VERSION 5.8 ;
BUSBITCHARS "[]" ;
DIVIDERCHAR "/" ;
UNITS
    DATABASE MICRONS 1000 ;
END UNITS

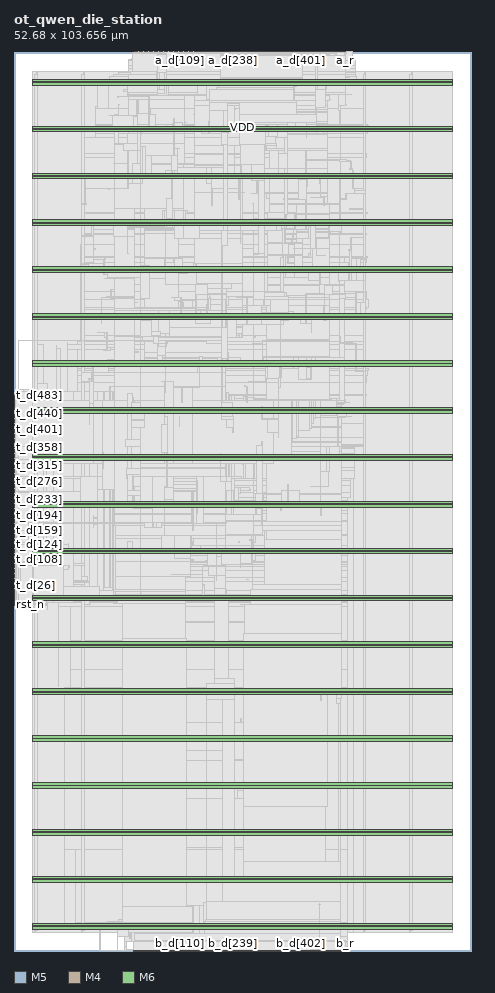
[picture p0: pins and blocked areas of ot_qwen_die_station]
MACRO ot_qwen_die_station
  FOREIGN ot_qwen_die_station 0 0 ;
  CLASS BLOCK ;
  SIZE 52.68 BY 103.656 ;
  PIN a_d[0]
    DIRECTION INPUT ;
    USE SIGNAL ;
    PORT
      LAYER M5 ;
        RECT  13.824 103.572 13.848 103.656 ;
    END
  END a_d[0]
  PIN a_d[100]
    DIRECTION INPUT ;
    USE SIGNAL ;
    PORT
      LAYER M5 ;
        RECT  18.624 103.572 18.648 103.656 ;
    END
  END a_d[100]
  PIN a_d[101]
    DIRECTION INPUT ;
    USE SIGNAL ;
    PORT
      LAYER M5 ;
        RECT  18.672 103.572 18.696 103.656 ;
    END
  END a_d[101]
  PIN a_d[102]
    DIRECTION INPUT ;
    USE SIGNAL ;
    PORT
      LAYER M5 ;
        RECT  18.72 103.572 18.744 103.656 ;
    END
  END a_d[102]
  PIN a_d[103]
    DIRECTION INPUT ;
    USE SIGNAL ;
    PORT
      LAYER M5 ;
        RECT  18.768 103.572 18.792 103.656 ;
    END
  END a_d[103]
  PIN a_d[104]
    DIRECTION INPUT ;
    USE SIGNAL ;
    PORT
      LAYER M5 ;
        RECT  18.816 103.572 18.84 103.656 ;
    END
  END a_d[104]
  PIN a_d[105]
    DIRECTION INPUT ;
    USE SIGNAL ;
    PORT
      LAYER M5 ;
        RECT  18.864 103.572 18.888 103.656 ;
    END
  END a_d[105]
  PIN a_d[106]
    DIRECTION INPUT ;
    USE SIGNAL ;
    PORT
      LAYER M5 ;
        RECT  18.912 103.572 18.936 103.656 ;
    END
  END a_d[106]
  PIN a_d[107]
    DIRECTION INPUT ;
    USE SIGNAL ;
    PORT
      LAYER M5 ;
        RECT  18.96 103.572 18.984 103.656 ;
    END
  END a_d[107]
  PIN a_d[108]
    DIRECTION INPUT ;
    USE SIGNAL ;
    PORT
      LAYER M5 ;
        RECT  19.008 103.572 19.032 103.656 ;
    END
  END a_d[108]
  PIN a_d[109]
    DIRECTION INPUT ;
    USE SIGNAL ;
    PORT
      LAYER M5 ;
        RECT  19.056 103.572 19.08 103.656 ;
    END
  END a_d[109]
  PIN a_d[10]
    DIRECTION INPUT ;
    USE SIGNAL ;
    PORT
      LAYER M5 ;
        RECT  14.304 103.572 14.328 103.656 ;
    END
  END a_d[10]
  PIN a_d[110]
    DIRECTION INPUT ;
    USE SIGNAL ;
    PORT
      LAYER M5 ;
        RECT  19.104 103.572 19.128 103.656 ;
    END
  END a_d[110]
  PIN a_d[111]
    DIRECTION INPUT ;
    USE SIGNAL ;
    PORT
      LAYER M5 ;
        RECT  19.152 103.572 19.176 103.656 ;
    END
  END a_d[111]
  PIN a_d[112]
    DIRECTION INPUT ;
    USE SIGNAL ;
    PORT
      LAYER M5 ;
        RECT  19.2 103.572 19.224 103.656 ;
    END
  END a_d[112]
  PIN a_d[113]
    DIRECTION INPUT ;
    USE SIGNAL ;
    PORT
      LAYER M5 ;
        RECT  19.248 103.572 19.272 103.656 ;
    END
  END a_d[113]
  PIN a_d[114]
    DIRECTION INPUT ;
    USE SIGNAL ;
    PORT
      LAYER M5 ;
        RECT  19.296 103.572 19.32 103.656 ;
    END
  END a_d[114]
  PIN a_d[115]
    DIRECTION INPUT ;
    USE SIGNAL ;
    PORT
      LAYER M5 ;
        RECT  19.344 103.572 19.368 103.656 ;
    END
  END a_d[115]
  PIN a_d[116]
    DIRECTION INPUT ;
    USE SIGNAL ;
    PORT
      LAYER M5 ;
        RECT  19.392 103.572 19.416 103.656 ;
    END
  END a_d[116]
  PIN a_d[117]
    DIRECTION INPUT ;
    USE SIGNAL ;
    PORT
      LAYER M5 ;
        RECT  19.44 103.572 19.464 103.656 ;
    END
  END a_d[117]
  PIN a_d[118]
    DIRECTION INPUT ;
    USE SIGNAL ;
    PORT
      LAYER M5 ;
        RECT  19.488 103.572 19.512 103.656 ;
    END
  END a_d[118]
  PIN a_d[119]
    DIRECTION INPUT ;
    USE SIGNAL ;
    PORT
      LAYER M5 ;
        RECT  19.536 103.572 19.56 103.656 ;
    END
  END a_d[119]
  PIN a_d[11]
    DIRECTION INPUT ;
    USE SIGNAL ;
    PORT
      LAYER M5 ;
        RECT  14.352 103.572 14.376 103.656 ;
    END
  END a_d[11]
  PIN a_d[120]
    DIRECTION INPUT ;
    USE SIGNAL ;
    PORT
      LAYER M5 ;
        RECT  19.584 103.572 19.608 103.656 ;
    END
  END a_d[120]
  PIN a_d[121]
    DIRECTION INPUT ;
    USE SIGNAL ;
    PORT
      LAYER M5 ;
        RECT  19.632 103.572 19.656 103.656 ;
    END
  END a_d[121]
  PIN a_d[122]
    DIRECTION INPUT ;
    USE SIGNAL ;
    PORT
      LAYER M5 ;
        RECT  19.68 103.572 19.704 103.656 ;
    END
  END a_d[122]
  PIN a_d[123]
    DIRECTION INPUT ;
    USE SIGNAL ;
    PORT
      LAYER M5 ;
        RECT  19.728 103.572 19.752 103.656 ;
    END
  END a_d[123]
  PIN a_d[124]
    DIRECTION INPUT ;
    USE SIGNAL ;
    PORT
      LAYER M5 ;
        RECT  19.776 103.572 19.8 103.656 ;
    END
  END a_d[124]
  PIN a_d[125]
    DIRECTION INPUT ;
    USE SIGNAL ;
    PORT
      LAYER M5 ;
        RECT  19.824 103.572 19.848 103.656 ;
    END
  END a_d[125]
  PIN a_d[126]
    DIRECTION INPUT ;
    USE SIGNAL ;
    PORT
      LAYER M5 ;
        RECT  19.872 103.572 19.896 103.656 ;
    END
  END a_d[126]
  PIN a_d[127]
    DIRECTION INPUT ;
    USE SIGNAL ;
    PORT
      LAYER M5 ;
        RECT  19.92 103.572 19.944 103.656 ;
    END
  END a_d[127]
  PIN a_d[128]
    DIRECTION INPUT ;
    USE SIGNAL ;
    PORT
      LAYER M5 ;
        RECT  19.968 103.572 19.992 103.656 ;
    END
  END a_d[128]
  PIN a_d[129]
    DIRECTION INPUT ;
    USE SIGNAL ;
    PORT
      LAYER M5 ;
        RECT  20.016 103.572 20.04 103.656 ;
    END
  END a_d[129]
  PIN a_d[12]
    DIRECTION INPUT ;
    USE SIGNAL ;
    PORT
      LAYER M5 ;
        RECT  14.4 103.572 14.424 103.656 ;
    END
  END a_d[12]
  PIN a_d[130]
    DIRECTION INPUT ;
    USE SIGNAL ;
    PORT
      LAYER M5 ;
        RECT  20.064 103.572 20.088 103.656 ;
    END
  END a_d[130]
  PIN a_d[131]
    DIRECTION INPUT ;
    USE SIGNAL ;
    PORT
      LAYER M5 ;
        RECT  20.112 103.572 20.136 103.656 ;
    END
  END a_d[131]
  PIN a_d[132]
    DIRECTION INPUT ;
    USE SIGNAL ;
    PORT
      LAYER M5 ;
        RECT  20.16 103.572 20.184 103.656 ;
    END
  END a_d[132]
  PIN a_d[133]
    DIRECTION INPUT ;
    USE SIGNAL ;
    PORT
      LAYER M5 ;
        RECT  20.208 103.572 20.232 103.656 ;
    END
  END a_d[133]
  PIN a_d[134]
    DIRECTION INPUT ;
    USE SIGNAL ;
    PORT
      LAYER M5 ;
        RECT  20.256 103.572 20.28 103.656 ;
    END
  END a_d[134]
  PIN a_d[135]
    DIRECTION INPUT ;
    USE SIGNAL ;
    PORT
      LAYER M5 ;
        RECT  20.304 103.572 20.328 103.656 ;
    END
  END a_d[135]
  PIN a_d[136]
    DIRECTION INPUT ;
    USE SIGNAL ;
    PORT
      LAYER M5 ;
        RECT  20.352 103.572 20.376 103.656 ;
    END
  END a_d[136]
  PIN a_d[137]
    DIRECTION INPUT ;
    USE SIGNAL ;
    PORT
      LAYER M5 ;
        RECT  20.4 103.572 20.424 103.656 ;
    END
  END a_d[137]
  PIN a_d[138]
    DIRECTION INPUT ;
    USE SIGNAL ;
    PORT
      LAYER M5 ;
        RECT  20.448 103.572 20.472 103.656 ;
    END
  END a_d[138]
  PIN a_d[139]
    DIRECTION INPUT ;
    USE SIGNAL ;
    PORT
      LAYER M5 ;
        RECT  20.496 103.572 20.52 103.656 ;
    END
  END a_d[139]
  PIN a_d[13]
    DIRECTION INPUT ;
    USE SIGNAL ;
    PORT
      LAYER M5 ;
        RECT  14.448 103.572 14.472 103.656 ;
    END
  END a_d[13]
  PIN a_d[140]
    DIRECTION INPUT ;
    USE SIGNAL ;
    PORT
      LAYER M5 ;
        RECT  20.544 103.572 20.568 103.656 ;
    END
  END a_d[140]
  PIN a_d[141]
    DIRECTION INPUT ;
    USE SIGNAL ;
    PORT
      LAYER M5 ;
        RECT  20.592 103.572 20.616 103.656 ;
    END
  END a_d[141]
  PIN a_d[142]
    DIRECTION INPUT ;
    USE SIGNAL ;
    PORT
      LAYER M5 ;
        RECT  20.64 103.572 20.664 103.656 ;
    END
  END a_d[142]
  PIN a_d[143]
    DIRECTION INPUT ;
    USE SIGNAL ;
    PORT
      LAYER M5 ;
        RECT  20.688 103.572 20.712 103.656 ;
    END
  END a_d[143]
  PIN a_d[144]
    DIRECTION INPUT ;
    USE SIGNAL ;
    PORT
      LAYER M5 ;
        RECT  20.736 103.572 20.76 103.656 ;
    END
  END a_d[144]
  PIN a_d[145]
    DIRECTION INPUT ;
    USE SIGNAL ;
    PORT
      LAYER M5 ;
        RECT  20.784 103.572 20.808 103.656 ;
    END
  END a_d[145]
  PIN a_d[146]
    DIRECTION INPUT ;
    USE SIGNAL ;
    PORT
      LAYER M5 ;
        RECT  20.832 103.572 20.856 103.656 ;
    END
  END a_d[146]
  PIN a_d[147]
    DIRECTION INPUT ;
    USE SIGNAL ;
    PORT
      LAYER M5 ;
        RECT  20.88 103.572 20.904 103.656 ;
    END
  END a_d[147]
  PIN a_d[148]
    DIRECTION INPUT ;
    USE SIGNAL ;
    PORT
      LAYER M5 ;
        RECT  20.928 103.572 20.952 103.656 ;
    END
  END a_d[148]
  PIN a_d[149]
    DIRECTION INPUT ;
    USE SIGNAL ;
    PORT
      LAYER M5 ;
        RECT  20.976 103.572 21 103.656 ;
    END
  END a_d[149]
  PIN a_d[14]
    DIRECTION INPUT ;
    USE SIGNAL ;
    PORT
      LAYER M5 ;
        RECT  14.496 103.572 14.52 103.656 ;
    END
  END a_d[14]
  PIN a_d[150]
    DIRECTION INPUT ;
    USE SIGNAL ;
    PORT
      LAYER M5 ;
        RECT  21.024 103.572 21.048 103.656 ;
    END
  END a_d[150]
  PIN a_d[151]
    DIRECTION INPUT ;
    USE SIGNAL ;
    PORT
      LAYER M5 ;
        RECT  21.072 103.572 21.096 103.656 ;
    END
  END a_d[151]
  PIN a_d[152]
    DIRECTION INPUT ;
    USE SIGNAL ;
    PORT
      LAYER M5 ;
        RECT  21.12 103.572 21.144 103.656 ;
    END
  END a_d[152]
  PIN a_d[153]
    DIRECTION INPUT ;
    USE SIGNAL ;
    PORT
      LAYER M5 ;
        RECT  21.168 103.572 21.192 103.656 ;
    END
  END a_d[153]
  PIN a_d[154]
    DIRECTION INPUT ;
    USE SIGNAL ;
    PORT
      LAYER M5 ;
        RECT  21.216 103.572 21.24 103.656 ;
    END
  END a_d[154]
  PIN a_d[155]
    DIRECTION INPUT ;
    USE SIGNAL ;
    PORT
      LAYER M5 ;
        RECT  21.264 103.572 21.288 103.656 ;
    END
  END a_d[155]
  PIN a_d[156]
    DIRECTION INPUT ;
    USE SIGNAL ;
    PORT
      LAYER M5 ;
        RECT  21.312 103.572 21.336 103.656 ;
    END
  END a_d[156]
  PIN a_d[157]
    DIRECTION INPUT ;
    USE SIGNAL ;
    PORT
      LAYER M5 ;
        RECT  21.36 103.572 21.384 103.656 ;
    END
  END a_d[157]
  PIN a_d[158]
    DIRECTION INPUT ;
    USE SIGNAL ;
    PORT
      LAYER M5 ;
        RECT  21.408 103.572 21.432 103.656 ;
    END
  END a_d[158]
  PIN a_d[159]
    DIRECTION INPUT ;
    USE SIGNAL ;
    PORT
      LAYER M5 ;
        RECT  21.456 103.572 21.48 103.656 ;
    END
  END a_d[159]
  PIN a_d[15]
    DIRECTION INPUT ;
    USE SIGNAL ;
    PORT
      LAYER M5 ;
        RECT  14.544 103.572 14.568 103.656 ;
    END
  END a_d[15]
  PIN a_d[160]
    DIRECTION INPUT ;
    USE SIGNAL ;
    PORT
      LAYER M5 ;
        RECT  21.504 103.572 21.528 103.656 ;
    END
  END a_d[160]
  PIN a_d[161]
    DIRECTION INPUT ;
    USE SIGNAL ;
    PORT
      LAYER M5 ;
        RECT  21.552 103.572 21.576 103.656 ;
    END
  END a_d[161]
  PIN a_d[162]
    DIRECTION INPUT ;
    USE SIGNAL ;
    PORT
      LAYER M5 ;
        RECT  21.6 103.572 21.624 103.656 ;
    END
  END a_d[162]
  PIN a_d[163]
    DIRECTION INPUT ;
    USE SIGNAL ;
    PORT
      LAYER M5 ;
        RECT  21.648 103.572 21.672 103.656 ;
    END
  END a_d[163]
  PIN a_d[164]
    DIRECTION INPUT ;
    USE SIGNAL ;
    PORT
      LAYER M5 ;
        RECT  21.696 103.572 21.72 103.656 ;
    END
  END a_d[164]
  PIN a_d[165]
    DIRECTION INPUT ;
    USE SIGNAL ;
    PORT
      LAYER M5 ;
        RECT  21.744 103.572 21.768 103.656 ;
    END
  END a_d[165]
  PIN a_d[166]
    DIRECTION INPUT ;
    USE SIGNAL ;
    PORT
      LAYER M5 ;
        RECT  21.792 103.572 21.816 103.656 ;
    END
  END a_d[166]
  PIN a_d[167]
    DIRECTION INPUT ;
    USE SIGNAL ;
    PORT
      LAYER M5 ;
        RECT  21.84 103.572 21.864 103.656 ;
    END
  END a_d[167]
  PIN a_d[168]
    DIRECTION INPUT ;
    USE SIGNAL ;
    PORT
      LAYER M5 ;
        RECT  21.888 103.572 21.912 103.656 ;
    END
  END a_d[168]
  PIN a_d[169]
    DIRECTION INPUT ;
    USE SIGNAL ;
    PORT
      LAYER M5 ;
        RECT  21.936 103.572 21.96 103.656 ;
    END
  END a_d[169]
  PIN a_d[16]
    DIRECTION INPUT ;
    USE SIGNAL ;
    PORT
      LAYER M5 ;
        RECT  14.592 103.572 14.616 103.656 ;
    END
  END a_d[16]
  PIN a_d[170]
    DIRECTION INPUT ;
    USE SIGNAL ;
    PORT
      LAYER M5 ;
        RECT  21.984 103.572 22.008 103.656 ;
    END
  END a_d[170]
  PIN a_d[171]
    DIRECTION INPUT ;
    USE SIGNAL ;
    PORT
      LAYER M5 ;
        RECT  22.032 103.572 22.056 103.656 ;
    END
  END a_d[171]
  PIN a_d[172]
    DIRECTION INPUT ;
    USE SIGNAL ;
    PORT
      LAYER M5 ;
        RECT  22.08 103.572 22.104 103.656 ;
    END
  END a_d[172]
  PIN a_d[173]
    DIRECTION INPUT ;
    USE SIGNAL ;
    PORT
      LAYER M5 ;
        RECT  22.128 103.572 22.152 103.656 ;
    END
  END a_d[173]
  PIN a_d[174]
    DIRECTION INPUT ;
    USE SIGNAL ;
    PORT
      LAYER M5 ;
        RECT  22.176 103.572 22.2 103.656 ;
    END
  END a_d[174]
  PIN a_d[175]
    DIRECTION INPUT ;
    USE SIGNAL ;
    PORT
      LAYER M5 ;
        RECT  22.224 103.572 22.248 103.656 ;
    END
  END a_d[175]
  PIN a_d[176]
    DIRECTION INPUT ;
    USE SIGNAL ;
    PORT
      LAYER M5 ;
        RECT  22.272 103.572 22.296 103.656 ;
    END
  END a_d[176]
  PIN a_d[177]
    DIRECTION INPUT ;
    USE SIGNAL ;
    PORT
      LAYER M5 ;
        RECT  22.32 103.572 22.344 103.656 ;
    END
  END a_d[177]
  PIN a_d[178]
    DIRECTION INPUT ;
    USE SIGNAL ;
    PORT
      LAYER M5 ;
        RECT  22.368 103.572 22.392 103.656 ;
    END
  END a_d[178]
  PIN a_d[179]
    DIRECTION INPUT ;
    USE SIGNAL ;
    PORT
      LAYER M5 ;
        RECT  22.416 103.572 22.44 103.656 ;
    END
  END a_d[179]
  PIN a_d[17]
    DIRECTION INPUT ;
    USE SIGNAL ;
    PORT
      LAYER M5 ;
        RECT  14.64 103.572 14.664 103.656 ;
    END
  END a_d[17]
  PIN a_d[180]
    DIRECTION INPUT ;
    USE SIGNAL ;
    PORT
      LAYER M5 ;
        RECT  22.464 103.572 22.488 103.656 ;
    END
  END a_d[180]
  PIN a_d[181]
    DIRECTION INPUT ;
    USE SIGNAL ;
    PORT
      LAYER M5 ;
        RECT  22.512 103.572 22.536 103.656 ;
    END
  END a_d[181]
  PIN a_d[182]
    DIRECTION INPUT ;
    USE SIGNAL ;
    PORT
      LAYER M5 ;
        RECT  22.56 103.572 22.584 103.656 ;
    END
  END a_d[182]
  PIN a_d[183]
    DIRECTION INPUT ;
    USE SIGNAL ;
    PORT
      LAYER M5 ;
        RECT  22.608 103.572 22.632 103.656 ;
    END
  END a_d[183]
  PIN a_d[184]
    DIRECTION INPUT ;
    USE SIGNAL ;
    PORT
      LAYER M5 ;
        RECT  22.656 103.572 22.68 103.656 ;
    END
  END a_d[184]
  PIN a_d[185]
    DIRECTION INPUT ;
    USE SIGNAL ;
    PORT
      LAYER M5 ;
        RECT  22.704 103.572 22.728 103.656 ;
    END
  END a_d[185]
  PIN a_d[186]
    DIRECTION INPUT ;
    USE SIGNAL ;
    PORT
      LAYER M5 ;
        RECT  22.752 103.572 22.776 103.656 ;
    END
  END a_d[186]
  PIN a_d[187]
    DIRECTION INPUT ;
    USE SIGNAL ;
    PORT
      LAYER M5 ;
        RECT  22.8 103.572 22.824 103.656 ;
    END
  END a_d[187]
  PIN a_d[188]
    DIRECTION INPUT ;
    USE SIGNAL ;
    PORT
      LAYER M5 ;
        RECT  22.848 103.572 22.872 103.656 ;
    END
  END a_d[188]
  PIN a_d[189]
    DIRECTION INPUT ;
    USE SIGNAL ;
    PORT
      LAYER M5 ;
        RECT  22.896 103.572 22.92 103.656 ;
    END
  END a_d[189]
  PIN a_d[18]
    DIRECTION INPUT ;
    USE SIGNAL ;
    PORT
      LAYER M5 ;
        RECT  14.688 103.572 14.712 103.656 ;
    END
  END a_d[18]
  PIN a_d[190]
    DIRECTION INPUT ;
    USE SIGNAL ;
    PORT
      LAYER M5 ;
        RECT  22.944 103.572 22.968 103.656 ;
    END
  END a_d[190]
  PIN a_d[191]
    DIRECTION INPUT ;
    USE SIGNAL ;
    PORT
      LAYER M5 ;
        RECT  22.992 103.572 23.016 103.656 ;
    END
  END a_d[191]
  PIN a_d[192]
    DIRECTION INPUT ;
    USE SIGNAL ;
    PORT
      LAYER M5 ;
        RECT  23.04 103.572 23.064 103.656 ;
    END
  END a_d[192]
  PIN a_d[193]
    DIRECTION INPUT ;
    USE SIGNAL ;
    PORT
      LAYER M5 ;
        RECT  23.088 103.572 23.112 103.656 ;
    END
  END a_d[193]
  PIN a_d[194]
    DIRECTION INPUT ;
    USE SIGNAL ;
    PORT
      LAYER M5 ;
        RECT  23.136 103.572 23.16 103.656 ;
    END
  END a_d[194]
  PIN a_d[195]
    DIRECTION INPUT ;
    USE SIGNAL ;
    PORT
      LAYER M5 ;
        RECT  23.184 103.572 23.208 103.656 ;
    END
  END a_d[195]
  PIN a_d[196]
    DIRECTION INPUT ;
    USE SIGNAL ;
    PORT
      LAYER M5 ;
        RECT  23.232 103.572 23.256 103.656 ;
    END
  END a_d[196]
  PIN a_d[197]
    DIRECTION INPUT ;
    USE SIGNAL ;
    PORT
      LAYER M5 ;
        RECT  23.28 103.572 23.304 103.656 ;
    END
  END a_d[197]
  PIN a_d[198]
    DIRECTION INPUT ;
    USE SIGNAL ;
    PORT
      LAYER M5 ;
        RECT  23.328 103.572 23.352 103.656 ;
    END
  END a_d[198]
  PIN a_d[199]
    DIRECTION INPUT ;
    USE SIGNAL ;
    PORT
      LAYER M5 ;
        RECT  23.376 103.572 23.4 103.656 ;
    END
  END a_d[199]
  PIN a_d[19]
    DIRECTION INPUT ;
    USE SIGNAL ;
    PORT
      LAYER M5 ;
        RECT  14.736 103.572 14.76 103.656 ;
    END
  END a_d[19]
  PIN a_d[1]
    DIRECTION INPUT ;
    USE SIGNAL ;
    PORT
      LAYER M5 ;
        RECT  13.872 103.572 13.896 103.656 ;
    END
  END a_d[1]
  PIN a_d[200]
    DIRECTION INPUT ;
    USE SIGNAL ;
    PORT
      LAYER M5 ;
        RECT  23.424 103.572 23.448 103.656 ;
    END
  END a_d[200]
  PIN a_d[201]
    DIRECTION INPUT ;
    USE SIGNAL ;
    PORT
      LAYER M5 ;
        RECT  23.472 103.572 23.496 103.656 ;
    END
  END a_d[201]
  PIN a_d[202]
    DIRECTION INPUT ;
    USE SIGNAL ;
    PORT
      LAYER M5 ;
        RECT  23.52 103.572 23.544 103.656 ;
    END
  END a_d[202]
  PIN a_d[203]
    DIRECTION INPUT ;
    USE SIGNAL ;
    PORT
      LAYER M5 ;
        RECT  23.568 103.572 23.592 103.656 ;
    END
  END a_d[203]
  PIN a_d[204]
    DIRECTION INPUT ;
    USE SIGNAL ;
    PORT
      LAYER M5 ;
        RECT  23.616 103.572 23.64 103.656 ;
    END
  END a_d[204]
  PIN a_d[205]
    DIRECTION INPUT ;
    USE SIGNAL ;
    PORT
      LAYER M5 ;
        RECT  23.664 103.572 23.688 103.656 ;
    END
  END a_d[205]
  PIN a_d[206]
    DIRECTION INPUT ;
    USE SIGNAL ;
    PORT
      LAYER M5 ;
        RECT  23.712 103.572 23.736 103.656 ;
    END
  END a_d[206]
  PIN a_d[207]
    DIRECTION INPUT ;
    USE SIGNAL ;
    PORT
      LAYER M5 ;
        RECT  23.76 103.572 23.784 103.656 ;
    END
  END a_d[207]
  PIN a_d[208]
    DIRECTION INPUT ;
    USE SIGNAL ;
    PORT
      LAYER M5 ;
        RECT  23.808 103.572 23.832 103.656 ;
    END
  END a_d[208]
  PIN a_d[209]
    DIRECTION INPUT ;
    USE SIGNAL ;
    PORT
      LAYER M5 ;
        RECT  23.856 103.572 23.88 103.656 ;
    END
  END a_d[209]
  PIN a_d[20]
    DIRECTION INPUT ;
    USE SIGNAL ;
    PORT
      LAYER M5 ;
        RECT  14.784 103.572 14.808 103.656 ;
    END
  END a_d[20]
  PIN a_d[210]
    DIRECTION INPUT ;
    USE SIGNAL ;
    PORT
      LAYER M5 ;
        RECT  23.904 103.572 23.928 103.656 ;
    END
  END a_d[210]
  PIN a_d[211]
    DIRECTION INPUT ;
    USE SIGNAL ;
    PORT
      LAYER M5 ;
        RECT  23.952 103.572 23.976 103.656 ;
    END
  END a_d[211]
  PIN a_d[212]
    DIRECTION INPUT ;
    USE SIGNAL ;
    PORT
      LAYER M5 ;
        RECT  24 103.572 24.024 103.656 ;
    END
  END a_d[212]
  PIN a_d[213]
    DIRECTION INPUT ;
    USE SIGNAL ;
    PORT
      LAYER M5 ;
        RECT  24.048 103.572 24.072 103.656 ;
    END
  END a_d[213]
  PIN a_d[214]
    DIRECTION INPUT ;
    USE SIGNAL ;
    PORT
      LAYER M5 ;
        RECT  24.096 103.572 24.12 103.656 ;
    END
  END a_d[214]
  PIN a_d[215]
    DIRECTION INPUT ;
    USE SIGNAL ;
    PORT
      LAYER M5 ;
        RECT  24.144 103.572 24.168 103.656 ;
    END
  END a_d[215]
  PIN a_d[216]
    DIRECTION INPUT ;
    USE SIGNAL ;
    PORT
      LAYER M5 ;
        RECT  24.192 103.572 24.216 103.656 ;
    END
  END a_d[216]
  PIN a_d[217]
    DIRECTION INPUT ;
    USE SIGNAL ;
    PORT
      LAYER M5 ;
        RECT  24.24 103.572 24.264 103.656 ;
    END
  END a_d[217]
  PIN a_d[218]
    DIRECTION INPUT ;
    USE SIGNAL ;
    PORT
      LAYER M5 ;
        RECT  24.288 103.572 24.312 103.656 ;
    END
  END a_d[218]
  PIN a_d[219]
    DIRECTION INPUT ;
    USE SIGNAL ;
    PORT
      LAYER M5 ;
        RECT  24.336 103.572 24.36 103.656 ;
    END
  END a_d[219]
  PIN a_d[21]
    DIRECTION INPUT ;
    USE SIGNAL ;
    PORT
      LAYER M5 ;
        RECT  14.832 103.572 14.856 103.656 ;
    END
  END a_d[21]
  PIN a_d[220]
    DIRECTION INPUT ;
    USE SIGNAL ;
    PORT
      LAYER M5 ;
        RECT  24.384 103.572 24.408 103.656 ;
    END
  END a_d[220]
  PIN a_d[221]
    DIRECTION INPUT ;
    USE SIGNAL ;
    PORT
      LAYER M5 ;
        RECT  24.432 103.572 24.456 103.656 ;
    END
  END a_d[221]
  PIN a_d[222]
    DIRECTION INPUT ;
    USE SIGNAL ;
    PORT
      LAYER M5 ;
        RECT  24.48 103.572 24.504 103.656 ;
    END
  END a_d[222]
  PIN a_d[223]
    DIRECTION INPUT ;
    USE SIGNAL ;
    PORT
      LAYER M5 ;
        RECT  24.528 103.572 24.552 103.656 ;
    END
  END a_d[223]
  PIN a_d[224]
    DIRECTION INPUT ;
    USE SIGNAL ;
    PORT
      LAYER M5 ;
        RECT  24.576 103.572 24.6 103.656 ;
    END
  END a_d[224]
  PIN a_d[225]
    DIRECTION INPUT ;
    USE SIGNAL ;
    PORT
      LAYER M5 ;
        RECT  24.624 103.572 24.648 103.656 ;
    END
  END a_d[225]
  PIN a_d[226]
    DIRECTION INPUT ;
    USE SIGNAL ;
    PORT
      LAYER M5 ;
        RECT  24.672 103.572 24.696 103.656 ;
    END
  END a_d[226]
  PIN a_d[227]
    DIRECTION INPUT ;
    USE SIGNAL ;
    PORT
      LAYER M5 ;
        RECT  24.72 103.572 24.744 103.656 ;
    END
  END a_d[227]
  PIN a_d[228]
    DIRECTION INPUT ;
    USE SIGNAL ;
    PORT
      LAYER M5 ;
        RECT  24.768 103.572 24.792 103.656 ;
    END
  END a_d[228]
  PIN a_d[229]
    DIRECTION INPUT ;
    USE SIGNAL ;
    PORT
      LAYER M5 ;
        RECT  24.816 103.572 24.84 103.656 ;
    END
  END a_d[229]
  PIN a_d[22]
    DIRECTION INPUT ;
    USE SIGNAL ;
    PORT
      LAYER M5 ;
        RECT  14.88 103.572 14.904 103.656 ;
    END
  END a_d[22]
  PIN a_d[230]
    DIRECTION INPUT ;
    USE SIGNAL ;
    PORT
      LAYER M5 ;
        RECT  24.864 103.572 24.888 103.656 ;
    END
  END a_d[230]
  PIN a_d[231]
    DIRECTION INPUT ;
    USE SIGNAL ;
    PORT
      LAYER M5 ;
        RECT  24.912 103.572 24.936 103.656 ;
    END
  END a_d[231]
  PIN a_d[232]
    DIRECTION INPUT ;
    USE SIGNAL ;
    PORT
      LAYER M5 ;
        RECT  24.96 103.572 24.984 103.656 ;
    END
  END a_d[232]
  PIN a_d[233]
    DIRECTION INPUT ;
    USE SIGNAL ;
    PORT
      LAYER M5 ;
        RECT  25.008 103.572 25.032 103.656 ;
    END
  END a_d[233]
  PIN a_d[234]
    DIRECTION INPUT ;
    USE SIGNAL ;
    PORT
      LAYER M5 ;
        RECT  25.056 103.572 25.08 103.656 ;
    END
  END a_d[234]
  PIN a_d[235]
    DIRECTION INPUT ;
    USE SIGNAL ;
    PORT
      LAYER M5 ;
        RECT  25.104 103.572 25.128 103.656 ;
    END
  END a_d[235]
  PIN a_d[236]
    DIRECTION INPUT ;
    USE SIGNAL ;
    PORT
      LAYER M5 ;
        RECT  25.152 103.572 25.176 103.656 ;
    END
  END a_d[236]
  PIN a_d[237]
    DIRECTION INPUT ;
    USE SIGNAL ;
    PORT
      LAYER M5 ;
        RECT  25.2 103.572 25.224 103.656 ;
    END
  END a_d[237]
  PIN a_d[238]
    DIRECTION INPUT ;
    USE SIGNAL ;
    PORT
      LAYER M5 ;
        RECT  25.248 103.572 25.272 103.656 ;
    END
  END a_d[238]
  PIN a_d[239]
    DIRECTION INPUT ;
    USE SIGNAL ;
    PORT
      LAYER M5 ;
        RECT  25.296 103.572 25.32 103.656 ;
    END
  END a_d[239]
  PIN a_d[23]
    DIRECTION INPUT ;
    USE SIGNAL ;
    PORT
      LAYER M5 ;
        RECT  14.928 103.572 14.952 103.656 ;
    END
  END a_d[23]
  PIN a_d[240]
    DIRECTION INPUT ;
    USE SIGNAL ;
    PORT
      LAYER M5 ;
        RECT  25.344 103.572 25.368 103.656 ;
    END
  END a_d[240]
  PIN a_d[241]
    DIRECTION INPUT ;
    USE SIGNAL ;
    PORT
      LAYER M5 ;
        RECT  25.392 103.572 25.416 103.656 ;
    END
  END a_d[241]
  PIN a_d[242]
    DIRECTION INPUT ;
    USE SIGNAL ;
    PORT
      LAYER M5 ;
        RECT  25.44 103.572 25.464 103.656 ;
    END
  END a_d[242]
  PIN a_d[243]
    DIRECTION INPUT ;
    USE SIGNAL ;
    PORT
      LAYER M5 ;
        RECT  25.488 103.572 25.512 103.656 ;
    END
  END a_d[243]
  PIN a_d[244]
    DIRECTION INPUT ;
    USE SIGNAL ;
    PORT
      LAYER M5 ;
        RECT  25.536 103.572 25.56 103.656 ;
    END
  END a_d[244]
  PIN a_d[245]
    DIRECTION INPUT ;
    USE SIGNAL ;
    PORT
      LAYER M5 ;
        RECT  25.584 103.572 25.608 103.656 ;
    END
  END a_d[245]
  PIN a_d[246]
    DIRECTION INPUT ;
    USE SIGNAL ;
    PORT
      LAYER M5 ;
        RECT  25.632 103.572 25.656 103.656 ;
    END
  END a_d[246]
  PIN a_d[247]
    DIRECTION INPUT ;
    USE SIGNAL ;
    PORT
      LAYER M5 ;
        RECT  25.68 103.572 25.704 103.656 ;
    END
  END a_d[247]
  PIN a_d[248]
    DIRECTION INPUT ;
    USE SIGNAL ;
    PORT
      LAYER M5 ;
        RECT  25.728 103.572 25.752 103.656 ;
    END
  END a_d[248]
  PIN a_d[249]
    DIRECTION INPUT ;
    USE SIGNAL ;
    PORT
      LAYER M5 ;
        RECT  25.776 103.572 25.8 103.656 ;
    END
  END a_d[249]
  PIN a_d[24]
    DIRECTION INPUT ;
    USE SIGNAL ;
    PORT
      LAYER M5 ;
        RECT  14.976 103.572 15 103.656 ;
    END
  END a_d[24]
  PIN a_d[250]
    DIRECTION INPUT ;
    USE SIGNAL ;
    PORT
      LAYER M5 ;
        RECT  25.824 103.572 25.848 103.656 ;
    END
  END a_d[250]
  PIN a_d[251]
    DIRECTION INPUT ;
    USE SIGNAL ;
    PORT
      LAYER M5 ;
        RECT  25.872 103.572 25.896 103.656 ;
    END
  END a_d[251]
  PIN a_d[252]
    DIRECTION INPUT ;
    USE SIGNAL ;
    PORT
      LAYER M5 ;
        RECT  25.92 103.572 25.944 103.656 ;
    END
  END a_d[252]
  PIN a_d[253]
    DIRECTION INPUT ;
    USE SIGNAL ;
    PORT
      LAYER M5 ;
        RECT  25.968 103.572 25.992 103.656 ;
    END
  END a_d[253]
  PIN a_d[254]
    DIRECTION INPUT ;
    USE SIGNAL ;
    PORT
      LAYER M5 ;
        RECT  26.016 103.572 26.04 103.656 ;
    END
  END a_d[254]
  PIN a_d[255]
    DIRECTION INPUT ;
    USE SIGNAL ;
    PORT
      LAYER M5 ;
        RECT  26.064 103.572 26.088 103.656 ;
    END
  END a_d[255]
  PIN a_d[256]
    DIRECTION INPUT ;
    USE SIGNAL ;
    PORT
      LAYER M5 ;
        RECT  26.112 103.572 26.136 103.656 ;
    END
  END a_d[256]
  PIN a_d[257]
    DIRECTION INPUT ;
    USE SIGNAL ;
    PORT
      LAYER M5 ;
        RECT  26.16 103.572 26.184 103.656 ;
    END
  END a_d[257]
  PIN a_d[258]
    DIRECTION INPUT ;
    USE SIGNAL ;
    PORT
      LAYER M5 ;
        RECT  26.208 103.572 26.232 103.656 ;
    END
  END a_d[258]
  PIN a_d[259]
    DIRECTION INPUT ;
    USE SIGNAL ;
    PORT
      LAYER M5 ;
        RECT  26.256 103.572 26.28 103.656 ;
    END
  END a_d[259]
  PIN a_d[25]
    DIRECTION INPUT ;
    USE SIGNAL ;
    PORT
      LAYER M5 ;
        RECT  15.024 103.572 15.048 103.656 ;
    END
  END a_d[25]
  PIN a_d[260]
    DIRECTION INPUT ;
    USE SIGNAL ;
    PORT
      LAYER M5 ;
        RECT  26.304 103.572 26.328 103.656 ;
    END
  END a_d[260]
  PIN a_d[261]
    DIRECTION INPUT ;
    USE SIGNAL ;
    PORT
      LAYER M5 ;
        RECT  26.352 103.572 26.376 103.656 ;
    END
  END a_d[261]
  PIN a_d[262]
    DIRECTION INPUT ;
    USE SIGNAL ;
    PORT
      LAYER M5 ;
        RECT  26.4 103.572 26.424 103.656 ;
    END
  END a_d[262]
  PIN a_d[263]
    DIRECTION INPUT ;
    USE SIGNAL ;
    PORT
      LAYER M5 ;
        RECT  26.448 103.572 26.472 103.656 ;
    END
  END a_d[263]
  PIN a_d[264]
    DIRECTION INPUT ;
    USE SIGNAL ;
    PORT
      LAYER M5 ;
        RECT  26.496 103.572 26.52 103.656 ;
    END
  END a_d[264]
  PIN a_d[265]
    DIRECTION INPUT ;
    USE SIGNAL ;
    PORT
      LAYER M5 ;
        RECT  26.544 103.572 26.568 103.656 ;
    END
  END a_d[265]
  PIN a_d[266]
    DIRECTION INPUT ;
    USE SIGNAL ;
    PORT
      LAYER M5 ;
        RECT  26.592 103.572 26.616 103.656 ;
    END
  END a_d[266]
  PIN a_d[267]
    DIRECTION INPUT ;
    USE SIGNAL ;
    PORT
      LAYER M5 ;
        RECT  26.64 103.572 26.664 103.656 ;
    END
  END a_d[267]
  PIN a_d[268]
    DIRECTION INPUT ;
    USE SIGNAL ;
    PORT
      LAYER M5 ;
        RECT  26.688 103.572 26.712 103.656 ;
    END
  END a_d[268]
  PIN a_d[269]
    DIRECTION INPUT ;
    USE SIGNAL ;
    PORT
      LAYER M5 ;
        RECT  26.736 103.572 26.76 103.656 ;
    END
  END a_d[269]
  PIN a_d[26]
    DIRECTION INPUT ;
    USE SIGNAL ;
    PORT
      LAYER M5 ;
        RECT  15.072 103.572 15.096 103.656 ;
    END
  END a_d[26]
  PIN a_d[270]
    DIRECTION INPUT ;
    USE SIGNAL ;
    PORT
      LAYER M5 ;
        RECT  26.784 103.572 26.808 103.656 ;
    END
  END a_d[270]
  PIN a_d[271]
    DIRECTION INPUT ;
    USE SIGNAL ;
    PORT
      LAYER M5 ;
        RECT  26.832 103.572 26.856 103.656 ;
    END
  END a_d[271]
  PIN a_d[272]
    DIRECTION INPUT ;
    USE SIGNAL ;
    PORT
      LAYER M5 ;
        RECT  26.88 103.572 26.904 103.656 ;
    END
  END a_d[272]
  PIN a_d[273]
    DIRECTION INPUT ;
    USE SIGNAL ;
    PORT
      LAYER M5 ;
        RECT  26.928 103.572 26.952 103.656 ;
    END
  END a_d[273]
  PIN a_d[274]
    DIRECTION INPUT ;
    USE SIGNAL ;
    PORT
      LAYER M5 ;
        RECT  26.976 103.572 27 103.656 ;
    END
  END a_d[274]
  PIN a_d[275]
    DIRECTION INPUT ;
    USE SIGNAL ;
    PORT
      LAYER M5 ;
        RECT  27.024 103.572 27.048 103.656 ;
    END
  END a_d[275]
  PIN a_d[276]
    DIRECTION INPUT ;
    USE SIGNAL ;
    PORT
      LAYER M5 ;
        RECT  27.072 103.572 27.096 103.656 ;
    END
  END a_d[276]
  PIN a_d[277]
    DIRECTION INPUT ;
    USE SIGNAL ;
    PORT
      LAYER M5 ;
        RECT  27.12 103.572 27.144 103.656 ;
    END
  END a_d[277]
  PIN a_d[278]
    DIRECTION INPUT ;
    USE SIGNAL ;
    PORT
      LAYER M5 ;
        RECT  27.168 103.572 27.192 103.656 ;
    END
  END a_d[278]
  PIN a_d[279]
    DIRECTION INPUT ;
    USE SIGNAL ;
    PORT
      LAYER M5 ;
        RECT  27.216 103.572 27.24 103.656 ;
    END
  END a_d[279]
  PIN a_d[27]
    DIRECTION INPUT ;
    USE SIGNAL ;
    PORT
      LAYER M5 ;
        RECT  15.12 103.572 15.144 103.656 ;
    END
  END a_d[27]
  PIN a_d[280]
    DIRECTION INPUT ;
    USE SIGNAL ;
    PORT
      LAYER M5 ;
        RECT  27.264 103.572 27.288 103.656 ;
    END
  END a_d[280]
  PIN a_d[281]
    DIRECTION INPUT ;
    USE SIGNAL ;
    PORT
      LAYER M5 ;
        RECT  27.312 103.572 27.336 103.656 ;
    END
  END a_d[281]
  PIN a_d[282]
    DIRECTION INPUT ;
    USE SIGNAL ;
    PORT
      LAYER M5 ;
        RECT  27.36 103.572 27.384 103.656 ;
    END
  END a_d[282]
  PIN a_d[283]
    DIRECTION INPUT ;
    USE SIGNAL ;
    PORT
      LAYER M5 ;
        RECT  27.408 103.572 27.432 103.656 ;
    END
  END a_d[283]
  PIN a_d[284]
    DIRECTION INPUT ;
    USE SIGNAL ;
    PORT
      LAYER M5 ;
        RECT  27.456 103.572 27.48 103.656 ;
    END
  END a_d[284]
  PIN a_d[285]
    DIRECTION INPUT ;
    USE SIGNAL ;
    PORT
      LAYER M5 ;
        RECT  27.504 103.572 27.528 103.656 ;
    END
  END a_d[285]
  PIN a_d[286]
    DIRECTION INPUT ;
    USE SIGNAL ;
    PORT
      LAYER M5 ;
        RECT  27.552 103.572 27.576 103.656 ;
    END
  END a_d[286]
  PIN a_d[287]
    DIRECTION INPUT ;
    USE SIGNAL ;
    PORT
      LAYER M5 ;
        RECT  27.6 103.572 27.624 103.656 ;
    END
  END a_d[287]
  PIN a_d[288]
    DIRECTION INPUT ;
    USE SIGNAL ;
    PORT
      LAYER M5 ;
        RECT  27.648 103.572 27.672 103.656 ;
    END
  END a_d[288]
  PIN a_d[289]
    DIRECTION INPUT ;
    USE SIGNAL ;
    PORT
      LAYER M5 ;
        RECT  27.696 103.572 27.72 103.656 ;
    END
  END a_d[289]
  PIN a_d[28]
    DIRECTION INPUT ;
    USE SIGNAL ;
    PORT
      LAYER M5 ;
        RECT  15.168 103.572 15.192 103.656 ;
    END
  END a_d[28]
  PIN a_d[290]
    DIRECTION INPUT ;
    USE SIGNAL ;
    PORT
      LAYER M5 ;
        RECT  27.744 103.572 27.768 103.656 ;
    END
  END a_d[290]
  PIN a_d[291]
    DIRECTION INPUT ;
    USE SIGNAL ;
    PORT
      LAYER M5 ;
        RECT  27.792 103.572 27.816 103.656 ;
    END
  END a_d[291]
  PIN a_d[292]
    DIRECTION INPUT ;
    USE SIGNAL ;
    PORT
      LAYER M5 ;
        RECT  27.84 103.572 27.864 103.656 ;
    END
  END a_d[292]
  PIN a_d[293]
    DIRECTION INPUT ;
    USE SIGNAL ;
    PORT
      LAYER M5 ;
        RECT  27.888 103.572 27.912 103.656 ;
    END
  END a_d[293]
  PIN a_d[294]
    DIRECTION INPUT ;
    USE SIGNAL ;
    PORT
      LAYER M5 ;
        RECT  27.936 103.572 27.96 103.656 ;
    END
  END a_d[294]
  PIN a_d[295]
    DIRECTION INPUT ;
    USE SIGNAL ;
    PORT
      LAYER M5 ;
        RECT  27.984 103.572 28.008 103.656 ;
    END
  END a_d[295]
  PIN a_d[296]
    DIRECTION INPUT ;
    USE SIGNAL ;
    PORT
      LAYER M5 ;
        RECT  28.032 103.572 28.056 103.656 ;
    END
  END a_d[296]
  PIN a_d[297]
    DIRECTION INPUT ;
    USE SIGNAL ;
    PORT
      LAYER M5 ;
        RECT  28.08 103.572 28.104 103.656 ;
    END
  END a_d[297]
  PIN a_d[298]
    DIRECTION INPUT ;
    USE SIGNAL ;
    PORT
      LAYER M5 ;
        RECT  28.128 103.572 28.152 103.656 ;
    END
  END a_d[298]
  PIN a_d[299]
    DIRECTION INPUT ;
    USE SIGNAL ;
    PORT
      LAYER M5 ;
        RECT  28.176 103.572 28.2 103.656 ;
    END
  END a_d[299]
  PIN a_d[29]
    DIRECTION INPUT ;
    USE SIGNAL ;
    PORT
      LAYER M5 ;
        RECT  15.216 103.572 15.24 103.656 ;
    END
  END a_d[29]
  PIN a_d[2]
    DIRECTION INPUT ;
    USE SIGNAL ;
    PORT
      LAYER M5 ;
        RECT  13.92 103.572 13.944 103.656 ;
    END
  END a_d[2]
  PIN a_d[300]
    DIRECTION INPUT ;
    USE SIGNAL ;
    PORT
      LAYER M5 ;
        RECT  28.224 103.572 28.248 103.656 ;
    END
  END a_d[300]
  PIN a_d[301]
    DIRECTION INPUT ;
    USE SIGNAL ;
    PORT
      LAYER M5 ;
        RECT  28.272 103.572 28.296 103.656 ;
    END
  END a_d[301]
  PIN a_d[302]
    DIRECTION INPUT ;
    USE SIGNAL ;
    PORT
      LAYER M5 ;
        RECT  28.32 103.572 28.344 103.656 ;
    END
  END a_d[302]
  PIN a_d[303]
    DIRECTION INPUT ;
    USE SIGNAL ;
    PORT
      LAYER M5 ;
        RECT  28.368 103.572 28.392 103.656 ;
    END
  END a_d[303]
  PIN a_d[304]
    DIRECTION INPUT ;
    USE SIGNAL ;
    PORT
      LAYER M5 ;
        RECT  28.416 103.572 28.44 103.656 ;
    END
  END a_d[304]
  PIN a_d[305]
    DIRECTION INPUT ;
    USE SIGNAL ;
    PORT
      LAYER M5 ;
        RECT  28.464 103.572 28.488 103.656 ;
    END
  END a_d[305]
  PIN a_d[306]
    DIRECTION INPUT ;
    USE SIGNAL ;
    PORT
      LAYER M5 ;
        RECT  28.512 103.572 28.536 103.656 ;
    END
  END a_d[306]
  PIN a_d[307]
    DIRECTION INPUT ;
    USE SIGNAL ;
    PORT
      LAYER M5 ;
        RECT  28.56 103.572 28.584 103.656 ;
    END
  END a_d[307]
  PIN a_d[308]
    DIRECTION INPUT ;
    USE SIGNAL ;
    PORT
      LAYER M5 ;
        RECT  28.608 103.572 28.632 103.656 ;
    END
  END a_d[308]
  PIN a_d[309]
    DIRECTION INPUT ;
    USE SIGNAL ;
    PORT
      LAYER M5 ;
        RECT  28.656 103.572 28.68 103.656 ;
    END
  END a_d[309]
  PIN a_d[30]
    DIRECTION INPUT ;
    USE SIGNAL ;
    PORT
      LAYER M5 ;
        RECT  15.264 103.572 15.288 103.656 ;
    END
  END a_d[30]
  PIN a_d[310]
    DIRECTION INPUT ;
    USE SIGNAL ;
    PORT
      LAYER M5 ;
        RECT  28.704 103.572 28.728 103.656 ;
    END
  END a_d[310]
  PIN a_d[311]
    DIRECTION INPUT ;
    USE SIGNAL ;
    PORT
      LAYER M5 ;
        RECT  28.752 103.572 28.776 103.656 ;
    END
  END a_d[311]
  PIN a_d[312]
    DIRECTION INPUT ;
    USE SIGNAL ;
    PORT
      LAYER M5 ;
        RECT  28.8 103.572 28.824 103.656 ;
    END
  END a_d[312]
  PIN a_d[313]
    DIRECTION INPUT ;
    USE SIGNAL ;
    PORT
      LAYER M5 ;
        RECT  28.848 103.572 28.872 103.656 ;
    END
  END a_d[313]
  PIN a_d[314]
    DIRECTION INPUT ;
    USE SIGNAL ;
    PORT
      LAYER M5 ;
        RECT  28.896 103.572 28.92 103.656 ;
    END
  END a_d[314]
  PIN a_d[315]
    DIRECTION INPUT ;
    USE SIGNAL ;
    PORT
      LAYER M5 ;
        RECT  28.944 103.572 28.968 103.656 ;
    END
  END a_d[315]
  PIN a_d[316]
    DIRECTION INPUT ;
    USE SIGNAL ;
    PORT
      LAYER M5 ;
        RECT  28.992 103.572 29.016 103.656 ;
    END
  END a_d[316]
  PIN a_d[317]
    DIRECTION INPUT ;
    USE SIGNAL ;
    PORT
      LAYER M5 ;
        RECT  29.04 103.572 29.064 103.656 ;
    END
  END a_d[317]
  PIN a_d[318]
    DIRECTION INPUT ;
    USE SIGNAL ;
    PORT
      LAYER M5 ;
        RECT  29.088 103.572 29.112 103.656 ;
    END
  END a_d[318]
  PIN a_d[319]
    DIRECTION INPUT ;
    USE SIGNAL ;
    PORT
      LAYER M5 ;
        RECT  29.136 103.572 29.16 103.656 ;
    END
  END a_d[319]
  PIN a_d[31]
    DIRECTION INPUT ;
    USE SIGNAL ;
    PORT
      LAYER M5 ;
        RECT  15.312 103.572 15.336 103.656 ;
    END
  END a_d[31]
  PIN a_d[320]
    DIRECTION INPUT ;
    USE SIGNAL ;
    PORT
      LAYER M5 ;
        RECT  29.184 103.572 29.208 103.656 ;
    END
  END a_d[320]
  PIN a_d[321]
    DIRECTION INPUT ;
    USE SIGNAL ;
    PORT
      LAYER M5 ;
        RECT  29.232 103.572 29.256 103.656 ;
    END
  END a_d[321]
  PIN a_d[322]
    DIRECTION INPUT ;
    USE SIGNAL ;
    PORT
      LAYER M5 ;
        RECT  29.28 103.572 29.304 103.656 ;
    END
  END a_d[322]
  PIN a_d[323]
    DIRECTION INPUT ;
    USE SIGNAL ;
    PORT
      LAYER M5 ;
        RECT  29.328 103.572 29.352 103.656 ;
    END
  END a_d[323]
  PIN a_d[324]
    DIRECTION INPUT ;
    USE SIGNAL ;
    PORT
      LAYER M5 ;
        RECT  29.376 103.572 29.4 103.656 ;
    END
  END a_d[324]
  PIN a_d[325]
    DIRECTION INPUT ;
    USE SIGNAL ;
    PORT
      LAYER M5 ;
        RECT  29.424 103.572 29.448 103.656 ;
    END
  END a_d[325]
  PIN a_d[326]
    DIRECTION INPUT ;
    USE SIGNAL ;
    PORT
      LAYER M5 ;
        RECT  29.472 103.572 29.496 103.656 ;
    END
  END a_d[326]
  PIN a_d[327]
    DIRECTION INPUT ;
    USE SIGNAL ;
    PORT
      LAYER M5 ;
        RECT  29.52 103.572 29.544 103.656 ;
    END
  END a_d[327]
  PIN a_d[328]
    DIRECTION INPUT ;
    USE SIGNAL ;
    PORT
      LAYER M5 ;
        RECT  29.568 103.572 29.592 103.656 ;
    END
  END a_d[328]
  PIN a_d[329]
    DIRECTION INPUT ;
    USE SIGNAL ;
    PORT
      LAYER M5 ;
        RECT  29.616 103.572 29.64 103.656 ;
    END
  END a_d[329]
  PIN a_d[32]
    DIRECTION INPUT ;
    USE SIGNAL ;
    PORT
      LAYER M5 ;
        RECT  15.36 103.572 15.384 103.656 ;
    END
  END a_d[32]
  PIN a_d[330]
    DIRECTION INPUT ;
    USE SIGNAL ;
    PORT
      LAYER M5 ;
        RECT  29.664 103.572 29.688 103.656 ;
    END
  END a_d[330]
  PIN a_d[331]
    DIRECTION INPUT ;
    USE SIGNAL ;
    PORT
      LAYER M5 ;
        RECT  29.712 103.572 29.736 103.656 ;
    END
  END a_d[331]
  PIN a_d[332]
    DIRECTION INPUT ;
    USE SIGNAL ;
    PORT
      LAYER M5 ;
        RECT  29.76 103.572 29.784 103.656 ;
    END
  END a_d[332]
  PIN a_d[333]
    DIRECTION INPUT ;
    USE SIGNAL ;
    PORT
      LAYER M5 ;
        RECT  29.808 103.572 29.832 103.656 ;
    END
  END a_d[333]
  PIN a_d[334]
    DIRECTION INPUT ;
    USE SIGNAL ;
    PORT
      LAYER M5 ;
        RECT  29.856 103.572 29.88 103.656 ;
    END
  END a_d[334]
  PIN a_d[335]
    DIRECTION INPUT ;
    USE SIGNAL ;
    PORT
      LAYER M5 ;
        RECT  29.904 103.572 29.928 103.656 ;
    END
  END a_d[335]
  PIN a_d[336]
    DIRECTION INPUT ;
    USE SIGNAL ;
    PORT
      LAYER M5 ;
        RECT  29.952 103.572 29.976 103.656 ;
    END
  END a_d[336]
  PIN a_d[337]
    DIRECTION INPUT ;
    USE SIGNAL ;
    PORT
      LAYER M5 ;
        RECT  30 103.572 30.024 103.656 ;
    END
  END a_d[337]
  PIN a_d[338]
    DIRECTION INPUT ;
    USE SIGNAL ;
    PORT
      LAYER M5 ;
        RECT  30.048 103.572 30.072 103.656 ;
    END
  END a_d[338]
  PIN a_d[339]
    DIRECTION INPUT ;
    USE SIGNAL ;
    PORT
      LAYER M5 ;
        RECT  30.096 103.572 30.12 103.656 ;
    END
  END a_d[339]
  PIN a_d[33]
    DIRECTION INPUT ;
    USE SIGNAL ;
    PORT
      LAYER M5 ;
        RECT  15.408 103.572 15.432 103.656 ;
    END
  END a_d[33]
  PIN a_d[340]
    DIRECTION INPUT ;
    USE SIGNAL ;
    PORT
      LAYER M5 ;
        RECT  30.144 103.572 30.168 103.656 ;
    END
  END a_d[340]
  PIN a_d[341]
    DIRECTION INPUT ;
    USE SIGNAL ;
    PORT
      LAYER M5 ;
        RECT  30.192 103.572 30.216 103.656 ;
    END
  END a_d[341]
  PIN a_d[342]
    DIRECTION INPUT ;
    USE SIGNAL ;
    PORT
      LAYER M5 ;
        RECT  30.24 103.572 30.264 103.656 ;
    END
  END a_d[342]
  PIN a_d[343]
    DIRECTION INPUT ;
    USE SIGNAL ;
    PORT
      LAYER M5 ;
        RECT  30.288 103.572 30.312 103.656 ;
    END
  END a_d[343]
  PIN a_d[344]
    DIRECTION INPUT ;
    USE SIGNAL ;
    PORT
      LAYER M5 ;
        RECT  30.336 103.572 30.36 103.656 ;
    END
  END a_d[344]
  PIN a_d[345]
    DIRECTION INPUT ;
    USE SIGNAL ;
    PORT
      LAYER M5 ;
        RECT  30.384 103.572 30.408 103.656 ;
    END
  END a_d[345]
  PIN a_d[346]
    DIRECTION INPUT ;
    USE SIGNAL ;
    PORT
      LAYER M5 ;
        RECT  30.432 103.572 30.456 103.656 ;
    END
  END a_d[346]
  PIN a_d[347]
    DIRECTION INPUT ;
    USE SIGNAL ;
    PORT
      LAYER M5 ;
        RECT  30.48 103.572 30.504 103.656 ;
    END
  END a_d[347]
  PIN a_d[348]
    DIRECTION INPUT ;
    USE SIGNAL ;
    PORT
      LAYER M5 ;
        RECT  30.528 103.572 30.552 103.656 ;
    END
  END a_d[348]
  PIN a_d[349]
    DIRECTION INPUT ;
    USE SIGNAL ;
    PORT
      LAYER M5 ;
        RECT  30.576 103.572 30.6 103.656 ;
    END
  END a_d[349]
  PIN a_d[34]
    DIRECTION INPUT ;
    USE SIGNAL ;
    PORT
      LAYER M5 ;
        RECT  15.456 103.572 15.48 103.656 ;
    END
  END a_d[34]
  PIN a_d[350]
    DIRECTION INPUT ;
    USE SIGNAL ;
    PORT
      LAYER M5 ;
        RECT  30.624 103.572 30.648 103.656 ;
    END
  END a_d[350]
  PIN a_d[351]
    DIRECTION INPUT ;
    USE SIGNAL ;
    PORT
      LAYER M5 ;
        RECT  30.672 103.572 30.696 103.656 ;
    END
  END a_d[351]
  PIN a_d[352]
    DIRECTION INPUT ;
    USE SIGNAL ;
    PORT
      LAYER M5 ;
        RECT  30.72 103.572 30.744 103.656 ;
    END
  END a_d[352]
  PIN a_d[353]
    DIRECTION INPUT ;
    USE SIGNAL ;
    PORT
      LAYER M5 ;
        RECT  30.768 103.572 30.792 103.656 ;
    END
  END a_d[353]
  PIN a_d[354]
    DIRECTION INPUT ;
    USE SIGNAL ;
    PORT
      LAYER M5 ;
        RECT  30.816 103.572 30.84 103.656 ;
    END
  END a_d[354]
  PIN a_d[355]
    DIRECTION INPUT ;
    USE SIGNAL ;
    PORT
      LAYER M5 ;
        RECT  30.864 103.572 30.888 103.656 ;
    END
  END a_d[355]
  PIN a_d[356]
    DIRECTION INPUT ;
    USE SIGNAL ;
    PORT
      LAYER M5 ;
        RECT  30.912 103.572 30.936 103.656 ;
    END
  END a_d[356]
  PIN a_d[357]
    DIRECTION INPUT ;
    USE SIGNAL ;
    PORT
      LAYER M5 ;
        RECT  30.96 103.572 30.984 103.656 ;
    END
  END a_d[357]
  PIN a_d[358]
    DIRECTION INPUT ;
    USE SIGNAL ;
    PORT
      LAYER M5 ;
        RECT  31.008 103.572 31.032 103.656 ;
    END
  END a_d[358]
  PIN a_d[359]
    DIRECTION INPUT ;
    USE SIGNAL ;
    PORT
      LAYER M5 ;
        RECT  31.056 103.572 31.08 103.656 ;
    END
  END a_d[359]
  PIN a_d[35]
    DIRECTION INPUT ;
    USE SIGNAL ;
    PORT
      LAYER M5 ;
        RECT  15.504 103.572 15.528 103.656 ;
    END
  END a_d[35]
  PIN a_d[360]
    DIRECTION INPUT ;
    USE SIGNAL ;
    PORT
      LAYER M5 ;
        RECT  31.104 103.572 31.128 103.656 ;
    END
  END a_d[360]
  PIN a_d[361]
    DIRECTION INPUT ;
    USE SIGNAL ;
    PORT
      LAYER M5 ;
        RECT  31.152 103.572 31.176 103.656 ;
    END
  END a_d[361]
  PIN a_d[362]
    DIRECTION INPUT ;
    USE SIGNAL ;
    PORT
      LAYER M5 ;
        RECT  31.2 103.572 31.224 103.656 ;
    END
  END a_d[362]
  PIN a_d[363]
    DIRECTION INPUT ;
    USE SIGNAL ;
    PORT
      LAYER M5 ;
        RECT  31.248 103.572 31.272 103.656 ;
    END
  END a_d[363]
  PIN a_d[364]
    DIRECTION INPUT ;
    USE SIGNAL ;
    PORT
      LAYER M5 ;
        RECT  31.296 103.572 31.32 103.656 ;
    END
  END a_d[364]
  PIN a_d[365]
    DIRECTION INPUT ;
    USE SIGNAL ;
    PORT
      LAYER M5 ;
        RECT  31.344 103.572 31.368 103.656 ;
    END
  END a_d[365]
  PIN a_d[366]
    DIRECTION INPUT ;
    USE SIGNAL ;
    PORT
      LAYER M5 ;
        RECT  31.392 103.572 31.416 103.656 ;
    END
  END a_d[366]
  PIN a_d[367]
    DIRECTION INPUT ;
    USE SIGNAL ;
    PORT
      LAYER M5 ;
        RECT  31.44 103.572 31.464 103.656 ;
    END
  END a_d[367]
  PIN a_d[368]
    DIRECTION INPUT ;
    USE SIGNAL ;
    PORT
      LAYER M5 ;
        RECT  31.488 103.572 31.512 103.656 ;
    END
  END a_d[368]
  PIN a_d[369]
    DIRECTION INPUT ;
    USE SIGNAL ;
    PORT
      LAYER M5 ;
        RECT  31.536 103.572 31.56 103.656 ;
    END
  END a_d[369]
  PIN a_d[36]
    DIRECTION INPUT ;
    USE SIGNAL ;
    PORT
      LAYER M5 ;
        RECT  15.552 103.572 15.576 103.656 ;
    END
  END a_d[36]
  PIN a_d[370]
    DIRECTION INPUT ;
    USE SIGNAL ;
    PORT
      LAYER M5 ;
        RECT  31.584 103.572 31.608 103.656 ;
    END
  END a_d[370]
  PIN a_d[371]
    DIRECTION INPUT ;
    USE SIGNAL ;
    PORT
      LAYER M5 ;
        RECT  31.632 103.572 31.656 103.656 ;
    END
  END a_d[371]
  PIN a_d[372]
    DIRECTION INPUT ;
    USE SIGNAL ;
    PORT
      LAYER M5 ;
        RECT  31.68 103.572 31.704 103.656 ;
    END
  END a_d[372]
  PIN a_d[373]
    DIRECTION INPUT ;
    USE SIGNAL ;
    PORT
      LAYER M5 ;
        RECT  31.728 103.572 31.752 103.656 ;
    END
  END a_d[373]
  PIN a_d[374]
    DIRECTION INPUT ;
    USE SIGNAL ;
    PORT
      LAYER M5 ;
        RECT  31.776 103.572 31.8 103.656 ;
    END
  END a_d[374]
  PIN a_d[375]
    DIRECTION INPUT ;
    USE SIGNAL ;
    PORT
      LAYER M5 ;
        RECT  31.824 103.572 31.848 103.656 ;
    END
  END a_d[375]
  PIN a_d[376]
    DIRECTION INPUT ;
    USE SIGNAL ;
    PORT
      LAYER M5 ;
        RECT  31.872 103.572 31.896 103.656 ;
    END
  END a_d[376]
  PIN a_d[377]
    DIRECTION INPUT ;
    USE SIGNAL ;
    PORT
      LAYER M5 ;
        RECT  31.92 103.572 31.944 103.656 ;
    END
  END a_d[377]
  PIN a_d[378]
    DIRECTION INPUT ;
    USE SIGNAL ;
    PORT
      LAYER M5 ;
        RECT  31.968 103.572 31.992 103.656 ;
    END
  END a_d[378]
  PIN a_d[379]
    DIRECTION INPUT ;
    USE SIGNAL ;
    PORT
      LAYER M5 ;
        RECT  32.016 103.572 32.04 103.656 ;
    END
  END a_d[379]
  PIN a_d[37]
    DIRECTION INPUT ;
    USE SIGNAL ;
    PORT
      LAYER M5 ;
        RECT  15.6 103.572 15.624 103.656 ;
    END
  END a_d[37]
  PIN a_d[380]
    DIRECTION INPUT ;
    USE SIGNAL ;
    PORT
      LAYER M5 ;
        RECT  32.064 103.572 32.088 103.656 ;
    END
  END a_d[380]
  PIN a_d[381]
    DIRECTION INPUT ;
    USE SIGNAL ;
    PORT
      LAYER M5 ;
        RECT  32.112 103.572 32.136 103.656 ;
    END
  END a_d[381]
  PIN a_d[382]
    DIRECTION INPUT ;
    USE SIGNAL ;
    PORT
      LAYER M5 ;
        RECT  32.16 103.572 32.184 103.656 ;
    END
  END a_d[382]
  PIN a_d[383]
    DIRECTION INPUT ;
    USE SIGNAL ;
    PORT
      LAYER M5 ;
        RECT  32.208 103.572 32.232 103.656 ;
    END
  END a_d[383]
  PIN a_d[384]
    DIRECTION INPUT ;
    USE SIGNAL ;
    PORT
      LAYER M5 ;
        RECT  32.256 103.572 32.28 103.656 ;
    END
  END a_d[384]
  PIN a_d[385]
    DIRECTION INPUT ;
    USE SIGNAL ;
    PORT
      LAYER M5 ;
        RECT  32.304 103.572 32.328 103.656 ;
    END
  END a_d[385]
  PIN a_d[386]
    DIRECTION INPUT ;
    USE SIGNAL ;
    PORT
      LAYER M5 ;
        RECT  32.352 103.572 32.376 103.656 ;
    END
  END a_d[386]
  PIN a_d[387]
    DIRECTION INPUT ;
    USE SIGNAL ;
    PORT
      LAYER M5 ;
        RECT  32.4 103.572 32.424 103.656 ;
    END
  END a_d[387]
  PIN a_d[388]
    DIRECTION INPUT ;
    USE SIGNAL ;
    PORT
      LAYER M5 ;
        RECT  32.448 103.572 32.472 103.656 ;
    END
  END a_d[388]
  PIN a_d[389]
    DIRECTION INPUT ;
    USE SIGNAL ;
    PORT
      LAYER M5 ;
        RECT  32.496 103.572 32.52 103.656 ;
    END
  END a_d[389]
  PIN a_d[38]
    DIRECTION INPUT ;
    USE SIGNAL ;
    PORT
      LAYER M5 ;
        RECT  15.648 103.572 15.672 103.656 ;
    END
  END a_d[38]
  PIN a_d[390]
    DIRECTION INPUT ;
    USE SIGNAL ;
    PORT
      LAYER M5 ;
        RECT  32.544 103.572 32.568 103.656 ;
    END
  END a_d[390]
  PIN a_d[391]
    DIRECTION INPUT ;
    USE SIGNAL ;
    PORT
      LAYER M5 ;
        RECT  32.592 103.572 32.616 103.656 ;
    END
  END a_d[391]
  PIN a_d[392]
    DIRECTION INPUT ;
    USE SIGNAL ;
    PORT
      LAYER M5 ;
        RECT  32.64 103.572 32.664 103.656 ;
    END
  END a_d[392]
  PIN a_d[393]
    DIRECTION INPUT ;
    USE SIGNAL ;
    PORT
      LAYER M5 ;
        RECT  32.688 103.572 32.712 103.656 ;
    END
  END a_d[393]
  PIN a_d[394]
    DIRECTION INPUT ;
    USE SIGNAL ;
    PORT
      LAYER M5 ;
        RECT  32.736 103.572 32.76 103.656 ;
    END
  END a_d[394]
  PIN a_d[395]
    DIRECTION INPUT ;
    USE SIGNAL ;
    PORT
      LAYER M5 ;
        RECT  32.784 103.572 32.808 103.656 ;
    END
  END a_d[395]
  PIN a_d[396]
    DIRECTION INPUT ;
    USE SIGNAL ;
    PORT
      LAYER M5 ;
        RECT  32.832 103.572 32.856 103.656 ;
    END
  END a_d[396]
  PIN a_d[397]
    DIRECTION INPUT ;
    USE SIGNAL ;
    PORT
      LAYER M5 ;
        RECT  32.88 103.572 32.904 103.656 ;
    END
  END a_d[397]
  PIN a_d[398]
    DIRECTION INPUT ;
    USE SIGNAL ;
    PORT
      LAYER M5 ;
        RECT  32.928 103.572 32.952 103.656 ;
    END
  END a_d[398]
  PIN a_d[399]
    DIRECTION INPUT ;
    USE SIGNAL ;
    PORT
      LAYER M5 ;
        RECT  32.976 103.572 33 103.656 ;
    END
  END a_d[399]
  PIN a_d[39]
    DIRECTION INPUT ;
    USE SIGNAL ;
    PORT
      LAYER M5 ;
        RECT  15.696 103.572 15.72 103.656 ;
    END
  END a_d[39]
  PIN a_d[3]
    DIRECTION INPUT ;
    USE SIGNAL ;
    PORT
      LAYER M5 ;
        RECT  13.968 103.572 13.992 103.656 ;
    END
  END a_d[3]
  PIN a_d[400]
    DIRECTION INPUT ;
    USE SIGNAL ;
    PORT
      LAYER M5 ;
        RECT  33.024 103.572 33.048 103.656 ;
    END
  END a_d[400]
  PIN a_d[401]
    DIRECTION INPUT ;
    USE SIGNAL ;
    PORT
      LAYER M5 ;
        RECT  33.072 103.572 33.096 103.656 ;
    END
  END a_d[401]
  PIN a_d[402]
    DIRECTION INPUT ;
    USE SIGNAL ;
    PORT
      LAYER M5 ;
        RECT  33.12 103.572 33.144 103.656 ;
    END
  END a_d[402]
  PIN a_d[403]
    DIRECTION INPUT ;
    USE SIGNAL ;
    PORT
      LAYER M5 ;
        RECT  33.168 103.572 33.192 103.656 ;
    END
  END a_d[403]
  PIN a_d[404]
    DIRECTION INPUT ;
    USE SIGNAL ;
    PORT
      LAYER M5 ;
        RECT  33.216 103.572 33.24 103.656 ;
    END
  END a_d[404]
  PIN a_d[405]
    DIRECTION INPUT ;
    USE SIGNAL ;
    PORT
      LAYER M5 ;
        RECT  33.264 103.572 33.288 103.656 ;
    END
  END a_d[405]
  PIN a_d[406]
    DIRECTION INPUT ;
    USE SIGNAL ;
    PORT
      LAYER M5 ;
        RECT  33.312 103.572 33.336 103.656 ;
    END
  END a_d[406]
  PIN a_d[407]
    DIRECTION INPUT ;
    USE SIGNAL ;
    PORT
      LAYER M5 ;
        RECT  33.36 103.572 33.384 103.656 ;
    END
  END a_d[407]
  PIN a_d[408]
    DIRECTION INPUT ;
    USE SIGNAL ;
    PORT
      LAYER M5 ;
        RECT  33.408 103.572 33.432 103.656 ;
    END
  END a_d[408]
  PIN a_d[409]
    DIRECTION INPUT ;
    USE SIGNAL ;
    PORT
      LAYER M5 ;
        RECT  33.456 103.572 33.48 103.656 ;
    END
  END a_d[409]
  PIN a_d[40]
    DIRECTION INPUT ;
    USE SIGNAL ;
    PORT
      LAYER M5 ;
        RECT  15.744 103.572 15.768 103.656 ;
    END
  END a_d[40]
  PIN a_d[410]
    DIRECTION INPUT ;
    USE SIGNAL ;
    PORT
      LAYER M5 ;
        RECT  33.504 103.572 33.528 103.656 ;
    END
  END a_d[410]
  PIN a_d[411]
    DIRECTION INPUT ;
    USE SIGNAL ;
    PORT
      LAYER M5 ;
        RECT  33.552 103.572 33.576 103.656 ;
    END
  END a_d[411]
  PIN a_d[412]
    DIRECTION INPUT ;
    USE SIGNAL ;
    PORT
      LAYER M5 ;
        RECT  33.6 103.572 33.624 103.656 ;
    END
  END a_d[412]
  PIN a_d[413]
    DIRECTION INPUT ;
    USE SIGNAL ;
    PORT
      LAYER M5 ;
        RECT  33.648 103.572 33.672 103.656 ;
    END
  END a_d[413]
  PIN a_d[414]
    DIRECTION INPUT ;
    USE SIGNAL ;
    PORT
      LAYER M5 ;
        RECT  33.696 103.572 33.72 103.656 ;
    END
  END a_d[414]
  PIN a_d[415]
    DIRECTION INPUT ;
    USE SIGNAL ;
    PORT
      LAYER M5 ;
        RECT  33.744 103.572 33.768 103.656 ;
    END
  END a_d[415]
  PIN a_d[416]
    DIRECTION INPUT ;
    USE SIGNAL ;
    PORT
      LAYER M5 ;
        RECT  33.792 103.572 33.816 103.656 ;
    END
  END a_d[416]
  PIN a_d[417]
    DIRECTION INPUT ;
    USE SIGNAL ;
    PORT
      LAYER M5 ;
        RECT  33.84 103.572 33.864 103.656 ;
    END
  END a_d[417]
  PIN a_d[418]
    DIRECTION INPUT ;
    USE SIGNAL ;
    PORT
      LAYER M5 ;
        RECT  33.888 103.572 33.912 103.656 ;
    END
  END a_d[418]
  PIN a_d[419]
    DIRECTION INPUT ;
    USE SIGNAL ;
    PORT
      LAYER M5 ;
        RECT  33.936 103.572 33.96 103.656 ;
    END
  END a_d[419]
  PIN a_d[41]
    DIRECTION INPUT ;
    USE SIGNAL ;
    PORT
      LAYER M5 ;
        RECT  15.792 103.572 15.816 103.656 ;
    END
  END a_d[41]
  PIN a_d[420]
    DIRECTION INPUT ;
    USE SIGNAL ;
    PORT
      LAYER M5 ;
        RECT  33.984 103.572 34.008 103.656 ;
    END
  END a_d[420]
  PIN a_d[421]
    DIRECTION INPUT ;
    USE SIGNAL ;
    PORT
      LAYER M5 ;
        RECT  34.032 103.572 34.056 103.656 ;
    END
  END a_d[421]
  PIN a_d[422]
    DIRECTION INPUT ;
    USE SIGNAL ;
    PORT
      LAYER M5 ;
        RECT  34.08 103.572 34.104 103.656 ;
    END
  END a_d[422]
  PIN a_d[423]
    DIRECTION INPUT ;
    USE SIGNAL ;
    PORT
      LAYER M5 ;
        RECT  34.128 103.572 34.152 103.656 ;
    END
  END a_d[423]
  PIN a_d[424]
    DIRECTION INPUT ;
    USE SIGNAL ;
    PORT
      LAYER M5 ;
        RECT  34.176 103.572 34.2 103.656 ;
    END
  END a_d[424]
  PIN a_d[425]
    DIRECTION INPUT ;
    USE SIGNAL ;
    PORT
      LAYER M5 ;
        RECT  34.224 103.572 34.248 103.656 ;
    END
  END a_d[425]
  PIN a_d[426]
    DIRECTION INPUT ;
    USE SIGNAL ;
    PORT
      LAYER M5 ;
        RECT  34.272 103.572 34.296 103.656 ;
    END
  END a_d[426]
  PIN a_d[427]
    DIRECTION INPUT ;
    USE SIGNAL ;
    PORT
      LAYER M5 ;
        RECT  34.32 103.572 34.344 103.656 ;
    END
  END a_d[427]
  PIN a_d[428]
    DIRECTION INPUT ;
    USE SIGNAL ;
    PORT
      LAYER M5 ;
        RECT  34.368 103.572 34.392 103.656 ;
    END
  END a_d[428]
  PIN a_d[429]
    DIRECTION INPUT ;
    USE SIGNAL ;
    PORT
      LAYER M5 ;
        RECT  34.416 103.572 34.44 103.656 ;
    END
  END a_d[429]
  PIN a_d[42]
    DIRECTION INPUT ;
    USE SIGNAL ;
    PORT
      LAYER M5 ;
        RECT  15.84 103.572 15.864 103.656 ;
    END
  END a_d[42]
  PIN a_d[430]
    DIRECTION INPUT ;
    USE SIGNAL ;
    PORT
      LAYER M5 ;
        RECT  34.464 103.572 34.488 103.656 ;
    END
  END a_d[430]
  PIN a_d[431]
    DIRECTION INPUT ;
    USE SIGNAL ;
    PORT
      LAYER M5 ;
        RECT  34.512 103.572 34.536 103.656 ;
    END
  END a_d[431]
  PIN a_d[432]
    DIRECTION INPUT ;
    USE SIGNAL ;
    PORT
      LAYER M5 ;
        RECT  34.56 103.572 34.584 103.656 ;
    END
  END a_d[432]
  PIN a_d[433]
    DIRECTION INPUT ;
    USE SIGNAL ;
    PORT
      LAYER M5 ;
        RECT  34.608 103.572 34.632 103.656 ;
    END
  END a_d[433]
  PIN a_d[434]
    DIRECTION INPUT ;
    USE SIGNAL ;
    PORT
      LAYER M5 ;
        RECT  34.656 103.572 34.68 103.656 ;
    END
  END a_d[434]
  PIN a_d[435]
    DIRECTION INPUT ;
    USE SIGNAL ;
    PORT
      LAYER M5 ;
        RECT  34.704 103.572 34.728 103.656 ;
    END
  END a_d[435]
  PIN a_d[436]
    DIRECTION INPUT ;
    USE SIGNAL ;
    PORT
      LAYER M5 ;
        RECT  34.752 103.572 34.776 103.656 ;
    END
  END a_d[436]
  PIN a_d[437]
    DIRECTION INPUT ;
    USE SIGNAL ;
    PORT
      LAYER M5 ;
        RECT  34.8 103.572 34.824 103.656 ;
    END
  END a_d[437]
  PIN a_d[438]
    DIRECTION INPUT ;
    USE SIGNAL ;
    PORT
      LAYER M5 ;
        RECT  34.848 103.572 34.872 103.656 ;
    END
  END a_d[438]
  PIN a_d[439]
    DIRECTION INPUT ;
    USE SIGNAL ;
    PORT
      LAYER M5 ;
        RECT  34.896 103.572 34.92 103.656 ;
    END
  END a_d[439]
  PIN a_d[43]
    DIRECTION INPUT ;
    USE SIGNAL ;
    PORT
      LAYER M5 ;
        RECT  15.888 103.572 15.912 103.656 ;
    END
  END a_d[43]
  PIN a_d[440]
    DIRECTION INPUT ;
    USE SIGNAL ;
    PORT
      LAYER M5 ;
        RECT  34.944 103.572 34.968 103.656 ;
    END
  END a_d[440]
  PIN a_d[441]
    DIRECTION INPUT ;
    USE SIGNAL ;
    PORT
      LAYER M5 ;
        RECT  34.992 103.572 35.016 103.656 ;
    END
  END a_d[441]
  PIN a_d[442]
    DIRECTION INPUT ;
    USE SIGNAL ;
    PORT
      LAYER M5 ;
        RECT  35.04 103.572 35.064 103.656 ;
    END
  END a_d[442]
  PIN a_d[443]
    DIRECTION INPUT ;
    USE SIGNAL ;
    PORT
      LAYER M5 ;
        RECT  35.088 103.572 35.112 103.656 ;
    END
  END a_d[443]
  PIN a_d[444]
    DIRECTION INPUT ;
    USE SIGNAL ;
    PORT
      LAYER M5 ;
        RECT  35.136 103.572 35.16 103.656 ;
    END
  END a_d[444]
  PIN a_d[445]
    DIRECTION INPUT ;
    USE SIGNAL ;
    PORT
      LAYER M5 ;
        RECT  35.184 103.572 35.208 103.656 ;
    END
  END a_d[445]
  PIN a_d[446]
    DIRECTION INPUT ;
    USE SIGNAL ;
    PORT
      LAYER M5 ;
        RECT  35.232 103.572 35.256 103.656 ;
    END
  END a_d[446]
  PIN a_d[447]
    DIRECTION INPUT ;
    USE SIGNAL ;
    PORT
      LAYER M5 ;
        RECT  35.28 103.572 35.304 103.656 ;
    END
  END a_d[447]
  PIN a_d[448]
    DIRECTION INPUT ;
    USE SIGNAL ;
    PORT
      LAYER M5 ;
        RECT  35.328 103.572 35.352 103.656 ;
    END
  END a_d[448]
  PIN a_d[449]
    DIRECTION INPUT ;
    USE SIGNAL ;
    PORT
      LAYER M5 ;
        RECT  35.376 103.572 35.4 103.656 ;
    END
  END a_d[449]
  PIN a_d[44]
    DIRECTION INPUT ;
    USE SIGNAL ;
    PORT
      LAYER M5 ;
        RECT  15.936 103.572 15.96 103.656 ;
    END
  END a_d[44]
  PIN a_d[450]
    DIRECTION INPUT ;
    USE SIGNAL ;
    PORT
      LAYER M5 ;
        RECT  35.424 103.572 35.448 103.656 ;
    END
  END a_d[450]
  PIN a_d[451]
    DIRECTION INPUT ;
    USE SIGNAL ;
    PORT
      LAYER M5 ;
        RECT  35.472 103.572 35.496 103.656 ;
    END
  END a_d[451]
  PIN a_d[452]
    DIRECTION INPUT ;
    USE SIGNAL ;
    PORT
      LAYER M5 ;
        RECT  35.52 103.572 35.544 103.656 ;
    END
  END a_d[452]
  PIN a_d[453]
    DIRECTION INPUT ;
    USE SIGNAL ;
    PORT
      LAYER M5 ;
        RECT  35.568 103.572 35.592 103.656 ;
    END
  END a_d[453]
  PIN a_d[454]
    DIRECTION INPUT ;
    USE SIGNAL ;
    PORT
      LAYER M5 ;
        RECT  35.616 103.572 35.64 103.656 ;
    END
  END a_d[454]
  PIN a_d[455]
    DIRECTION INPUT ;
    USE SIGNAL ;
    PORT
      LAYER M5 ;
        RECT  35.664 103.572 35.688 103.656 ;
    END
  END a_d[455]
  PIN a_d[456]
    DIRECTION INPUT ;
    USE SIGNAL ;
    PORT
      LAYER M5 ;
        RECT  35.712 103.572 35.736 103.656 ;
    END
  END a_d[456]
  PIN a_d[457]
    DIRECTION INPUT ;
    USE SIGNAL ;
    PORT
      LAYER M5 ;
        RECT  35.76 103.572 35.784 103.656 ;
    END
  END a_d[457]
  PIN a_d[458]
    DIRECTION INPUT ;
    USE SIGNAL ;
    PORT
      LAYER M5 ;
        RECT  35.808 103.572 35.832 103.656 ;
    END
  END a_d[458]
  PIN a_d[459]
    DIRECTION INPUT ;
    USE SIGNAL ;
    PORT
      LAYER M5 ;
        RECT  35.856 103.572 35.88 103.656 ;
    END
  END a_d[459]
  PIN a_d[45]
    DIRECTION INPUT ;
    USE SIGNAL ;
    PORT
      LAYER M5 ;
        RECT  15.984 103.572 16.008 103.656 ;
    END
  END a_d[45]
  PIN a_d[460]
    DIRECTION INPUT ;
    USE SIGNAL ;
    PORT
      LAYER M5 ;
        RECT  35.904 103.572 35.928 103.656 ;
    END
  END a_d[460]
  PIN a_d[461]
    DIRECTION INPUT ;
    USE SIGNAL ;
    PORT
      LAYER M5 ;
        RECT  35.952 103.572 35.976 103.656 ;
    END
  END a_d[461]
  PIN a_d[462]
    DIRECTION INPUT ;
    USE SIGNAL ;
    PORT
      LAYER M5 ;
        RECT  36 103.572 36.024 103.656 ;
    END
  END a_d[462]
  PIN a_d[463]
    DIRECTION INPUT ;
    USE SIGNAL ;
    PORT
      LAYER M5 ;
        RECT  36.048 103.572 36.072 103.656 ;
    END
  END a_d[463]
  PIN a_d[464]
    DIRECTION INPUT ;
    USE SIGNAL ;
    PORT
      LAYER M5 ;
        RECT  36.096 103.572 36.12 103.656 ;
    END
  END a_d[464]
  PIN a_d[465]
    DIRECTION INPUT ;
    USE SIGNAL ;
    PORT
      LAYER M5 ;
        RECT  36.144 103.572 36.168 103.656 ;
    END
  END a_d[465]
  PIN a_d[466]
    DIRECTION INPUT ;
    USE SIGNAL ;
    PORT
      LAYER M5 ;
        RECT  36.192 103.572 36.216 103.656 ;
    END
  END a_d[466]
  PIN a_d[467]
    DIRECTION INPUT ;
    USE SIGNAL ;
    PORT
      LAYER M5 ;
        RECT  36.24 103.572 36.264 103.656 ;
    END
  END a_d[467]
  PIN a_d[468]
    DIRECTION INPUT ;
    USE SIGNAL ;
    PORT
      LAYER M5 ;
        RECT  36.288 103.572 36.312 103.656 ;
    END
  END a_d[468]
  PIN a_d[469]
    DIRECTION INPUT ;
    USE SIGNAL ;
    PORT
      LAYER M5 ;
        RECT  36.336 103.572 36.36 103.656 ;
    END
  END a_d[469]
  PIN a_d[46]
    DIRECTION INPUT ;
    USE SIGNAL ;
    PORT
      LAYER M5 ;
        RECT  16.032 103.572 16.056 103.656 ;
    END
  END a_d[46]
  PIN a_d[470]
    DIRECTION INPUT ;
    USE SIGNAL ;
    PORT
      LAYER M5 ;
        RECT  36.384 103.572 36.408 103.656 ;
    END
  END a_d[470]
  PIN a_d[471]
    DIRECTION INPUT ;
    USE SIGNAL ;
    PORT
      LAYER M5 ;
        RECT  36.432 103.572 36.456 103.656 ;
    END
  END a_d[471]
  PIN a_d[472]
    DIRECTION INPUT ;
    USE SIGNAL ;
    PORT
      LAYER M5 ;
        RECT  36.48 103.572 36.504 103.656 ;
    END
  END a_d[472]
  PIN a_d[473]
    DIRECTION INPUT ;
    USE SIGNAL ;
    PORT
      LAYER M5 ;
        RECT  36.528 103.572 36.552 103.656 ;
    END
  END a_d[473]
  PIN a_d[474]
    DIRECTION INPUT ;
    USE SIGNAL ;
    PORT
      LAYER M5 ;
        RECT  36.576 103.572 36.6 103.656 ;
    END
  END a_d[474]
  PIN a_d[475]
    DIRECTION INPUT ;
    USE SIGNAL ;
    PORT
      LAYER M5 ;
        RECT  36.624 103.572 36.648 103.656 ;
    END
  END a_d[475]
  PIN a_d[476]
    DIRECTION INPUT ;
    USE SIGNAL ;
    PORT
      LAYER M5 ;
        RECT  36.672 103.572 36.696 103.656 ;
    END
  END a_d[476]
  PIN a_d[477]
    DIRECTION INPUT ;
    USE SIGNAL ;
    PORT
      LAYER M5 ;
        RECT  36.72 103.572 36.744 103.656 ;
    END
  END a_d[477]
  PIN a_d[478]
    DIRECTION INPUT ;
    USE SIGNAL ;
    PORT
      LAYER M5 ;
        RECT  36.768 103.572 36.792 103.656 ;
    END
  END a_d[478]
  PIN a_d[479]
    DIRECTION INPUT ;
    USE SIGNAL ;
    PORT
      LAYER M5 ;
        RECT  36.816 103.572 36.84 103.656 ;
    END
  END a_d[479]
  PIN a_d[47]
    DIRECTION INPUT ;
    USE SIGNAL ;
    PORT
      LAYER M5 ;
        RECT  16.08 103.572 16.104 103.656 ;
    END
  END a_d[47]
  PIN a_d[480]
    DIRECTION INPUT ;
    USE SIGNAL ;
    PORT
      LAYER M5 ;
        RECT  36.864 103.572 36.888 103.656 ;
    END
  END a_d[480]
  PIN a_d[481]
    DIRECTION INPUT ;
    USE SIGNAL ;
    PORT
      LAYER M5 ;
        RECT  36.912 103.572 36.936 103.656 ;
    END
  END a_d[481]
  PIN a_d[482]
    DIRECTION INPUT ;
    USE SIGNAL ;
    PORT
      LAYER M5 ;
        RECT  36.96 103.572 36.984 103.656 ;
    END
  END a_d[482]
  PIN a_d[483]
    DIRECTION INPUT ;
    USE SIGNAL ;
    PORT
      LAYER M5 ;
        RECT  37.008 103.572 37.032 103.656 ;
    END
  END a_d[483]
  PIN a_d[484]
    DIRECTION INPUT ;
    USE SIGNAL ;
    PORT
      LAYER M5 ;
        RECT  37.056 103.572 37.08 103.656 ;
    END
  END a_d[484]
  PIN a_d[485]
    DIRECTION INPUT ;
    USE SIGNAL ;
    PORT
      LAYER M5 ;
        RECT  37.104 103.572 37.128 103.656 ;
    END
  END a_d[485]
  PIN a_d[486]
    DIRECTION INPUT ;
    USE SIGNAL ;
    PORT
      LAYER M5 ;
        RECT  37.152 103.572 37.176 103.656 ;
    END
  END a_d[486]
  PIN a_d[487]
    DIRECTION INPUT ;
    USE SIGNAL ;
    PORT
      LAYER M5 ;
        RECT  37.2 103.572 37.224 103.656 ;
    END
  END a_d[487]
  PIN a_d[488]
    DIRECTION INPUT ;
    USE SIGNAL ;
    PORT
      LAYER M5 ;
        RECT  37.248 103.572 37.272 103.656 ;
    END
  END a_d[488]
  PIN a_d[489]
    DIRECTION INPUT ;
    USE SIGNAL ;
    PORT
      LAYER M5 ;
        RECT  37.296 103.572 37.32 103.656 ;
    END
  END a_d[489]
  PIN a_d[48]
    DIRECTION INPUT ;
    USE SIGNAL ;
    PORT
      LAYER M5 ;
        RECT  16.128 103.572 16.152 103.656 ;
    END
  END a_d[48]
  PIN a_d[490]
    DIRECTION INPUT ;
    USE SIGNAL ;
    PORT
      LAYER M5 ;
        RECT  37.344 103.572 37.368 103.656 ;
    END
  END a_d[490]
  PIN a_d[491]
    DIRECTION INPUT ;
    USE SIGNAL ;
    PORT
      LAYER M5 ;
        RECT  37.392 103.572 37.416 103.656 ;
    END
  END a_d[491]
  PIN a_d[492]
    DIRECTION INPUT ;
    USE SIGNAL ;
    PORT
      LAYER M5 ;
        RECT  37.44 103.572 37.464 103.656 ;
    END
  END a_d[492]
  PIN a_d[493]
    DIRECTION INPUT ;
    USE SIGNAL ;
    PORT
      LAYER M5 ;
        RECT  37.488 103.572 37.512 103.656 ;
    END
  END a_d[493]
  PIN a_d[494]
    DIRECTION INPUT ;
    USE SIGNAL ;
    PORT
      LAYER M5 ;
        RECT  37.536 103.572 37.56 103.656 ;
    END
  END a_d[494]
  PIN a_d[495]
    DIRECTION INPUT ;
    USE SIGNAL ;
    PORT
      LAYER M5 ;
        RECT  37.584 103.572 37.608 103.656 ;
    END
  END a_d[495]
  PIN a_d[496]
    DIRECTION INPUT ;
    USE SIGNAL ;
    PORT
      LAYER M5 ;
        RECT  37.632 103.572 37.656 103.656 ;
    END
  END a_d[496]
  PIN a_d[497]
    DIRECTION INPUT ;
    USE SIGNAL ;
    PORT
      LAYER M5 ;
        RECT  37.68 103.572 37.704 103.656 ;
    END
  END a_d[497]
  PIN a_d[498]
    DIRECTION INPUT ;
    USE SIGNAL ;
    PORT
      LAYER M5 ;
        RECT  37.728 103.572 37.752 103.656 ;
    END
  END a_d[498]
  PIN a_d[499]
    DIRECTION INPUT ;
    USE SIGNAL ;
    PORT
      LAYER M5 ;
        RECT  37.776 103.572 37.8 103.656 ;
    END
  END a_d[499]
  PIN a_d[49]
    DIRECTION INPUT ;
    USE SIGNAL ;
    PORT
      LAYER M5 ;
        RECT  16.176 103.572 16.2 103.656 ;
    END
  END a_d[49]
  PIN a_d[4]
    DIRECTION INPUT ;
    USE SIGNAL ;
    PORT
      LAYER M5 ;
        RECT  14.016 103.572 14.04 103.656 ;
    END
  END a_d[4]
  PIN a_d[500]
    DIRECTION INPUT ;
    USE SIGNAL ;
    PORT
      LAYER M5 ;
        RECT  37.824 103.572 37.848 103.656 ;
    END
  END a_d[500]
  PIN a_d[501]
    DIRECTION INPUT ;
    USE SIGNAL ;
    PORT
      LAYER M5 ;
        RECT  37.872 103.572 37.896 103.656 ;
    END
  END a_d[501]
  PIN a_d[502]
    DIRECTION INPUT ;
    USE SIGNAL ;
    PORT
      LAYER M5 ;
        RECT  37.92 103.572 37.944 103.656 ;
    END
  END a_d[502]
  PIN a_d[503]
    DIRECTION INPUT ;
    USE SIGNAL ;
    PORT
      LAYER M5 ;
        RECT  37.968 103.572 37.992 103.656 ;
    END
  END a_d[503]
  PIN a_d[504]
    DIRECTION INPUT ;
    USE SIGNAL ;
    PORT
      LAYER M5 ;
        RECT  38.016 103.572 38.04 103.656 ;
    END
  END a_d[504]
  PIN a_d[505]
    DIRECTION INPUT ;
    USE SIGNAL ;
    PORT
      LAYER M5 ;
        RECT  38.064 103.572 38.088 103.656 ;
    END
  END a_d[505]
  PIN a_d[506]
    DIRECTION INPUT ;
    USE SIGNAL ;
    PORT
      LAYER M5 ;
        RECT  38.112 103.572 38.136 103.656 ;
    END
  END a_d[506]
  PIN a_d[507]
    DIRECTION INPUT ;
    USE SIGNAL ;
    PORT
      LAYER M5 ;
        RECT  38.16 103.572 38.184 103.656 ;
    END
  END a_d[507]
  PIN a_d[50]
    DIRECTION INPUT ;
    USE SIGNAL ;
    PORT
      LAYER M5 ;
        RECT  16.224 103.572 16.248 103.656 ;
    END
  END a_d[50]
  PIN a_d[51]
    DIRECTION INPUT ;
    USE SIGNAL ;
    PORT
      LAYER M5 ;
        RECT  16.272 103.572 16.296 103.656 ;
    END
  END a_d[51]
  PIN a_d[52]
    DIRECTION INPUT ;
    USE SIGNAL ;
    PORT
      LAYER M5 ;
        RECT  16.32 103.572 16.344 103.656 ;
    END
  END a_d[52]
  PIN a_d[53]
    DIRECTION INPUT ;
    USE SIGNAL ;
    PORT
      LAYER M5 ;
        RECT  16.368 103.572 16.392 103.656 ;
    END
  END a_d[53]
  PIN a_d[54]
    DIRECTION INPUT ;
    USE SIGNAL ;
    PORT
      LAYER M5 ;
        RECT  16.416 103.572 16.44 103.656 ;
    END
  END a_d[54]
  PIN a_d[55]
    DIRECTION INPUT ;
    USE SIGNAL ;
    PORT
      LAYER M5 ;
        RECT  16.464 103.572 16.488 103.656 ;
    END
  END a_d[55]
  PIN a_d[56]
    DIRECTION INPUT ;
    USE SIGNAL ;
    PORT
      LAYER M5 ;
        RECT  16.512 103.572 16.536 103.656 ;
    END
  END a_d[56]
  PIN a_d[57]
    DIRECTION INPUT ;
    USE SIGNAL ;
    PORT
      LAYER M5 ;
        RECT  16.56 103.572 16.584 103.656 ;
    END
  END a_d[57]
  PIN a_d[58]
    DIRECTION INPUT ;
    USE SIGNAL ;
    PORT
      LAYER M5 ;
        RECT  16.608 103.572 16.632 103.656 ;
    END
  END a_d[58]
  PIN a_d[59]
    DIRECTION INPUT ;
    USE SIGNAL ;
    PORT
      LAYER M5 ;
        RECT  16.656 103.572 16.68 103.656 ;
    END
  END a_d[59]
  PIN a_d[5]
    DIRECTION INPUT ;
    USE SIGNAL ;
    PORT
      LAYER M5 ;
        RECT  14.064 103.572 14.088 103.656 ;
    END
  END a_d[5]
  PIN a_d[60]
    DIRECTION INPUT ;
    USE SIGNAL ;
    PORT
      LAYER M5 ;
        RECT  16.704 103.572 16.728 103.656 ;
    END
  END a_d[60]
  PIN a_d[61]
    DIRECTION INPUT ;
    USE SIGNAL ;
    PORT
      LAYER M5 ;
        RECT  16.752 103.572 16.776 103.656 ;
    END
  END a_d[61]
  PIN a_d[62]
    DIRECTION INPUT ;
    USE SIGNAL ;
    PORT
      LAYER M5 ;
        RECT  16.8 103.572 16.824 103.656 ;
    END
  END a_d[62]
  PIN a_d[63]
    DIRECTION INPUT ;
    USE SIGNAL ;
    PORT
      LAYER M5 ;
        RECT  16.848 103.572 16.872 103.656 ;
    END
  END a_d[63]
  PIN a_d[64]
    DIRECTION INPUT ;
    USE SIGNAL ;
    PORT
      LAYER M5 ;
        RECT  16.896 103.572 16.92 103.656 ;
    END
  END a_d[64]
  PIN a_d[65]
    DIRECTION INPUT ;
    USE SIGNAL ;
    PORT
      LAYER M5 ;
        RECT  16.944 103.572 16.968 103.656 ;
    END
  END a_d[65]
  PIN a_d[66]
    DIRECTION INPUT ;
    USE SIGNAL ;
    PORT
      LAYER M5 ;
        RECT  16.992 103.572 17.016 103.656 ;
    END
  END a_d[66]
  PIN a_d[67]
    DIRECTION INPUT ;
    USE SIGNAL ;
    PORT
      LAYER M5 ;
        RECT  17.04 103.572 17.064 103.656 ;
    END
  END a_d[67]
  PIN a_d[68]
    DIRECTION INPUT ;
    USE SIGNAL ;
    PORT
      LAYER M5 ;
        RECT  17.088 103.572 17.112 103.656 ;
    END
  END a_d[68]
  PIN a_d[69]
    DIRECTION INPUT ;
    USE SIGNAL ;
    PORT
      LAYER M5 ;
        RECT  17.136 103.572 17.16 103.656 ;
    END
  END a_d[69]
  PIN a_d[6]
    DIRECTION INPUT ;
    USE SIGNAL ;
    PORT
      LAYER M5 ;
        RECT  14.112 103.572 14.136 103.656 ;
    END
  END a_d[6]
  PIN a_d[70]
    DIRECTION INPUT ;
    USE SIGNAL ;
    PORT
      LAYER M5 ;
        RECT  17.184 103.572 17.208 103.656 ;
    END
  END a_d[70]
  PIN a_d[71]
    DIRECTION INPUT ;
    USE SIGNAL ;
    PORT
      LAYER M5 ;
        RECT  17.232 103.572 17.256 103.656 ;
    END
  END a_d[71]
  PIN a_d[72]
    DIRECTION INPUT ;
    USE SIGNAL ;
    PORT
      LAYER M5 ;
        RECT  17.28 103.572 17.304 103.656 ;
    END
  END a_d[72]
  PIN a_d[73]
    DIRECTION INPUT ;
    USE SIGNAL ;
    PORT
      LAYER M5 ;
        RECT  17.328 103.572 17.352 103.656 ;
    END
  END a_d[73]
  PIN a_d[74]
    DIRECTION INPUT ;
    USE SIGNAL ;
    PORT
      LAYER M5 ;
        RECT  17.376 103.572 17.4 103.656 ;
    END
  END a_d[74]
  PIN a_d[75]
    DIRECTION INPUT ;
    USE SIGNAL ;
    PORT
      LAYER M5 ;
        RECT  17.424 103.572 17.448 103.656 ;
    END
  END a_d[75]
  PIN a_d[76]
    DIRECTION INPUT ;
    USE SIGNAL ;
    PORT
      LAYER M5 ;
        RECT  17.472 103.572 17.496 103.656 ;
    END
  END a_d[76]
  PIN a_d[77]
    DIRECTION INPUT ;
    USE SIGNAL ;
    PORT
      LAYER M5 ;
        RECT  17.52 103.572 17.544 103.656 ;
    END
  END a_d[77]
  PIN a_d[78]
    DIRECTION INPUT ;
    USE SIGNAL ;
    PORT
      LAYER M5 ;
        RECT  17.568 103.572 17.592 103.656 ;
    END
  END a_d[78]
  PIN a_d[79]
    DIRECTION INPUT ;
    USE SIGNAL ;
    PORT
      LAYER M5 ;
        RECT  17.616 103.572 17.64 103.656 ;
    END
  END a_d[79]
  PIN a_d[7]
    DIRECTION INPUT ;
    USE SIGNAL ;
    PORT
      LAYER M5 ;
        RECT  14.16 103.572 14.184 103.656 ;
    END
  END a_d[7]
  PIN a_d[80]
    DIRECTION INPUT ;
    USE SIGNAL ;
    PORT
      LAYER M5 ;
        RECT  17.664 103.572 17.688 103.656 ;
    END
  END a_d[80]
  PIN a_d[81]
    DIRECTION INPUT ;
    USE SIGNAL ;
    PORT
      LAYER M5 ;
        RECT  17.712 103.572 17.736 103.656 ;
    END
  END a_d[81]
  PIN a_d[82]
    DIRECTION INPUT ;
    USE SIGNAL ;
    PORT
      LAYER M5 ;
        RECT  17.76 103.572 17.784 103.656 ;
    END
  END a_d[82]
  PIN a_d[83]
    DIRECTION INPUT ;
    USE SIGNAL ;
    PORT
      LAYER M5 ;
        RECT  17.808 103.572 17.832 103.656 ;
    END
  END a_d[83]
  PIN a_d[84]
    DIRECTION INPUT ;
    USE SIGNAL ;
    PORT
      LAYER M5 ;
        RECT  17.856 103.572 17.88 103.656 ;
    END
  END a_d[84]
  PIN a_d[85]
    DIRECTION INPUT ;
    USE SIGNAL ;
    PORT
      LAYER M5 ;
        RECT  17.904 103.572 17.928 103.656 ;
    END
  END a_d[85]
  PIN a_d[86]
    DIRECTION INPUT ;
    USE SIGNAL ;
    PORT
      LAYER M5 ;
        RECT  17.952 103.572 17.976 103.656 ;
    END
  END a_d[86]
  PIN a_d[87]
    DIRECTION INPUT ;
    USE SIGNAL ;
    PORT
      LAYER M5 ;
        RECT  18 103.572 18.024 103.656 ;
    END
  END a_d[87]
  PIN a_d[88]
    DIRECTION INPUT ;
    USE SIGNAL ;
    PORT
      LAYER M5 ;
        RECT  18.048 103.572 18.072 103.656 ;
    END
  END a_d[88]
  PIN a_d[89]
    DIRECTION INPUT ;
    USE SIGNAL ;
    PORT
      LAYER M5 ;
        RECT  18.096 103.572 18.12 103.656 ;
    END
  END a_d[89]
  PIN a_d[8]
    DIRECTION INPUT ;
    USE SIGNAL ;
    PORT
      LAYER M5 ;
        RECT  14.208 103.572 14.232 103.656 ;
    END
  END a_d[8]
  PIN a_d[90]
    DIRECTION INPUT ;
    USE SIGNAL ;
    PORT
      LAYER M5 ;
        RECT  18.144 103.572 18.168 103.656 ;
    END
  END a_d[90]
  PIN a_d[91]
    DIRECTION INPUT ;
    USE SIGNAL ;
    PORT
      LAYER M5 ;
        RECT  18.192 103.572 18.216 103.656 ;
    END
  END a_d[91]
  PIN a_d[92]
    DIRECTION INPUT ;
    USE SIGNAL ;
    PORT
      LAYER M5 ;
        RECT  18.24 103.572 18.264 103.656 ;
    END
  END a_d[92]
  PIN a_d[93]
    DIRECTION INPUT ;
    USE SIGNAL ;
    PORT
      LAYER M5 ;
        RECT  18.288 103.572 18.312 103.656 ;
    END
  END a_d[93]
  PIN a_d[94]
    DIRECTION INPUT ;
    USE SIGNAL ;
    PORT
      LAYER M5 ;
        RECT  18.336 103.572 18.36 103.656 ;
    END
  END a_d[94]
  PIN a_d[95]
    DIRECTION INPUT ;
    USE SIGNAL ;
    PORT
      LAYER M5 ;
        RECT  18.384 103.572 18.408 103.656 ;
    END
  END a_d[95]
  PIN a_d[96]
    DIRECTION INPUT ;
    USE SIGNAL ;
    PORT
      LAYER M5 ;
        RECT  18.432 103.572 18.456 103.656 ;
    END
  END a_d[96]
  PIN a_d[97]
    DIRECTION INPUT ;
    USE SIGNAL ;
    PORT
      LAYER M5 ;
        RECT  18.48 103.572 18.504 103.656 ;
    END
  END a_d[97]
  PIN a_d[98]
    DIRECTION INPUT ;
    USE SIGNAL ;
    PORT
      LAYER M5 ;
        RECT  18.528 103.572 18.552 103.656 ;
    END
  END a_d[98]
  PIN a_d[99]
    DIRECTION INPUT ;
    USE SIGNAL ;
    PORT
      LAYER M5 ;
        RECT  18.576 103.572 18.6 103.656 ;
    END
  END a_d[99]
  PIN a_d[9]
    DIRECTION INPUT ;
    USE SIGNAL ;
    PORT
      LAYER M5 ;
        RECT  14.256 103.572 14.28 103.656 ;
    END
  END a_d[9]
  PIN a_r
    DIRECTION OUTPUT ;
    USE SIGNAL ;
    PORT
      LAYER M5 ;
        RECT  38.208 103.572 38.232 103.656 ;
    END
  END a_r
  PIN b_d[0]
    DIRECTION OUTPUT ;
    USE SIGNAL ;
    PORT
      LAYER M5 ;
        RECT  13.776 0 13.8 0.084 ;
    END
  END b_d[0]
  PIN b_d[100]
    DIRECTION OUTPUT ;
    USE SIGNAL ;
    PORT
      LAYER M5 ;
        RECT  18.576 0 18.6 0.084 ;
    END
  END b_d[100]
  PIN b_d[101]
    DIRECTION OUTPUT ;
    USE SIGNAL ;
    PORT
      LAYER M5 ;
        RECT  18.624 0 18.648 0.084 ;
    END
  END b_d[101]
  PIN b_d[102]
    DIRECTION OUTPUT ;
    USE SIGNAL ;
    PORT
      LAYER M5 ;
        RECT  18.672 0 18.696 0.084 ;
    END
  END b_d[102]
  PIN b_d[103]
    DIRECTION OUTPUT ;
    USE SIGNAL ;
    PORT
      LAYER M5 ;
        RECT  18.72 0 18.744 0.084 ;
    END
  END b_d[103]
  PIN b_d[104]
    DIRECTION OUTPUT ;
    USE SIGNAL ;
    PORT
      LAYER M5 ;
        RECT  18.768 0 18.792 0.084 ;
    END
  END b_d[104]
  PIN b_d[105]
    DIRECTION OUTPUT ;
    USE SIGNAL ;
    PORT
      LAYER M5 ;
        RECT  18.816 0 18.84 0.084 ;
    END
  END b_d[105]
  PIN b_d[106]
    DIRECTION OUTPUT ;
    USE SIGNAL ;
    PORT
      LAYER M5 ;
        RECT  18.864 0 18.888 0.084 ;
    END
  END b_d[106]
  PIN b_d[107]
    DIRECTION OUTPUT ;
    USE SIGNAL ;
    PORT
      LAYER M5 ;
        RECT  18.912 0 18.936 0.084 ;
    END
  END b_d[107]
  PIN b_d[108]
    DIRECTION OUTPUT ;
    USE SIGNAL ;
    PORT
      LAYER M5 ;
        RECT  18.96 0 18.984 0.084 ;
    END
  END b_d[108]
  PIN b_d[109]
    DIRECTION OUTPUT ;
    USE SIGNAL ;
    PORT
      LAYER M5 ;
        RECT  19.008 0 19.032 0.084 ;
    END
  END b_d[109]
  PIN b_d[10]
    DIRECTION OUTPUT ;
    USE SIGNAL ;
    PORT
      LAYER M5 ;
        RECT  14.256 0 14.28 0.084 ;
    END
  END b_d[10]
  PIN b_d[110]
    DIRECTION OUTPUT ;
    USE SIGNAL ;
    PORT
      LAYER M5 ;
        RECT  19.056 0 19.08 0.084 ;
    END
  END b_d[110]
  PIN b_d[111]
    DIRECTION OUTPUT ;
    USE SIGNAL ;
    PORT
      LAYER M5 ;
        RECT  19.104 0 19.128 0.084 ;
    END
  END b_d[111]
  PIN b_d[112]
    DIRECTION OUTPUT ;
    USE SIGNAL ;
    PORT
      LAYER M5 ;
        RECT  19.152 0 19.176 0.084 ;
    END
  END b_d[112]
  PIN b_d[113]
    DIRECTION OUTPUT ;
    USE SIGNAL ;
    PORT
      LAYER M5 ;
        RECT  19.2 0 19.224 0.084 ;
    END
  END b_d[113]
  PIN b_d[114]
    DIRECTION OUTPUT ;
    USE SIGNAL ;
    PORT
      LAYER M5 ;
        RECT  19.248 0 19.272 0.084 ;
    END
  END b_d[114]
  PIN b_d[115]
    DIRECTION OUTPUT ;
    USE SIGNAL ;
    PORT
      LAYER M5 ;
        RECT  19.296 0 19.32 0.084 ;
    END
  END b_d[115]
  PIN b_d[116]
    DIRECTION OUTPUT ;
    USE SIGNAL ;
    PORT
      LAYER M5 ;
        RECT  19.344 0 19.368 0.084 ;
    END
  END b_d[116]
  PIN b_d[117]
    DIRECTION OUTPUT ;
    USE SIGNAL ;
    PORT
      LAYER M5 ;
        RECT  19.392 0 19.416 0.084 ;
    END
  END b_d[117]
  PIN b_d[118]
    DIRECTION OUTPUT ;
    USE SIGNAL ;
    PORT
      LAYER M5 ;
        RECT  19.44 0 19.464 0.084 ;
    END
  END b_d[118]
  PIN b_d[119]
    DIRECTION OUTPUT ;
    USE SIGNAL ;
    PORT
      LAYER M5 ;
        RECT  19.488 0 19.512 0.084 ;
    END
  END b_d[119]
  PIN b_d[11]
    DIRECTION OUTPUT ;
    USE SIGNAL ;
    PORT
      LAYER M5 ;
        RECT  14.304 0 14.328 0.084 ;
    END
  END b_d[11]
  PIN b_d[120]
    DIRECTION OUTPUT ;
    USE SIGNAL ;
    PORT
      LAYER M5 ;
        RECT  19.536 0 19.56 0.084 ;
    END
  END b_d[120]
  PIN b_d[121]
    DIRECTION OUTPUT ;
    USE SIGNAL ;
    PORT
      LAYER M5 ;
        RECT  19.584 0 19.608 0.084 ;
    END
  END b_d[121]
  PIN b_d[122]
    DIRECTION OUTPUT ;
    USE SIGNAL ;
    PORT
      LAYER M5 ;
        RECT  19.632 0 19.656 0.084 ;
    END
  END b_d[122]
  PIN b_d[123]
    DIRECTION OUTPUT ;
    USE SIGNAL ;
    PORT
      LAYER M5 ;
        RECT  19.68 0 19.704 0.084 ;
    END
  END b_d[123]
  PIN b_d[124]
    DIRECTION OUTPUT ;
    USE SIGNAL ;
    PORT
      LAYER M5 ;
        RECT  19.728 0 19.752 0.084 ;
    END
  END b_d[124]
  PIN b_d[125]
    DIRECTION OUTPUT ;
    USE SIGNAL ;
    PORT
      LAYER M5 ;
        RECT  19.776 0 19.8 0.084 ;
    END
  END b_d[125]
  PIN b_d[126]
    DIRECTION OUTPUT ;
    USE SIGNAL ;
    PORT
      LAYER M5 ;
        RECT  19.824 0 19.848 0.084 ;
    END
  END b_d[126]
  PIN b_d[127]
    DIRECTION OUTPUT ;
    USE SIGNAL ;
    PORT
      LAYER M5 ;
        RECT  19.872 0 19.896 0.084 ;
    END
  END b_d[127]
  PIN b_d[128]
    DIRECTION OUTPUT ;
    USE SIGNAL ;
    PORT
      LAYER M5 ;
        RECT  19.92 0 19.944 0.084 ;
    END
  END b_d[128]
  PIN b_d[129]
    DIRECTION OUTPUT ;
    USE SIGNAL ;
    PORT
      LAYER M5 ;
        RECT  19.968 0 19.992 0.084 ;
    END
  END b_d[129]
  PIN b_d[12]
    DIRECTION OUTPUT ;
    USE SIGNAL ;
    PORT
      LAYER M5 ;
        RECT  14.352 0 14.376 0.084 ;
    END
  END b_d[12]
  PIN b_d[130]
    DIRECTION OUTPUT ;
    USE SIGNAL ;
    PORT
      LAYER M5 ;
        RECT  20.016 0 20.04 0.084 ;
    END
  END b_d[130]
  PIN b_d[131]
    DIRECTION OUTPUT ;
    USE SIGNAL ;
    PORT
      LAYER M5 ;
        RECT  20.064 0 20.088 0.084 ;
    END
  END b_d[131]
  PIN b_d[132]
    DIRECTION OUTPUT ;
    USE SIGNAL ;
    PORT
      LAYER M5 ;
        RECT  20.112 0 20.136 0.084 ;
    END
  END b_d[132]
  PIN b_d[133]
    DIRECTION OUTPUT ;
    USE SIGNAL ;
    PORT
      LAYER M5 ;
        RECT  20.16 0 20.184 0.084 ;
    END
  END b_d[133]
  PIN b_d[134]
    DIRECTION OUTPUT ;
    USE SIGNAL ;
    PORT
      LAYER M5 ;
        RECT  20.208 0 20.232 0.084 ;
    END
  END b_d[134]
  PIN b_d[135]
    DIRECTION OUTPUT ;
    USE SIGNAL ;
    PORT
      LAYER M5 ;
        RECT  20.256 0 20.28 0.084 ;
    END
  END b_d[135]
  PIN b_d[136]
    DIRECTION OUTPUT ;
    USE SIGNAL ;
    PORT
      LAYER M5 ;
        RECT  20.304 0 20.328 0.084 ;
    END
  END b_d[136]
  PIN b_d[137]
    DIRECTION OUTPUT ;
    USE SIGNAL ;
    PORT
      LAYER M5 ;
        RECT  20.352 0 20.376 0.084 ;
    END
  END b_d[137]
  PIN b_d[138]
    DIRECTION OUTPUT ;
    USE SIGNAL ;
    PORT
      LAYER M5 ;
        RECT  20.4 0 20.424 0.084 ;
    END
  END b_d[138]
  PIN b_d[139]
    DIRECTION OUTPUT ;
    USE SIGNAL ;
    PORT
      LAYER M5 ;
        RECT  20.448 0 20.472 0.084 ;
    END
  END b_d[139]
  PIN b_d[13]
    DIRECTION OUTPUT ;
    USE SIGNAL ;
    PORT
      LAYER M5 ;
        RECT  14.4 0 14.424 0.084 ;
    END
  END b_d[13]
  PIN b_d[140]
    DIRECTION OUTPUT ;
    USE SIGNAL ;
    PORT
      LAYER M5 ;
        RECT  20.496 0 20.52 0.084 ;
    END
  END b_d[140]
  PIN b_d[141]
    DIRECTION OUTPUT ;
    USE SIGNAL ;
    PORT
      LAYER M5 ;
        RECT  20.544 0 20.568 0.084 ;
    END
  END b_d[141]
  PIN b_d[142]
    DIRECTION OUTPUT ;
    USE SIGNAL ;
    PORT
      LAYER M5 ;
        RECT  20.592 0 20.616 0.084 ;
    END
  END b_d[142]
  PIN b_d[143]
    DIRECTION OUTPUT ;
    USE SIGNAL ;
    PORT
      LAYER M5 ;
        RECT  20.64 0 20.664 0.084 ;
    END
  END b_d[143]
  PIN b_d[144]
    DIRECTION OUTPUT ;
    USE SIGNAL ;
    PORT
      LAYER M5 ;
        RECT  20.688 0 20.712 0.084 ;
    END
  END b_d[144]
  PIN b_d[145]
    DIRECTION OUTPUT ;
    USE SIGNAL ;
    PORT
      LAYER M5 ;
        RECT  20.736 0 20.76 0.084 ;
    END
  END b_d[145]
  PIN b_d[146]
    DIRECTION OUTPUT ;
    USE SIGNAL ;
    PORT
      LAYER M5 ;
        RECT  20.784 0 20.808 0.084 ;
    END
  END b_d[146]
  PIN b_d[147]
    DIRECTION OUTPUT ;
    USE SIGNAL ;
    PORT
      LAYER M5 ;
        RECT  20.832 0 20.856 0.084 ;
    END
  END b_d[147]
  PIN b_d[148]
    DIRECTION OUTPUT ;
    USE SIGNAL ;
    PORT
      LAYER M5 ;
        RECT  20.88 0 20.904 0.084 ;
    END
  END b_d[148]
  PIN b_d[149]
    DIRECTION OUTPUT ;
    USE SIGNAL ;
    PORT
      LAYER M5 ;
        RECT  20.928 0 20.952 0.084 ;
    END
  END b_d[149]
  PIN b_d[14]
    DIRECTION OUTPUT ;
    USE SIGNAL ;
    PORT
      LAYER M5 ;
        RECT  14.448 0 14.472 0.084 ;
    END
  END b_d[14]
  PIN b_d[150]
    DIRECTION OUTPUT ;
    USE SIGNAL ;
    PORT
      LAYER M5 ;
        RECT  20.976 0 21 0.084 ;
    END
  END b_d[150]
  PIN b_d[151]
    DIRECTION OUTPUT ;
    USE SIGNAL ;
    PORT
      LAYER M5 ;
        RECT  21.024 0 21.048 0.084 ;
    END
  END b_d[151]
  PIN b_d[152]
    DIRECTION OUTPUT ;
    USE SIGNAL ;
    PORT
      LAYER M5 ;
        RECT  21.072 0 21.096 0.084 ;
    END
  END b_d[152]
  PIN b_d[153]
    DIRECTION OUTPUT ;
    USE SIGNAL ;
    PORT
      LAYER M5 ;
        RECT  21.12 0 21.144 0.084 ;
    END
  END b_d[153]
  PIN b_d[154]
    DIRECTION OUTPUT ;
    USE SIGNAL ;
    PORT
      LAYER M5 ;
        RECT  21.168 0 21.192 0.084 ;
    END
  END b_d[154]
  PIN b_d[155]
    DIRECTION OUTPUT ;
    USE SIGNAL ;
    PORT
      LAYER M5 ;
        RECT  21.216 0 21.24 0.084 ;
    END
  END b_d[155]
  PIN b_d[156]
    DIRECTION OUTPUT ;
    USE SIGNAL ;
    PORT
      LAYER M5 ;
        RECT  21.264 0 21.288 0.084 ;
    END
  END b_d[156]
  PIN b_d[157]
    DIRECTION OUTPUT ;
    USE SIGNAL ;
    PORT
      LAYER M5 ;
        RECT  21.312 0 21.336 0.084 ;
    END
  END b_d[157]
  PIN b_d[158]
    DIRECTION OUTPUT ;
    USE SIGNAL ;
    PORT
      LAYER M5 ;
        RECT  21.36 0 21.384 0.084 ;
    END
  END b_d[158]
  PIN b_d[159]
    DIRECTION OUTPUT ;
    USE SIGNAL ;
    PORT
      LAYER M5 ;
        RECT  21.408 0 21.432 0.084 ;
    END
  END b_d[159]
  PIN b_d[15]
    DIRECTION OUTPUT ;
    USE SIGNAL ;
    PORT
      LAYER M5 ;
        RECT  14.496 0 14.52 0.084 ;
    END
  END b_d[15]
  PIN b_d[160]
    DIRECTION OUTPUT ;
    USE SIGNAL ;
    PORT
      LAYER M5 ;
        RECT  21.456 0 21.48 0.084 ;
    END
  END b_d[160]
  PIN b_d[161]
    DIRECTION OUTPUT ;
    USE SIGNAL ;
    PORT
      LAYER M5 ;
        RECT  21.504 0 21.528 0.084 ;
    END
  END b_d[161]
  PIN b_d[162]
    DIRECTION OUTPUT ;
    USE SIGNAL ;
    PORT
      LAYER M5 ;
        RECT  21.552 0 21.576 0.084 ;
    END
  END b_d[162]
  PIN b_d[163]
    DIRECTION OUTPUT ;
    USE SIGNAL ;
    PORT
      LAYER M5 ;
        RECT  21.6 0 21.624 0.084 ;
    END
  END b_d[163]
  PIN b_d[164]
    DIRECTION OUTPUT ;
    USE SIGNAL ;
    PORT
      LAYER M5 ;
        RECT  21.648 0 21.672 0.084 ;
    END
  END b_d[164]
  PIN b_d[165]
    DIRECTION OUTPUT ;
    USE SIGNAL ;
    PORT
      LAYER M5 ;
        RECT  21.696 0 21.72 0.084 ;
    END
  END b_d[165]
  PIN b_d[166]
    DIRECTION OUTPUT ;
    USE SIGNAL ;
    PORT
      LAYER M5 ;
        RECT  21.744 0 21.768 0.084 ;
    END
  END b_d[166]
  PIN b_d[167]
    DIRECTION OUTPUT ;
    USE SIGNAL ;
    PORT
      LAYER M5 ;
        RECT  21.792 0 21.816 0.084 ;
    END
  END b_d[167]
  PIN b_d[168]
    DIRECTION OUTPUT ;
    USE SIGNAL ;
    PORT
      LAYER M5 ;
        RECT  21.84 0 21.864 0.084 ;
    END
  END b_d[168]
  PIN b_d[169]
    DIRECTION OUTPUT ;
    USE SIGNAL ;
    PORT
      LAYER M5 ;
        RECT  21.888 0 21.912 0.084 ;
    END
  END b_d[169]
  PIN b_d[16]
    DIRECTION OUTPUT ;
    USE SIGNAL ;
    PORT
      LAYER M5 ;
        RECT  14.544 0 14.568 0.084 ;
    END
  END b_d[16]
  PIN b_d[170]
    DIRECTION OUTPUT ;
    USE SIGNAL ;
    PORT
      LAYER M5 ;
        RECT  21.936 0 21.96 0.084 ;
    END
  END b_d[170]
  PIN b_d[171]
    DIRECTION OUTPUT ;
    USE SIGNAL ;
    PORT
      LAYER M5 ;
        RECT  21.984 0 22.008 0.084 ;
    END
  END b_d[171]
  PIN b_d[172]
    DIRECTION OUTPUT ;
    USE SIGNAL ;
    PORT
      LAYER M5 ;
        RECT  22.032 0 22.056 0.084 ;
    END
  END b_d[172]
  PIN b_d[173]
    DIRECTION OUTPUT ;
    USE SIGNAL ;
    PORT
      LAYER M5 ;
        RECT  22.08 0 22.104 0.084 ;
    END
  END b_d[173]
  PIN b_d[174]
    DIRECTION OUTPUT ;
    USE SIGNAL ;
    PORT
      LAYER M5 ;
        RECT  22.128 0 22.152 0.084 ;
    END
  END b_d[174]
  PIN b_d[175]
    DIRECTION OUTPUT ;
    USE SIGNAL ;
    PORT
      LAYER M5 ;
        RECT  22.176 0 22.2 0.084 ;
    END
  END b_d[175]
  PIN b_d[176]
    DIRECTION OUTPUT ;
    USE SIGNAL ;
    PORT
      LAYER M5 ;
        RECT  22.224 0 22.248 0.084 ;
    END
  END b_d[176]
  PIN b_d[177]
    DIRECTION OUTPUT ;
    USE SIGNAL ;
    PORT
      LAYER M5 ;
        RECT  22.272 0 22.296 0.084 ;
    END
  END b_d[177]
  PIN b_d[178]
    DIRECTION OUTPUT ;
    USE SIGNAL ;
    PORT
      LAYER M5 ;
        RECT  22.32 0 22.344 0.084 ;
    END
  END b_d[178]
  PIN b_d[179]
    DIRECTION OUTPUT ;
    USE SIGNAL ;
    PORT
      LAYER M5 ;
        RECT  22.368 0 22.392 0.084 ;
    END
  END b_d[179]
  PIN b_d[17]
    DIRECTION OUTPUT ;
    USE SIGNAL ;
    PORT
      LAYER M5 ;
        RECT  14.592 0 14.616 0.084 ;
    END
  END b_d[17]
  PIN b_d[180]
    DIRECTION OUTPUT ;
    USE SIGNAL ;
    PORT
      LAYER M5 ;
        RECT  22.416 0 22.44 0.084 ;
    END
  END b_d[180]
  PIN b_d[181]
    DIRECTION OUTPUT ;
    USE SIGNAL ;
    PORT
      LAYER M5 ;
        RECT  22.464 0 22.488 0.084 ;
    END
  END b_d[181]
  PIN b_d[182]
    DIRECTION OUTPUT ;
    USE SIGNAL ;
    PORT
      LAYER M5 ;
        RECT  22.512 0 22.536 0.084 ;
    END
  END b_d[182]
  PIN b_d[183]
    DIRECTION OUTPUT ;
    USE SIGNAL ;
    PORT
      LAYER M5 ;
        RECT  22.56 0 22.584 0.084 ;
    END
  END b_d[183]
  PIN b_d[184]
    DIRECTION OUTPUT ;
    USE SIGNAL ;
    PORT
      LAYER M5 ;
        RECT  22.608 0 22.632 0.084 ;
    END
  END b_d[184]
  PIN b_d[185]
    DIRECTION OUTPUT ;
    USE SIGNAL ;
    PORT
      LAYER M5 ;
        RECT  22.656 0 22.68 0.084 ;
    END
  END b_d[185]
  PIN b_d[186]
    DIRECTION OUTPUT ;
    USE SIGNAL ;
    PORT
      LAYER M5 ;
        RECT  22.704 0 22.728 0.084 ;
    END
  END b_d[186]
  PIN b_d[187]
    DIRECTION OUTPUT ;
    USE SIGNAL ;
    PORT
      LAYER M5 ;
        RECT  22.752 0 22.776 0.084 ;
    END
  END b_d[187]
  PIN b_d[188]
    DIRECTION OUTPUT ;
    USE SIGNAL ;
    PORT
      LAYER M5 ;
        RECT  22.8 0 22.824 0.084 ;
    END
  END b_d[188]
  PIN b_d[189]
    DIRECTION OUTPUT ;
    USE SIGNAL ;
    PORT
      LAYER M5 ;
        RECT  22.848 0 22.872 0.084 ;
    END
  END b_d[189]
  PIN b_d[18]
    DIRECTION OUTPUT ;
    USE SIGNAL ;
    PORT
      LAYER M5 ;
        RECT  14.64 0 14.664 0.084 ;
    END
  END b_d[18]
  PIN b_d[190]
    DIRECTION OUTPUT ;
    USE SIGNAL ;
    PORT
      LAYER M5 ;
        RECT  22.896 0 22.92 0.084 ;
    END
  END b_d[190]
  PIN b_d[191]
    DIRECTION OUTPUT ;
    USE SIGNAL ;
    PORT
      LAYER M5 ;
        RECT  22.944 0 22.968 0.084 ;
    END
  END b_d[191]
  PIN b_d[192]
    DIRECTION OUTPUT ;
    USE SIGNAL ;
    PORT
      LAYER M5 ;
        RECT  22.992 0 23.016 0.084 ;
    END
  END b_d[192]
  PIN b_d[193]
    DIRECTION OUTPUT ;
    USE SIGNAL ;
    PORT
      LAYER M5 ;
        RECT  23.04 0 23.064 0.084 ;
    END
  END b_d[193]
  PIN b_d[194]
    DIRECTION OUTPUT ;
    USE SIGNAL ;
    PORT
      LAYER M5 ;
        RECT  23.088 0 23.112 0.084 ;
    END
  END b_d[194]
  PIN b_d[195]
    DIRECTION OUTPUT ;
    USE SIGNAL ;
    PORT
      LAYER M5 ;
        RECT  23.136 0 23.16 0.084 ;
    END
  END b_d[195]
  PIN b_d[196]
    DIRECTION OUTPUT ;
    USE SIGNAL ;
    PORT
      LAYER M5 ;
        RECT  23.184 0 23.208 0.084 ;
    END
  END b_d[196]
  PIN b_d[197]
    DIRECTION OUTPUT ;
    USE SIGNAL ;
    PORT
      LAYER M5 ;
        RECT  23.232 0 23.256 0.084 ;
    END
  END b_d[197]
  PIN b_d[198]
    DIRECTION OUTPUT ;
    USE SIGNAL ;
    PORT
      LAYER M5 ;
        RECT  23.28 0 23.304 0.084 ;
    END
  END b_d[198]
  PIN b_d[199]
    DIRECTION OUTPUT ;
    USE SIGNAL ;
    PORT
      LAYER M5 ;
        RECT  23.328 0 23.352 0.084 ;
    END
  END b_d[199]
  PIN b_d[19]
    DIRECTION OUTPUT ;
    USE SIGNAL ;
    PORT
      LAYER M5 ;
        RECT  14.688 0 14.712 0.084 ;
    END
  END b_d[19]
  PIN b_d[1]
    DIRECTION OUTPUT ;
    USE SIGNAL ;
    PORT
      LAYER M5 ;
        RECT  13.824 0 13.848 0.084 ;
    END
  END b_d[1]
  PIN b_d[200]
    DIRECTION OUTPUT ;
    USE SIGNAL ;
    PORT
      LAYER M5 ;
        RECT  23.376 0 23.4 0.084 ;
    END
  END b_d[200]
  PIN b_d[201]
    DIRECTION OUTPUT ;
    USE SIGNAL ;
    PORT
      LAYER M5 ;
        RECT  23.424 0 23.448 0.084 ;
    END
  END b_d[201]
  PIN b_d[202]
    DIRECTION OUTPUT ;
    USE SIGNAL ;
    PORT
      LAYER M5 ;
        RECT  23.472 0 23.496 0.084 ;
    END
  END b_d[202]
  PIN b_d[203]
    DIRECTION OUTPUT ;
    USE SIGNAL ;
    PORT
      LAYER M5 ;
        RECT  23.52 0 23.544 0.084 ;
    END
  END b_d[203]
  PIN b_d[204]
    DIRECTION OUTPUT ;
    USE SIGNAL ;
    PORT
      LAYER M5 ;
        RECT  23.568 0 23.592 0.084 ;
    END
  END b_d[204]
  PIN b_d[205]
    DIRECTION OUTPUT ;
    USE SIGNAL ;
    PORT
      LAYER M5 ;
        RECT  23.616 0 23.64 0.084 ;
    END
  END b_d[205]
  PIN b_d[206]
    DIRECTION OUTPUT ;
    USE SIGNAL ;
    PORT
      LAYER M5 ;
        RECT  23.664 0 23.688 0.084 ;
    END
  END b_d[206]
  PIN b_d[207]
    DIRECTION OUTPUT ;
    USE SIGNAL ;
    PORT
      LAYER M5 ;
        RECT  23.712 0 23.736 0.084 ;
    END
  END b_d[207]
  PIN b_d[208]
    DIRECTION OUTPUT ;
    USE SIGNAL ;
    PORT
      LAYER M5 ;
        RECT  23.76 0 23.784 0.084 ;
    END
  END b_d[208]
  PIN b_d[209]
    DIRECTION OUTPUT ;
    USE SIGNAL ;
    PORT
      LAYER M5 ;
        RECT  23.808 0 23.832 0.084 ;
    END
  END b_d[209]
  PIN b_d[20]
    DIRECTION OUTPUT ;
    USE SIGNAL ;
    PORT
      LAYER M5 ;
        RECT  14.736 0 14.76 0.084 ;
    END
  END b_d[20]
  PIN b_d[210]
    DIRECTION OUTPUT ;
    USE SIGNAL ;
    PORT
      LAYER M5 ;
        RECT  23.856 0 23.88 0.084 ;
    END
  END b_d[210]
  PIN b_d[211]
    DIRECTION OUTPUT ;
    USE SIGNAL ;
    PORT
      LAYER M5 ;
        RECT  23.904 0 23.928 0.084 ;
    END
  END b_d[211]
  PIN b_d[212]
    DIRECTION OUTPUT ;
    USE SIGNAL ;
    PORT
      LAYER M5 ;
        RECT  23.952 0 23.976 0.084 ;
    END
  END b_d[212]
  PIN b_d[213]
    DIRECTION OUTPUT ;
    USE SIGNAL ;
    PORT
      LAYER M5 ;
        RECT  24 0 24.024 0.084 ;
    END
  END b_d[213]
  PIN b_d[214]
    DIRECTION OUTPUT ;
    USE SIGNAL ;
    PORT
      LAYER M5 ;
        RECT  24.048 0 24.072 0.084 ;
    END
  END b_d[214]
  PIN b_d[215]
    DIRECTION OUTPUT ;
    USE SIGNAL ;
    PORT
      LAYER M5 ;
        RECT  24.096 0 24.12 0.084 ;
    END
  END b_d[215]
  PIN b_d[216]
    DIRECTION OUTPUT ;
    USE SIGNAL ;
    PORT
      LAYER M5 ;
        RECT  24.144 0 24.168 0.084 ;
    END
  END b_d[216]
  PIN b_d[217]
    DIRECTION OUTPUT ;
    USE SIGNAL ;
    PORT
      LAYER M5 ;
        RECT  24.192 0 24.216 0.084 ;
    END
  END b_d[217]
  PIN b_d[218]
    DIRECTION OUTPUT ;
    USE SIGNAL ;
    PORT
      LAYER M5 ;
        RECT  24.24 0 24.264 0.084 ;
    END
  END b_d[218]
  PIN b_d[219]
    DIRECTION OUTPUT ;
    USE SIGNAL ;
    PORT
      LAYER M5 ;
        RECT  24.288 0 24.312 0.084 ;
    END
  END b_d[219]
  PIN b_d[21]
    DIRECTION OUTPUT ;
    USE SIGNAL ;
    PORT
      LAYER M5 ;
        RECT  14.784 0 14.808 0.084 ;
    END
  END b_d[21]
  PIN b_d[220]
    DIRECTION OUTPUT ;
    USE SIGNAL ;
    PORT
      LAYER M5 ;
        RECT  24.336 0 24.36 0.084 ;
    END
  END b_d[220]
  PIN b_d[221]
    DIRECTION OUTPUT ;
    USE SIGNAL ;
    PORT
      LAYER M5 ;
        RECT  24.384 0 24.408 0.084 ;
    END
  END b_d[221]
  PIN b_d[222]
    DIRECTION OUTPUT ;
    USE SIGNAL ;
    PORT
      LAYER M5 ;
        RECT  24.432 0 24.456 0.084 ;
    END
  END b_d[222]
  PIN b_d[223]
    DIRECTION OUTPUT ;
    USE SIGNAL ;
    PORT
      LAYER M5 ;
        RECT  24.48 0 24.504 0.084 ;
    END
  END b_d[223]
  PIN b_d[224]
    DIRECTION OUTPUT ;
    USE SIGNAL ;
    PORT
      LAYER M5 ;
        RECT  24.528 0 24.552 0.084 ;
    END
  END b_d[224]
  PIN b_d[225]
    DIRECTION OUTPUT ;
    USE SIGNAL ;
    PORT
      LAYER M5 ;
        RECT  24.576 0 24.6 0.084 ;
    END
  END b_d[225]
  PIN b_d[226]
    DIRECTION OUTPUT ;
    USE SIGNAL ;
    PORT
      LAYER M5 ;
        RECT  24.624 0 24.648 0.084 ;
    END
  END b_d[226]
  PIN b_d[227]
    DIRECTION OUTPUT ;
    USE SIGNAL ;
    PORT
      LAYER M5 ;
        RECT  24.672 0 24.696 0.084 ;
    END
  END b_d[227]
  PIN b_d[228]
    DIRECTION OUTPUT ;
    USE SIGNAL ;
    PORT
      LAYER M5 ;
        RECT  24.72 0 24.744 0.084 ;
    END
  END b_d[228]
  PIN b_d[229]
    DIRECTION OUTPUT ;
    USE SIGNAL ;
    PORT
      LAYER M5 ;
        RECT  24.768 0 24.792 0.084 ;
    END
  END b_d[229]
  PIN b_d[22]
    DIRECTION OUTPUT ;
    USE SIGNAL ;
    PORT
      LAYER M5 ;
        RECT  14.832 0 14.856 0.084 ;
    END
  END b_d[22]
  PIN b_d[230]
    DIRECTION OUTPUT ;
    USE SIGNAL ;
    PORT
      LAYER M5 ;
        RECT  24.816 0 24.84 0.084 ;
    END
  END b_d[230]
  PIN b_d[231]
    DIRECTION OUTPUT ;
    USE SIGNAL ;
    PORT
      LAYER M5 ;
        RECT  24.864 0 24.888 0.084 ;
    END
  END b_d[231]
  PIN b_d[232]
    DIRECTION OUTPUT ;
    USE SIGNAL ;
    PORT
      LAYER M5 ;
        RECT  24.912 0 24.936 0.084 ;
    END
  END b_d[232]
  PIN b_d[233]
    DIRECTION OUTPUT ;
    USE SIGNAL ;
    PORT
      LAYER M5 ;
        RECT  24.96 0 24.984 0.084 ;
    END
  END b_d[233]
  PIN b_d[234]
    DIRECTION OUTPUT ;
    USE SIGNAL ;
    PORT
      LAYER M5 ;
        RECT  25.008 0 25.032 0.084 ;
    END
  END b_d[234]
  PIN b_d[235]
    DIRECTION OUTPUT ;
    USE SIGNAL ;
    PORT
      LAYER M5 ;
        RECT  25.056 0 25.08 0.084 ;
    END
  END b_d[235]
  PIN b_d[236]
    DIRECTION OUTPUT ;
    USE SIGNAL ;
    PORT
      LAYER M5 ;
        RECT  25.104 0 25.128 0.084 ;
    END
  END b_d[236]
  PIN b_d[237]
    DIRECTION OUTPUT ;
    USE SIGNAL ;
    PORT
      LAYER M5 ;
        RECT  25.152 0 25.176 0.084 ;
    END
  END b_d[237]
  PIN b_d[238]
    DIRECTION OUTPUT ;
    USE SIGNAL ;
    PORT
      LAYER M5 ;
        RECT  25.2 0 25.224 0.084 ;
    END
  END b_d[238]
  PIN b_d[239]
    DIRECTION OUTPUT ;
    USE SIGNAL ;
    PORT
      LAYER M5 ;
        RECT  25.248 0 25.272 0.084 ;
    END
  END b_d[239]
  PIN b_d[23]
    DIRECTION OUTPUT ;
    USE SIGNAL ;
    PORT
      LAYER M5 ;
        RECT  14.88 0 14.904 0.084 ;
    END
  END b_d[23]
  PIN b_d[240]
    DIRECTION OUTPUT ;
    USE SIGNAL ;
    PORT
      LAYER M5 ;
        RECT  25.296 0 25.32 0.084 ;
    END
  END b_d[240]
  PIN b_d[241]
    DIRECTION OUTPUT ;
    USE SIGNAL ;
    PORT
      LAYER M5 ;
        RECT  25.344 0 25.368 0.084 ;
    END
  END b_d[241]
  PIN b_d[242]
    DIRECTION OUTPUT ;
    USE SIGNAL ;
    PORT
      LAYER M5 ;
        RECT  25.392 0 25.416 0.084 ;
    END
  END b_d[242]
  PIN b_d[243]
    DIRECTION OUTPUT ;
    USE SIGNAL ;
    PORT
      LAYER M5 ;
        RECT  25.44 0 25.464 0.084 ;
    END
  END b_d[243]
  PIN b_d[244]
    DIRECTION OUTPUT ;
    USE SIGNAL ;
    PORT
      LAYER M5 ;
        RECT  25.488 0 25.512 0.084 ;
    END
  END b_d[244]
  PIN b_d[245]
    DIRECTION OUTPUT ;
    USE SIGNAL ;
    PORT
      LAYER M5 ;
        RECT  25.536 0 25.56 0.084 ;
    END
  END b_d[245]
  PIN b_d[246]
    DIRECTION OUTPUT ;
    USE SIGNAL ;
    PORT
      LAYER M5 ;
        RECT  25.584 0 25.608 0.084 ;
    END
  END b_d[246]
  PIN b_d[247]
    DIRECTION OUTPUT ;
    USE SIGNAL ;
    PORT
      LAYER M5 ;
        RECT  25.632 0 25.656 0.084 ;
    END
  END b_d[247]
  PIN b_d[248]
    DIRECTION OUTPUT ;
    USE SIGNAL ;
    PORT
      LAYER M5 ;
        RECT  25.68 0 25.704 0.084 ;
    END
  END b_d[248]
  PIN b_d[249]
    DIRECTION OUTPUT ;
    USE SIGNAL ;
    PORT
      LAYER M5 ;
        RECT  25.728 0 25.752 0.084 ;
    END
  END b_d[249]
  PIN b_d[24]
    DIRECTION OUTPUT ;
    USE SIGNAL ;
    PORT
      LAYER M5 ;
        RECT  14.928 0 14.952 0.084 ;
    END
  END b_d[24]
  PIN b_d[250]
    DIRECTION OUTPUT ;
    USE SIGNAL ;
    PORT
      LAYER M5 ;
        RECT  25.776 0 25.8 0.084 ;
    END
  END b_d[250]
  PIN b_d[251]
    DIRECTION OUTPUT ;
    USE SIGNAL ;
    PORT
      LAYER M5 ;
        RECT  25.824 0 25.848 0.084 ;
    END
  END b_d[251]
  PIN b_d[252]
    DIRECTION OUTPUT ;
    USE SIGNAL ;
    PORT
      LAYER M5 ;
        RECT  25.872 0 25.896 0.084 ;
    END
  END b_d[252]
  PIN b_d[253]
    DIRECTION OUTPUT ;
    USE SIGNAL ;
    PORT
      LAYER M5 ;
        RECT  25.92 0 25.944 0.084 ;
    END
  END b_d[253]
  PIN b_d[254]
    DIRECTION OUTPUT ;
    USE SIGNAL ;
    PORT
      LAYER M5 ;
        RECT  25.968 0 25.992 0.084 ;
    END
  END b_d[254]
  PIN b_d[255]
    DIRECTION OUTPUT ;
    USE SIGNAL ;
    PORT
      LAYER M5 ;
        RECT  26.016 0 26.04 0.084 ;
    END
  END b_d[255]
  PIN b_d[256]
    DIRECTION OUTPUT ;
    USE SIGNAL ;
    PORT
      LAYER M5 ;
        RECT  26.064 0 26.088 0.084 ;
    END
  END b_d[256]
  PIN b_d[257]
    DIRECTION OUTPUT ;
    USE SIGNAL ;
    PORT
      LAYER M5 ;
        RECT  26.112 0 26.136 0.084 ;
    END
  END b_d[257]
  PIN b_d[258]
    DIRECTION OUTPUT ;
    USE SIGNAL ;
    PORT
      LAYER M5 ;
        RECT  26.16 0 26.184 0.084 ;
    END
  END b_d[258]
  PIN b_d[259]
    DIRECTION OUTPUT ;
    USE SIGNAL ;
    PORT
      LAYER M5 ;
        RECT  26.208 0 26.232 0.084 ;
    END
  END b_d[259]
  PIN b_d[25]
    DIRECTION OUTPUT ;
    USE SIGNAL ;
    PORT
      LAYER M5 ;
        RECT  14.976 0 15 0.084 ;
    END
  END b_d[25]
  PIN b_d[260]
    DIRECTION OUTPUT ;
    USE SIGNAL ;
    PORT
      LAYER M5 ;
        RECT  26.256 0 26.28 0.084 ;
    END
  END b_d[260]
  PIN b_d[261]
    DIRECTION OUTPUT ;
    USE SIGNAL ;
    PORT
      LAYER M5 ;
        RECT  26.304 0 26.328 0.084 ;
    END
  END b_d[261]
  PIN b_d[262]
    DIRECTION OUTPUT ;
    USE SIGNAL ;
    PORT
      LAYER M5 ;
        RECT  26.352 0 26.376 0.084 ;
    END
  END b_d[262]
  PIN b_d[263]
    DIRECTION OUTPUT ;
    USE SIGNAL ;
    PORT
      LAYER M5 ;
        RECT  26.4 0 26.424 0.084 ;
    END
  END b_d[263]
  PIN b_d[264]
    DIRECTION OUTPUT ;
    USE SIGNAL ;
    PORT
      LAYER M5 ;
        RECT  26.448 0 26.472 0.084 ;
    END
  END b_d[264]
  PIN b_d[265]
    DIRECTION OUTPUT ;
    USE SIGNAL ;
    PORT
      LAYER M5 ;
        RECT  26.496 0 26.52 0.084 ;
    END
  END b_d[265]
  PIN b_d[266]
    DIRECTION OUTPUT ;
    USE SIGNAL ;
    PORT
      LAYER M5 ;
        RECT  26.544 0 26.568 0.084 ;
    END
  END b_d[266]
  PIN b_d[267]
    DIRECTION OUTPUT ;
    USE SIGNAL ;
    PORT
      LAYER M5 ;
        RECT  26.592 0 26.616 0.084 ;
    END
  END b_d[267]
  PIN b_d[268]
    DIRECTION OUTPUT ;
    USE SIGNAL ;
    PORT
      LAYER M5 ;
        RECT  26.64 0 26.664 0.084 ;
    END
  END b_d[268]
  PIN b_d[269]
    DIRECTION OUTPUT ;
    USE SIGNAL ;
    PORT
      LAYER M5 ;
        RECT  26.688 0 26.712 0.084 ;
    END
  END b_d[269]
  PIN b_d[26]
    DIRECTION OUTPUT ;
    USE SIGNAL ;
    PORT
      LAYER M5 ;
        RECT  15.024 0 15.048 0.084 ;
    END
  END b_d[26]
  PIN b_d[270]
    DIRECTION OUTPUT ;
    USE SIGNAL ;
    PORT
      LAYER M5 ;
        RECT  26.736 0 26.76 0.084 ;
    END
  END b_d[270]
  PIN b_d[271]
    DIRECTION OUTPUT ;
    USE SIGNAL ;
    PORT
      LAYER M5 ;
        RECT  26.784 0 26.808 0.084 ;
    END
  END b_d[271]
  PIN b_d[272]
    DIRECTION OUTPUT ;
    USE SIGNAL ;
    PORT
      LAYER M5 ;
        RECT  26.832 0 26.856 0.084 ;
    END
  END b_d[272]
  PIN b_d[273]
    DIRECTION OUTPUT ;
    USE SIGNAL ;
    PORT
      LAYER M5 ;
        RECT  26.88 0 26.904 0.084 ;
    END
  END b_d[273]
  PIN b_d[274]
    DIRECTION OUTPUT ;
    USE SIGNAL ;
    PORT
      LAYER M5 ;
        RECT  26.928 0 26.952 0.084 ;
    END
  END b_d[274]
  PIN b_d[275]
    DIRECTION OUTPUT ;
    USE SIGNAL ;
    PORT
      LAYER M5 ;
        RECT  26.976 0 27 0.084 ;
    END
  END b_d[275]
  PIN b_d[276]
    DIRECTION OUTPUT ;
    USE SIGNAL ;
    PORT
      LAYER M5 ;
        RECT  27.024 0 27.048 0.084 ;
    END
  END b_d[276]
  PIN b_d[277]
    DIRECTION OUTPUT ;
    USE SIGNAL ;
    PORT
      LAYER M5 ;
        RECT  27.072 0 27.096 0.084 ;
    END
  END b_d[277]
  PIN b_d[278]
    DIRECTION OUTPUT ;
    USE SIGNAL ;
    PORT
      LAYER M5 ;
        RECT  27.12 0 27.144 0.084 ;
    END
  END b_d[278]
  PIN b_d[279]
    DIRECTION OUTPUT ;
    USE SIGNAL ;
    PORT
      LAYER M5 ;
        RECT  27.168 0 27.192 0.084 ;
    END
  END b_d[279]
  PIN b_d[27]
    DIRECTION OUTPUT ;
    USE SIGNAL ;
    PORT
      LAYER M5 ;
        RECT  15.072 0 15.096 0.084 ;
    END
  END b_d[27]
  PIN b_d[280]
    DIRECTION OUTPUT ;
    USE SIGNAL ;
    PORT
      LAYER M5 ;
        RECT  27.216 0 27.24 0.084 ;
    END
  END b_d[280]
  PIN b_d[281]
    DIRECTION OUTPUT ;
    USE SIGNAL ;
    PORT
      LAYER M5 ;
        RECT  27.264 0 27.288 0.084 ;
    END
  END b_d[281]
  PIN b_d[282]
    DIRECTION OUTPUT ;
    USE SIGNAL ;
    PORT
      LAYER M5 ;
        RECT  27.312 0 27.336 0.084 ;
    END
  END b_d[282]
  PIN b_d[283]
    DIRECTION OUTPUT ;
    USE SIGNAL ;
    PORT
      LAYER M5 ;
        RECT  27.36 0 27.384 0.084 ;
    END
  END b_d[283]
  PIN b_d[284]
    DIRECTION OUTPUT ;
    USE SIGNAL ;
    PORT
      LAYER M5 ;
        RECT  27.408 0 27.432 0.084 ;
    END
  END b_d[284]
  PIN b_d[285]
    DIRECTION OUTPUT ;
    USE SIGNAL ;
    PORT
      LAYER M5 ;
        RECT  27.456 0 27.48 0.084 ;
    END
  END b_d[285]
  PIN b_d[286]
    DIRECTION OUTPUT ;
    USE SIGNAL ;
    PORT
      LAYER M5 ;
        RECT  27.504 0 27.528 0.084 ;
    END
  END b_d[286]
  PIN b_d[287]
    DIRECTION OUTPUT ;
    USE SIGNAL ;
    PORT
      LAYER M5 ;
        RECT  27.552 0 27.576 0.084 ;
    END
  END b_d[287]
  PIN b_d[288]
    DIRECTION OUTPUT ;
    USE SIGNAL ;
    PORT
      LAYER M5 ;
        RECT  27.6 0 27.624 0.084 ;
    END
  END b_d[288]
  PIN b_d[289]
    DIRECTION OUTPUT ;
    USE SIGNAL ;
    PORT
      LAYER M5 ;
        RECT  27.648 0 27.672 0.084 ;
    END
  END b_d[289]
  PIN b_d[28]
    DIRECTION OUTPUT ;
    USE SIGNAL ;
    PORT
      LAYER M5 ;
        RECT  15.12 0 15.144 0.084 ;
    END
  END b_d[28]
  PIN b_d[290]
    DIRECTION OUTPUT ;
    USE SIGNAL ;
    PORT
      LAYER M5 ;
        RECT  27.696 0 27.72 0.084 ;
    END
  END b_d[290]
  PIN b_d[291]
    DIRECTION OUTPUT ;
    USE SIGNAL ;
    PORT
      LAYER M5 ;
        RECT  27.744 0 27.768 0.084 ;
    END
  END b_d[291]
  PIN b_d[292]
    DIRECTION OUTPUT ;
    USE SIGNAL ;
    PORT
      LAYER M5 ;
        RECT  27.792 0 27.816 0.084 ;
    END
  END b_d[292]
  PIN b_d[293]
    DIRECTION OUTPUT ;
    USE SIGNAL ;
    PORT
      LAYER M5 ;
        RECT  27.84 0 27.864 0.084 ;
    END
  END b_d[293]
  PIN b_d[294]
    DIRECTION OUTPUT ;
    USE SIGNAL ;
    PORT
      LAYER M5 ;
        RECT  27.888 0 27.912 0.084 ;
    END
  END b_d[294]
  PIN b_d[295]
    DIRECTION OUTPUT ;
    USE SIGNAL ;
    PORT
      LAYER M5 ;
        RECT  27.936 0 27.96 0.084 ;
    END
  END b_d[295]
  PIN b_d[296]
    DIRECTION OUTPUT ;
    USE SIGNAL ;
    PORT
      LAYER M5 ;
        RECT  27.984 0 28.008 0.084 ;
    END
  END b_d[296]
  PIN b_d[297]
    DIRECTION OUTPUT ;
    USE SIGNAL ;
    PORT
      LAYER M5 ;
        RECT  28.032 0 28.056 0.084 ;
    END
  END b_d[297]
  PIN b_d[298]
    DIRECTION OUTPUT ;
    USE SIGNAL ;
    PORT
      LAYER M5 ;
        RECT  28.08 0 28.104 0.084 ;
    END
  END b_d[298]
  PIN b_d[299]
    DIRECTION OUTPUT ;
    USE SIGNAL ;
    PORT
      LAYER M5 ;
        RECT  28.128 0 28.152 0.084 ;
    END
  END b_d[299]
  PIN b_d[29]
    DIRECTION OUTPUT ;
    USE SIGNAL ;
    PORT
      LAYER M5 ;
        RECT  15.168 0 15.192 0.084 ;
    END
  END b_d[29]
  PIN b_d[2]
    DIRECTION OUTPUT ;
    USE SIGNAL ;
    PORT
      LAYER M5 ;
        RECT  13.872 0 13.896 0.084 ;
    END
  END b_d[2]
  PIN b_d[300]
    DIRECTION OUTPUT ;
    USE SIGNAL ;
    PORT
      LAYER M5 ;
        RECT  28.176 0 28.2 0.084 ;
    END
  END b_d[300]
  PIN b_d[301]
    DIRECTION OUTPUT ;
    USE SIGNAL ;
    PORT
      LAYER M5 ;
        RECT  28.224 0 28.248 0.084 ;
    END
  END b_d[301]
  PIN b_d[302]
    DIRECTION OUTPUT ;
    USE SIGNAL ;
    PORT
      LAYER M5 ;
        RECT  28.272 0 28.296 0.084 ;
    END
  END b_d[302]
  PIN b_d[303]
    DIRECTION OUTPUT ;
    USE SIGNAL ;
    PORT
      LAYER M5 ;
        RECT  28.32 0 28.344 0.084 ;
    END
  END b_d[303]
  PIN b_d[304]
    DIRECTION OUTPUT ;
    USE SIGNAL ;
    PORT
      LAYER M5 ;
        RECT  28.368 0 28.392 0.084 ;
    END
  END b_d[304]
  PIN b_d[305]
    DIRECTION OUTPUT ;
    USE SIGNAL ;
    PORT
      LAYER M5 ;
        RECT  28.416 0 28.44 0.084 ;
    END
  END b_d[305]
  PIN b_d[306]
    DIRECTION OUTPUT ;
    USE SIGNAL ;
    PORT
      LAYER M5 ;
        RECT  28.464 0 28.488 0.084 ;
    END
  END b_d[306]
  PIN b_d[307]
    DIRECTION OUTPUT ;
    USE SIGNAL ;
    PORT
      LAYER M5 ;
        RECT  28.512 0 28.536 0.084 ;
    END
  END b_d[307]
  PIN b_d[308]
    DIRECTION OUTPUT ;
    USE SIGNAL ;
    PORT
      LAYER M5 ;
        RECT  28.56 0 28.584 0.084 ;
    END
  END b_d[308]
  PIN b_d[309]
    DIRECTION OUTPUT ;
    USE SIGNAL ;
    PORT
      LAYER M5 ;
        RECT  28.608 0 28.632 0.084 ;
    END
  END b_d[309]
  PIN b_d[30]
    DIRECTION OUTPUT ;
    USE SIGNAL ;
    PORT
      LAYER M5 ;
        RECT  15.216 0 15.24 0.084 ;
    END
  END b_d[30]
  PIN b_d[310]
    DIRECTION OUTPUT ;
    USE SIGNAL ;
    PORT
      LAYER M5 ;
        RECT  28.656 0 28.68 0.084 ;
    END
  END b_d[310]
  PIN b_d[311]
    DIRECTION OUTPUT ;
    USE SIGNAL ;
    PORT
      LAYER M5 ;
        RECT  28.704 0 28.728 0.084 ;
    END
  END b_d[311]
  PIN b_d[312]
    DIRECTION OUTPUT ;
    USE SIGNAL ;
    PORT
      LAYER M5 ;
        RECT  28.752 0 28.776 0.084 ;
    END
  END b_d[312]
  PIN b_d[313]
    DIRECTION OUTPUT ;
    USE SIGNAL ;
    PORT
      LAYER M5 ;
        RECT  28.8 0 28.824 0.084 ;
    END
  END b_d[313]
  PIN b_d[314]
    DIRECTION OUTPUT ;
    USE SIGNAL ;
    PORT
      LAYER M5 ;
        RECT  28.848 0 28.872 0.084 ;
    END
  END b_d[314]
  PIN b_d[315]
    DIRECTION OUTPUT ;
    USE SIGNAL ;
    PORT
      LAYER M5 ;
        RECT  28.896 0 28.92 0.084 ;
    END
  END b_d[315]
  PIN b_d[316]
    DIRECTION OUTPUT ;
    USE SIGNAL ;
    PORT
      LAYER M5 ;
        RECT  28.944 0 28.968 0.084 ;
    END
  END b_d[316]
  PIN b_d[317]
    DIRECTION OUTPUT ;
    USE SIGNAL ;
    PORT
      LAYER M5 ;
        RECT  28.992 0 29.016 0.084 ;
    END
  END b_d[317]
  PIN b_d[318]
    DIRECTION OUTPUT ;
    USE SIGNAL ;
    PORT
      LAYER M5 ;
        RECT  29.04 0 29.064 0.084 ;
    END
  END b_d[318]
  PIN b_d[319]
    DIRECTION OUTPUT ;
    USE SIGNAL ;
    PORT
      LAYER M5 ;
        RECT  29.088 0 29.112 0.084 ;
    END
  END b_d[319]
  PIN b_d[31]
    DIRECTION OUTPUT ;
    USE SIGNAL ;
    PORT
      LAYER M5 ;
        RECT  15.264 0 15.288 0.084 ;
    END
  END b_d[31]
  PIN b_d[320]
    DIRECTION OUTPUT ;
    USE SIGNAL ;
    PORT
      LAYER M5 ;
        RECT  29.136 0 29.16 0.084 ;
    END
  END b_d[320]
  PIN b_d[321]
    DIRECTION OUTPUT ;
    USE SIGNAL ;
    PORT
      LAYER M5 ;
        RECT  29.184 0 29.208 0.084 ;
    END
  END b_d[321]
  PIN b_d[322]
    DIRECTION OUTPUT ;
    USE SIGNAL ;
    PORT
      LAYER M5 ;
        RECT  29.232 0 29.256 0.084 ;
    END
  END b_d[322]
  PIN b_d[323]
    DIRECTION OUTPUT ;
    USE SIGNAL ;
    PORT
      LAYER M5 ;
        RECT  29.28 0 29.304 0.084 ;
    END
  END b_d[323]
  PIN b_d[324]
    DIRECTION OUTPUT ;
    USE SIGNAL ;
    PORT
      LAYER M5 ;
        RECT  29.328 0 29.352 0.084 ;
    END
  END b_d[324]
  PIN b_d[325]
    DIRECTION OUTPUT ;
    USE SIGNAL ;
    PORT
      LAYER M5 ;
        RECT  29.376 0 29.4 0.084 ;
    END
  END b_d[325]
  PIN b_d[326]
    DIRECTION OUTPUT ;
    USE SIGNAL ;
    PORT
      LAYER M5 ;
        RECT  29.424 0 29.448 0.084 ;
    END
  END b_d[326]
  PIN b_d[327]
    DIRECTION OUTPUT ;
    USE SIGNAL ;
    PORT
      LAYER M5 ;
        RECT  29.472 0 29.496 0.084 ;
    END
  END b_d[327]
  PIN b_d[328]
    DIRECTION OUTPUT ;
    USE SIGNAL ;
    PORT
      LAYER M5 ;
        RECT  29.52 0 29.544 0.084 ;
    END
  END b_d[328]
  PIN b_d[329]
    DIRECTION OUTPUT ;
    USE SIGNAL ;
    PORT
      LAYER M5 ;
        RECT  29.568 0 29.592 0.084 ;
    END
  END b_d[329]
  PIN b_d[32]
    DIRECTION OUTPUT ;
    USE SIGNAL ;
    PORT
      LAYER M5 ;
        RECT  15.312 0 15.336 0.084 ;
    END
  END b_d[32]
  PIN b_d[330]
    DIRECTION OUTPUT ;
    USE SIGNAL ;
    PORT
      LAYER M5 ;
        RECT  29.616 0 29.64 0.084 ;
    END
  END b_d[330]
  PIN b_d[331]
    DIRECTION OUTPUT ;
    USE SIGNAL ;
    PORT
      LAYER M5 ;
        RECT  29.664 0 29.688 0.084 ;
    END
  END b_d[331]
  PIN b_d[332]
    DIRECTION OUTPUT ;
    USE SIGNAL ;
    PORT
      LAYER M5 ;
        RECT  29.712 0 29.736 0.084 ;
    END
  END b_d[332]
  PIN b_d[333]
    DIRECTION OUTPUT ;
    USE SIGNAL ;
    PORT
      LAYER M5 ;
        RECT  29.76 0 29.784 0.084 ;
    END
  END b_d[333]
  PIN b_d[334]
    DIRECTION OUTPUT ;
    USE SIGNAL ;
    PORT
      LAYER M5 ;
        RECT  29.808 0 29.832 0.084 ;
    END
  END b_d[334]
  PIN b_d[335]
    DIRECTION OUTPUT ;
    USE SIGNAL ;
    PORT
      LAYER M5 ;
        RECT  29.856 0 29.88 0.084 ;
    END
  END b_d[335]
  PIN b_d[336]
    DIRECTION OUTPUT ;
    USE SIGNAL ;
    PORT
      LAYER M5 ;
        RECT  29.904 0 29.928 0.084 ;
    END
  END b_d[336]
  PIN b_d[337]
    DIRECTION OUTPUT ;
    USE SIGNAL ;
    PORT
      LAYER M5 ;
        RECT  29.952 0 29.976 0.084 ;
    END
  END b_d[337]
  PIN b_d[338]
    DIRECTION OUTPUT ;
    USE SIGNAL ;
    PORT
      LAYER M5 ;
        RECT  30 0 30.024 0.084 ;
    END
  END b_d[338]
  PIN b_d[339]
    DIRECTION OUTPUT ;
    USE SIGNAL ;
    PORT
      LAYER M5 ;
        RECT  30.048 0 30.072 0.084 ;
    END
  END b_d[339]
  PIN b_d[33]
    DIRECTION OUTPUT ;
    USE SIGNAL ;
    PORT
      LAYER M5 ;
        RECT  15.36 0 15.384 0.084 ;
    END
  END b_d[33]
  PIN b_d[340]
    DIRECTION OUTPUT ;
    USE SIGNAL ;
    PORT
      LAYER M5 ;
        RECT  30.096 0 30.12 0.084 ;
    END
  END b_d[340]
  PIN b_d[341]
    DIRECTION OUTPUT ;
    USE SIGNAL ;
    PORT
      LAYER M5 ;
        RECT  30.144 0 30.168 0.084 ;
    END
  END b_d[341]
  PIN b_d[342]
    DIRECTION OUTPUT ;
    USE SIGNAL ;
    PORT
      LAYER M5 ;
        RECT  30.192 0 30.216 0.084 ;
    END
  END b_d[342]
  PIN b_d[343]
    DIRECTION OUTPUT ;
    USE SIGNAL ;
    PORT
      LAYER M5 ;
        RECT  30.24 0 30.264 0.084 ;
    END
  END b_d[343]
  PIN b_d[344]
    DIRECTION OUTPUT ;
    USE SIGNAL ;
    PORT
      LAYER M5 ;
        RECT  30.288 0 30.312 0.084 ;
    END
  END b_d[344]
  PIN b_d[345]
    DIRECTION OUTPUT ;
    USE SIGNAL ;
    PORT
      LAYER M5 ;
        RECT  30.336 0 30.36 0.084 ;
    END
  END b_d[345]
  PIN b_d[346]
    DIRECTION OUTPUT ;
    USE SIGNAL ;
    PORT
      LAYER M5 ;
        RECT  30.384 0 30.408 0.084 ;
    END
  END b_d[346]
  PIN b_d[347]
    DIRECTION OUTPUT ;
    USE SIGNAL ;
    PORT
      LAYER M5 ;
        RECT  30.432 0 30.456 0.084 ;
    END
  END b_d[347]
  PIN b_d[348]
    DIRECTION OUTPUT ;
    USE SIGNAL ;
    PORT
      LAYER M5 ;
        RECT  30.48 0 30.504 0.084 ;
    END
  END b_d[348]
  PIN b_d[349]
    DIRECTION OUTPUT ;
    USE SIGNAL ;
    PORT
      LAYER M5 ;
        RECT  30.528 0 30.552 0.084 ;
    END
  END b_d[349]
  PIN b_d[34]
    DIRECTION OUTPUT ;
    USE SIGNAL ;
    PORT
      LAYER M5 ;
        RECT  15.408 0 15.432 0.084 ;
    END
  END b_d[34]
  PIN b_d[350]
    DIRECTION OUTPUT ;
    USE SIGNAL ;
    PORT
      LAYER M5 ;
        RECT  30.576 0 30.6 0.084 ;
    END
  END b_d[350]
  PIN b_d[351]
    DIRECTION OUTPUT ;
    USE SIGNAL ;
    PORT
      LAYER M5 ;
        RECT  30.624 0 30.648 0.084 ;
    END
  END b_d[351]
  PIN b_d[352]
    DIRECTION OUTPUT ;
    USE SIGNAL ;
    PORT
      LAYER M5 ;
        RECT  30.672 0 30.696 0.084 ;
    END
  END b_d[352]
  PIN b_d[353]
    DIRECTION OUTPUT ;
    USE SIGNAL ;
    PORT
      LAYER M5 ;
        RECT  30.72 0 30.744 0.084 ;
    END
  END b_d[353]
  PIN b_d[354]
    DIRECTION OUTPUT ;
    USE SIGNAL ;
    PORT
      LAYER M5 ;
        RECT  30.768 0 30.792 0.084 ;
    END
  END b_d[354]
  PIN b_d[355]
    DIRECTION OUTPUT ;
    USE SIGNAL ;
    PORT
      LAYER M5 ;
        RECT  30.816 0 30.84 0.084 ;
    END
  END b_d[355]
  PIN b_d[356]
    DIRECTION OUTPUT ;
    USE SIGNAL ;
    PORT
      LAYER M5 ;
        RECT  30.864 0 30.888 0.084 ;
    END
  END b_d[356]
  PIN b_d[357]
    DIRECTION OUTPUT ;
    USE SIGNAL ;
    PORT
      LAYER M5 ;
        RECT  30.912 0 30.936 0.084 ;
    END
  END b_d[357]
  PIN b_d[358]
    DIRECTION OUTPUT ;
    USE SIGNAL ;
    PORT
      LAYER M5 ;
        RECT  30.96 0 30.984 0.084 ;
    END
  END b_d[358]
  PIN b_d[359]
    DIRECTION OUTPUT ;
    USE SIGNAL ;
    PORT
      LAYER M5 ;
        RECT  31.008 0 31.032 0.084 ;
    END
  END b_d[359]
  PIN b_d[35]
    DIRECTION OUTPUT ;
    USE SIGNAL ;
    PORT
      LAYER M5 ;
        RECT  15.456 0 15.48 0.084 ;
    END
  END b_d[35]
  PIN b_d[360]
    DIRECTION OUTPUT ;
    USE SIGNAL ;
    PORT
      LAYER M5 ;
        RECT  31.056 0 31.08 0.084 ;
    END
  END b_d[360]
  PIN b_d[361]
    DIRECTION OUTPUT ;
    USE SIGNAL ;
    PORT
      LAYER M5 ;
        RECT  31.104 0 31.128 0.084 ;
    END
  END b_d[361]
  PIN b_d[362]
    DIRECTION OUTPUT ;
    USE SIGNAL ;
    PORT
      LAYER M5 ;
        RECT  31.152 0 31.176 0.084 ;
    END
  END b_d[362]
  PIN b_d[363]
    DIRECTION OUTPUT ;
    USE SIGNAL ;
    PORT
      LAYER M5 ;
        RECT  31.2 0 31.224 0.084 ;
    END
  END b_d[363]
  PIN b_d[364]
    DIRECTION OUTPUT ;
    USE SIGNAL ;
    PORT
      LAYER M5 ;
        RECT  31.248 0 31.272 0.084 ;
    END
  END b_d[364]
  PIN b_d[365]
    DIRECTION OUTPUT ;
    USE SIGNAL ;
    PORT
      LAYER M5 ;
        RECT  31.296 0 31.32 0.084 ;
    END
  END b_d[365]
  PIN b_d[366]
    DIRECTION OUTPUT ;
    USE SIGNAL ;
    PORT
      LAYER M5 ;
        RECT  31.344 0 31.368 0.084 ;
    END
  END b_d[366]
  PIN b_d[367]
    DIRECTION OUTPUT ;
    USE SIGNAL ;
    PORT
      LAYER M5 ;
        RECT  31.392 0 31.416 0.084 ;
    END
  END b_d[367]
  PIN b_d[368]
    DIRECTION OUTPUT ;
    USE SIGNAL ;
    PORT
      LAYER M5 ;
        RECT  31.44 0 31.464 0.084 ;
    END
  END b_d[368]
  PIN b_d[369]
    DIRECTION OUTPUT ;
    USE SIGNAL ;
    PORT
      LAYER M5 ;
        RECT  31.488 0 31.512 0.084 ;
    END
  END b_d[369]
  PIN b_d[36]
    DIRECTION OUTPUT ;
    USE SIGNAL ;
    PORT
      LAYER M5 ;
        RECT  15.504 0 15.528 0.084 ;
    END
  END b_d[36]
  PIN b_d[370]
    DIRECTION OUTPUT ;
    USE SIGNAL ;
    PORT
      LAYER M5 ;
        RECT  31.536 0 31.56 0.084 ;
    END
  END b_d[370]
  PIN b_d[371]
    DIRECTION OUTPUT ;
    USE SIGNAL ;
    PORT
      LAYER M5 ;
        RECT  31.584 0 31.608 0.084 ;
    END
  END b_d[371]
  PIN b_d[372]
    DIRECTION OUTPUT ;
    USE SIGNAL ;
    PORT
      LAYER M5 ;
        RECT  31.632 0 31.656 0.084 ;
    END
  END b_d[372]
  PIN b_d[373]
    DIRECTION OUTPUT ;
    USE SIGNAL ;
    PORT
      LAYER M5 ;
        RECT  31.68 0 31.704 0.084 ;
    END
  END b_d[373]
  PIN b_d[374]
    DIRECTION OUTPUT ;
    USE SIGNAL ;
    PORT
      LAYER M5 ;
        RECT  31.728 0 31.752 0.084 ;
    END
  END b_d[374]
  PIN b_d[375]
    DIRECTION OUTPUT ;
    USE SIGNAL ;
    PORT
      LAYER M5 ;
        RECT  31.776 0 31.8 0.084 ;
    END
  END b_d[375]
  PIN b_d[376]
    DIRECTION OUTPUT ;
    USE SIGNAL ;
    PORT
      LAYER M5 ;
        RECT  31.824 0 31.848 0.084 ;
    END
  END b_d[376]
  PIN b_d[377]
    DIRECTION OUTPUT ;
    USE SIGNAL ;
    PORT
      LAYER M5 ;
        RECT  31.872 0 31.896 0.084 ;
    END
  END b_d[377]
  PIN b_d[378]
    DIRECTION OUTPUT ;
    USE SIGNAL ;
    PORT
      LAYER M5 ;
        RECT  31.92 0 31.944 0.084 ;
    END
  END b_d[378]
  PIN b_d[379]
    DIRECTION OUTPUT ;
    USE SIGNAL ;
    PORT
      LAYER M5 ;
        RECT  31.968 0 31.992 0.084 ;
    END
  END b_d[379]
  PIN b_d[37]
    DIRECTION OUTPUT ;
    USE SIGNAL ;
    PORT
      LAYER M5 ;
        RECT  15.552 0 15.576 0.084 ;
    END
  END b_d[37]
  PIN b_d[380]
    DIRECTION OUTPUT ;
    USE SIGNAL ;
    PORT
      LAYER M5 ;
        RECT  32.016 0 32.04 0.084 ;
    END
  END b_d[380]
  PIN b_d[381]
    DIRECTION OUTPUT ;
    USE SIGNAL ;
    PORT
      LAYER M5 ;
        RECT  32.064 0 32.088 0.084 ;
    END
  END b_d[381]
  PIN b_d[382]
    DIRECTION OUTPUT ;
    USE SIGNAL ;
    PORT
      LAYER M5 ;
        RECT  32.112 0 32.136 0.084 ;
    END
  END b_d[382]
  PIN b_d[383]
    DIRECTION OUTPUT ;
    USE SIGNAL ;
    PORT
      LAYER M5 ;
        RECT  32.16 0 32.184 0.084 ;
    END
  END b_d[383]
  PIN b_d[384]
    DIRECTION OUTPUT ;
    USE SIGNAL ;
    PORT
      LAYER M5 ;
        RECT  32.208 0 32.232 0.084 ;
    END
  END b_d[384]
  PIN b_d[385]
    DIRECTION OUTPUT ;
    USE SIGNAL ;
    PORT
      LAYER M5 ;
        RECT  32.256 0 32.28 0.084 ;
    END
  END b_d[385]
  PIN b_d[386]
    DIRECTION OUTPUT ;
    USE SIGNAL ;
    PORT
      LAYER M5 ;
        RECT  32.304 0 32.328 0.084 ;
    END
  END b_d[386]
  PIN b_d[387]
    DIRECTION OUTPUT ;
    USE SIGNAL ;
    PORT
      LAYER M5 ;
        RECT  32.352 0 32.376 0.084 ;
    END
  END b_d[387]
  PIN b_d[388]
    DIRECTION OUTPUT ;
    USE SIGNAL ;
    PORT
      LAYER M5 ;
        RECT  32.4 0 32.424 0.084 ;
    END
  END b_d[388]
  PIN b_d[389]
    DIRECTION OUTPUT ;
    USE SIGNAL ;
    PORT
      LAYER M5 ;
        RECT  32.448 0 32.472 0.084 ;
    END
  END b_d[389]
  PIN b_d[38]
    DIRECTION OUTPUT ;
    USE SIGNAL ;
    PORT
      LAYER M5 ;
        RECT  15.6 0 15.624 0.084 ;
    END
  END b_d[38]
  PIN b_d[390]
    DIRECTION OUTPUT ;
    USE SIGNAL ;
    PORT
      LAYER M5 ;
        RECT  32.496 0 32.52 0.084 ;
    END
  END b_d[390]
  PIN b_d[391]
    DIRECTION OUTPUT ;
    USE SIGNAL ;
    PORT
      LAYER M5 ;
        RECT  32.544 0 32.568 0.084 ;
    END
  END b_d[391]
  PIN b_d[392]
    DIRECTION OUTPUT ;
    USE SIGNAL ;
    PORT
      LAYER M5 ;
        RECT  32.592 0 32.616 0.084 ;
    END
  END b_d[392]
  PIN b_d[393]
    DIRECTION OUTPUT ;
    USE SIGNAL ;
    PORT
      LAYER M5 ;
        RECT  32.64 0 32.664 0.084 ;
    END
  END b_d[393]
  PIN b_d[394]
    DIRECTION OUTPUT ;
    USE SIGNAL ;
    PORT
      LAYER M5 ;
        RECT  32.688 0 32.712 0.084 ;
    END
  END b_d[394]
  PIN b_d[395]
    DIRECTION OUTPUT ;
    USE SIGNAL ;
    PORT
      LAYER M5 ;
        RECT  32.736 0 32.76 0.084 ;
    END
  END b_d[395]
  PIN b_d[396]
    DIRECTION OUTPUT ;
    USE SIGNAL ;
    PORT
      LAYER M5 ;
        RECT  32.784 0 32.808 0.084 ;
    END
  END b_d[396]
  PIN b_d[397]
    DIRECTION OUTPUT ;
    USE SIGNAL ;
    PORT
      LAYER M5 ;
        RECT  32.832 0 32.856 0.084 ;
    END
  END b_d[397]
  PIN b_d[398]
    DIRECTION OUTPUT ;
    USE SIGNAL ;
    PORT
      LAYER M5 ;
        RECT  32.88 0 32.904 0.084 ;
    END
  END b_d[398]
  PIN b_d[399]
    DIRECTION OUTPUT ;
    USE SIGNAL ;
    PORT
      LAYER M5 ;
        RECT  32.928 0 32.952 0.084 ;
    END
  END b_d[399]
  PIN b_d[39]
    DIRECTION OUTPUT ;
    USE SIGNAL ;
    PORT
      LAYER M5 ;
        RECT  15.648 0 15.672 0.084 ;
    END
  END b_d[39]
  PIN b_d[3]
    DIRECTION OUTPUT ;
    USE SIGNAL ;
    PORT
      LAYER M5 ;
        RECT  13.92 0 13.944 0.084 ;
    END
  END b_d[3]
  PIN b_d[400]
    DIRECTION OUTPUT ;
    USE SIGNAL ;
    PORT
      LAYER M5 ;
        RECT  32.976 0 33 0.084 ;
    END
  END b_d[400]
  PIN b_d[401]
    DIRECTION OUTPUT ;
    USE SIGNAL ;
    PORT
      LAYER M5 ;
        RECT  33.024 0 33.048 0.084 ;
    END
  END b_d[401]
  PIN b_d[402]
    DIRECTION OUTPUT ;
    USE SIGNAL ;
    PORT
      LAYER M5 ;
        RECT  33.072 0 33.096 0.084 ;
    END
  END b_d[402]
  PIN b_d[403]
    DIRECTION OUTPUT ;
    USE SIGNAL ;
    PORT
      LAYER M5 ;
        RECT  33.12 0 33.144 0.084 ;
    END
  END b_d[403]
  PIN b_d[404]
    DIRECTION OUTPUT ;
    USE SIGNAL ;
    PORT
      LAYER M5 ;
        RECT  33.168 0 33.192 0.084 ;
    END
  END b_d[404]
  PIN b_d[405]
    DIRECTION OUTPUT ;
    USE SIGNAL ;
    PORT
      LAYER M5 ;
        RECT  33.216 0 33.24 0.084 ;
    END
  END b_d[405]
  PIN b_d[406]
    DIRECTION OUTPUT ;
    USE SIGNAL ;
    PORT
      LAYER M5 ;
        RECT  33.264 0 33.288 0.084 ;
    END
  END b_d[406]
  PIN b_d[407]
    DIRECTION OUTPUT ;
    USE SIGNAL ;
    PORT
      LAYER M5 ;
        RECT  33.312 0 33.336 0.084 ;
    END
  END b_d[407]
  PIN b_d[408]
    DIRECTION OUTPUT ;
    USE SIGNAL ;
    PORT
      LAYER M5 ;
        RECT  33.36 0 33.384 0.084 ;
    END
  END b_d[408]
  PIN b_d[409]
    DIRECTION OUTPUT ;
    USE SIGNAL ;
    PORT
      LAYER M5 ;
        RECT  33.408 0 33.432 0.084 ;
    END
  END b_d[409]
  PIN b_d[40]
    DIRECTION OUTPUT ;
    USE SIGNAL ;
    PORT
      LAYER M5 ;
        RECT  15.696 0 15.72 0.084 ;
    END
  END b_d[40]
  PIN b_d[410]
    DIRECTION OUTPUT ;
    USE SIGNAL ;
    PORT
      LAYER M5 ;
        RECT  33.456 0 33.48 0.084 ;
    END
  END b_d[410]
  PIN b_d[411]
    DIRECTION OUTPUT ;
    USE SIGNAL ;
    PORT
      LAYER M5 ;
        RECT  33.504 0 33.528 0.084 ;
    END
  END b_d[411]
  PIN b_d[412]
    DIRECTION OUTPUT ;
    USE SIGNAL ;
    PORT
      LAYER M5 ;
        RECT  33.552 0 33.576 0.084 ;
    END
  END b_d[412]
  PIN b_d[413]
    DIRECTION OUTPUT ;
    USE SIGNAL ;
    PORT
      LAYER M5 ;
        RECT  33.6 0 33.624 0.084 ;
    END
  END b_d[413]
  PIN b_d[414]
    DIRECTION OUTPUT ;
    USE SIGNAL ;
    PORT
      LAYER M5 ;
        RECT  33.648 0 33.672 0.084 ;
    END
  END b_d[414]
  PIN b_d[415]
    DIRECTION OUTPUT ;
    USE SIGNAL ;
    PORT
      LAYER M5 ;
        RECT  33.696 0 33.72 0.084 ;
    END
  END b_d[415]
  PIN b_d[416]
    DIRECTION OUTPUT ;
    USE SIGNAL ;
    PORT
      LAYER M5 ;
        RECT  33.744 0 33.768 0.084 ;
    END
  END b_d[416]
  PIN b_d[417]
    DIRECTION OUTPUT ;
    USE SIGNAL ;
    PORT
      LAYER M5 ;
        RECT  33.792 0 33.816 0.084 ;
    END
  END b_d[417]
  PIN b_d[418]
    DIRECTION OUTPUT ;
    USE SIGNAL ;
    PORT
      LAYER M5 ;
        RECT  33.84 0 33.864 0.084 ;
    END
  END b_d[418]
  PIN b_d[419]
    DIRECTION OUTPUT ;
    USE SIGNAL ;
    PORT
      LAYER M5 ;
        RECT  33.888 0 33.912 0.084 ;
    END
  END b_d[419]
  PIN b_d[41]
    DIRECTION OUTPUT ;
    USE SIGNAL ;
    PORT
      LAYER M5 ;
        RECT  15.744 0 15.768 0.084 ;
    END
  END b_d[41]
  PIN b_d[420]
    DIRECTION OUTPUT ;
    USE SIGNAL ;
    PORT
      LAYER M5 ;
        RECT  33.936 0 33.96 0.084 ;
    END
  END b_d[420]
  PIN b_d[421]
    DIRECTION OUTPUT ;
    USE SIGNAL ;
    PORT
      LAYER M5 ;
        RECT  33.984 0 34.008 0.084 ;
    END
  END b_d[421]
  PIN b_d[422]
    DIRECTION OUTPUT ;
    USE SIGNAL ;
    PORT
      LAYER M5 ;
        RECT  34.032 0 34.056 0.084 ;
    END
  END b_d[422]
  PIN b_d[423]
    DIRECTION OUTPUT ;
    USE SIGNAL ;
    PORT
      LAYER M5 ;
        RECT  34.08 0 34.104 0.084 ;
    END
  END b_d[423]
  PIN b_d[424]
    DIRECTION OUTPUT ;
    USE SIGNAL ;
    PORT
      LAYER M5 ;
        RECT  34.128 0 34.152 0.084 ;
    END
  END b_d[424]
  PIN b_d[425]
    DIRECTION OUTPUT ;
    USE SIGNAL ;
    PORT
      LAYER M5 ;
        RECT  34.176 0 34.2 0.084 ;
    END
  END b_d[425]
  PIN b_d[426]
    DIRECTION OUTPUT ;
    USE SIGNAL ;
    PORT
      LAYER M5 ;
        RECT  34.224 0 34.248 0.084 ;
    END
  END b_d[426]
  PIN b_d[427]
    DIRECTION OUTPUT ;
    USE SIGNAL ;
    PORT
      LAYER M5 ;
        RECT  34.272 0 34.296 0.084 ;
    END
  END b_d[427]
  PIN b_d[428]
    DIRECTION OUTPUT ;
    USE SIGNAL ;
    PORT
      LAYER M5 ;
        RECT  34.32 0 34.344 0.084 ;
    END
  END b_d[428]
  PIN b_d[429]
    DIRECTION OUTPUT ;
    USE SIGNAL ;
    PORT
      LAYER M5 ;
        RECT  34.368 0 34.392 0.084 ;
    END
  END b_d[429]
  PIN b_d[42]
    DIRECTION OUTPUT ;
    USE SIGNAL ;
    PORT
      LAYER M5 ;
        RECT  15.792 0 15.816 0.084 ;
    END
  END b_d[42]
  PIN b_d[430]
    DIRECTION OUTPUT ;
    USE SIGNAL ;
    PORT
      LAYER M5 ;
        RECT  34.416 0 34.44 0.084 ;
    END
  END b_d[430]
  PIN b_d[431]
    DIRECTION OUTPUT ;
    USE SIGNAL ;
    PORT
      LAYER M5 ;
        RECT  34.464 0 34.488 0.084 ;
    END
  END b_d[431]
  PIN b_d[432]
    DIRECTION OUTPUT ;
    USE SIGNAL ;
    PORT
      LAYER M5 ;
        RECT  34.512 0 34.536 0.084 ;
    END
  END b_d[432]
  PIN b_d[433]
    DIRECTION OUTPUT ;
    USE SIGNAL ;
    PORT
      LAYER M5 ;
        RECT  34.56 0 34.584 0.084 ;
    END
  END b_d[433]
  PIN b_d[434]
    DIRECTION OUTPUT ;
    USE SIGNAL ;
    PORT
      LAYER M5 ;
        RECT  34.608 0 34.632 0.084 ;
    END
  END b_d[434]
  PIN b_d[435]
    DIRECTION OUTPUT ;
    USE SIGNAL ;
    PORT
      LAYER M5 ;
        RECT  34.656 0 34.68 0.084 ;
    END
  END b_d[435]
  PIN b_d[436]
    DIRECTION OUTPUT ;
    USE SIGNAL ;
    PORT
      LAYER M5 ;
        RECT  34.704 0 34.728 0.084 ;
    END
  END b_d[436]
  PIN b_d[437]
    DIRECTION OUTPUT ;
    USE SIGNAL ;
    PORT
      LAYER M5 ;
        RECT  34.752 0 34.776 0.084 ;
    END
  END b_d[437]
  PIN b_d[438]
    DIRECTION OUTPUT ;
    USE SIGNAL ;
    PORT
      LAYER M5 ;
        RECT  34.8 0 34.824 0.084 ;
    END
  END b_d[438]
  PIN b_d[439]
    DIRECTION OUTPUT ;
    USE SIGNAL ;
    PORT
      LAYER M5 ;
        RECT  34.848 0 34.872 0.084 ;
    END
  END b_d[439]
  PIN b_d[43]
    DIRECTION OUTPUT ;
    USE SIGNAL ;
    PORT
      LAYER M5 ;
        RECT  15.84 0 15.864 0.084 ;
    END
  END b_d[43]
  PIN b_d[440]
    DIRECTION OUTPUT ;
    USE SIGNAL ;
    PORT
      LAYER M5 ;
        RECT  34.896 0 34.92 0.084 ;
    END
  END b_d[440]
  PIN b_d[441]
    DIRECTION OUTPUT ;
    USE SIGNAL ;
    PORT
      LAYER M5 ;
        RECT  34.944 0 34.968 0.084 ;
    END
  END b_d[441]
  PIN b_d[442]
    DIRECTION OUTPUT ;
    USE SIGNAL ;
    PORT
      LAYER M5 ;
        RECT  34.992 0 35.016 0.084 ;
    END
  END b_d[442]
  PIN b_d[443]
    DIRECTION OUTPUT ;
    USE SIGNAL ;
    PORT
      LAYER M5 ;
        RECT  35.04 0 35.064 0.084 ;
    END
  END b_d[443]
  PIN b_d[444]
    DIRECTION OUTPUT ;
    USE SIGNAL ;
    PORT
      LAYER M5 ;
        RECT  35.088 0 35.112 0.084 ;
    END
  END b_d[444]
  PIN b_d[445]
    DIRECTION OUTPUT ;
    USE SIGNAL ;
    PORT
      LAYER M5 ;
        RECT  35.136 0 35.16 0.084 ;
    END
  END b_d[445]
  PIN b_d[446]
    DIRECTION OUTPUT ;
    USE SIGNAL ;
    PORT
      LAYER M5 ;
        RECT  35.184 0 35.208 0.084 ;
    END
  END b_d[446]
  PIN b_d[447]
    DIRECTION OUTPUT ;
    USE SIGNAL ;
    PORT
      LAYER M5 ;
        RECT  35.232 0 35.256 0.084 ;
    END
  END b_d[447]
  PIN b_d[448]
    DIRECTION OUTPUT ;
    USE SIGNAL ;
    PORT
      LAYER M5 ;
        RECT  35.28 0 35.304 0.084 ;
    END
  END b_d[448]
  PIN b_d[449]
    DIRECTION OUTPUT ;
    USE SIGNAL ;
    PORT
      LAYER M5 ;
        RECT  35.328 0 35.352 0.084 ;
    END
  END b_d[449]
  PIN b_d[44]
    DIRECTION OUTPUT ;
    USE SIGNAL ;
    PORT
      LAYER M5 ;
        RECT  15.888 0 15.912 0.084 ;
    END
  END b_d[44]
  PIN b_d[450]
    DIRECTION OUTPUT ;
    USE SIGNAL ;
    PORT
      LAYER M5 ;
        RECT  35.376 0 35.4 0.084 ;
    END
  END b_d[450]
  PIN b_d[451]
    DIRECTION OUTPUT ;
    USE SIGNAL ;
    PORT
      LAYER M5 ;
        RECT  35.424 0 35.448 0.084 ;
    END
  END b_d[451]
  PIN b_d[452]
    DIRECTION OUTPUT ;
    USE SIGNAL ;
    PORT
      LAYER M5 ;
        RECT  35.472 0 35.496 0.084 ;
    END
  END b_d[452]
  PIN b_d[453]
    DIRECTION OUTPUT ;
    USE SIGNAL ;
    PORT
      LAYER M5 ;
        RECT  35.52 0 35.544 0.084 ;
    END
  END b_d[453]
  PIN b_d[454]
    DIRECTION OUTPUT ;
    USE SIGNAL ;
    PORT
      LAYER M5 ;
        RECT  35.568 0 35.592 0.084 ;
    END
  END b_d[454]
  PIN b_d[455]
    DIRECTION OUTPUT ;
    USE SIGNAL ;
    PORT
      LAYER M5 ;
        RECT  35.616 0 35.64 0.084 ;
    END
  END b_d[455]
  PIN b_d[456]
    DIRECTION OUTPUT ;
    USE SIGNAL ;
    PORT
      LAYER M5 ;
        RECT  35.664 0 35.688 0.084 ;
    END
  END b_d[456]
  PIN b_d[457]
    DIRECTION OUTPUT ;
    USE SIGNAL ;
    PORT
      LAYER M5 ;
        RECT  35.712 0 35.736 0.084 ;
    END
  END b_d[457]
  PIN b_d[458]
    DIRECTION OUTPUT ;
    USE SIGNAL ;
    PORT
      LAYER M5 ;
        RECT  35.76 0 35.784 0.084 ;
    END
  END b_d[458]
  PIN b_d[459]
    DIRECTION OUTPUT ;
    USE SIGNAL ;
    PORT
      LAYER M5 ;
        RECT  35.808 0 35.832 0.084 ;
    END
  END b_d[459]
  PIN b_d[45]
    DIRECTION OUTPUT ;
    USE SIGNAL ;
    PORT
      LAYER M5 ;
        RECT  15.936 0 15.96 0.084 ;
    END
  END b_d[45]
  PIN b_d[460]
    DIRECTION OUTPUT ;
    USE SIGNAL ;
    PORT
      LAYER M5 ;
        RECT  35.856 0 35.88 0.084 ;
    END
  END b_d[460]
  PIN b_d[461]
    DIRECTION OUTPUT ;
    USE SIGNAL ;
    PORT
      LAYER M5 ;
        RECT  35.904 0 35.928 0.084 ;
    END
  END b_d[461]
  PIN b_d[462]
    DIRECTION OUTPUT ;
    USE SIGNAL ;
    PORT
      LAYER M5 ;
        RECT  35.952 0 35.976 0.084 ;
    END
  END b_d[462]
  PIN b_d[463]
    DIRECTION OUTPUT ;
    USE SIGNAL ;
    PORT
      LAYER M5 ;
        RECT  36 0 36.024 0.084 ;
    END
  END b_d[463]
  PIN b_d[464]
    DIRECTION OUTPUT ;
    USE SIGNAL ;
    PORT
      LAYER M5 ;
        RECT  36.048 0 36.072 0.084 ;
    END
  END b_d[464]
  PIN b_d[465]
    DIRECTION OUTPUT ;
    USE SIGNAL ;
    PORT
      LAYER M5 ;
        RECT  36.096 0 36.12 0.084 ;
    END
  END b_d[465]
  PIN b_d[466]
    DIRECTION OUTPUT ;
    USE SIGNAL ;
    PORT
      LAYER M5 ;
        RECT  36.144 0 36.168 0.084 ;
    END
  END b_d[466]
  PIN b_d[467]
    DIRECTION OUTPUT ;
    USE SIGNAL ;
    PORT
      LAYER M5 ;
        RECT  36.192 0 36.216 0.084 ;
    END
  END b_d[467]
  PIN b_d[468]
    DIRECTION OUTPUT ;
    USE SIGNAL ;
    PORT
      LAYER M5 ;
        RECT  36.24 0 36.264 0.084 ;
    END
  END b_d[468]
  PIN b_d[469]
    DIRECTION OUTPUT ;
    USE SIGNAL ;
    PORT
      LAYER M5 ;
        RECT  36.288 0 36.312 0.084 ;
    END
  END b_d[469]
  PIN b_d[46]
    DIRECTION OUTPUT ;
    USE SIGNAL ;
    PORT
      LAYER M5 ;
        RECT  15.984 0 16.008 0.084 ;
    END
  END b_d[46]
  PIN b_d[470]
    DIRECTION OUTPUT ;
    USE SIGNAL ;
    PORT
      LAYER M5 ;
        RECT  36.336 0 36.36 0.084 ;
    END
  END b_d[470]
  PIN b_d[471]
    DIRECTION OUTPUT ;
    USE SIGNAL ;
    PORT
      LAYER M5 ;
        RECT  36.384 0 36.408 0.084 ;
    END
  END b_d[471]
  PIN b_d[472]
    DIRECTION OUTPUT ;
    USE SIGNAL ;
    PORT
      LAYER M5 ;
        RECT  36.432 0 36.456 0.084 ;
    END
  END b_d[472]
  PIN b_d[473]
    DIRECTION OUTPUT ;
    USE SIGNAL ;
    PORT
      LAYER M5 ;
        RECT  36.48 0 36.504 0.084 ;
    END
  END b_d[473]
  PIN b_d[474]
    DIRECTION OUTPUT ;
    USE SIGNAL ;
    PORT
      LAYER M5 ;
        RECT  36.528 0 36.552 0.084 ;
    END
  END b_d[474]
  PIN b_d[475]
    DIRECTION OUTPUT ;
    USE SIGNAL ;
    PORT
      LAYER M5 ;
        RECT  36.576 0 36.6 0.084 ;
    END
  END b_d[475]
  PIN b_d[476]
    DIRECTION OUTPUT ;
    USE SIGNAL ;
    PORT
      LAYER M5 ;
        RECT  36.624 0 36.648 0.084 ;
    END
  END b_d[476]
  PIN b_d[477]
    DIRECTION OUTPUT ;
    USE SIGNAL ;
    PORT
      LAYER M5 ;
        RECT  36.672 0 36.696 0.084 ;
    END
  END b_d[477]
  PIN b_d[478]
    DIRECTION OUTPUT ;
    USE SIGNAL ;
    PORT
      LAYER M5 ;
        RECT  36.72 0 36.744 0.084 ;
    END
  END b_d[478]
  PIN b_d[479]
    DIRECTION OUTPUT ;
    USE SIGNAL ;
    PORT
      LAYER M5 ;
        RECT  36.768 0 36.792 0.084 ;
    END
  END b_d[479]
  PIN b_d[47]
    DIRECTION OUTPUT ;
    USE SIGNAL ;
    PORT
      LAYER M5 ;
        RECT  16.032 0 16.056 0.084 ;
    END
  END b_d[47]
  PIN b_d[480]
    DIRECTION OUTPUT ;
    USE SIGNAL ;
    PORT
      LAYER M5 ;
        RECT  36.816 0 36.84 0.084 ;
    END
  END b_d[480]
  PIN b_d[481]
    DIRECTION OUTPUT ;
    USE SIGNAL ;
    PORT
      LAYER M5 ;
        RECT  36.864 0 36.888 0.084 ;
    END
  END b_d[481]
  PIN b_d[482]
    DIRECTION OUTPUT ;
    USE SIGNAL ;
    PORT
      LAYER M5 ;
        RECT  36.912 0 36.936 0.084 ;
    END
  END b_d[482]
  PIN b_d[483]
    DIRECTION OUTPUT ;
    USE SIGNAL ;
    PORT
      LAYER M5 ;
        RECT  36.96 0 36.984 0.084 ;
    END
  END b_d[483]
  PIN b_d[484]
    DIRECTION OUTPUT ;
    USE SIGNAL ;
    PORT
      LAYER M5 ;
        RECT  37.008 0 37.032 0.084 ;
    END
  END b_d[484]
  PIN b_d[485]
    DIRECTION OUTPUT ;
    USE SIGNAL ;
    PORT
      LAYER M5 ;
        RECT  37.056 0 37.08 0.084 ;
    END
  END b_d[485]
  PIN b_d[486]
    DIRECTION OUTPUT ;
    USE SIGNAL ;
    PORT
      LAYER M5 ;
        RECT  37.104 0 37.128 0.084 ;
    END
  END b_d[486]
  PIN b_d[487]
    DIRECTION OUTPUT ;
    USE SIGNAL ;
    PORT
      LAYER M5 ;
        RECT  37.152 0 37.176 0.084 ;
    END
  END b_d[487]
  PIN b_d[488]
    DIRECTION OUTPUT ;
    USE SIGNAL ;
    PORT
      LAYER M5 ;
        RECT  37.2 0 37.224 0.084 ;
    END
  END b_d[488]
  PIN b_d[489]
    DIRECTION OUTPUT ;
    USE SIGNAL ;
    PORT
      LAYER M5 ;
        RECT  37.248 0 37.272 0.084 ;
    END
  END b_d[489]
  PIN b_d[48]
    DIRECTION OUTPUT ;
    USE SIGNAL ;
    PORT
      LAYER M5 ;
        RECT  16.08 0 16.104 0.084 ;
    END
  END b_d[48]
  PIN b_d[490]
    DIRECTION OUTPUT ;
    USE SIGNAL ;
    PORT
      LAYER M5 ;
        RECT  37.296 0 37.32 0.084 ;
    END
  END b_d[490]
  PIN b_d[491]
    DIRECTION OUTPUT ;
    USE SIGNAL ;
    PORT
      LAYER M5 ;
        RECT  37.344 0 37.368 0.084 ;
    END
  END b_d[491]
  PIN b_d[492]
    DIRECTION OUTPUT ;
    USE SIGNAL ;
    PORT
      LAYER M5 ;
        RECT  37.392 0 37.416 0.084 ;
    END
  END b_d[492]
  PIN b_d[493]
    DIRECTION OUTPUT ;
    USE SIGNAL ;
    PORT
      LAYER M5 ;
        RECT  37.44 0 37.464 0.084 ;
    END
  END b_d[493]
  PIN b_d[494]
    DIRECTION OUTPUT ;
    USE SIGNAL ;
    PORT
      LAYER M5 ;
        RECT  37.488 0 37.512 0.084 ;
    END
  END b_d[494]
  PIN b_d[495]
    DIRECTION OUTPUT ;
    USE SIGNAL ;
    PORT
      LAYER M5 ;
        RECT  37.536 0 37.56 0.084 ;
    END
  END b_d[495]
  PIN b_d[496]
    DIRECTION OUTPUT ;
    USE SIGNAL ;
    PORT
      LAYER M5 ;
        RECT  37.584 0 37.608 0.084 ;
    END
  END b_d[496]
  PIN b_d[497]
    DIRECTION OUTPUT ;
    USE SIGNAL ;
    PORT
      LAYER M5 ;
        RECT  37.632 0 37.656 0.084 ;
    END
  END b_d[497]
  PIN b_d[498]
    DIRECTION OUTPUT ;
    USE SIGNAL ;
    PORT
      LAYER M5 ;
        RECT  37.68 0 37.704 0.084 ;
    END
  END b_d[498]
  PIN b_d[499]
    DIRECTION OUTPUT ;
    USE SIGNAL ;
    PORT
      LAYER M5 ;
        RECT  37.728 0 37.752 0.084 ;
    END
  END b_d[499]
  PIN b_d[49]
    DIRECTION OUTPUT ;
    USE SIGNAL ;
    PORT
      LAYER M5 ;
        RECT  16.128 0 16.152 0.084 ;
    END
  END b_d[49]
  PIN b_d[4]
    DIRECTION OUTPUT ;
    USE SIGNAL ;
    PORT
      LAYER M5 ;
        RECT  13.968 0 13.992 0.084 ;
    END
  END b_d[4]
  PIN b_d[500]
    DIRECTION OUTPUT ;
    USE SIGNAL ;
    PORT
      LAYER M5 ;
        RECT  37.776 0 37.8 0.084 ;
    END
  END b_d[500]
  PIN b_d[501]
    DIRECTION OUTPUT ;
    USE SIGNAL ;
    PORT
      LAYER M5 ;
        RECT  37.824 0 37.848 0.084 ;
    END
  END b_d[501]
  PIN b_d[502]
    DIRECTION OUTPUT ;
    USE SIGNAL ;
    PORT
      LAYER M5 ;
        RECT  37.872 0 37.896 0.084 ;
    END
  END b_d[502]
  PIN b_d[503]
    DIRECTION OUTPUT ;
    USE SIGNAL ;
    PORT
      LAYER M5 ;
        RECT  37.92 0 37.944 0.084 ;
    END
  END b_d[503]
  PIN b_d[504]
    DIRECTION OUTPUT ;
    USE SIGNAL ;
    PORT
      LAYER M5 ;
        RECT  37.968 0 37.992 0.084 ;
    END
  END b_d[504]
  PIN b_d[505]
    DIRECTION OUTPUT ;
    USE SIGNAL ;
    PORT
      LAYER M5 ;
        RECT  38.016 0 38.04 0.084 ;
    END
  END b_d[505]
  PIN b_d[506]
    DIRECTION OUTPUT ;
    USE SIGNAL ;
    PORT
      LAYER M5 ;
        RECT  38.064 0 38.088 0.084 ;
    END
  END b_d[506]
  PIN b_d[507]
    DIRECTION OUTPUT ;
    USE SIGNAL ;
    PORT
      LAYER M5 ;
        RECT  38.112 0 38.136 0.084 ;
    END
  END b_d[507]
  PIN b_d[50]
    DIRECTION OUTPUT ;
    USE SIGNAL ;
    PORT
      LAYER M5 ;
        RECT  16.176 0 16.2 0.084 ;
    END
  END b_d[50]
  PIN b_d[51]
    DIRECTION OUTPUT ;
    USE SIGNAL ;
    PORT
      LAYER M5 ;
        RECT  16.224 0 16.248 0.084 ;
    END
  END b_d[51]
  PIN b_d[52]
    DIRECTION OUTPUT ;
    USE SIGNAL ;
    PORT
      LAYER M5 ;
        RECT  16.272 0 16.296 0.084 ;
    END
  END b_d[52]
  PIN b_d[53]
    DIRECTION OUTPUT ;
    USE SIGNAL ;
    PORT
      LAYER M5 ;
        RECT  16.32 0 16.344 0.084 ;
    END
  END b_d[53]
  PIN b_d[54]
    DIRECTION OUTPUT ;
    USE SIGNAL ;
    PORT
      LAYER M5 ;
        RECT  16.368 0 16.392 0.084 ;
    END
  END b_d[54]
  PIN b_d[55]
    DIRECTION OUTPUT ;
    USE SIGNAL ;
    PORT
      LAYER M5 ;
        RECT  16.416 0 16.44 0.084 ;
    END
  END b_d[55]
  PIN b_d[56]
    DIRECTION OUTPUT ;
    USE SIGNAL ;
    PORT
      LAYER M5 ;
        RECT  16.464 0 16.488 0.084 ;
    END
  END b_d[56]
  PIN b_d[57]
    DIRECTION OUTPUT ;
    USE SIGNAL ;
    PORT
      LAYER M5 ;
        RECT  16.512 0 16.536 0.084 ;
    END
  END b_d[57]
  PIN b_d[58]
    DIRECTION OUTPUT ;
    USE SIGNAL ;
    PORT
      LAYER M5 ;
        RECT  16.56 0 16.584 0.084 ;
    END
  END b_d[58]
  PIN b_d[59]
    DIRECTION OUTPUT ;
    USE SIGNAL ;
    PORT
      LAYER M5 ;
        RECT  16.608 0 16.632 0.084 ;
    END
  END b_d[59]
  PIN b_d[5]
    DIRECTION OUTPUT ;
    USE SIGNAL ;
    PORT
      LAYER M5 ;
        RECT  14.016 0 14.04 0.084 ;
    END
  END b_d[5]
  PIN b_d[60]
    DIRECTION OUTPUT ;
    USE SIGNAL ;
    PORT
      LAYER M5 ;
        RECT  16.656 0 16.68 0.084 ;
    END
  END b_d[60]
  PIN b_d[61]
    DIRECTION OUTPUT ;
    USE SIGNAL ;
    PORT
      LAYER M5 ;
        RECT  16.704 0 16.728 0.084 ;
    END
  END b_d[61]
  PIN b_d[62]
    DIRECTION OUTPUT ;
    USE SIGNAL ;
    PORT
      LAYER M5 ;
        RECT  16.752 0 16.776 0.084 ;
    END
  END b_d[62]
  PIN b_d[63]
    DIRECTION OUTPUT ;
    USE SIGNAL ;
    PORT
      LAYER M5 ;
        RECT  16.8 0 16.824 0.084 ;
    END
  END b_d[63]
  PIN b_d[64]
    DIRECTION OUTPUT ;
    USE SIGNAL ;
    PORT
      LAYER M5 ;
        RECT  16.848 0 16.872 0.084 ;
    END
  END b_d[64]
  PIN b_d[65]
    DIRECTION OUTPUT ;
    USE SIGNAL ;
    PORT
      LAYER M5 ;
        RECT  16.896 0 16.92 0.084 ;
    END
  END b_d[65]
  PIN b_d[66]
    DIRECTION OUTPUT ;
    USE SIGNAL ;
    PORT
      LAYER M5 ;
        RECT  16.944 0 16.968 0.084 ;
    END
  END b_d[66]
  PIN b_d[67]
    DIRECTION OUTPUT ;
    USE SIGNAL ;
    PORT
      LAYER M5 ;
        RECT  16.992 0 17.016 0.084 ;
    END
  END b_d[67]
  PIN b_d[68]
    DIRECTION OUTPUT ;
    USE SIGNAL ;
    PORT
      LAYER M5 ;
        RECT  17.04 0 17.064 0.084 ;
    END
  END b_d[68]
  PIN b_d[69]
    DIRECTION OUTPUT ;
    USE SIGNAL ;
    PORT
      LAYER M5 ;
        RECT  17.088 0 17.112 0.084 ;
    END
  END b_d[69]
  PIN b_d[6]
    DIRECTION OUTPUT ;
    USE SIGNAL ;
    PORT
      LAYER M5 ;
        RECT  14.064 0 14.088 0.084 ;
    END
  END b_d[6]
  PIN b_d[70]
    DIRECTION OUTPUT ;
    USE SIGNAL ;
    PORT
      LAYER M5 ;
        RECT  17.136 0 17.16 0.084 ;
    END
  END b_d[70]
  PIN b_d[71]
    DIRECTION OUTPUT ;
    USE SIGNAL ;
    PORT
      LAYER M5 ;
        RECT  17.184 0 17.208 0.084 ;
    END
  END b_d[71]
  PIN b_d[72]
    DIRECTION OUTPUT ;
    USE SIGNAL ;
    PORT
      LAYER M5 ;
        RECT  17.232 0 17.256 0.084 ;
    END
  END b_d[72]
  PIN b_d[73]
    DIRECTION OUTPUT ;
    USE SIGNAL ;
    PORT
      LAYER M5 ;
        RECT  17.28 0 17.304 0.084 ;
    END
  END b_d[73]
  PIN b_d[74]
    DIRECTION OUTPUT ;
    USE SIGNAL ;
    PORT
      LAYER M5 ;
        RECT  17.328 0 17.352 0.084 ;
    END
  END b_d[74]
  PIN b_d[75]
    DIRECTION OUTPUT ;
    USE SIGNAL ;
    PORT
      LAYER M5 ;
        RECT  17.376 0 17.4 0.084 ;
    END
  END b_d[75]
  PIN b_d[76]
    DIRECTION OUTPUT ;
    USE SIGNAL ;
    PORT
      LAYER M5 ;
        RECT  17.424 0 17.448 0.084 ;
    END
  END b_d[76]
  PIN b_d[77]
    DIRECTION OUTPUT ;
    USE SIGNAL ;
    PORT
      LAYER M5 ;
        RECT  17.472 0 17.496 0.084 ;
    END
  END b_d[77]
  PIN b_d[78]
    DIRECTION OUTPUT ;
    USE SIGNAL ;
    PORT
      LAYER M5 ;
        RECT  17.52 0 17.544 0.084 ;
    END
  END b_d[78]
  PIN b_d[79]
    DIRECTION OUTPUT ;
    USE SIGNAL ;
    PORT
      LAYER M5 ;
        RECT  17.568 0 17.592 0.084 ;
    END
  END b_d[79]
  PIN b_d[7]
    DIRECTION OUTPUT ;
    USE SIGNAL ;
    PORT
      LAYER M5 ;
        RECT  14.112 0 14.136 0.084 ;
    END
  END b_d[7]
  PIN b_d[80]
    DIRECTION OUTPUT ;
    USE SIGNAL ;
    PORT
      LAYER M5 ;
        RECT  17.616 0 17.64 0.084 ;
    END
  END b_d[80]
  PIN b_d[81]
    DIRECTION OUTPUT ;
    USE SIGNAL ;
    PORT
      LAYER M5 ;
        RECT  17.664 0 17.688 0.084 ;
    END
  END b_d[81]
  PIN b_d[82]
    DIRECTION OUTPUT ;
    USE SIGNAL ;
    PORT
      LAYER M5 ;
        RECT  17.712 0 17.736 0.084 ;
    END
  END b_d[82]
  PIN b_d[83]
    DIRECTION OUTPUT ;
    USE SIGNAL ;
    PORT
      LAYER M5 ;
        RECT  17.76 0 17.784 0.084 ;
    END
  END b_d[83]
  PIN b_d[84]
    DIRECTION OUTPUT ;
    USE SIGNAL ;
    PORT
      LAYER M5 ;
        RECT  17.808 0 17.832 0.084 ;
    END
  END b_d[84]
  PIN b_d[85]
    DIRECTION OUTPUT ;
    USE SIGNAL ;
    PORT
      LAYER M5 ;
        RECT  17.856 0 17.88 0.084 ;
    END
  END b_d[85]
  PIN b_d[86]
    DIRECTION OUTPUT ;
    USE SIGNAL ;
    PORT
      LAYER M5 ;
        RECT  17.904 0 17.928 0.084 ;
    END
  END b_d[86]
  PIN b_d[87]
    DIRECTION OUTPUT ;
    USE SIGNAL ;
    PORT
      LAYER M5 ;
        RECT  17.952 0 17.976 0.084 ;
    END
  END b_d[87]
  PIN b_d[88]
    DIRECTION OUTPUT ;
    USE SIGNAL ;
    PORT
      LAYER M5 ;
        RECT  18 0 18.024 0.084 ;
    END
  END b_d[88]
  PIN b_d[89]
    DIRECTION OUTPUT ;
    USE SIGNAL ;
    PORT
      LAYER M5 ;
        RECT  18.048 0 18.072 0.084 ;
    END
  END b_d[89]
  PIN b_d[8]
    DIRECTION OUTPUT ;
    USE SIGNAL ;
    PORT
      LAYER M5 ;
        RECT  14.16 0 14.184 0.084 ;
    END
  END b_d[8]
  PIN b_d[90]
    DIRECTION OUTPUT ;
    USE SIGNAL ;
    PORT
      LAYER M5 ;
        RECT  18.096 0 18.12 0.084 ;
    END
  END b_d[90]
  PIN b_d[91]
    DIRECTION OUTPUT ;
    USE SIGNAL ;
    PORT
      LAYER M5 ;
        RECT  18.144 0 18.168 0.084 ;
    END
  END b_d[91]
  PIN b_d[92]
    DIRECTION OUTPUT ;
    USE SIGNAL ;
    PORT
      LAYER M5 ;
        RECT  18.192 0 18.216 0.084 ;
    END
  END b_d[92]
  PIN b_d[93]
    DIRECTION OUTPUT ;
    USE SIGNAL ;
    PORT
      LAYER M5 ;
        RECT  18.24 0 18.264 0.084 ;
    END
  END b_d[93]
  PIN b_d[94]
    DIRECTION OUTPUT ;
    USE SIGNAL ;
    PORT
      LAYER M5 ;
        RECT  18.288 0 18.312 0.084 ;
    END
  END b_d[94]
  PIN b_d[95]
    DIRECTION OUTPUT ;
    USE SIGNAL ;
    PORT
      LAYER M5 ;
        RECT  18.336 0 18.36 0.084 ;
    END
  END b_d[95]
  PIN b_d[96]
    DIRECTION OUTPUT ;
    USE SIGNAL ;
    PORT
      LAYER M5 ;
        RECT  18.384 0 18.408 0.084 ;
    END
  END b_d[96]
  PIN b_d[97]
    DIRECTION OUTPUT ;
    USE SIGNAL ;
    PORT
      LAYER M5 ;
        RECT  18.432 0 18.456 0.084 ;
    END
  END b_d[97]
  PIN b_d[98]
    DIRECTION OUTPUT ;
    USE SIGNAL ;
    PORT
      LAYER M5 ;
        RECT  18.48 0 18.504 0.084 ;
    END
  END b_d[98]
  PIN b_d[99]
    DIRECTION OUTPUT ;
    USE SIGNAL ;
    PORT
      LAYER M5 ;
        RECT  18.528 0 18.552 0.084 ;
    END
  END b_d[99]
  PIN b_d[9]
    DIRECTION OUTPUT ;
    USE SIGNAL ;
    PORT
      LAYER M5 ;
        RECT  14.208 0 14.232 0.084 ;
    END
  END b_d[9]
  PIN b_r
    DIRECTION INPUT ;
    USE SIGNAL ;
    PORT
      LAYER M5 ;
        RECT  38.16 0 38.184 0.084 ;
    END
  END b_r
  PIN c_d[0]
    DIRECTION OUTPUT ;
    USE SIGNAL ;
    PORT
      LAYER M4 ;
        RECT  0 39.696 0.084 39.72 ;
    END
  END c_d[0]
  PIN c_r
    DIRECTION INPUT ;
    USE SIGNAL ;
    PORT
      LAYER M4 ;
        RECT  0 39.744 0.084 39.768 ;
    END
  END c_r
  PIN clk
    DIRECTION INPUT ;
    USE SIGNAL ;
    PORT
      LAYER M4 ;
        RECT  0 39.792 0.084 39.816 ;
    END
  END clk
  PIN rst_n
    DIRECTION INPUT ;
    USE SIGNAL ;
    PORT
      LAYER M4 ;
        RECT  0 39.84 0.084 39.864 ;
    END
  END rst_n
  PIN t_d[0]
    DIRECTION OUTPUT ;
    USE SIGNAL ;
    PORT
      LAYER M4 ;
        RECT  0 39.888 0.084 39.912 ;
    END
  END t_d[0]
  PIN t_d[100]
    DIRECTION OUTPUT ;
    USE SIGNAL ;
    PORT
      LAYER M4 ;
        RECT  0 44.688 0.084 44.712 ;
    END
  END t_d[100]
  PIN t_d[101]
    DIRECTION OUTPUT ;
    USE SIGNAL ;
    PORT
      LAYER M4 ;
        RECT  0 44.736 0.084 44.76 ;
    END
  END t_d[101]
  PIN t_d[102]
    DIRECTION OUTPUT ;
    USE SIGNAL ;
    PORT
      LAYER M4 ;
        RECT  0 44.784 0.084 44.808 ;
    END
  END t_d[102]
  PIN t_d[103]
    DIRECTION OUTPUT ;
    USE SIGNAL ;
    PORT
      LAYER M4 ;
        RECT  0 44.832 0.084 44.856 ;
    END
  END t_d[103]
  PIN t_d[104]
    DIRECTION OUTPUT ;
    USE SIGNAL ;
    PORT
      LAYER M4 ;
        RECT  0 44.88 0.084 44.904 ;
    END
  END t_d[104]
  PIN t_d[105]
    DIRECTION OUTPUT ;
    USE SIGNAL ;
    PORT
      LAYER M4 ;
        RECT  0 44.928 0.084 44.952 ;
    END
  END t_d[105]
  PIN t_d[106]
    DIRECTION OUTPUT ;
    USE SIGNAL ;
    PORT
      LAYER M4 ;
        RECT  0 44.976 0.084 45 ;
    END
  END t_d[106]
  PIN t_d[107]
    DIRECTION OUTPUT ;
    USE SIGNAL ;
    PORT
      LAYER M4 ;
        RECT  0 45.024 0.084 45.048 ;
    END
  END t_d[107]
  PIN t_d[108]
    DIRECTION OUTPUT ;
    USE SIGNAL ;
    PORT
      LAYER M4 ;
        RECT  0 45.072 0.084 45.096 ;
    END
  END t_d[108]
  PIN t_d[109]
    DIRECTION OUTPUT ;
    USE SIGNAL ;
    PORT
      LAYER M4 ;
        RECT  0 45.12 0.084 45.144 ;
    END
  END t_d[109]
  PIN t_d[10]
    DIRECTION OUTPUT ;
    USE SIGNAL ;
    PORT
      LAYER M4 ;
        RECT  0 40.368 0.084 40.392 ;
    END
  END t_d[10]
  PIN t_d[110]
    DIRECTION OUTPUT ;
    USE SIGNAL ;
    PORT
      LAYER M4 ;
        RECT  0 45.168 0.084 45.192 ;
    END
  END t_d[110]
  PIN t_d[111]
    DIRECTION OUTPUT ;
    USE SIGNAL ;
    PORT
      LAYER M4 ;
        RECT  0 45.216 0.084 45.24 ;
    END
  END t_d[111]
  PIN t_d[112]
    DIRECTION OUTPUT ;
    USE SIGNAL ;
    PORT
      LAYER M4 ;
        RECT  0 45.264 0.084 45.288 ;
    END
  END t_d[112]
  PIN t_d[113]
    DIRECTION OUTPUT ;
    USE SIGNAL ;
    PORT
      LAYER M4 ;
        RECT  0 45.312 0.084 45.336 ;
    END
  END t_d[113]
  PIN t_d[114]
    DIRECTION OUTPUT ;
    USE SIGNAL ;
    PORT
      LAYER M4 ;
        RECT  0 45.36 0.084 45.384 ;
    END
  END t_d[114]
  PIN t_d[115]
    DIRECTION OUTPUT ;
    USE SIGNAL ;
    PORT
      LAYER M4 ;
        RECT  0 45.408 0.084 45.432 ;
    END
  END t_d[115]
  PIN t_d[116]
    DIRECTION OUTPUT ;
    USE SIGNAL ;
    PORT
      LAYER M4 ;
        RECT  0 45.456 0.084 45.48 ;
    END
  END t_d[116]
  PIN t_d[117]
    DIRECTION OUTPUT ;
    USE SIGNAL ;
    PORT
      LAYER M4 ;
        RECT  0 45.504 0.084 45.528 ;
    END
  END t_d[117]
  PIN t_d[118]
    DIRECTION OUTPUT ;
    USE SIGNAL ;
    PORT
      LAYER M4 ;
        RECT  0 45.552 0.084 45.576 ;
    END
  END t_d[118]
  PIN t_d[119]
    DIRECTION OUTPUT ;
    USE SIGNAL ;
    PORT
      LAYER M4 ;
        RECT  0 45.6 0.084 45.624 ;
    END
  END t_d[119]
  PIN t_d[11]
    DIRECTION OUTPUT ;
    USE SIGNAL ;
    PORT
      LAYER M4 ;
        RECT  0 40.416 0.084 40.44 ;
    END
  END t_d[11]
  PIN t_d[120]
    DIRECTION OUTPUT ;
    USE SIGNAL ;
    PORT
      LAYER M4 ;
        RECT  0 45.648 0.084 45.672 ;
    END
  END t_d[120]
  PIN t_d[121]
    DIRECTION OUTPUT ;
    USE SIGNAL ;
    PORT
      LAYER M4 ;
        RECT  0 45.696 0.084 45.72 ;
    END
  END t_d[121]
  PIN t_d[122]
    DIRECTION OUTPUT ;
    USE SIGNAL ;
    PORT
      LAYER M4 ;
        RECT  0 45.744 0.084 45.768 ;
    END
  END t_d[122]
  PIN t_d[123]
    DIRECTION OUTPUT ;
    USE SIGNAL ;
    PORT
      LAYER M4 ;
        RECT  0 45.792 0.084 45.816 ;
    END
  END t_d[123]
  PIN t_d[124]
    DIRECTION OUTPUT ;
    USE SIGNAL ;
    PORT
      LAYER M4 ;
        RECT  0 45.84 0.084 45.864 ;
    END
  END t_d[124]
  PIN t_d[125]
    DIRECTION OUTPUT ;
    USE SIGNAL ;
    PORT
      LAYER M4 ;
        RECT  0 45.888 0.084 45.912 ;
    END
  END t_d[125]
  PIN t_d[126]
    DIRECTION OUTPUT ;
    USE SIGNAL ;
    PORT
      LAYER M4 ;
        RECT  0 45.936 0.084 45.96 ;
    END
  END t_d[126]
  PIN t_d[127]
    DIRECTION OUTPUT ;
    USE SIGNAL ;
    PORT
      LAYER M4 ;
        RECT  0 45.984 0.084 46.008 ;
    END
  END t_d[127]
  PIN t_d[128]
    DIRECTION OUTPUT ;
    USE SIGNAL ;
    PORT
      LAYER M4 ;
        RECT  0 46.032 0.084 46.056 ;
    END
  END t_d[128]
  PIN t_d[129]
    DIRECTION OUTPUT ;
    USE SIGNAL ;
    PORT
      LAYER M4 ;
        RECT  0 46.08 0.084 46.104 ;
    END
  END t_d[129]
  PIN t_d[12]
    DIRECTION OUTPUT ;
    USE SIGNAL ;
    PORT
      LAYER M4 ;
        RECT  0 40.464 0.084 40.488 ;
    END
  END t_d[12]
  PIN t_d[130]
    DIRECTION OUTPUT ;
    USE SIGNAL ;
    PORT
      LAYER M4 ;
        RECT  0 46.128 0.084 46.152 ;
    END
  END t_d[130]
  PIN t_d[131]
    DIRECTION OUTPUT ;
    USE SIGNAL ;
    PORT
      LAYER M4 ;
        RECT  0 46.176 0.084 46.2 ;
    END
  END t_d[131]
  PIN t_d[132]
    DIRECTION OUTPUT ;
    USE SIGNAL ;
    PORT
      LAYER M4 ;
        RECT  0 46.224 0.084 46.248 ;
    END
  END t_d[132]
  PIN t_d[133]
    DIRECTION OUTPUT ;
    USE SIGNAL ;
    PORT
      LAYER M4 ;
        RECT  0 46.272 0.084 46.296 ;
    END
  END t_d[133]
  PIN t_d[134]
    DIRECTION OUTPUT ;
    USE SIGNAL ;
    PORT
      LAYER M4 ;
        RECT  0 46.32 0.084 46.344 ;
    END
  END t_d[134]
  PIN t_d[135]
    DIRECTION OUTPUT ;
    USE SIGNAL ;
    PORT
      LAYER M4 ;
        RECT  0 46.368 0.084 46.392 ;
    END
  END t_d[135]
  PIN t_d[136]
    DIRECTION OUTPUT ;
    USE SIGNAL ;
    PORT
      LAYER M4 ;
        RECT  0 46.416 0.084 46.44 ;
    END
  END t_d[136]
  PIN t_d[137]
    DIRECTION OUTPUT ;
    USE SIGNAL ;
    PORT
      LAYER M4 ;
        RECT  0 46.464 0.084 46.488 ;
    END
  END t_d[137]
  PIN t_d[138]
    DIRECTION OUTPUT ;
    USE SIGNAL ;
    PORT
      LAYER M4 ;
        RECT  0 46.512 0.084 46.536 ;
    END
  END t_d[138]
  PIN t_d[139]
    DIRECTION OUTPUT ;
    USE SIGNAL ;
    PORT
      LAYER M4 ;
        RECT  0 46.56 0.084 46.584 ;
    END
  END t_d[139]
  PIN t_d[13]
    DIRECTION OUTPUT ;
    USE SIGNAL ;
    PORT
      LAYER M4 ;
        RECT  0 40.512 0.084 40.536 ;
    END
  END t_d[13]
  PIN t_d[140]
    DIRECTION OUTPUT ;
    USE SIGNAL ;
    PORT
      LAYER M4 ;
        RECT  0 46.608 0.084 46.632 ;
    END
  END t_d[140]
  PIN t_d[141]
    DIRECTION OUTPUT ;
    USE SIGNAL ;
    PORT
      LAYER M4 ;
        RECT  0 46.656 0.084 46.68 ;
    END
  END t_d[141]
  PIN t_d[142]
    DIRECTION OUTPUT ;
    USE SIGNAL ;
    PORT
      LAYER M4 ;
        RECT  0 46.704 0.084 46.728 ;
    END
  END t_d[142]
  PIN t_d[143]
    DIRECTION OUTPUT ;
    USE SIGNAL ;
    PORT
      LAYER M4 ;
        RECT  0 46.752 0.084 46.776 ;
    END
  END t_d[143]
  PIN t_d[144]
    DIRECTION OUTPUT ;
    USE SIGNAL ;
    PORT
      LAYER M4 ;
        RECT  0 46.8 0.084 46.824 ;
    END
  END t_d[144]
  PIN t_d[145]
    DIRECTION OUTPUT ;
    USE SIGNAL ;
    PORT
      LAYER M4 ;
        RECT  0 46.848 0.084 46.872 ;
    END
  END t_d[145]
  PIN t_d[146]
    DIRECTION OUTPUT ;
    USE SIGNAL ;
    PORT
      LAYER M4 ;
        RECT  0 46.896 0.084 46.92 ;
    END
  END t_d[146]
  PIN t_d[147]
    DIRECTION OUTPUT ;
    USE SIGNAL ;
    PORT
      LAYER M4 ;
        RECT  0 46.944 0.084 46.968 ;
    END
  END t_d[147]
  PIN t_d[148]
    DIRECTION OUTPUT ;
    USE SIGNAL ;
    PORT
      LAYER M4 ;
        RECT  0 46.992 0.084 47.016 ;
    END
  END t_d[148]
  PIN t_d[149]
    DIRECTION OUTPUT ;
    USE SIGNAL ;
    PORT
      LAYER M4 ;
        RECT  0 47.04 0.084 47.064 ;
    END
  END t_d[149]
  PIN t_d[14]
    DIRECTION OUTPUT ;
    USE SIGNAL ;
    PORT
      LAYER M4 ;
        RECT  0 40.56 0.084 40.584 ;
    END
  END t_d[14]
  PIN t_d[150]
    DIRECTION OUTPUT ;
    USE SIGNAL ;
    PORT
      LAYER M4 ;
        RECT  0 47.088 0.084 47.112 ;
    END
  END t_d[150]
  PIN t_d[151]
    DIRECTION OUTPUT ;
    USE SIGNAL ;
    PORT
      LAYER M4 ;
        RECT  0 47.136 0.084 47.16 ;
    END
  END t_d[151]
  PIN t_d[152]
    DIRECTION OUTPUT ;
    USE SIGNAL ;
    PORT
      LAYER M4 ;
        RECT  0 47.184 0.084 47.208 ;
    END
  END t_d[152]
  PIN t_d[153]
    DIRECTION OUTPUT ;
    USE SIGNAL ;
    PORT
      LAYER M4 ;
        RECT  0 47.232 0.084 47.256 ;
    END
  END t_d[153]
  PIN t_d[154]
    DIRECTION OUTPUT ;
    USE SIGNAL ;
    PORT
      LAYER M4 ;
        RECT  0 47.28 0.084 47.304 ;
    END
  END t_d[154]
  PIN t_d[155]
    DIRECTION OUTPUT ;
    USE SIGNAL ;
    PORT
      LAYER M4 ;
        RECT  0 47.328 0.084 47.352 ;
    END
  END t_d[155]
  PIN t_d[156]
    DIRECTION OUTPUT ;
    USE SIGNAL ;
    PORT
      LAYER M4 ;
        RECT  0 47.376 0.084 47.4 ;
    END
  END t_d[156]
  PIN t_d[157]
    DIRECTION OUTPUT ;
    USE SIGNAL ;
    PORT
      LAYER M4 ;
        RECT  0 47.424 0.084 47.448 ;
    END
  END t_d[157]
  PIN t_d[158]
    DIRECTION OUTPUT ;
    USE SIGNAL ;
    PORT
      LAYER M4 ;
        RECT  0 47.472 0.084 47.496 ;
    END
  END t_d[158]
  PIN t_d[159]
    DIRECTION OUTPUT ;
    USE SIGNAL ;
    PORT
      LAYER M4 ;
        RECT  0 47.52 0.084 47.544 ;
    END
  END t_d[159]
  PIN t_d[15]
    DIRECTION OUTPUT ;
    USE SIGNAL ;
    PORT
      LAYER M4 ;
        RECT  0 40.608 0.084 40.632 ;
    END
  END t_d[15]
  PIN t_d[160]
    DIRECTION OUTPUT ;
    USE SIGNAL ;
    PORT
      LAYER M4 ;
        RECT  0 47.568 0.084 47.592 ;
    END
  END t_d[160]
  PIN t_d[161]
    DIRECTION OUTPUT ;
    USE SIGNAL ;
    PORT
      LAYER M4 ;
        RECT  0 47.616 0.084 47.64 ;
    END
  END t_d[161]
  PIN t_d[162]
    DIRECTION OUTPUT ;
    USE SIGNAL ;
    PORT
      LAYER M4 ;
        RECT  0 47.664 0.084 47.688 ;
    END
  END t_d[162]
  PIN t_d[163]
    DIRECTION OUTPUT ;
    USE SIGNAL ;
    PORT
      LAYER M4 ;
        RECT  0 47.712 0.084 47.736 ;
    END
  END t_d[163]
  PIN t_d[164]
    DIRECTION OUTPUT ;
    USE SIGNAL ;
    PORT
      LAYER M4 ;
        RECT  0 47.76 0.084 47.784 ;
    END
  END t_d[164]
  PIN t_d[165]
    DIRECTION OUTPUT ;
    USE SIGNAL ;
    PORT
      LAYER M4 ;
        RECT  0 47.808 0.084 47.832 ;
    END
  END t_d[165]
  PIN t_d[166]
    DIRECTION OUTPUT ;
    USE SIGNAL ;
    PORT
      LAYER M4 ;
        RECT  0 47.856 0.084 47.88 ;
    END
  END t_d[166]
  PIN t_d[167]
    DIRECTION OUTPUT ;
    USE SIGNAL ;
    PORT
      LAYER M4 ;
        RECT  0 47.904 0.084 47.928 ;
    END
  END t_d[167]
  PIN t_d[168]
    DIRECTION OUTPUT ;
    USE SIGNAL ;
    PORT
      LAYER M4 ;
        RECT  0 47.952 0.084 47.976 ;
    END
  END t_d[168]
  PIN t_d[169]
    DIRECTION OUTPUT ;
    USE SIGNAL ;
    PORT
      LAYER M4 ;
        RECT  0 48 0.084 48.024 ;
    END
  END t_d[169]
  PIN t_d[16]
    DIRECTION OUTPUT ;
    USE SIGNAL ;
    PORT
      LAYER M4 ;
        RECT  0 40.656 0.084 40.68 ;
    END
  END t_d[16]
  PIN t_d[170]
    DIRECTION OUTPUT ;
    USE SIGNAL ;
    PORT
      LAYER M4 ;
        RECT  0 48.048 0.084 48.072 ;
    END
  END t_d[170]
  PIN t_d[171]
    DIRECTION OUTPUT ;
    USE SIGNAL ;
    PORT
      LAYER M4 ;
        RECT  0 48.096 0.084 48.12 ;
    END
  END t_d[171]
  PIN t_d[172]
    DIRECTION OUTPUT ;
    USE SIGNAL ;
    PORT
      LAYER M4 ;
        RECT  0 48.144 0.084 48.168 ;
    END
  END t_d[172]
  PIN t_d[173]
    DIRECTION OUTPUT ;
    USE SIGNAL ;
    PORT
      LAYER M4 ;
        RECT  0 48.192 0.084 48.216 ;
    END
  END t_d[173]
  PIN t_d[174]
    DIRECTION OUTPUT ;
    USE SIGNAL ;
    PORT
      LAYER M4 ;
        RECT  0 48.24 0.084 48.264 ;
    END
  END t_d[174]
  PIN t_d[175]
    DIRECTION OUTPUT ;
    USE SIGNAL ;
    PORT
      LAYER M4 ;
        RECT  0 48.288 0.084 48.312 ;
    END
  END t_d[175]
  PIN t_d[176]
    DIRECTION OUTPUT ;
    USE SIGNAL ;
    PORT
      LAYER M4 ;
        RECT  0 48.336 0.084 48.36 ;
    END
  END t_d[176]
  PIN t_d[177]
    DIRECTION OUTPUT ;
    USE SIGNAL ;
    PORT
      LAYER M4 ;
        RECT  0 48.384 0.084 48.408 ;
    END
  END t_d[177]
  PIN t_d[178]
    DIRECTION OUTPUT ;
    USE SIGNAL ;
    PORT
      LAYER M4 ;
        RECT  0 48.432 0.084 48.456 ;
    END
  END t_d[178]
  PIN t_d[179]
    DIRECTION OUTPUT ;
    USE SIGNAL ;
    PORT
      LAYER M4 ;
        RECT  0 48.48 0.084 48.504 ;
    END
  END t_d[179]
  PIN t_d[17]
    DIRECTION OUTPUT ;
    USE SIGNAL ;
    PORT
      LAYER M4 ;
        RECT  0 40.704 0.084 40.728 ;
    END
  END t_d[17]
  PIN t_d[180]
    DIRECTION OUTPUT ;
    USE SIGNAL ;
    PORT
      LAYER M4 ;
        RECT  0 48.528 0.084 48.552 ;
    END
  END t_d[180]
  PIN t_d[181]
    DIRECTION OUTPUT ;
    USE SIGNAL ;
    PORT
      LAYER M4 ;
        RECT  0 48.576 0.084 48.6 ;
    END
  END t_d[181]
  PIN t_d[182]
    DIRECTION OUTPUT ;
    USE SIGNAL ;
    PORT
      LAYER M4 ;
        RECT  0 48.624 0.084 48.648 ;
    END
  END t_d[182]
  PIN t_d[183]
    DIRECTION OUTPUT ;
    USE SIGNAL ;
    PORT
      LAYER M4 ;
        RECT  0 48.672 0.084 48.696 ;
    END
  END t_d[183]
  PIN t_d[184]
    DIRECTION OUTPUT ;
    USE SIGNAL ;
    PORT
      LAYER M4 ;
        RECT  0 48.72 0.084 48.744 ;
    END
  END t_d[184]
  PIN t_d[185]
    DIRECTION OUTPUT ;
    USE SIGNAL ;
    PORT
      LAYER M4 ;
        RECT  0 48.768 0.084 48.792 ;
    END
  END t_d[185]
  PIN t_d[186]
    DIRECTION OUTPUT ;
    USE SIGNAL ;
    PORT
      LAYER M4 ;
        RECT  0 48.816 0.084 48.84 ;
    END
  END t_d[186]
  PIN t_d[187]
    DIRECTION OUTPUT ;
    USE SIGNAL ;
    PORT
      LAYER M4 ;
        RECT  0 48.864 0.084 48.888 ;
    END
  END t_d[187]
  PIN t_d[188]
    DIRECTION OUTPUT ;
    USE SIGNAL ;
    PORT
      LAYER M4 ;
        RECT  0 48.912 0.084 48.936 ;
    END
  END t_d[188]
  PIN t_d[189]
    DIRECTION OUTPUT ;
    USE SIGNAL ;
    PORT
      LAYER M4 ;
        RECT  0 48.96 0.084 48.984 ;
    END
  END t_d[189]
  PIN t_d[18]
    DIRECTION OUTPUT ;
    USE SIGNAL ;
    PORT
      LAYER M4 ;
        RECT  0 40.752 0.084 40.776 ;
    END
  END t_d[18]
  PIN t_d[190]
    DIRECTION OUTPUT ;
    USE SIGNAL ;
    PORT
      LAYER M4 ;
        RECT  0 49.008 0.084 49.032 ;
    END
  END t_d[190]
  PIN t_d[191]
    DIRECTION OUTPUT ;
    USE SIGNAL ;
    PORT
      LAYER M4 ;
        RECT  0 49.056 0.084 49.08 ;
    END
  END t_d[191]
  PIN t_d[192]
    DIRECTION OUTPUT ;
    USE SIGNAL ;
    PORT
      LAYER M4 ;
        RECT  0 49.104 0.084 49.128 ;
    END
  END t_d[192]
  PIN t_d[193]
    DIRECTION OUTPUT ;
    USE SIGNAL ;
    PORT
      LAYER M4 ;
        RECT  0 49.152 0.084 49.176 ;
    END
  END t_d[193]
  PIN t_d[194]
    DIRECTION OUTPUT ;
    USE SIGNAL ;
    PORT
      LAYER M4 ;
        RECT  0 49.2 0.084 49.224 ;
    END
  END t_d[194]
  PIN t_d[195]
    DIRECTION OUTPUT ;
    USE SIGNAL ;
    PORT
      LAYER M4 ;
        RECT  0 49.248 0.084 49.272 ;
    END
  END t_d[195]
  PIN t_d[196]
    DIRECTION OUTPUT ;
    USE SIGNAL ;
    PORT
      LAYER M4 ;
        RECT  0 49.296 0.084 49.32 ;
    END
  END t_d[196]
  PIN t_d[197]
    DIRECTION OUTPUT ;
    USE SIGNAL ;
    PORT
      LAYER M4 ;
        RECT  0 49.344 0.084 49.368 ;
    END
  END t_d[197]
  PIN t_d[198]
    DIRECTION OUTPUT ;
    USE SIGNAL ;
    PORT
      LAYER M4 ;
        RECT  0 49.392 0.084 49.416 ;
    END
  END t_d[198]
  PIN t_d[199]
    DIRECTION OUTPUT ;
    USE SIGNAL ;
    PORT
      LAYER M4 ;
        RECT  0 49.44 0.084 49.464 ;
    END
  END t_d[199]
  PIN t_d[19]
    DIRECTION OUTPUT ;
    USE SIGNAL ;
    PORT
      LAYER M4 ;
        RECT  0 40.8 0.084 40.824 ;
    END
  END t_d[19]
  PIN t_d[1]
    DIRECTION OUTPUT ;
    USE SIGNAL ;
    PORT
      LAYER M4 ;
        RECT  0 39.936 0.084 39.96 ;
    END
  END t_d[1]
  PIN t_d[200]
    DIRECTION OUTPUT ;
    USE SIGNAL ;
    PORT
      LAYER M4 ;
        RECT  0 49.488 0.084 49.512 ;
    END
  END t_d[200]
  PIN t_d[201]
    DIRECTION OUTPUT ;
    USE SIGNAL ;
    PORT
      LAYER M4 ;
        RECT  0 49.536 0.084 49.56 ;
    END
  END t_d[201]
  PIN t_d[202]
    DIRECTION OUTPUT ;
    USE SIGNAL ;
    PORT
      LAYER M4 ;
        RECT  0 49.584 0.084 49.608 ;
    END
  END t_d[202]
  PIN t_d[203]
    DIRECTION OUTPUT ;
    USE SIGNAL ;
    PORT
      LAYER M4 ;
        RECT  0 49.632 0.084 49.656 ;
    END
  END t_d[203]
  PIN t_d[204]
    DIRECTION OUTPUT ;
    USE SIGNAL ;
    PORT
      LAYER M4 ;
        RECT  0 49.68 0.084 49.704 ;
    END
  END t_d[204]
  PIN t_d[205]
    DIRECTION OUTPUT ;
    USE SIGNAL ;
    PORT
      LAYER M4 ;
        RECT  0 49.728 0.084 49.752 ;
    END
  END t_d[205]
  PIN t_d[206]
    DIRECTION OUTPUT ;
    USE SIGNAL ;
    PORT
      LAYER M4 ;
        RECT  0 49.776 0.084 49.8 ;
    END
  END t_d[206]
  PIN t_d[207]
    DIRECTION OUTPUT ;
    USE SIGNAL ;
    PORT
      LAYER M4 ;
        RECT  0 49.824 0.084 49.848 ;
    END
  END t_d[207]
  PIN t_d[208]
    DIRECTION OUTPUT ;
    USE SIGNAL ;
    PORT
      LAYER M4 ;
        RECT  0 49.872 0.084 49.896 ;
    END
  END t_d[208]
  PIN t_d[209]
    DIRECTION OUTPUT ;
    USE SIGNAL ;
    PORT
      LAYER M4 ;
        RECT  0 49.92 0.084 49.944 ;
    END
  END t_d[209]
  PIN t_d[20]
    DIRECTION OUTPUT ;
    USE SIGNAL ;
    PORT
      LAYER M4 ;
        RECT  0 40.848 0.084 40.872 ;
    END
  END t_d[20]
  PIN t_d[210]
    DIRECTION OUTPUT ;
    USE SIGNAL ;
    PORT
      LAYER M4 ;
        RECT  0 49.968 0.084 49.992 ;
    END
  END t_d[210]
  PIN t_d[211]
    DIRECTION OUTPUT ;
    USE SIGNAL ;
    PORT
      LAYER M4 ;
        RECT  0 50.016 0.084 50.04 ;
    END
  END t_d[211]
  PIN t_d[212]
    DIRECTION OUTPUT ;
    USE SIGNAL ;
    PORT
      LAYER M4 ;
        RECT  0 50.064 0.084 50.088 ;
    END
  END t_d[212]
  PIN t_d[213]
    DIRECTION OUTPUT ;
    USE SIGNAL ;
    PORT
      LAYER M4 ;
        RECT  0 50.112 0.084 50.136 ;
    END
  END t_d[213]
  PIN t_d[214]
    DIRECTION OUTPUT ;
    USE SIGNAL ;
    PORT
      LAYER M4 ;
        RECT  0 50.16 0.084 50.184 ;
    END
  END t_d[214]
  PIN t_d[215]
    DIRECTION OUTPUT ;
    USE SIGNAL ;
    PORT
      LAYER M4 ;
        RECT  0 50.208 0.084 50.232 ;
    END
  END t_d[215]
  PIN t_d[216]
    DIRECTION OUTPUT ;
    USE SIGNAL ;
    PORT
      LAYER M4 ;
        RECT  0 50.256 0.084 50.28 ;
    END
  END t_d[216]
  PIN t_d[217]
    DIRECTION OUTPUT ;
    USE SIGNAL ;
    PORT
      LAYER M4 ;
        RECT  0 50.304 0.084 50.328 ;
    END
  END t_d[217]
  PIN t_d[218]
    DIRECTION OUTPUT ;
    USE SIGNAL ;
    PORT
      LAYER M4 ;
        RECT  0 50.352 0.084 50.376 ;
    END
  END t_d[218]
  PIN t_d[219]
    DIRECTION OUTPUT ;
    USE SIGNAL ;
    PORT
      LAYER M4 ;
        RECT  0 50.4 0.084 50.424 ;
    END
  END t_d[219]
  PIN t_d[21]
    DIRECTION OUTPUT ;
    USE SIGNAL ;
    PORT
      LAYER M4 ;
        RECT  0 40.896 0.084 40.92 ;
    END
  END t_d[21]
  PIN t_d[220]
    DIRECTION OUTPUT ;
    USE SIGNAL ;
    PORT
      LAYER M4 ;
        RECT  0 50.448 0.084 50.472 ;
    END
  END t_d[220]
  PIN t_d[221]
    DIRECTION OUTPUT ;
    USE SIGNAL ;
    PORT
      LAYER M4 ;
        RECT  0 50.496 0.084 50.52 ;
    END
  END t_d[221]
  PIN t_d[222]
    DIRECTION OUTPUT ;
    USE SIGNAL ;
    PORT
      LAYER M4 ;
        RECT  0 50.544 0.084 50.568 ;
    END
  END t_d[222]
  PIN t_d[223]
    DIRECTION OUTPUT ;
    USE SIGNAL ;
    PORT
      LAYER M4 ;
        RECT  0 50.592 0.084 50.616 ;
    END
  END t_d[223]
  PIN t_d[224]
    DIRECTION OUTPUT ;
    USE SIGNAL ;
    PORT
      LAYER M4 ;
        RECT  0 50.64 0.084 50.664 ;
    END
  END t_d[224]
  PIN t_d[225]
    DIRECTION OUTPUT ;
    USE SIGNAL ;
    PORT
      LAYER M4 ;
        RECT  0 50.688 0.084 50.712 ;
    END
  END t_d[225]
  PIN t_d[226]
    DIRECTION OUTPUT ;
    USE SIGNAL ;
    PORT
      LAYER M4 ;
        RECT  0 50.736 0.084 50.76 ;
    END
  END t_d[226]
  PIN t_d[227]
    DIRECTION OUTPUT ;
    USE SIGNAL ;
    PORT
      LAYER M4 ;
        RECT  0 50.784 0.084 50.808 ;
    END
  END t_d[227]
  PIN t_d[228]
    DIRECTION OUTPUT ;
    USE SIGNAL ;
    PORT
      LAYER M4 ;
        RECT  0 50.832 0.084 50.856 ;
    END
  END t_d[228]
  PIN t_d[229]
    DIRECTION OUTPUT ;
    USE SIGNAL ;
    PORT
      LAYER M4 ;
        RECT  0 50.88 0.084 50.904 ;
    END
  END t_d[229]
  PIN t_d[22]
    DIRECTION OUTPUT ;
    USE SIGNAL ;
    PORT
      LAYER M4 ;
        RECT  0 40.944 0.084 40.968 ;
    END
  END t_d[22]
  PIN t_d[230]
    DIRECTION OUTPUT ;
    USE SIGNAL ;
    PORT
      LAYER M4 ;
        RECT  0 50.928 0.084 50.952 ;
    END
  END t_d[230]
  PIN t_d[231]
    DIRECTION OUTPUT ;
    USE SIGNAL ;
    PORT
      LAYER M4 ;
        RECT  0 50.976 0.084 51 ;
    END
  END t_d[231]
  PIN t_d[232]
    DIRECTION OUTPUT ;
    USE SIGNAL ;
    PORT
      LAYER M4 ;
        RECT  0 51.024 0.084 51.048 ;
    END
  END t_d[232]
  PIN t_d[233]
    DIRECTION OUTPUT ;
    USE SIGNAL ;
    PORT
      LAYER M4 ;
        RECT  0 51.072 0.084 51.096 ;
    END
  END t_d[233]
  PIN t_d[234]
    DIRECTION OUTPUT ;
    USE SIGNAL ;
    PORT
      LAYER M4 ;
        RECT  0 51.12 0.084 51.144 ;
    END
  END t_d[234]
  PIN t_d[235]
    DIRECTION OUTPUT ;
    USE SIGNAL ;
    PORT
      LAYER M4 ;
        RECT  0 51.168 0.084 51.192 ;
    END
  END t_d[235]
  PIN t_d[236]
    DIRECTION OUTPUT ;
    USE SIGNAL ;
    PORT
      LAYER M4 ;
        RECT  0 51.216 0.084 51.24 ;
    END
  END t_d[236]
  PIN t_d[237]
    DIRECTION OUTPUT ;
    USE SIGNAL ;
    PORT
      LAYER M4 ;
        RECT  0 51.264 0.084 51.288 ;
    END
  END t_d[237]
  PIN t_d[238]
    DIRECTION OUTPUT ;
    USE SIGNAL ;
    PORT
      LAYER M4 ;
        RECT  0 51.312 0.084 51.336 ;
    END
  END t_d[238]
  PIN t_d[239]
    DIRECTION OUTPUT ;
    USE SIGNAL ;
    PORT
      LAYER M4 ;
        RECT  0 51.36 0.084 51.384 ;
    END
  END t_d[239]
  PIN t_d[23]
    DIRECTION OUTPUT ;
    USE SIGNAL ;
    PORT
      LAYER M4 ;
        RECT  0 40.992 0.084 41.016 ;
    END
  END t_d[23]
  PIN t_d[240]
    DIRECTION OUTPUT ;
    USE SIGNAL ;
    PORT
      LAYER M4 ;
        RECT  0 51.408 0.084 51.432 ;
    END
  END t_d[240]
  PIN t_d[241]
    DIRECTION OUTPUT ;
    USE SIGNAL ;
    PORT
      LAYER M4 ;
        RECT  0 51.456 0.084 51.48 ;
    END
  END t_d[241]
  PIN t_d[242]
    DIRECTION OUTPUT ;
    USE SIGNAL ;
    PORT
      LAYER M4 ;
        RECT  0 51.504 0.084 51.528 ;
    END
  END t_d[242]
  PIN t_d[243]
    DIRECTION OUTPUT ;
    USE SIGNAL ;
    PORT
      LAYER M4 ;
        RECT  0 51.552 0.084 51.576 ;
    END
  END t_d[243]
  PIN t_d[244]
    DIRECTION OUTPUT ;
    USE SIGNAL ;
    PORT
      LAYER M4 ;
        RECT  0 51.6 0.084 51.624 ;
    END
  END t_d[244]
  PIN t_d[245]
    DIRECTION OUTPUT ;
    USE SIGNAL ;
    PORT
      LAYER M4 ;
        RECT  0 51.648 0.084 51.672 ;
    END
  END t_d[245]
  PIN t_d[246]
    DIRECTION OUTPUT ;
    USE SIGNAL ;
    PORT
      LAYER M4 ;
        RECT  0 51.696 0.084 51.72 ;
    END
  END t_d[246]
  PIN t_d[247]
    DIRECTION OUTPUT ;
    USE SIGNAL ;
    PORT
      LAYER M4 ;
        RECT  0 51.744 0.084 51.768 ;
    END
  END t_d[247]
  PIN t_d[248]
    DIRECTION OUTPUT ;
    USE SIGNAL ;
    PORT
      LAYER M4 ;
        RECT  0 51.792 0.084 51.816 ;
    END
  END t_d[248]
  PIN t_d[249]
    DIRECTION OUTPUT ;
    USE SIGNAL ;
    PORT
      LAYER M4 ;
        RECT  0 51.84 0.084 51.864 ;
    END
  END t_d[249]
  PIN t_d[24]
    DIRECTION OUTPUT ;
    USE SIGNAL ;
    PORT
      LAYER M4 ;
        RECT  0 41.04 0.084 41.064 ;
    END
  END t_d[24]
  PIN t_d[250]
    DIRECTION OUTPUT ;
    USE SIGNAL ;
    PORT
      LAYER M4 ;
        RECT  0 51.888 0.084 51.912 ;
    END
  END t_d[250]
  PIN t_d[251]
    DIRECTION OUTPUT ;
    USE SIGNAL ;
    PORT
      LAYER M4 ;
        RECT  0 51.936 0.084 51.96 ;
    END
  END t_d[251]
  PIN t_d[252]
    DIRECTION OUTPUT ;
    USE SIGNAL ;
    PORT
      LAYER M4 ;
        RECT  0 51.984 0.084 52.008 ;
    END
  END t_d[252]
  PIN t_d[253]
    DIRECTION OUTPUT ;
    USE SIGNAL ;
    PORT
      LAYER M4 ;
        RECT  0 52.032 0.084 52.056 ;
    END
  END t_d[253]
  PIN t_d[254]
    DIRECTION OUTPUT ;
    USE SIGNAL ;
    PORT
      LAYER M4 ;
        RECT  0 52.08 0.084 52.104 ;
    END
  END t_d[254]
  PIN t_d[255]
    DIRECTION OUTPUT ;
    USE SIGNAL ;
    PORT
      LAYER M4 ;
        RECT  0 52.128 0.084 52.152 ;
    END
  END t_d[255]
  PIN t_d[256]
    DIRECTION OUTPUT ;
    USE SIGNAL ;
    PORT
      LAYER M4 ;
        RECT  0 52.176 0.084 52.2 ;
    END
  END t_d[256]
  PIN t_d[257]
    DIRECTION OUTPUT ;
    USE SIGNAL ;
    PORT
      LAYER M4 ;
        RECT  0 52.224 0.084 52.248 ;
    END
  END t_d[257]
  PIN t_d[258]
    DIRECTION OUTPUT ;
    USE SIGNAL ;
    PORT
      LAYER M4 ;
        RECT  0 52.272 0.084 52.296 ;
    END
  END t_d[258]
  PIN t_d[259]
    DIRECTION OUTPUT ;
    USE SIGNAL ;
    PORT
      LAYER M4 ;
        RECT  0 52.32 0.084 52.344 ;
    END
  END t_d[259]
  PIN t_d[25]
    DIRECTION OUTPUT ;
    USE SIGNAL ;
    PORT
      LAYER M4 ;
        RECT  0 41.088 0.084 41.112 ;
    END
  END t_d[25]
  PIN t_d[260]
    DIRECTION OUTPUT ;
    USE SIGNAL ;
    PORT
      LAYER M4 ;
        RECT  0 52.368 0.084 52.392 ;
    END
  END t_d[260]
  PIN t_d[261]
    DIRECTION OUTPUT ;
    USE SIGNAL ;
    PORT
      LAYER M4 ;
        RECT  0 52.416 0.084 52.44 ;
    END
  END t_d[261]
  PIN t_d[262]
    DIRECTION OUTPUT ;
    USE SIGNAL ;
    PORT
      LAYER M4 ;
        RECT  0 52.464 0.084 52.488 ;
    END
  END t_d[262]
  PIN t_d[263]
    DIRECTION OUTPUT ;
    USE SIGNAL ;
    PORT
      LAYER M4 ;
        RECT  0 52.512 0.084 52.536 ;
    END
  END t_d[263]
  PIN t_d[264]
    DIRECTION OUTPUT ;
    USE SIGNAL ;
    PORT
      LAYER M4 ;
        RECT  0 52.56 0.084 52.584 ;
    END
  END t_d[264]
  PIN t_d[265]
    DIRECTION OUTPUT ;
    USE SIGNAL ;
    PORT
      LAYER M4 ;
        RECT  0 52.608 0.084 52.632 ;
    END
  END t_d[265]
  PIN t_d[266]
    DIRECTION OUTPUT ;
    USE SIGNAL ;
    PORT
      LAYER M4 ;
        RECT  0 52.656 0.084 52.68 ;
    END
  END t_d[266]
  PIN t_d[267]
    DIRECTION OUTPUT ;
    USE SIGNAL ;
    PORT
      LAYER M4 ;
        RECT  0 52.704 0.084 52.728 ;
    END
  END t_d[267]
  PIN t_d[268]
    DIRECTION OUTPUT ;
    USE SIGNAL ;
    PORT
      LAYER M4 ;
        RECT  0 52.752 0.084 52.776 ;
    END
  END t_d[268]
  PIN t_d[269]
    DIRECTION OUTPUT ;
    USE SIGNAL ;
    PORT
      LAYER M4 ;
        RECT  0 52.8 0.084 52.824 ;
    END
  END t_d[269]
  PIN t_d[26]
    DIRECTION OUTPUT ;
    USE SIGNAL ;
    PORT
      LAYER M4 ;
        RECT  0 41.136 0.084 41.16 ;
    END
  END t_d[26]
  PIN t_d[270]
    DIRECTION OUTPUT ;
    USE SIGNAL ;
    PORT
      LAYER M4 ;
        RECT  0 52.848 0.084 52.872 ;
    END
  END t_d[270]
  PIN t_d[271]
    DIRECTION OUTPUT ;
    USE SIGNAL ;
    PORT
      LAYER M4 ;
        RECT  0 52.896 0.084 52.92 ;
    END
  END t_d[271]
  PIN t_d[272]
    DIRECTION OUTPUT ;
    USE SIGNAL ;
    PORT
      LAYER M4 ;
        RECT  0 52.944 0.084 52.968 ;
    END
  END t_d[272]
  PIN t_d[273]
    DIRECTION OUTPUT ;
    USE SIGNAL ;
    PORT
      LAYER M4 ;
        RECT  0 52.992 0.084 53.016 ;
    END
  END t_d[273]
  PIN t_d[274]
    DIRECTION OUTPUT ;
    USE SIGNAL ;
    PORT
      LAYER M4 ;
        RECT  0 53.04 0.084 53.064 ;
    END
  END t_d[274]
  PIN t_d[275]
    DIRECTION OUTPUT ;
    USE SIGNAL ;
    PORT
      LAYER M4 ;
        RECT  0 53.088 0.084 53.112 ;
    END
  END t_d[275]
  PIN t_d[276]
    DIRECTION OUTPUT ;
    USE SIGNAL ;
    PORT
      LAYER M4 ;
        RECT  0 53.136 0.084 53.16 ;
    END
  END t_d[276]
  PIN t_d[277]
    DIRECTION OUTPUT ;
    USE SIGNAL ;
    PORT
      LAYER M4 ;
        RECT  0 53.184 0.084 53.208 ;
    END
  END t_d[277]
  PIN t_d[278]
    DIRECTION OUTPUT ;
    USE SIGNAL ;
    PORT
      LAYER M4 ;
        RECT  0 53.232 0.084 53.256 ;
    END
  END t_d[278]
  PIN t_d[279]
    DIRECTION OUTPUT ;
    USE SIGNAL ;
    PORT
      LAYER M4 ;
        RECT  0 53.28 0.084 53.304 ;
    END
  END t_d[279]
  PIN t_d[27]
    DIRECTION OUTPUT ;
    USE SIGNAL ;
    PORT
      LAYER M4 ;
        RECT  0 41.184 0.084 41.208 ;
    END
  END t_d[27]
  PIN t_d[280]
    DIRECTION OUTPUT ;
    USE SIGNAL ;
    PORT
      LAYER M4 ;
        RECT  0 53.328 0.084 53.352 ;
    END
  END t_d[280]
  PIN t_d[281]
    DIRECTION OUTPUT ;
    USE SIGNAL ;
    PORT
      LAYER M4 ;
        RECT  0 53.376 0.084 53.4 ;
    END
  END t_d[281]
  PIN t_d[282]
    DIRECTION OUTPUT ;
    USE SIGNAL ;
    PORT
      LAYER M4 ;
        RECT  0 53.424 0.084 53.448 ;
    END
  END t_d[282]
  PIN t_d[283]
    DIRECTION OUTPUT ;
    USE SIGNAL ;
    PORT
      LAYER M4 ;
        RECT  0 53.472 0.084 53.496 ;
    END
  END t_d[283]
  PIN t_d[284]
    DIRECTION OUTPUT ;
    USE SIGNAL ;
    PORT
      LAYER M4 ;
        RECT  0 53.52 0.084 53.544 ;
    END
  END t_d[284]
  PIN t_d[285]
    DIRECTION OUTPUT ;
    USE SIGNAL ;
    PORT
      LAYER M4 ;
        RECT  0 53.568 0.084 53.592 ;
    END
  END t_d[285]
  PIN t_d[286]
    DIRECTION OUTPUT ;
    USE SIGNAL ;
    PORT
      LAYER M4 ;
        RECT  0 53.616 0.084 53.64 ;
    END
  END t_d[286]
  PIN t_d[287]
    DIRECTION OUTPUT ;
    USE SIGNAL ;
    PORT
      LAYER M4 ;
        RECT  0 53.664 0.084 53.688 ;
    END
  END t_d[287]
  PIN t_d[288]
    DIRECTION OUTPUT ;
    USE SIGNAL ;
    PORT
      LAYER M4 ;
        RECT  0 53.712 0.084 53.736 ;
    END
  END t_d[288]
  PIN t_d[289]
    DIRECTION OUTPUT ;
    USE SIGNAL ;
    PORT
      LAYER M4 ;
        RECT  0 53.76 0.084 53.784 ;
    END
  END t_d[289]
  PIN t_d[28]
    DIRECTION OUTPUT ;
    USE SIGNAL ;
    PORT
      LAYER M4 ;
        RECT  0 41.232 0.084 41.256 ;
    END
  END t_d[28]
  PIN t_d[290]
    DIRECTION OUTPUT ;
    USE SIGNAL ;
    PORT
      LAYER M4 ;
        RECT  0 53.808 0.084 53.832 ;
    END
  END t_d[290]
  PIN t_d[291]
    DIRECTION OUTPUT ;
    USE SIGNAL ;
    PORT
      LAYER M4 ;
        RECT  0 53.856 0.084 53.88 ;
    END
  END t_d[291]
  PIN t_d[292]
    DIRECTION OUTPUT ;
    USE SIGNAL ;
    PORT
      LAYER M4 ;
        RECT  0 53.904 0.084 53.928 ;
    END
  END t_d[292]
  PIN t_d[293]
    DIRECTION OUTPUT ;
    USE SIGNAL ;
    PORT
      LAYER M4 ;
        RECT  0 53.952 0.084 53.976 ;
    END
  END t_d[293]
  PIN t_d[294]
    DIRECTION OUTPUT ;
    USE SIGNAL ;
    PORT
      LAYER M4 ;
        RECT  0 54 0.084 54.024 ;
    END
  END t_d[294]
  PIN t_d[295]
    DIRECTION OUTPUT ;
    USE SIGNAL ;
    PORT
      LAYER M4 ;
        RECT  0 54.048 0.084 54.072 ;
    END
  END t_d[295]
  PIN t_d[296]
    DIRECTION OUTPUT ;
    USE SIGNAL ;
    PORT
      LAYER M4 ;
        RECT  0 54.096 0.084 54.12 ;
    END
  END t_d[296]
  PIN t_d[297]
    DIRECTION OUTPUT ;
    USE SIGNAL ;
    PORT
      LAYER M4 ;
        RECT  0 54.144 0.084 54.168 ;
    END
  END t_d[297]
  PIN t_d[298]
    DIRECTION OUTPUT ;
    USE SIGNAL ;
    PORT
      LAYER M4 ;
        RECT  0 54.192 0.084 54.216 ;
    END
  END t_d[298]
  PIN t_d[299]
    DIRECTION OUTPUT ;
    USE SIGNAL ;
    PORT
      LAYER M4 ;
        RECT  0 54.24 0.084 54.264 ;
    END
  END t_d[299]
  PIN t_d[29]
    DIRECTION OUTPUT ;
    USE SIGNAL ;
    PORT
      LAYER M4 ;
        RECT  0 41.28 0.084 41.304 ;
    END
  END t_d[29]
  PIN t_d[2]
    DIRECTION OUTPUT ;
    USE SIGNAL ;
    PORT
      LAYER M4 ;
        RECT  0 39.984 0.084 40.008 ;
    END
  END t_d[2]
  PIN t_d[300]
    DIRECTION OUTPUT ;
    USE SIGNAL ;
    PORT
      LAYER M4 ;
        RECT  0 54.288 0.084 54.312 ;
    END
  END t_d[300]
  PIN t_d[301]
    DIRECTION OUTPUT ;
    USE SIGNAL ;
    PORT
      LAYER M4 ;
        RECT  0 54.336 0.084 54.36 ;
    END
  END t_d[301]
  PIN t_d[302]
    DIRECTION OUTPUT ;
    USE SIGNAL ;
    PORT
      LAYER M4 ;
        RECT  0 54.384 0.084 54.408 ;
    END
  END t_d[302]
  PIN t_d[303]
    DIRECTION OUTPUT ;
    USE SIGNAL ;
    PORT
      LAYER M4 ;
        RECT  0 54.432 0.084 54.456 ;
    END
  END t_d[303]
  PIN t_d[304]
    DIRECTION OUTPUT ;
    USE SIGNAL ;
    PORT
      LAYER M4 ;
        RECT  0 54.48 0.084 54.504 ;
    END
  END t_d[304]
  PIN t_d[305]
    DIRECTION OUTPUT ;
    USE SIGNAL ;
    PORT
      LAYER M4 ;
        RECT  0 54.528 0.084 54.552 ;
    END
  END t_d[305]
  PIN t_d[306]
    DIRECTION OUTPUT ;
    USE SIGNAL ;
    PORT
      LAYER M4 ;
        RECT  0 54.576 0.084 54.6 ;
    END
  END t_d[306]
  PIN t_d[307]
    DIRECTION OUTPUT ;
    USE SIGNAL ;
    PORT
      LAYER M4 ;
        RECT  0 54.624 0.084 54.648 ;
    END
  END t_d[307]
  PIN t_d[308]
    DIRECTION OUTPUT ;
    USE SIGNAL ;
    PORT
      LAYER M4 ;
        RECT  0 54.672 0.084 54.696 ;
    END
  END t_d[308]
  PIN t_d[309]
    DIRECTION OUTPUT ;
    USE SIGNAL ;
    PORT
      LAYER M4 ;
        RECT  0 54.72 0.084 54.744 ;
    END
  END t_d[309]
  PIN t_d[30]
    DIRECTION OUTPUT ;
    USE SIGNAL ;
    PORT
      LAYER M4 ;
        RECT  0 41.328 0.084 41.352 ;
    END
  END t_d[30]
  PIN t_d[310]
    DIRECTION OUTPUT ;
    USE SIGNAL ;
    PORT
      LAYER M4 ;
        RECT  0 54.768 0.084 54.792 ;
    END
  END t_d[310]
  PIN t_d[311]
    DIRECTION OUTPUT ;
    USE SIGNAL ;
    PORT
      LAYER M4 ;
        RECT  0 54.816 0.084 54.84 ;
    END
  END t_d[311]
  PIN t_d[312]
    DIRECTION OUTPUT ;
    USE SIGNAL ;
    PORT
      LAYER M4 ;
        RECT  0 54.864 0.084 54.888 ;
    END
  END t_d[312]
  PIN t_d[313]
    DIRECTION OUTPUT ;
    USE SIGNAL ;
    PORT
      LAYER M4 ;
        RECT  0 54.912 0.084 54.936 ;
    END
  END t_d[313]
  PIN t_d[314]
    DIRECTION OUTPUT ;
    USE SIGNAL ;
    PORT
      LAYER M4 ;
        RECT  0 54.96 0.084 54.984 ;
    END
  END t_d[314]
  PIN t_d[315]
    DIRECTION OUTPUT ;
    USE SIGNAL ;
    PORT
      LAYER M4 ;
        RECT  0 55.008 0.084 55.032 ;
    END
  END t_d[315]
  PIN t_d[316]
    DIRECTION OUTPUT ;
    USE SIGNAL ;
    PORT
      LAYER M4 ;
        RECT  0 55.056 0.084 55.08 ;
    END
  END t_d[316]
  PIN t_d[317]
    DIRECTION OUTPUT ;
    USE SIGNAL ;
    PORT
      LAYER M4 ;
        RECT  0 55.104 0.084 55.128 ;
    END
  END t_d[317]
  PIN t_d[318]
    DIRECTION OUTPUT ;
    USE SIGNAL ;
    PORT
      LAYER M4 ;
        RECT  0 55.152 0.084 55.176 ;
    END
  END t_d[318]
  PIN t_d[319]
    DIRECTION OUTPUT ;
    USE SIGNAL ;
    PORT
      LAYER M4 ;
        RECT  0 55.2 0.084 55.224 ;
    END
  END t_d[319]
  PIN t_d[31]
    DIRECTION OUTPUT ;
    USE SIGNAL ;
    PORT
      LAYER M4 ;
        RECT  0 41.376 0.084 41.4 ;
    END
  END t_d[31]
  PIN t_d[320]
    DIRECTION OUTPUT ;
    USE SIGNAL ;
    PORT
      LAYER M4 ;
        RECT  0 55.248 0.084 55.272 ;
    END
  END t_d[320]
  PIN t_d[321]
    DIRECTION OUTPUT ;
    USE SIGNAL ;
    PORT
      LAYER M4 ;
        RECT  0 55.296 0.084 55.32 ;
    END
  END t_d[321]
  PIN t_d[322]
    DIRECTION OUTPUT ;
    USE SIGNAL ;
    PORT
      LAYER M4 ;
        RECT  0 55.344 0.084 55.368 ;
    END
  END t_d[322]
  PIN t_d[323]
    DIRECTION OUTPUT ;
    USE SIGNAL ;
    PORT
      LAYER M4 ;
        RECT  0 55.392 0.084 55.416 ;
    END
  END t_d[323]
  PIN t_d[324]
    DIRECTION OUTPUT ;
    USE SIGNAL ;
    PORT
      LAYER M4 ;
        RECT  0 55.44 0.084 55.464 ;
    END
  END t_d[324]
  PIN t_d[325]
    DIRECTION OUTPUT ;
    USE SIGNAL ;
    PORT
      LAYER M4 ;
        RECT  0 55.488 0.084 55.512 ;
    END
  END t_d[325]
  PIN t_d[326]
    DIRECTION OUTPUT ;
    USE SIGNAL ;
    PORT
      LAYER M4 ;
        RECT  0 55.536 0.084 55.56 ;
    END
  END t_d[326]
  PIN t_d[327]
    DIRECTION OUTPUT ;
    USE SIGNAL ;
    PORT
      LAYER M4 ;
        RECT  0 55.584 0.084 55.608 ;
    END
  END t_d[327]
  PIN t_d[328]
    DIRECTION OUTPUT ;
    USE SIGNAL ;
    PORT
      LAYER M4 ;
        RECT  0 55.632 0.084 55.656 ;
    END
  END t_d[328]
  PIN t_d[329]
    DIRECTION OUTPUT ;
    USE SIGNAL ;
    PORT
      LAYER M4 ;
        RECT  0 55.68 0.084 55.704 ;
    END
  END t_d[329]
  PIN t_d[32]
    DIRECTION OUTPUT ;
    USE SIGNAL ;
    PORT
      LAYER M4 ;
        RECT  0 41.424 0.084 41.448 ;
    END
  END t_d[32]
  PIN t_d[330]
    DIRECTION OUTPUT ;
    USE SIGNAL ;
    PORT
      LAYER M4 ;
        RECT  0 55.728 0.084 55.752 ;
    END
  END t_d[330]
  PIN t_d[331]
    DIRECTION OUTPUT ;
    USE SIGNAL ;
    PORT
      LAYER M4 ;
        RECT  0 55.776 0.084 55.8 ;
    END
  END t_d[331]
  PIN t_d[332]
    DIRECTION OUTPUT ;
    USE SIGNAL ;
    PORT
      LAYER M4 ;
        RECT  0 55.824 0.084 55.848 ;
    END
  END t_d[332]
  PIN t_d[333]
    DIRECTION OUTPUT ;
    USE SIGNAL ;
    PORT
      LAYER M4 ;
        RECT  0 55.872 0.084 55.896 ;
    END
  END t_d[333]
  PIN t_d[334]
    DIRECTION OUTPUT ;
    USE SIGNAL ;
    PORT
      LAYER M4 ;
        RECT  0 55.92 0.084 55.944 ;
    END
  END t_d[334]
  PIN t_d[335]
    DIRECTION OUTPUT ;
    USE SIGNAL ;
    PORT
      LAYER M4 ;
        RECT  0 55.968 0.084 55.992 ;
    END
  END t_d[335]
  PIN t_d[336]
    DIRECTION OUTPUT ;
    USE SIGNAL ;
    PORT
      LAYER M4 ;
        RECT  0 56.016 0.084 56.04 ;
    END
  END t_d[336]
  PIN t_d[337]
    DIRECTION OUTPUT ;
    USE SIGNAL ;
    PORT
      LAYER M4 ;
        RECT  0 56.064 0.084 56.088 ;
    END
  END t_d[337]
  PIN t_d[338]
    DIRECTION OUTPUT ;
    USE SIGNAL ;
    PORT
      LAYER M4 ;
        RECT  0 56.112 0.084 56.136 ;
    END
  END t_d[338]
  PIN t_d[339]
    DIRECTION OUTPUT ;
    USE SIGNAL ;
    PORT
      LAYER M4 ;
        RECT  0 56.16 0.084 56.184 ;
    END
  END t_d[339]
  PIN t_d[33]
    DIRECTION OUTPUT ;
    USE SIGNAL ;
    PORT
      LAYER M4 ;
        RECT  0 41.472 0.084 41.496 ;
    END
  END t_d[33]
  PIN t_d[340]
    DIRECTION OUTPUT ;
    USE SIGNAL ;
    PORT
      LAYER M4 ;
        RECT  0 56.208 0.084 56.232 ;
    END
  END t_d[340]
  PIN t_d[341]
    DIRECTION OUTPUT ;
    USE SIGNAL ;
    PORT
      LAYER M4 ;
        RECT  0 56.256 0.084 56.28 ;
    END
  END t_d[341]
  PIN t_d[342]
    DIRECTION OUTPUT ;
    USE SIGNAL ;
    PORT
      LAYER M4 ;
        RECT  0 56.304 0.084 56.328 ;
    END
  END t_d[342]
  PIN t_d[343]
    DIRECTION OUTPUT ;
    USE SIGNAL ;
    PORT
      LAYER M4 ;
        RECT  0 56.352 0.084 56.376 ;
    END
  END t_d[343]
  PIN t_d[344]
    DIRECTION OUTPUT ;
    USE SIGNAL ;
    PORT
      LAYER M4 ;
        RECT  0 56.4 0.084 56.424 ;
    END
  END t_d[344]
  PIN t_d[345]
    DIRECTION OUTPUT ;
    USE SIGNAL ;
    PORT
      LAYER M4 ;
        RECT  0 56.448 0.084 56.472 ;
    END
  END t_d[345]
  PIN t_d[346]
    DIRECTION OUTPUT ;
    USE SIGNAL ;
    PORT
      LAYER M4 ;
        RECT  0 56.496 0.084 56.52 ;
    END
  END t_d[346]
  PIN t_d[347]
    DIRECTION OUTPUT ;
    USE SIGNAL ;
    PORT
      LAYER M4 ;
        RECT  0 56.544 0.084 56.568 ;
    END
  END t_d[347]
  PIN t_d[348]
    DIRECTION OUTPUT ;
    USE SIGNAL ;
    PORT
      LAYER M4 ;
        RECT  0 56.592 0.084 56.616 ;
    END
  END t_d[348]
  PIN t_d[349]
    DIRECTION OUTPUT ;
    USE SIGNAL ;
    PORT
      LAYER M4 ;
        RECT  0 56.64 0.084 56.664 ;
    END
  END t_d[349]
  PIN t_d[34]
    DIRECTION OUTPUT ;
    USE SIGNAL ;
    PORT
      LAYER M4 ;
        RECT  0 41.52 0.084 41.544 ;
    END
  END t_d[34]
  PIN t_d[350]
    DIRECTION OUTPUT ;
    USE SIGNAL ;
    PORT
      LAYER M4 ;
        RECT  0 56.688 0.084 56.712 ;
    END
  END t_d[350]
  PIN t_d[351]
    DIRECTION OUTPUT ;
    USE SIGNAL ;
    PORT
      LAYER M4 ;
        RECT  0 56.736 0.084 56.76 ;
    END
  END t_d[351]
  PIN t_d[352]
    DIRECTION OUTPUT ;
    USE SIGNAL ;
    PORT
      LAYER M4 ;
        RECT  0 56.784 0.084 56.808 ;
    END
  END t_d[352]
  PIN t_d[353]
    DIRECTION OUTPUT ;
    USE SIGNAL ;
    PORT
      LAYER M4 ;
        RECT  0 56.832 0.084 56.856 ;
    END
  END t_d[353]
  PIN t_d[354]
    DIRECTION OUTPUT ;
    USE SIGNAL ;
    PORT
      LAYER M4 ;
        RECT  0 56.88 0.084 56.904 ;
    END
  END t_d[354]
  PIN t_d[355]
    DIRECTION OUTPUT ;
    USE SIGNAL ;
    PORT
      LAYER M4 ;
        RECT  0 56.928 0.084 56.952 ;
    END
  END t_d[355]
  PIN t_d[356]
    DIRECTION OUTPUT ;
    USE SIGNAL ;
    PORT
      LAYER M4 ;
        RECT  0 56.976 0.084 57 ;
    END
  END t_d[356]
  PIN t_d[357]
    DIRECTION OUTPUT ;
    USE SIGNAL ;
    PORT
      LAYER M4 ;
        RECT  0 57.024 0.084 57.048 ;
    END
  END t_d[357]
  PIN t_d[358]
    DIRECTION OUTPUT ;
    USE SIGNAL ;
    PORT
      LAYER M4 ;
        RECT  0 57.072 0.084 57.096 ;
    END
  END t_d[358]
  PIN t_d[359]
    DIRECTION OUTPUT ;
    USE SIGNAL ;
    PORT
      LAYER M4 ;
        RECT  0 57.12 0.084 57.144 ;
    END
  END t_d[359]
  PIN t_d[35]
    DIRECTION OUTPUT ;
    USE SIGNAL ;
    PORT
      LAYER M4 ;
        RECT  0 41.568 0.084 41.592 ;
    END
  END t_d[35]
  PIN t_d[360]
    DIRECTION OUTPUT ;
    USE SIGNAL ;
    PORT
      LAYER M4 ;
        RECT  0 57.168 0.084 57.192 ;
    END
  END t_d[360]
  PIN t_d[361]
    DIRECTION OUTPUT ;
    USE SIGNAL ;
    PORT
      LAYER M4 ;
        RECT  0 57.216 0.084 57.24 ;
    END
  END t_d[361]
  PIN t_d[362]
    DIRECTION OUTPUT ;
    USE SIGNAL ;
    PORT
      LAYER M4 ;
        RECT  0 57.264 0.084 57.288 ;
    END
  END t_d[362]
  PIN t_d[363]
    DIRECTION OUTPUT ;
    USE SIGNAL ;
    PORT
      LAYER M4 ;
        RECT  0 57.312 0.084 57.336 ;
    END
  END t_d[363]
  PIN t_d[364]
    DIRECTION OUTPUT ;
    USE SIGNAL ;
    PORT
      LAYER M4 ;
        RECT  0 57.36 0.084 57.384 ;
    END
  END t_d[364]
  PIN t_d[365]
    DIRECTION OUTPUT ;
    USE SIGNAL ;
    PORT
      LAYER M4 ;
        RECT  0 57.408 0.084 57.432 ;
    END
  END t_d[365]
  PIN t_d[366]
    DIRECTION OUTPUT ;
    USE SIGNAL ;
    PORT
      LAYER M4 ;
        RECT  0 57.456 0.084 57.48 ;
    END
  END t_d[366]
  PIN t_d[367]
    DIRECTION OUTPUT ;
    USE SIGNAL ;
    PORT
      LAYER M4 ;
        RECT  0 57.504 0.084 57.528 ;
    END
  END t_d[367]
  PIN t_d[368]
    DIRECTION OUTPUT ;
    USE SIGNAL ;
    PORT
      LAYER M4 ;
        RECT  0 57.552 0.084 57.576 ;
    END
  END t_d[368]
  PIN t_d[369]
    DIRECTION OUTPUT ;
    USE SIGNAL ;
    PORT
      LAYER M4 ;
        RECT  0 57.6 0.084 57.624 ;
    END
  END t_d[369]
  PIN t_d[36]
    DIRECTION OUTPUT ;
    USE SIGNAL ;
    PORT
      LAYER M4 ;
        RECT  0 41.616 0.084 41.64 ;
    END
  END t_d[36]
  PIN t_d[370]
    DIRECTION OUTPUT ;
    USE SIGNAL ;
    PORT
      LAYER M4 ;
        RECT  0 57.648 0.084 57.672 ;
    END
  END t_d[370]
  PIN t_d[371]
    DIRECTION OUTPUT ;
    USE SIGNAL ;
    PORT
      LAYER M4 ;
        RECT  0 57.696 0.084 57.72 ;
    END
  END t_d[371]
  PIN t_d[372]
    DIRECTION OUTPUT ;
    USE SIGNAL ;
    PORT
      LAYER M4 ;
        RECT  0 57.744 0.084 57.768 ;
    END
  END t_d[372]
  PIN t_d[373]
    DIRECTION OUTPUT ;
    USE SIGNAL ;
    PORT
      LAYER M4 ;
        RECT  0 57.792 0.084 57.816 ;
    END
  END t_d[373]
  PIN t_d[374]
    DIRECTION OUTPUT ;
    USE SIGNAL ;
    PORT
      LAYER M4 ;
        RECT  0 57.84 0.084 57.864 ;
    END
  END t_d[374]
  PIN t_d[375]
    DIRECTION OUTPUT ;
    USE SIGNAL ;
    PORT
      LAYER M4 ;
        RECT  0 57.888 0.084 57.912 ;
    END
  END t_d[375]
  PIN t_d[376]
    DIRECTION OUTPUT ;
    USE SIGNAL ;
    PORT
      LAYER M4 ;
        RECT  0 57.936 0.084 57.96 ;
    END
  END t_d[376]
  PIN t_d[377]
    DIRECTION OUTPUT ;
    USE SIGNAL ;
    PORT
      LAYER M4 ;
        RECT  0 57.984 0.084 58.008 ;
    END
  END t_d[377]
  PIN t_d[378]
    DIRECTION OUTPUT ;
    USE SIGNAL ;
    PORT
      LAYER M4 ;
        RECT  0 58.032 0.084 58.056 ;
    END
  END t_d[378]
  PIN t_d[379]
    DIRECTION OUTPUT ;
    USE SIGNAL ;
    PORT
      LAYER M4 ;
        RECT  0 58.08 0.084 58.104 ;
    END
  END t_d[379]
  PIN t_d[37]
    DIRECTION OUTPUT ;
    USE SIGNAL ;
    PORT
      LAYER M4 ;
        RECT  0 41.664 0.084 41.688 ;
    END
  END t_d[37]
  PIN t_d[380]
    DIRECTION OUTPUT ;
    USE SIGNAL ;
    PORT
      LAYER M4 ;
        RECT  0 58.128 0.084 58.152 ;
    END
  END t_d[380]
  PIN t_d[381]
    DIRECTION OUTPUT ;
    USE SIGNAL ;
    PORT
      LAYER M4 ;
        RECT  0 58.176 0.084 58.2 ;
    END
  END t_d[381]
  PIN t_d[382]
    DIRECTION OUTPUT ;
    USE SIGNAL ;
    PORT
      LAYER M4 ;
        RECT  0 58.224 0.084 58.248 ;
    END
  END t_d[382]
  PIN t_d[383]
    DIRECTION OUTPUT ;
    USE SIGNAL ;
    PORT
      LAYER M4 ;
        RECT  0 58.272 0.084 58.296 ;
    END
  END t_d[383]
  PIN t_d[384]
    DIRECTION OUTPUT ;
    USE SIGNAL ;
    PORT
      LAYER M4 ;
        RECT  0 58.32 0.084 58.344 ;
    END
  END t_d[384]
  PIN t_d[385]
    DIRECTION OUTPUT ;
    USE SIGNAL ;
    PORT
      LAYER M4 ;
        RECT  0 58.368 0.084 58.392 ;
    END
  END t_d[385]
  PIN t_d[386]
    DIRECTION OUTPUT ;
    USE SIGNAL ;
    PORT
      LAYER M4 ;
        RECT  0 58.416 0.084 58.44 ;
    END
  END t_d[386]
  PIN t_d[387]
    DIRECTION OUTPUT ;
    USE SIGNAL ;
    PORT
      LAYER M4 ;
        RECT  0 58.464 0.084 58.488 ;
    END
  END t_d[387]
  PIN t_d[388]
    DIRECTION OUTPUT ;
    USE SIGNAL ;
    PORT
      LAYER M4 ;
        RECT  0 58.512 0.084 58.536 ;
    END
  END t_d[388]
  PIN t_d[389]
    DIRECTION OUTPUT ;
    USE SIGNAL ;
    PORT
      LAYER M4 ;
        RECT  0 58.56 0.084 58.584 ;
    END
  END t_d[389]
  PIN t_d[38]
    DIRECTION OUTPUT ;
    USE SIGNAL ;
    PORT
      LAYER M4 ;
        RECT  0 41.712 0.084 41.736 ;
    END
  END t_d[38]
  PIN t_d[390]
    DIRECTION OUTPUT ;
    USE SIGNAL ;
    PORT
      LAYER M4 ;
        RECT  0 58.608 0.084 58.632 ;
    END
  END t_d[390]
  PIN t_d[391]
    DIRECTION OUTPUT ;
    USE SIGNAL ;
    PORT
      LAYER M4 ;
        RECT  0 58.656 0.084 58.68 ;
    END
  END t_d[391]
  PIN t_d[392]
    DIRECTION OUTPUT ;
    USE SIGNAL ;
    PORT
      LAYER M4 ;
        RECT  0 58.704 0.084 58.728 ;
    END
  END t_d[392]
  PIN t_d[393]
    DIRECTION OUTPUT ;
    USE SIGNAL ;
    PORT
      LAYER M4 ;
        RECT  0 58.752 0.084 58.776 ;
    END
  END t_d[393]
  PIN t_d[394]
    DIRECTION OUTPUT ;
    USE SIGNAL ;
    PORT
      LAYER M4 ;
        RECT  0 58.8 0.084 58.824 ;
    END
  END t_d[394]
  PIN t_d[395]
    DIRECTION OUTPUT ;
    USE SIGNAL ;
    PORT
      LAYER M4 ;
        RECT  0 58.848 0.084 58.872 ;
    END
  END t_d[395]
  PIN t_d[396]
    DIRECTION OUTPUT ;
    USE SIGNAL ;
    PORT
      LAYER M4 ;
        RECT  0 58.896 0.084 58.92 ;
    END
  END t_d[396]
  PIN t_d[397]
    DIRECTION OUTPUT ;
    USE SIGNAL ;
    PORT
      LAYER M4 ;
        RECT  0 58.944 0.084 58.968 ;
    END
  END t_d[397]
  PIN t_d[398]
    DIRECTION OUTPUT ;
    USE SIGNAL ;
    PORT
      LAYER M4 ;
        RECT  0 58.992 0.084 59.016 ;
    END
  END t_d[398]
  PIN t_d[399]
    DIRECTION OUTPUT ;
    USE SIGNAL ;
    PORT
      LAYER M4 ;
        RECT  0 59.04 0.084 59.064 ;
    END
  END t_d[399]
  PIN t_d[39]
    DIRECTION OUTPUT ;
    USE SIGNAL ;
    PORT
      LAYER M4 ;
        RECT  0 41.76 0.084 41.784 ;
    END
  END t_d[39]
  PIN t_d[3]
    DIRECTION OUTPUT ;
    USE SIGNAL ;
    PORT
      LAYER M4 ;
        RECT  0 40.032 0.084 40.056 ;
    END
  END t_d[3]
  PIN t_d[400]
    DIRECTION OUTPUT ;
    USE SIGNAL ;
    PORT
      LAYER M4 ;
        RECT  0 59.088 0.084 59.112 ;
    END
  END t_d[400]
  PIN t_d[401]
    DIRECTION OUTPUT ;
    USE SIGNAL ;
    PORT
      LAYER M4 ;
        RECT  0 59.136 0.084 59.16 ;
    END
  END t_d[401]
  PIN t_d[402]
    DIRECTION OUTPUT ;
    USE SIGNAL ;
    PORT
      LAYER M4 ;
        RECT  0 59.184 0.084 59.208 ;
    END
  END t_d[402]
  PIN t_d[403]
    DIRECTION OUTPUT ;
    USE SIGNAL ;
    PORT
      LAYER M4 ;
        RECT  0 59.232 0.084 59.256 ;
    END
  END t_d[403]
  PIN t_d[404]
    DIRECTION OUTPUT ;
    USE SIGNAL ;
    PORT
      LAYER M4 ;
        RECT  0 59.28 0.084 59.304 ;
    END
  END t_d[404]
  PIN t_d[405]
    DIRECTION OUTPUT ;
    USE SIGNAL ;
    PORT
      LAYER M4 ;
        RECT  0 59.328 0.084 59.352 ;
    END
  END t_d[405]
  PIN t_d[406]
    DIRECTION OUTPUT ;
    USE SIGNAL ;
    PORT
      LAYER M4 ;
        RECT  0 59.376 0.084 59.4 ;
    END
  END t_d[406]
  PIN t_d[407]
    DIRECTION OUTPUT ;
    USE SIGNAL ;
    PORT
      LAYER M4 ;
        RECT  0 59.424 0.084 59.448 ;
    END
  END t_d[407]
  PIN t_d[408]
    DIRECTION OUTPUT ;
    USE SIGNAL ;
    PORT
      LAYER M4 ;
        RECT  0 59.472 0.084 59.496 ;
    END
  END t_d[408]
  PIN t_d[409]
    DIRECTION OUTPUT ;
    USE SIGNAL ;
    PORT
      LAYER M4 ;
        RECT  0 59.52 0.084 59.544 ;
    END
  END t_d[409]
  PIN t_d[40]
    DIRECTION OUTPUT ;
    USE SIGNAL ;
    PORT
      LAYER M4 ;
        RECT  0 41.808 0.084 41.832 ;
    END
  END t_d[40]
  PIN t_d[410]
    DIRECTION OUTPUT ;
    USE SIGNAL ;
    PORT
      LAYER M4 ;
        RECT  0 59.568 0.084 59.592 ;
    END
  END t_d[410]
  PIN t_d[411]
    DIRECTION OUTPUT ;
    USE SIGNAL ;
    PORT
      LAYER M4 ;
        RECT  0 59.616 0.084 59.64 ;
    END
  END t_d[411]
  PIN t_d[412]
    DIRECTION OUTPUT ;
    USE SIGNAL ;
    PORT
      LAYER M4 ;
        RECT  0 59.664 0.084 59.688 ;
    END
  END t_d[412]
  PIN t_d[413]
    DIRECTION OUTPUT ;
    USE SIGNAL ;
    PORT
      LAYER M4 ;
        RECT  0 59.712 0.084 59.736 ;
    END
  END t_d[413]
  PIN t_d[414]
    DIRECTION OUTPUT ;
    USE SIGNAL ;
    PORT
      LAYER M4 ;
        RECT  0 59.76 0.084 59.784 ;
    END
  END t_d[414]
  PIN t_d[415]
    DIRECTION OUTPUT ;
    USE SIGNAL ;
    PORT
      LAYER M4 ;
        RECT  0 59.808 0.084 59.832 ;
    END
  END t_d[415]
  PIN t_d[416]
    DIRECTION OUTPUT ;
    USE SIGNAL ;
    PORT
      LAYER M4 ;
        RECT  0 59.856 0.084 59.88 ;
    END
  END t_d[416]
  PIN t_d[417]
    DIRECTION OUTPUT ;
    USE SIGNAL ;
    PORT
      LAYER M4 ;
        RECT  0 59.904 0.084 59.928 ;
    END
  END t_d[417]
  PIN t_d[418]
    DIRECTION OUTPUT ;
    USE SIGNAL ;
    PORT
      LAYER M4 ;
        RECT  0 59.952 0.084 59.976 ;
    END
  END t_d[418]
  PIN t_d[419]
    DIRECTION OUTPUT ;
    USE SIGNAL ;
    PORT
      LAYER M4 ;
        RECT  0 60 0.084 60.024 ;
    END
  END t_d[419]
  PIN t_d[41]
    DIRECTION OUTPUT ;
    USE SIGNAL ;
    PORT
      LAYER M4 ;
        RECT  0 41.856 0.084 41.88 ;
    END
  END t_d[41]
  PIN t_d[420]
    DIRECTION OUTPUT ;
    USE SIGNAL ;
    PORT
      LAYER M4 ;
        RECT  0 60.048 0.084 60.072 ;
    END
  END t_d[420]
  PIN t_d[421]
    DIRECTION OUTPUT ;
    USE SIGNAL ;
    PORT
      LAYER M4 ;
        RECT  0 60.096 0.084 60.12 ;
    END
  END t_d[421]
  PIN t_d[422]
    DIRECTION OUTPUT ;
    USE SIGNAL ;
    PORT
      LAYER M4 ;
        RECT  0 60.144 0.084 60.168 ;
    END
  END t_d[422]
  PIN t_d[423]
    DIRECTION OUTPUT ;
    USE SIGNAL ;
    PORT
      LAYER M4 ;
        RECT  0 60.192 0.084 60.216 ;
    END
  END t_d[423]
  PIN t_d[424]
    DIRECTION OUTPUT ;
    USE SIGNAL ;
    PORT
      LAYER M4 ;
        RECT  0 60.24 0.084 60.264 ;
    END
  END t_d[424]
  PIN t_d[425]
    DIRECTION OUTPUT ;
    USE SIGNAL ;
    PORT
      LAYER M4 ;
        RECT  0 60.288 0.084 60.312 ;
    END
  END t_d[425]
  PIN t_d[426]
    DIRECTION OUTPUT ;
    USE SIGNAL ;
    PORT
      LAYER M4 ;
        RECT  0 60.336 0.084 60.36 ;
    END
  END t_d[426]
  PIN t_d[427]
    DIRECTION OUTPUT ;
    USE SIGNAL ;
    PORT
      LAYER M4 ;
        RECT  0 60.384 0.084 60.408 ;
    END
  END t_d[427]
  PIN t_d[428]
    DIRECTION OUTPUT ;
    USE SIGNAL ;
    PORT
      LAYER M4 ;
        RECT  0 60.432 0.084 60.456 ;
    END
  END t_d[428]
  PIN t_d[429]
    DIRECTION OUTPUT ;
    USE SIGNAL ;
    PORT
      LAYER M4 ;
        RECT  0 60.48 0.084 60.504 ;
    END
  END t_d[429]
  PIN t_d[42]
    DIRECTION OUTPUT ;
    USE SIGNAL ;
    PORT
      LAYER M4 ;
        RECT  0 41.904 0.084 41.928 ;
    END
  END t_d[42]
  PIN t_d[430]
    DIRECTION OUTPUT ;
    USE SIGNAL ;
    PORT
      LAYER M4 ;
        RECT  0 60.528 0.084 60.552 ;
    END
  END t_d[430]
  PIN t_d[431]
    DIRECTION OUTPUT ;
    USE SIGNAL ;
    PORT
      LAYER M4 ;
        RECT  0 60.576 0.084 60.6 ;
    END
  END t_d[431]
  PIN t_d[432]
    DIRECTION OUTPUT ;
    USE SIGNAL ;
    PORT
      LAYER M4 ;
        RECT  0 60.624 0.084 60.648 ;
    END
  END t_d[432]
  PIN t_d[433]
    DIRECTION OUTPUT ;
    USE SIGNAL ;
    PORT
      LAYER M4 ;
        RECT  0 60.672 0.084 60.696 ;
    END
  END t_d[433]
  PIN t_d[434]
    DIRECTION OUTPUT ;
    USE SIGNAL ;
    PORT
      LAYER M4 ;
        RECT  0 60.72 0.084 60.744 ;
    END
  END t_d[434]
  PIN t_d[435]
    DIRECTION OUTPUT ;
    USE SIGNAL ;
    PORT
      LAYER M4 ;
        RECT  0 60.768 0.084 60.792 ;
    END
  END t_d[435]
  PIN t_d[436]
    DIRECTION OUTPUT ;
    USE SIGNAL ;
    PORT
      LAYER M4 ;
        RECT  0 60.816 0.084 60.84 ;
    END
  END t_d[436]
  PIN t_d[437]
    DIRECTION OUTPUT ;
    USE SIGNAL ;
    PORT
      LAYER M4 ;
        RECT  0 60.864 0.084 60.888 ;
    END
  END t_d[437]
  PIN t_d[438]
    DIRECTION OUTPUT ;
    USE SIGNAL ;
    PORT
      LAYER M4 ;
        RECT  0 60.912 0.084 60.936 ;
    END
  END t_d[438]
  PIN t_d[439]
    DIRECTION OUTPUT ;
    USE SIGNAL ;
    PORT
      LAYER M4 ;
        RECT  0 60.96 0.084 60.984 ;
    END
  END t_d[439]
  PIN t_d[43]
    DIRECTION OUTPUT ;
    USE SIGNAL ;
    PORT
      LAYER M4 ;
        RECT  0 41.952 0.084 41.976 ;
    END
  END t_d[43]
  PIN t_d[440]
    DIRECTION OUTPUT ;
    USE SIGNAL ;
    PORT
      LAYER M4 ;
        RECT  0 61.008 0.084 61.032 ;
    END
  END t_d[440]
  PIN t_d[441]
    DIRECTION OUTPUT ;
    USE SIGNAL ;
    PORT
      LAYER M4 ;
        RECT  0 61.056 0.084 61.08 ;
    END
  END t_d[441]
  PIN t_d[442]
    DIRECTION OUTPUT ;
    USE SIGNAL ;
    PORT
      LAYER M4 ;
        RECT  0 61.104 0.084 61.128 ;
    END
  END t_d[442]
  PIN t_d[443]
    DIRECTION OUTPUT ;
    USE SIGNAL ;
    PORT
      LAYER M4 ;
        RECT  0 61.152 0.084 61.176 ;
    END
  END t_d[443]
  PIN t_d[444]
    DIRECTION OUTPUT ;
    USE SIGNAL ;
    PORT
      LAYER M4 ;
        RECT  0 61.2 0.084 61.224 ;
    END
  END t_d[444]
  PIN t_d[445]
    DIRECTION OUTPUT ;
    USE SIGNAL ;
    PORT
      LAYER M4 ;
        RECT  0 61.248 0.084 61.272 ;
    END
  END t_d[445]
  PIN t_d[446]
    DIRECTION OUTPUT ;
    USE SIGNAL ;
    PORT
      LAYER M4 ;
        RECT  0 61.296 0.084 61.32 ;
    END
  END t_d[446]
  PIN t_d[447]
    DIRECTION OUTPUT ;
    USE SIGNAL ;
    PORT
      LAYER M4 ;
        RECT  0 61.344 0.084 61.368 ;
    END
  END t_d[447]
  PIN t_d[448]
    DIRECTION OUTPUT ;
    USE SIGNAL ;
    PORT
      LAYER M4 ;
        RECT  0 61.392 0.084 61.416 ;
    END
  END t_d[448]
  PIN t_d[449]
    DIRECTION OUTPUT ;
    USE SIGNAL ;
    PORT
      LAYER M4 ;
        RECT  0 61.44 0.084 61.464 ;
    END
  END t_d[449]
  PIN t_d[44]
    DIRECTION OUTPUT ;
    USE SIGNAL ;
    PORT
      LAYER M4 ;
        RECT  0 42 0.084 42.024 ;
    END
  END t_d[44]
  PIN t_d[450]
    DIRECTION OUTPUT ;
    USE SIGNAL ;
    PORT
      LAYER M4 ;
        RECT  0 61.488 0.084 61.512 ;
    END
  END t_d[450]
  PIN t_d[451]
    DIRECTION OUTPUT ;
    USE SIGNAL ;
    PORT
      LAYER M4 ;
        RECT  0 61.536 0.084 61.56 ;
    END
  END t_d[451]
  PIN t_d[452]
    DIRECTION OUTPUT ;
    USE SIGNAL ;
    PORT
      LAYER M4 ;
        RECT  0 61.584 0.084 61.608 ;
    END
  END t_d[452]
  PIN t_d[453]
    DIRECTION OUTPUT ;
    USE SIGNAL ;
    PORT
      LAYER M4 ;
        RECT  0 61.632 0.084 61.656 ;
    END
  END t_d[453]
  PIN t_d[454]
    DIRECTION OUTPUT ;
    USE SIGNAL ;
    PORT
      LAYER M4 ;
        RECT  0 61.68 0.084 61.704 ;
    END
  END t_d[454]
  PIN t_d[455]
    DIRECTION OUTPUT ;
    USE SIGNAL ;
    PORT
      LAYER M4 ;
        RECT  0 61.728 0.084 61.752 ;
    END
  END t_d[455]
  PIN t_d[456]
    DIRECTION OUTPUT ;
    USE SIGNAL ;
    PORT
      LAYER M4 ;
        RECT  0 61.776 0.084 61.8 ;
    END
  END t_d[456]
  PIN t_d[457]
    DIRECTION OUTPUT ;
    USE SIGNAL ;
    PORT
      LAYER M4 ;
        RECT  0 61.824 0.084 61.848 ;
    END
  END t_d[457]
  PIN t_d[458]
    DIRECTION OUTPUT ;
    USE SIGNAL ;
    PORT
      LAYER M4 ;
        RECT  0 61.872 0.084 61.896 ;
    END
  END t_d[458]
  PIN t_d[459]
    DIRECTION OUTPUT ;
    USE SIGNAL ;
    PORT
      LAYER M4 ;
        RECT  0 61.92 0.084 61.944 ;
    END
  END t_d[459]
  PIN t_d[45]
    DIRECTION OUTPUT ;
    USE SIGNAL ;
    PORT
      LAYER M4 ;
        RECT  0 42.048 0.084 42.072 ;
    END
  END t_d[45]
  PIN t_d[460]
    DIRECTION OUTPUT ;
    USE SIGNAL ;
    PORT
      LAYER M4 ;
        RECT  0 61.968 0.084 61.992 ;
    END
  END t_d[460]
  PIN t_d[461]
    DIRECTION OUTPUT ;
    USE SIGNAL ;
    PORT
      LAYER M4 ;
        RECT  0 62.016 0.084 62.04 ;
    END
  END t_d[461]
  PIN t_d[462]
    DIRECTION OUTPUT ;
    USE SIGNAL ;
    PORT
      LAYER M4 ;
        RECT  0 62.064 0.084 62.088 ;
    END
  END t_d[462]
  PIN t_d[463]
    DIRECTION OUTPUT ;
    USE SIGNAL ;
    PORT
      LAYER M4 ;
        RECT  0 62.112 0.084 62.136 ;
    END
  END t_d[463]
  PIN t_d[464]
    DIRECTION OUTPUT ;
    USE SIGNAL ;
    PORT
      LAYER M4 ;
        RECT  0 62.16 0.084 62.184 ;
    END
  END t_d[464]
  PIN t_d[465]
    DIRECTION OUTPUT ;
    USE SIGNAL ;
    PORT
      LAYER M4 ;
        RECT  0 62.208 0.084 62.232 ;
    END
  END t_d[465]
  PIN t_d[466]
    DIRECTION OUTPUT ;
    USE SIGNAL ;
    PORT
      LAYER M4 ;
        RECT  0 62.256 0.084 62.28 ;
    END
  END t_d[466]
  PIN t_d[467]
    DIRECTION OUTPUT ;
    USE SIGNAL ;
    PORT
      LAYER M4 ;
        RECT  0 62.304 0.084 62.328 ;
    END
  END t_d[467]
  PIN t_d[468]
    DIRECTION OUTPUT ;
    USE SIGNAL ;
    PORT
      LAYER M4 ;
        RECT  0 62.352 0.084 62.376 ;
    END
  END t_d[468]
  PIN t_d[469]
    DIRECTION OUTPUT ;
    USE SIGNAL ;
    PORT
      LAYER M4 ;
        RECT  0 62.4 0.084 62.424 ;
    END
  END t_d[469]
  PIN t_d[46]
    DIRECTION OUTPUT ;
    USE SIGNAL ;
    PORT
      LAYER M4 ;
        RECT  0 42.096 0.084 42.12 ;
    END
  END t_d[46]
  PIN t_d[470]
    DIRECTION OUTPUT ;
    USE SIGNAL ;
    PORT
      LAYER M4 ;
        RECT  0 62.448 0.084 62.472 ;
    END
  END t_d[470]
  PIN t_d[471]
    DIRECTION OUTPUT ;
    USE SIGNAL ;
    PORT
      LAYER M4 ;
        RECT  0 62.496 0.084 62.52 ;
    END
  END t_d[471]
  PIN t_d[472]
    DIRECTION OUTPUT ;
    USE SIGNAL ;
    PORT
      LAYER M4 ;
        RECT  0 62.544 0.084 62.568 ;
    END
  END t_d[472]
  PIN t_d[473]
    DIRECTION OUTPUT ;
    USE SIGNAL ;
    PORT
      LAYER M4 ;
        RECT  0 62.592 0.084 62.616 ;
    END
  END t_d[473]
  PIN t_d[474]
    DIRECTION OUTPUT ;
    USE SIGNAL ;
    PORT
      LAYER M4 ;
        RECT  0 62.64 0.084 62.664 ;
    END
  END t_d[474]
  PIN t_d[475]
    DIRECTION OUTPUT ;
    USE SIGNAL ;
    PORT
      LAYER M4 ;
        RECT  0 62.688 0.084 62.712 ;
    END
  END t_d[475]
  PIN t_d[476]
    DIRECTION OUTPUT ;
    USE SIGNAL ;
    PORT
      LAYER M4 ;
        RECT  0 62.736 0.084 62.76 ;
    END
  END t_d[476]
  PIN t_d[477]
    DIRECTION OUTPUT ;
    USE SIGNAL ;
    PORT
      LAYER M4 ;
        RECT  0 62.784 0.084 62.808 ;
    END
  END t_d[477]
  PIN t_d[478]
    DIRECTION OUTPUT ;
    USE SIGNAL ;
    PORT
      LAYER M4 ;
        RECT  0 62.832 0.084 62.856 ;
    END
  END t_d[478]
  PIN t_d[479]
    DIRECTION OUTPUT ;
    USE SIGNAL ;
    PORT
      LAYER M4 ;
        RECT  0 62.88 0.084 62.904 ;
    END
  END t_d[479]
  PIN t_d[47]
    DIRECTION OUTPUT ;
    USE SIGNAL ;
    PORT
      LAYER M4 ;
        RECT  0 42.144 0.084 42.168 ;
    END
  END t_d[47]
  PIN t_d[480]
    DIRECTION OUTPUT ;
    USE SIGNAL ;
    PORT
      LAYER M4 ;
        RECT  0 62.928 0.084 62.952 ;
    END
  END t_d[480]
  PIN t_d[481]
    DIRECTION OUTPUT ;
    USE SIGNAL ;
    PORT
      LAYER M4 ;
        RECT  0 62.976 0.084 63 ;
    END
  END t_d[481]
  PIN t_d[482]
    DIRECTION OUTPUT ;
    USE SIGNAL ;
    PORT
      LAYER M4 ;
        RECT  0 63.024 0.084 63.048 ;
    END
  END t_d[482]
  PIN t_d[483]
    DIRECTION OUTPUT ;
    USE SIGNAL ;
    PORT
      LAYER M4 ;
        RECT  0 63.072 0.084 63.096 ;
    END
  END t_d[483]
  PIN t_d[484]
    DIRECTION OUTPUT ;
    USE SIGNAL ;
    PORT
      LAYER M4 ;
        RECT  0 63.12 0.084 63.144 ;
    END
  END t_d[484]
  PIN t_d[485]
    DIRECTION OUTPUT ;
    USE SIGNAL ;
    PORT
      LAYER M4 ;
        RECT  0 63.168 0.084 63.192 ;
    END
  END t_d[485]
  PIN t_d[486]
    DIRECTION OUTPUT ;
    USE SIGNAL ;
    PORT
      LAYER M4 ;
        RECT  0 63.216 0.084 63.24 ;
    END
  END t_d[486]
  PIN t_d[487]
    DIRECTION OUTPUT ;
    USE SIGNAL ;
    PORT
      LAYER M4 ;
        RECT  0 63.264 0.084 63.288 ;
    END
  END t_d[487]
  PIN t_d[488]
    DIRECTION OUTPUT ;
    USE SIGNAL ;
    PORT
      LAYER M4 ;
        RECT  0 63.312 0.084 63.336 ;
    END
  END t_d[488]
  PIN t_d[489]
    DIRECTION OUTPUT ;
    USE SIGNAL ;
    PORT
      LAYER M4 ;
        RECT  0 63.36 0.084 63.384 ;
    END
  END t_d[489]
  PIN t_d[48]
    DIRECTION OUTPUT ;
    USE SIGNAL ;
    PORT
      LAYER M4 ;
        RECT  0 42.192 0.084 42.216 ;
    END
  END t_d[48]
  PIN t_d[490]
    DIRECTION OUTPUT ;
    USE SIGNAL ;
    PORT
      LAYER M4 ;
        RECT  0 63.408 0.084 63.432 ;
    END
  END t_d[490]
  PIN t_d[491]
    DIRECTION OUTPUT ;
    USE SIGNAL ;
    PORT
      LAYER M4 ;
        RECT  0 63.456 0.084 63.48 ;
    END
  END t_d[491]
  PIN t_d[492]
    DIRECTION OUTPUT ;
    USE SIGNAL ;
    PORT
      LAYER M4 ;
        RECT  0 63.504 0.084 63.528 ;
    END
  END t_d[492]
  PIN t_d[493]
    DIRECTION OUTPUT ;
    USE SIGNAL ;
    PORT
      LAYER M4 ;
        RECT  0 63.552 0.084 63.576 ;
    END
  END t_d[493]
  PIN t_d[494]
    DIRECTION OUTPUT ;
    USE SIGNAL ;
    PORT
      LAYER M4 ;
        RECT  0 63.6 0.084 63.624 ;
    END
  END t_d[494]
  PIN t_d[495]
    DIRECTION OUTPUT ;
    USE SIGNAL ;
    PORT
      LAYER M4 ;
        RECT  0 63.648 0.084 63.672 ;
    END
  END t_d[495]
  PIN t_d[496]
    DIRECTION OUTPUT ;
    USE SIGNAL ;
    PORT
      LAYER M4 ;
        RECT  0 63.696 0.084 63.72 ;
    END
  END t_d[496]
  PIN t_d[497]
    DIRECTION OUTPUT ;
    USE SIGNAL ;
    PORT
      LAYER M4 ;
        RECT  0 63.744 0.084 63.768 ;
    END
  END t_d[497]
  PIN t_d[498]
    DIRECTION OUTPUT ;
    USE SIGNAL ;
    PORT
      LAYER M4 ;
        RECT  0 63.792 0.084 63.816 ;
    END
  END t_d[498]
  PIN t_d[499]
    DIRECTION OUTPUT ;
    USE SIGNAL ;
    PORT
      LAYER M4 ;
        RECT  0 63.84 0.084 63.864 ;
    END
  END t_d[499]
  PIN t_d[49]
    DIRECTION OUTPUT ;
    USE SIGNAL ;
    PORT
      LAYER M4 ;
        RECT  0 42.24 0.084 42.264 ;
    END
  END t_d[49]
  PIN t_d[4]
    DIRECTION OUTPUT ;
    USE SIGNAL ;
    PORT
      LAYER M4 ;
        RECT  0 40.08 0.084 40.104 ;
    END
  END t_d[4]
  PIN t_d[500]
    DIRECTION OUTPUT ;
    USE SIGNAL ;
    PORT
      LAYER M4 ;
        RECT  0 63.888 0.084 63.912 ;
    END
  END t_d[500]
  PIN t_d[501]
    DIRECTION OUTPUT ;
    USE SIGNAL ;
    PORT
      LAYER M4 ;
        RECT  0 63.936 0.084 63.96 ;
    END
  END t_d[501]
  PIN t_d[502]
    DIRECTION OUTPUT ;
    USE SIGNAL ;
    PORT
      LAYER M4 ;
        RECT  0 63.984 0.084 64.008 ;
    END
  END t_d[502]
  PIN t_d[503]
    DIRECTION OUTPUT ;
    USE SIGNAL ;
    PORT
      LAYER M4 ;
        RECT  0 64.032 0.084 64.056 ;
    END
  END t_d[503]
  PIN t_d[504]
    DIRECTION OUTPUT ;
    USE SIGNAL ;
    PORT
      LAYER M4 ;
        RECT  0 64.08 0.084 64.104 ;
    END
  END t_d[504]
  PIN t_d[505]
    DIRECTION OUTPUT ;
    USE SIGNAL ;
    PORT
      LAYER M4 ;
        RECT  0 64.128 0.084 64.152 ;
    END
  END t_d[505]
  PIN t_d[506]
    DIRECTION OUTPUT ;
    USE SIGNAL ;
    PORT
      LAYER M4 ;
        RECT  0 64.176 0.084 64.2 ;
    END
  END t_d[506]
  PIN t_d[507]
    DIRECTION OUTPUT ;
    USE SIGNAL ;
    PORT
      LAYER M4 ;
        RECT  0 64.224 0.084 64.248 ;
    END
  END t_d[507]
  PIN t_d[50]
    DIRECTION OUTPUT ;
    USE SIGNAL ;
    PORT
      LAYER M4 ;
        RECT  0 42.288 0.084 42.312 ;
    END
  END t_d[50]
  PIN t_d[51]
    DIRECTION OUTPUT ;
    USE SIGNAL ;
    PORT
      LAYER M4 ;
        RECT  0 42.336 0.084 42.36 ;
    END
  END t_d[51]
  PIN t_d[52]
    DIRECTION OUTPUT ;
    USE SIGNAL ;
    PORT
      LAYER M4 ;
        RECT  0 42.384 0.084 42.408 ;
    END
  END t_d[52]
  PIN t_d[53]
    DIRECTION OUTPUT ;
    USE SIGNAL ;
    PORT
      LAYER M4 ;
        RECT  0 42.432 0.084 42.456 ;
    END
  END t_d[53]
  PIN t_d[54]
    DIRECTION OUTPUT ;
    USE SIGNAL ;
    PORT
      LAYER M4 ;
        RECT  0 42.48 0.084 42.504 ;
    END
  END t_d[54]
  PIN t_d[55]
    DIRECTION OUTPUT ;
    USE SIGNAL ;
    PORT
      LAYER M4 ;
        RECT  0 42.528 0.084 42.552 ;
    END
  END t_d[55]
  PIN t_d[56]
    DIRECTION OUTPUT ;
    USE SIGNAL ;
    PORT
      LAYER M4 ;
        RECT  0 42.576 0.084 42.6 ;
    END
  END t_d[56]
  PIN t_d[57]
    DIRECTION OUTPUT ;
    USE SIGNAL ;
    PORT
      LAYER M4 ;
        RECT  0 42.624 0.084 42.648 ;
    END
  END t_d[57]
  PIN t_d[58]
    DIRECTION OUTPUT ;
    USE SIGNAL ;
    PORT
      LAYER M4 ;
        RECT  0 42.672 0.084 42.696 ;
    END
  END t_d[58]
  PIN t_d[59]
    DIRECTION OUTPUT ;
    USE SIGNAL ;
    PORT
      LAYER M4 ;
        RECT  0 42.72 0.084 42.744 ;
    END
  END t_d[59]
  PIN t_d[5]
    DIRECTION OUTPUT ;
    USE SIGNAL ;
    PORT
      LAYER M4 ;
        RECT  0 40.128 0.084 40.152 ;
    END
  END t_d[5]
  PIN t_d[60]
    DIRECTION OUTPUT ;
    USE SIGNAL ;
    PORT
      LAYER M4 ;
        RECT  0 42.768 0.084 42.792 ;
    END
  END t_d[60]
  PIN t_d[61]
    DIRECTION OUTPUT ;
    USE SIGNAL ;
    PORT
      LAYER M4 ;
        RECT  0 42.816 0.084 42.84 ;
    END
  END t_d[61]
  PIN t_d[62]
    DIRECTION OUTPUT ;
    USE SIGNAL ;
    PORT
      LAYER M4 ;
        RECT  0 42.864 0.084 42.888 ;
    END
  END t_d[62]
  PIN t_d[63]
    DIRECTION OUTPUT ;
    USE SIGNAL ;
    PORT
      LAYER M4 ;
        RECT  0 42.912 0.084 42.936 ;
    END
  END t_d[63]
  PIN t_d[64]
    DIRECTION OUTPUT ;
    USE SIGNAL ;
    PORT
      LAYER M4 ;
        RECT  0 42.96 0.084 42.984 ;
    END
  END t_d[64]
  PIN t_d[65]
    DIRECTION OUTPUT ;
    USE SIGNAL ;
    PORT
      LAYER M4 ;
        RECT  0 43.008 0.084 43.032 ;
    END
  END t_d[65]
  PIN t_d[66]
    DIRECTION OUTPUT ;
    USE SIGNAL ;
    PORT
      LAYER M4 ;
        RECT  0 43.056 0.084 43.08 ;
    END
  END t_d[66]
  PIN t_d[67]
    DIRECTION OUTPUT ;
    USE SIGNAL ;
    PORT
      LAYER M4 ;
        RECT  0 43.104 0.084 43.128 ;
    END
  END t_d[67]
  PIN t_d[68]
    DIRECTION OUTPUT ;
    USE SIGNAL ;
    PORT
      LAYER M4 ;
        RECT  0 43.152 0.084 43.176 ;
    END
  END t_d[68]
  PIN t_d[69]
    DIRECTION OUTPUT ;
    USE SIGNAL ;
    PORT
      LAYER M4 ;
        RECT  0 43.2 0.084 43.224 ;
    END
  END t_d[69]
  PIN t_d[6]
    DIRECTION OUTPUT ;
    USE SIGNAL ;
    PORT
      LAYER M4 ;
        RECT  0 40.176 0.084 40.2 ;
    END
  END t_d[6]
  PIN t_d[70]
    DIRECTION OUTPUT ;
    USE SIGNAL ;
    PORT
      LAYER M4 ;
        RECT  0 43.248 0.084 43.272 ;
    END
  END t_d[70]
  PIN t_d[71]
    DIRECTION OUTPUT ;
    USE SIGNAL ;
    PORT
      LAYER M4 ;
        RECT  0 43.296 0.084 43.32 ;
    END
  END t_d[71]
  PIN t_d[72]
    DIRECTION OUTPUT ;
    USE SIGNAL ;
    PORT
      LAYER M4 ;
        RECT  0 43.344 0.084 43.368 ;
    END
  END t_d[72]
  PIN t_d[73]
    DIRECTION OUTPUT ;
    USE SIGNAL ;
    PORT
      LAYER M4 ;
        RECT  0 43.392 0.084 43.416 ;
    END
  END t_d[73]
  PIN t_d[74]
    DIRECTION OUTPUT ;
    USE SIGNAL ;
    PORT
      LAYER M4 ;
        RECT  0 43.44 0.084 43.464 ;
    END
  END t_d[74]
  PIN t_d[75]
    DIRECTION OUTPUT ;
    USE SIGNAL ;
    PORT
      LAYER M4 ;
        RECT  0 43.488 0.084 43.512 ;
    END
  END t_d[75]
  PIN t_d[76]
    DIRECTION OUTPUT ;
    USE SIGNAL ;
    PORT
      LAYER M4 ;
        RECT  0 43.536 0.084 43.56 ;
    END
  END t_d[76]
  PIN t_d[77]
    DIRECTION OUTPUT ;
    USE SIGNAL ;
    PORT
      LAYER M4 ;
        RECT  0 43.584 0.084 43.608 ;
    END
  END t_d[77]
  PIN t_d[78]
    DIRECTION OUTPUT ;
    USE SIGNAL ;
    PORT
      LAYER M4 ;
        RECT  0 43.632 0.084 43.656 ;
    END
  END t_d[78]
  PIN t_d[79]
    DIRECTION OUTPUT ;
    USE SIGNAL ;
    PORT
      LAYER M4 ;
        RECT  0 43.68 0.084 43.704 ;
    END
  END t_d[79]
  PIN t_d[7]
    DIRECTION OUTPUT ;
    USE SIGNAL ;
    PORT
      LAYER M4 ;
        RECT  0 40.224 0.084 40.248 ;
    END
  END t_d[7]
  PIN t_d[80]
    DIRECTION OUTPUT ;
    USE SIGNAL ;
    PORT
      LAYER M4 ;
        RECT  0 43.728 0.084 43.752 ;
    END
  END t_d[80]
  PIN t_d[81]
    DIRECTION OUTPUT ;
    USE SIGNAL ;
    PORT
      LAYER M4 ;
        RECT  0 43.776 0.084 43.8 ;
    END
  END t_d[81]
  PIN t_d[82]
    DIRECTION OUTPUT ;
    USE SIGNAL ;
    PORT
      LAYER M4 ;
        RECT  0 43.824 0.084 43.848 ;
    END
  END t_d[82]
  PIN t_d[83]
    DIRECTION OUTPUT ;
    USE SIGNAL ;
    PORT
      LAYER M4 ;
        RECT  0 43.872 0.084 43.896 ;
    END
  END t_d[83]
  PIN t_d[84]
    DIRECTION OUTPUT ;
    USE SIGNAL ;
    PORT
      LAYER M4 ;
        RECT  0 43.92 0.084 43.944 ;
    END
  END t_d[84]
  PIN t_d[85]
    DIRECTION OUTPUT ;
    USE SIGNAL ;
    PORT
      LAYER M4 ;
        RECT  0 43.968 0.084 43.992 ;
    END
  END t_d[85]
  PIN t_d[86]
    DIRECTION OUTPUT ;
    USE SIGNAL ;
    PORT
      LAYER M4 ;
        RECT  0 44.016 0.084 44.04 ;
    END
  END t_d[86]
  PIN t_d[87]
    DIRECTION OUTPUT ;
    USE SIGNAL ;
    PORT
      LAYER M4 ;
        RECT  0 44.064 0.084 44.088 ;
    END
  END t_d[87]
  PIN t_d[88]
    DIRECTION OUTPUT ;
    USE SIGNAL ;
    PORT
      LAYER M4 ;
        RECT  0 44.112 0.084 44.136 ;
    END
  END t_d[88]
  PIN t_d[89]
    DIRECTION OUTPUT ;
    USE SIGNAL ;
    PORT
      LAYER M4 ;
        RECT  0 44.16 0.084 44.184 ;
    END
  END t_d[89]
  PIN t_d[8]
    DIRECTION OUTPUT ;
    USE SIGNAL ;
    PORT
      LAYER M4 ;
        RECT  0 40.272 0.084 40.296 ;
    END
  END t_d[8]
  PIN t_d[90]
    DIRECTION OUTPUT ;
    USE SIGNAL ;
    PORT
      LAYER M4 ;
        RECT  0 44.208 0.084 44.232 ;
    END
  END t_d[90]
  PIN t_d[91]
    DIRECTION OUTPUT ;
    USE SIGNAL ;
    PORT
      LAYER M4 ;
        RECT  0 44.256 0.084 44.28 ;
    END
  END t_d[91]
  PIN t_d[92]
    DIRECTION OUTPUT ;
    USE SIGNAL ;
    PORT
      LAYER M4 ;
        RECT  0 44.304 0.084 44.328 ;
    END
  END t_d[92]
  PIN t_d[93]
    DIRECTION OUTPUT ;
    USE SIGNAL ;
    PORT
      LAYER M4 ;
        RECT  0 44.352 0.084 44.376 ;
    END
  END t_d[93]
  PIN t_d[94]
    DIRECTION OUTPUT ;
    USE SIGNAL ;
    PORT
      LAYER M4 ;
        RECT  0 44.4 0.084 44.424 ;
    END
  END t_d[94]
  PIN t_d[95]
    DIRECTION OUTPUT ;
    USE SIGNAL ;
    PORT
      LAYER M4 ;
        RECT  0 44.448 0.084 44.472 ;
    END
  END t_d[95]
  PIN t_d[96]
    DIRECTION OUTPUT ;
    USE SIGNAL ;
    PORT
      LAYER M4 ;
        RECT  0 44.496 0.084 44.52 ;
    END
  END t_d[96]
  PIN t_d[97]
    DIRECTION OUTPUT ;
    USE SIGNAL ;
    PORT
      LAYER M4 ;
        RECT  0 44.544 0.084 44.568 ;
    END
  END t_d[97]
  PIN t_d[98]
    DIRECTION OUTPUT ;
    USE SIGNAL ;
    PORT
      LAYER M4 ;
        RECT  0 44.592 0.084 44.616 ;
    END
  END t_d[98]
  PIN t_d[99]
    DIRECTION OUTPUT ;
    USE SIGNAL ;
    PORT
      LAYER M4 ;
        RECT  0 44.64 0.084 44.664 ;
    END
  END t_d[99]
  PIN t_d[9]
    DIRECTION OUTPUT ;
    USE SIGNAL ;
    PORT
      LAYER M4 ;
        RECT  0 40.32 0.084 40.344 ;
    END
  END t_d[9]
  PIN t_r
    DIRECTION INPUT ;
    USE SIGNAL ;
    PORT
      LAYER M4 ;
        RECT  0 64.272 0.084 64.296 ;
    END
  END t_r
  PIN VDD
    DIRECTION INOUT ;
    USE POWER ;
    PORT
      LAYER M6 ;
        RECT  2.16 100.113 50.49 100.401 ;
        RECT  2.16 94.713 50.49 95.001 ;
        RECT  2.16 89.313 50.49 89.601 ;
        RECT  2.16 83.913 50.49 84.201 ;
        RECT  2.16 78.513 50.49 78.801 ;
        RECT  2.16 73.113 50.49 73.401 ;
        RECT  2.16 67.713 50.49 68.001 ;
        RECT  2.16 62.313 50.49 62.601 ;
        RECT  2.16 56.913 50.49 57.201 ;
        RECT  2.16 51.513 50.49 51.801 ;
        RECT  2.16 46.113 50.49 46.401 ;
        RECT  2.16 40.713 50.49 41.001 ;
        RECT  2.16 35.313 50.49 35.601 ;
        RECT  2.16 29.913 50.49 30.201 ;
        RECT  2.16 24.513 50.49 24.801 ;
        RECT  2.16 19.113 50.49 19.401 ;
        RECT  2.16 13.713 50.49 14.001 ;
        RECT  2.16 8.313 50.49 8.601 ;
        RECT  2.16 2.913 50.49 3.201 ;
    END
  END VDD
  PIN VSS
    DIRECTION INOUT ;
    USE GROUND ;
    PORT
      LAYER M6 ;
        RECT  2.16 99.729 50.49 100.017 ;
        RECT  2.16 94.329 50.49 94.617 ;
        RECT  2.16 88.929 50.49 89.217 ;
        RECT  2.16 83.529 50.49 83.817 ;
        RECT  2.16 78.129 50.49 78.417 ;
        RECT  2.16 72.729 50.49 73.017 ;
        RECT  2.16 67.329 50.49 67.617 ;
        RECT  2.16 61.929 50.49 62.217 ;
        RECT  2.16 56.529 50.49 56.817 ;
        RECT  2.16 51.129 50.49 51.417 ;
        RECT  2.16 45.729 50.49 46.017 ;
        RECT  2.16 40.329 50.49 40.617 ;
        RECT  2.16 34.929 50.49 35.217 ;
        RECT  2.16 29.529 50.49 29.817 ;
        RECT  2.16 24.129 50.49 24.417 ;
        RECT  2.16 18.729 50.49 19.017 ;
        RECT  2.16 13.329 50.49 13.617 ;
        RECT  2.16 7.929 50.49 8.217 ;
        RECT  2.16 2.529 50.49 2.817 ;
    END
  END VSS
  OBS
    LAYER RVTN ;
     RECT  2.16 2.16 50.49 2.295 ;
     RECT  2.16 2.565 50.49 2.835 ;
     RECT  2.16 3.105 50.49 3.375 ;
     RECT  2.16 3.645 50.49 3.915 ;
     RECT  2.16 4.185 50.49 4.455 ;
     RECT  2.16 4.725 50.49 4.995 ;
     RECT  2.16 5.265 50.49 5.535 ;
     RECT  2.16 5.805 50.49 6.075 ;
     RECT  2.16 6.345 50.49 6.615 ;
     RECT  2.16 6.885 50.49 7.155 ;
     RECT  2.16 7.425 50.49 7.695 ;
     RECT  2.16 7.965 50.49 8.235 ;
     RECT  2.16 8.505 50.49 8.775 ;
     RECT  2.16 9.045 50.49 9.315 ;
     RECT  2.16 9.585 50.49 9.855 ;
     RECT  2.16 10.125 50.49 10.395 ;
     RECT  2.16 10.665 50.49 10.935 ;
     RECT  2.16 11.205 50.49 11.475 ;
     RECT  2.16 11.745 50.49 12.015 ;
     RECT  2.16 12.285 50.49 12.555 ;
     RECT  2.16 12.825 50.49 13.095 ;
     RECT  2.16 13.365 50.49 13.635 ;
     RECT  2.16 13.905 50.49 14.175 ;
     RECT  2.16 14.445 50.49 14.715 ;
     RECT  2.16 14.985 50.49 15.255 ;
     RECT  2.16 15.525 50.49 15.795 ;
     RECT  2.16 16.065 50.49 16.335 ;
     RECT  2.16 16.605 50.49 16.875 ;
     RECT  2.16 17.145 50.49 17.415 ;
     RECT  2.16 17.685 50.49 17.955 ;
     RECT  2.16 18.225 50.49 18.495 ;
     RECT  2.16 18.765 50.49 19.035 ;
     RECT  2.16 19.305 50.49 19.575 ;
     RECT  2.16 19.845 50.49 20.115 ;
     RECT  2.16 20.385 50.49 20.655 ;
     RECT  2.16 20.925 50.49 21.195 ;
     RECT  2.16 21.465 50.49 21.735 ;
     RECT  2.16 22.005 50.49 22.275 ;
     RECT  2.16 22.545 50.49 22.815 ;
     RECT  2.16 23.085 50.49 23.355 ;
     RECT  2.16 23.625 50.49 23.895 ;
     RECT  2.16 24.165 50.49 24.435 ;
     RECT  2.16 24.705 50.49 24.975 ;
     RECT  2.16 25.245 50.49 25.515 ;
     RECT  2.16 25.785 50.49 26.055 ;
     RECT  2.16 26.325 50.49 26.595 ;
     RECT  2.16 26.865 50.49 27.135 ;
     RECT  2.16 27.405 50.49 27.675 ;
     RECT  2.16 27.945 50.49 28.215 ;
     RECT  2.16 28.485 50.49 28.755 ;
     RECT  2.16 29.025 50.49 29.295 ;
     RECT  2.16 29.565 50.49 29.835 ;
     RECT  2.16 30.105 50.49 30.375 ;
     RECT  2.16 30.645 50.49 30.915 ;
     RECT  2.16 31.185 50.49 31.455 ;
     RECT  2.16 31.725 50.49 31.995 ;
     RECT  2.16 32.265 50.49 32.535 ;
     RECT  2.16 32.805 50.49 33.075 ;
     RECT  2.16 33.345 50.49 33.615 ;
     RECT  2.16 33.885 50.49 34.155 ;
     RECT  2.16 34.425 50.49 34.695 ;
     RECT  2.16 34.965 50.49 35.235 ;
     RECT  2.16 35.505 50.49 35.775 ;
     RECT  2.16 36.045 50.49 36.315 ;
     RECT  2.16 36.585 50.49 36.855 ;
     RECT  2.16 37.125 50.49 37.395 ;
     RECT  2.16 37.665 50.49 37.935 ;
     RECT  2.16 38.205 50.49 38.475 ;
     RECT  2.16 38.745 50.49 39.015 ;
     RECT  2.16 39.285 50.49 39.555 ;
     RECT  2.16 39.825 50.49 40.095 ;
     RECT  2.16 40.365 50.49 40.635 ;
     RECT  2.16 40.905 50.49 41.175 ;
     RECT  2.16 41.445 50.49 41.715 ;
     RECT  2.16 41.985 50.49 42.255 ;
     RECT  2.16 42.525 50.49 42.795 ;
     RECT  2.16 43.065 50.49 43.335 ;
     RECT  2.16 43.605 50.49 43.875 ;
     RECT  2.16 44.145 50.49 44.415 ;
     RECT  2.16 44.685 50.49 44.955 ;
     RECT  2.16 45.225 50.49 45.495 ;
     RECT  2.16 45.765 50.49 46.035 ;
     RECT  2.16 46.305 50.49 46.575 ;
     RECT  2.16 46.845 50.49 47.115 ;
     RECT  2.16 47.385 50.49 47.655 ;
     RECT  2.16 47.925 50.49 48.195 ;
     RECT  2.16 48.465 50.49 48.735 ;
     RECT  2.16 49.005 50.49 49.275 ;
     RECT  2.16 49.545 50.49 49.815 ;
     RECT  2.16 50.085 50.49 50.355 ;
     RECT  2.16 50.625 50.49 50.895 ;
     RECT  2.16 51.165 50.49 51.435 ;
     RECT  2.16 51.705 50.49 51.975 ;
     RECT  2.16 52.245 50.49 52.515 ;
     RECT  2.16 52.785 50.49 53.055 ;
     RECT  2.16 53.325 50.49 53.595 ;
     RECT  2.16 53.865 50.49 54.135 ;
     RECT  2.16 54.405 50.49 54.675 ;
     RECT  2.16 54.945 50.49 55.215 ;
     RECT  2.16 55.485 50.49 55.755 ;
     RECT  2.16 56.025 50.49 56.295 ;
     RECT  2.16 56.565 50.49 56.835 ;
     RECT  2.16 57.105 50.49 57.375 ;
     RECT  2.16 57.645 50.49 57.915 ;
     RECT  2.16 58.185 50.49 58.455 ;
     RECT  2.16 58.725 50.49 58.995 ;
     RECT  2.16 59.265 50.49 59.535 ;
     RECT  2.16 59.805 50.49 60.075 ;
     RECT  2.16 60.345 50.49 60.615 ;
     RECT  2.16 60.885 50.49 61.155 ;
     RECT  2.16 61.425 50.49 61.695 ;
     RECT  2.16 61.965 50.49 62.235 ;
     RECT  2.16 62.505 50.49 62.775 ;
     RECT  2.16 63.045 50.49 63.315 ;
     RECT  2.16 63.585 50.49 63.855 ;
     RECT  2.16 64.125 50.49 64.395 ;
     RECT  2.16 64.665 50.49 64.935 ;
     RECT  2.16 65.205 50.49 65.475 ;
     RECT  2.16 65.745 50.49 66.015 ;
     RECT  2.16 66.285 50.49 66.555 ;
     RECT  2.16 66.825 50.49 67.095 ;
     RECT  2.16 67.365 50.49 67.635 ;
     RECT  2.16 67.905 50.49 68.175 ;
     RECT  2.16 68.445 50.49 68.715 ;
     RECT  2.16 68.985 50.49 69.255 ;
     RECT  2.16 69.525 50.49 69.795 ;
     RECT  2.16 70.065 50.49 70.335 ;
     RECT  2.16 70.605 50.49 70.875 ;
     RECT  2.16 71.145 50.49 71.415 ;
     RECT  2.16 71.685 50.49 71.955 ;
     RECT  2.16 72.225 50.49 72.495 ;
     RECT  2.16 72.765 50.49 73.035 ;
     RECT  2.16 73.305 50.49 73.575 ;
     RECT  2.16 73.845 50.49 74.115 ;
     RECT  2.16 74.385 50.49 74.655 ;
     RECT  2.16 74.925 50.49 75.195 ;
     RECT  2.16 75.465 50.49 75.735 ;
     RECT  2.16 76.005 50.49 76.275 ;
     RECT  2.16 76.545 50.49 76.815 ;
     RECT  2.16 77.085 50.49 77.355 ;
     RECT  2.16 77.625 50.49 77.895 ;
     RECT  2.16 78.165 50.49 78.435 ;
     RECT  2.16 78.705 50.49 78.975 ;
     RECT  2.16 79.245 50.49 79.515 ;
     RECT  2.16 79.785 50.49 80.055 ;
     RECT  2.16 80.325 50.49 80.595 ;
     RECT  2.16 80.865 50.49 81.135 ;
     RECT  2.16 81.405 50.49 81.675 ;
     RECT  2.16 81.945 50.49 82.215 ;
     RECT  2.16 82.485 50.49 82.755 ;
     RECT  2.16 83.025 50.49 83.295 ;
     RECT  2.16 83.565 50.49 83.835 ;
     RECT  2.16 84.105 50.49 84.375 ;
     RECT  2.16 84.645 50.49 84.915 ;
     RECT  2.16 85.185 50.49 85.455 ;
     RECT  2.16 85.725 50.49 85.995 ;
     RECT  2.16 86.265 50.49 86.535 ;
     RECT  2.16 86.805 50.49 87.075 ;
     RECT  2.16 87.345 50.49 87.615 ;
     RECT  2.16 87.885 50.49 88.155 ;
     RECT  2.16 88.425 50.49 88.695 ;
     RECT  2.16 88.965 50.49 89.235 ;
     RECT  2.16 89.505 50.49 89.775 ;
     RECT  2.16 90.045 50.49 90.315 ;
     RECT  2.16 90.585 50.49 90.855 ;
     RECT  2.16 91.125 50.49 91.395 ;
     RECT  2.16 91.665 50.49 91.935 ;
     RECT  2.16 92.205 50.49 92.475 ;
     RECT  2.16 92.745 50.49 93.015 ;
     RECT  2.16 93.285 50.49 93.555 ;
     RECT  2.16 93.825 50.49 94.095 ;
     RECT  2.16 94.365 50.49 94.635 ;
     RECT  2.16 94.905 50.49 95.175 ;
     RECT  2.16 95.445 50.49 95.715 ;
     RECT  2.16 95.985 50.49 96.255 ;
     RECT  2.16 96.525 50.49 96.795 ;
     RECT  2.16 97.065 50.49 97.335 ;
     RECT  2.16 97.605 50.49 97.875 ;
     RECT  2.16 98.145 50.49 98.415 ;
     RECT  2.16 98.685 50.49 98.955 ;
     RECT  2.16 99.225 50.49 99.495 ;
     RECT  2.16 99.765 50.49 100.035 ;
     RECT  2.16 100.305 50.49 100.575 ;
     RECT  2.16 100.845 50.49 101.115 ;
    LAYER RVTP ;
     RECT  2.16 2.295 50.49 2.565 ;
     RECT  2.16 2.835 50.49 3.105 ;
     RECT  2.16 3.375 50.49 3.645 ;
     RECT  2.16 3.915 50.49 4.185 ;
     RECT  2.16 4.455 50.49 4.725 ;
     RECT  2.16 4.995 50.49 5.265 ;
     RECT  2.16 5.535 50.49 5.805 ;
     RECT  2.16 6.075 50.49 6.345 ;
     RECT  2.16 6.615 50.49 6.885 ;
     RECT  2.16 7.155 50.49 7.425 ;
     RECT  2.16 7.695 50.49 7.965 ;
     RECT  2.16 8.235 50.49 8.505 ;
     RECT  2.16 8.775 50.49 9.045 ;
     RECT  2.16 9.315 50.49 9.585 ;
     RECT  2.16 9.855 50.49 10.125 ;
     RECT  2.16 10.395 50.49 10.665 ;
     RECT  2.16 10.935 50.49 11.205 ;
     RECT  2.16 11.475 50.49 11.745 ;
     RECT  2.16 12.015 50.49 12.285 ;
     RECT  2.16 12.555 50.49 12.825 ;
     RECT  2.16 13.095 50.49 13.365 ;
     RECT  2.16 13.635 50.49 13.905 ;
     RECT  2.16 14.175 50.49 14.445 ;
     RECT  2.16 14.715 50.49 14.985 ;
     RECT  2.16 15.255 50.49 15.525 ;
     RECT  2.16 15.795 50.49 16.065 ;
     RECT  2.16 16.335 50.49 16.605 ;
     RECT  2.16 16.875 50.49 17.145 ;
     RECT  2.16 17.415 50.49 17.685 ;
     RECT  2.16 17.955 50.49 18.225 ;
     RECT  2.16 18.495 50.49 18.765 ;
     RECT  2.16 19.035 50.49 19.305 ;
     RECT  2.16 19.575 50.49 19.845 ;
     RECT  2.16 20.115 50.49 20.385 ;
     RECT  2.16 20.655 50.49 20.925 ;
     RECT  2.16 21.195 50.49 21.465 ;
     RECT  2.16 21.735 50.49 22.005 ;
     RECT  2.16 22.275 50.49 22.545 ;
     RECT  2.16 22.815 50.49 23.085 ;
     RECT  2.16 23.355 50.49 23.625 ;
     RECT  2.16 23.895 50.49 24.165 ;
     RECT  2.16 24.435 50.49 24.705 ;
     RECT  2.16 24.975 50.49 25.245 ;
     RECT  2.16 25.515 50.49 25.785 ;
     RECT  2.16 26.055 50.49 26.325 ;
     RECT  2.16 26.595 50.49 26.865 ;
     RECT  2.16 27.135 50.49 27.405 ;
     RECT  2.16 27.675 50.49 27.945 ;
     RECT  2.16 28.215 50.49 28.485 ;
     RECT  2.16 28.755 50.49 29.025 ;
     RECT  2.16 29.295 50.49 29.565 ;
     RECT  2.16 29.835 50.49 30.105 ;
     RECT  2.16 30.375 50.49 30.645 ;
     RECT  2.16 30.915 50.49 31.185 ;
     RECT  2.16 31.455 50.49 31.725 ;
     RECT  2.16 31.995 50.49 32.265 ;
     RECT  2.16 32.535 50.49 32.805 ;
     RECT  2.16 33.075 50.49 33.345 ;
     RECT  2.16 33.615 50.49 33.885 ;
     RECT  2.16 34.155 50.49 34.425 ;
     RECT  2.16 34.695 50.49 34.965 ;
     RECT  2.16 35.235 50.49 35.505 ;
     RECT  2.16 35.775 50.49 36.045 ;
     RECT  2.16 36.315 50.49 36.585 ;
     RECT  2.16 36.855 50.49 37.125 ;
     RECT  2.16 37.395 50.49 37.665 ;
     RECT  2.16 37.935 50.49 38.205 ;
     RECT  2.16 38.475 50.49 38.745 ;
     RECT  2.16 39.015 50.49 39.285 ;
     RECT  2.16 39.555 50.49 39.825 ;
     RECT  2.16 40.095 50.49 40.365 ;
     RECT  2.16 40.635 50.49 40.905 ;
     RECT  2.16 41.175 50.49 41.445 ;
     RECT  2.16 41.715 50.49 41.985 ;
     RECT  2.16 42.255 50.49 42.525 ;
     RECT  2.16 42.795 50.49 43.065 ;
     RECT  2.16 43.335 50.49 43.605 ;
     RECT  2.16 43.875 50.49 44.145 ;
     RECT  2.16 44.415 50.49 44.685 ;
     RECT  2.16 44.955 50.49 45.225 ;
     RECT  2.16 45.495 50.49 45.765 ;
     RECT  2.16 46.035 50.49 46.305 ;
     RECT  2.16 46.575 50.49 46.845 ;
     RECT  2.16 47.115 50.49 47.385 ;
     RECT  2.16 47.655 50.49 47.925 ;
     RECT  2.16 48.195 50.49 48.465 ;
     RECT  2.16 48.735 50.49 49.005 ;
     RECT  2.16 49.275 50.49 49.545 ;
     RECT  2.16 49.815 50.49 50.085 ;
     RECT  2.16 50.355 50.49 50.625 ;
     RECT  2.16 50.895 50.49 51.165 ;
     RECT  2.16 51.435 50.49 51.705 ;
     RECT  2.16 51.975 50.49 52.245 ;
     RECT  2.16 52.515 50.49 52.785 ;
     RECT  2.16 53.055 50.49 53.325 ;
     RECT  2.16 53.595 50.49 53.865 ;
     RECT  2.16 54.135 50.49 54.405 ;
     RECT  2.16 54.675 50.49 54.945 ;
     RECT  2.16 55.215 50.49 55.485 ;
     RECT  2.16 55.755 50.49 56.025 ;
     RECT  2.16 56.295 50.49 56.565 ;
     RECT  2.16 56.835 50.49 57.105 ;
     RECT  2.16 57.375 50.49 57.645 ;
     RECT  2.16 57.915 50.49 58.185 ;
     RECT  2.16 58.455 50.49 58.725 ;
     RECT  2.16 58.995 50.49 59.265 ;
     RECT  2.16 59.535 50.49 59.805 ;
     RECT  2.16 60.075 50.49 60.345 ;
     RECT  2.16 60.615 50.49 60.885 ;
     RECT  2.16 61.155 50.49 61.425 ;
     RECT  2.16 61.695 50.49 61.965 ;
     RECT  2.16 62.235 50.49 62.505 ;
     RECT  2.16 62.775 50.49 63.045 ;
     RECT  2.16 63.315 50.49 63.585 ;
     RECT  2.16 63.855 50.49 64.125 ;
     RECT  2.16 64.395 50.49 64.665 ;
     RECT  2.16 64.935 50.49 65.205 ;
     RECT  2.16 65.475 50.49 65.745 ;
     RECT  2.16 66.015 50.49 66.285 ;
     RECT  2.16 66.555 50.49 66.825 ;
     RECT  2.16 67.095 50.49 67.365 ;
     RECT  2.16 67.635 50.49 67.905 ;
     RECT  2.16 68.175 50.49 68.445 ;
     RECT  2.16 68.715 50.49 68.985 ;
     RECT  2.16 69.255 50.49 69.525 ;
     RECT  2.16 69.795 50.49 70.065 ;
     RECT  2.16 70.335 50.49 70.605 ;
     RECT  2.16 70.875 50.49 71.145 ;
     RECT  2.16 71.415 50.49 71.685 ;
     RECT  2.16 71.955 50.49 72.225 ;
     RECT  2.16 72.495 50.49 72.765 ;
     RECT  2.16 73.035 50.49 73.305 ;
     RECT  2.16 73.575 50.49 73.845 ;
     RECT  2.16 74.115 50.49 74.385 ;
     RECT  2.16 74.655 50.49 74.925 ;
     RECT  2.16 75.195 50.49 75.465 ;
     RECT  2.16 75.735 50.49 76.005 ;
     RECT  2.16 76.275 50.49 76.545 ;
     RECT  2.16 76.815 50.49 77.085 ;
     RECT  2.16 77.355 50.49 77.625 ;
     RECT  2.16 77.895 50.49 78.165 ;
     RECT  2.16 78.435 50.49 78.705 ;
     RECT  2.16 78.975 50.49 79.245 ;
     RECT  2.16 79.515 50.49 79.785 ;
     RECT  2.16 80.055 50.49 80.325 ;
     RECT  2.16 80.595 50.49 80.865 ;
     RECT  2.16 81.135 50.49 81.405 ;
     RECT  2.16 81.675 50.49 81.945 ;
     RECT  2.16 82.215 50.49 82.485 ;
     RECT  2.16 82.755 50.49 83.025 ;
     RECT  2.16 83.295 50.49 83.565 ;
     RECT  2.16 83.835 50.49 84.105 ;
     RECT  2.16 84.375 50.49 84.645 ;
     RECT  2.16 84.915 50.49 85.185 ;
     RECT  2.16 85.455 50.49 85.725 ;
     RECT  2.16 85.995 50.49 86.265 ;
     RECT  2.16 86.535 50.49 86.805 ;
     RECT  2.16 87.075 50.49 87.345 ;
     RECT  2.16 87.615 50.49 87.885 ;
     RECT  2.16 88.155 50.49 88.425 ;
     RECT  2.16 88.695 50.49 88.965 ;
     RECT  2.16 89.235 50.49 89.505 ;
     RECT  2.16 89.775 50.49 90.045 ;
     RECT  2.16 90.315 50.49 90.585 ;
     RECT  2.16 90.855 50.49 91.125 ;
     RECT  2.16 91.395 50.49 91.665 ;
     RECT  2.16 91.935 50.49 92.205 ;
     RECT  2.16 92.475 50.49 92.745 ;
     RECT  2.16 93.015 50.49 93.285 ;
     RECT  2.16 93.555 50.49 93.825 ;
     RECT  2.16 94.095 50.49 94.365 ;
     RECT  2.16 94.635 50.49 94.905 ;
     RECT  2.16 95.175 50.49 95.445 ;
     RECT  2.16 95.715 50.49 95.985 ;
     RECT  2.16 96.255 50.49 96.525 ;
     RECT  2.16 96.795 50.49 97.065 ;
     RECT  2.16 97.335 50.49 97.605 ;
     RECT  2.16 97.875 50.49 98.145 ;
     RECT  2.16 98.415 50.49 98.685 ;
     RECT  2.16 98.955 50.49 99.225 ;
     RECT  2.16 99.495 50.49 99.765 ;
     RECT  2.16 100.035 50.49 100.305 ;
     RECT  2.16 100.575 50.49 100.845 ;
     RECT  2.16 101.115 50.49 101.25 ;
    LAYER M1 ;
     RECT  2.16 2.151 50.49 101.259 ;
    LAYER M2 ;
     RECT  0.031 53.298 0.067 53.316 ;
     RECT  0.031 57.924 0.067 57.942 ;
     RECT  0.031 39.798 0.103 39.816 ;
     RECT  0.031 47.934 0.103 47.952 ;
     RECT  0.067 49.131 0.103 49.149 ;
     RECT  0.067 52.866 0.103 53.388 ;
     RECT  0.103 39.798 0.131 40.122 ;
     RECT  0.131 40.104 0.139 40.122 ;
     RECT  0.103 47.934 0.139 49.149 ;
     RECT  0.103 52.866 0.139 53.514 ;
     RECT  0.031 54.612 0.139 54.63 ;
     RECT  0.067 57.501 0.139 57.942 ;
     RECT  0.103 62.046 0.139 62.064 ;
     RECT  0.139 40.104 0.175 40.554 ;
     RECT  0.139 41.346 0.175 42.354 ;
     RECT  0.103 43.614 0.175 43.632 ;
     RECT  0.139 45.126 0.175 45.144 ;
     RECT  0.139 46.044 0.175 46.224 ;
     RECT  0.139 47.628 0.175 51.12 ;
     RECT  0.139 52.146 0.175 53.514 ;
     RECT  0.139 54.306 0.175 54.63 ;
     RECT  0.139 56.106 0.175 56.25 ;
     RECT  0.139 57.501 0.175 58.248 ;
     RECT  0.103 60.696 0.175 60.804 ;
     RECT  0.175 45.126 0.211 46.719 ;
     RECT  0.175 47.628 0.211 54.63 ;
     RECT  0.175 55.764 0.211 56.394 ;
     RECT  0.139 62.046 0.211 62.649 ;
     RECT  0.211 44.856 0.247 54.63 ;
     RECT  0.211 55.764 0.247 56.628 ;
     RECT  0.175 57.501 0.247 58.644 ;
     RECT  0.211 62.046 0.247 63.036 ;
     RECT  0.247 44.694 0.283 54.702 ;
     RECT  0.283 44.694 0.383 54.774 ;
     RECT  0.175 40.104 0.427 43.866 ;
     RECT  0.383 44.694 0.427 46.638 ;
     RECT  0.247 55.764 0.499 58.752 ;
     RECT  0.247 61.704 0.499 63.036 ;
     RECT  0.427 40.104 0.527 46.638 ;
     RECT  0.383 47.394 0.535 54.774 ;
     RECT  0.499 55.566 0.535 58.752 ;
     RECT  0.175 60.696 0.535 60.948 ;
     RECT  0.499 61.704 0.535 63.234 ;
     RECT  0.103 59.706 0.607 59.724 ;
     RECT  0.535 60.696 0.607 63.234 ;
     RECT  0.139 64.638 1.147 64.656 ;
     RECT  0.527 40.176 1.183 46.638 ;
     RECT  0.535 47.394 1.183 58.752 ;
     RECT  1.183 40.176 2.119 58.752 ;
     RECT  2.119 39.798 2.16 58.752 ;
     RECT  0.607 59.706 2.16 63.234 ;
     RECT  1.147 64.17 2.16 64.656 ;
     RECT  9.895 0.036 11.947 0.054 ;
     RECT  2.16 2.151 12.631 101.259 ;
     RECT  11.947 0.036 12.703 0.09 ;
     RECT  12.703 0.036 12.983 0.549 ;
     RECT  12.631 2.151 13.055 101.304 ;
     RECT  12.983 0.036 14.071 0.162 ;
     RECT  14.071 0.036 14.143 0.198 ;
     RECT  14.143 0.036 14.531 0.549 ;
     RECT  13.055 2.151 14.827 101.259 ;
     RECT  14.827 2.151 14.927 101.574 ;
     RECT  14.927 2.151 16.231 101.259 ;
     RECT  16.519 102.591 16.619 102.609 ;
     RECT  14.531 0.036 17.735 0.198 ;
     RECT  16.231 2.151 17.779 101.304 ;
     RECT  17.779 2.151 17.879 101.682 ;
     RECT  17.735 0.036 18.347 0.054 ;
     RECT  17.879 2.151 20.435 101.304 ;
     RECT  20.479 0.216 21.443 0.234 ;
     RECT  22.135 1.152 22.235 1.17 ;
     RECT  26.635 0.531 26.771 0.549 ;
     RECT  20.435 2.151 26.779 101.259 ;
     RECT  27.571 0.45 27.959 0.468 ;
     RECT  26.779 2.034 30.371 101.259 ;
     RECT  35.239 0.378 35.339 0.396 ;
     RECT  30.371 2.106 35.843 101.259 ;
     RECT  35.843 2.151 37.507 101.259 ;
     RECT  37.507 2.151 37.607 101.754 ;
     RECT  37.607 2.151 38.407 101.259 ;
     RECT  38.407 2.151 39.083 101.304 ;
     RECT  39.083 2.151 50.49 101.259 ;
    LAYER M3 ;
     RECT  18.324 0.031 18.342 0.091 ;
     RECT  20.7 0.043 21.366 0.091 ;
     RECT  22.14 0.043 22.158 0.091 ;
     RECT  16.164 0.067 16.182 0.103 ;
     RECT  12.96 0.103 12.978 0.139 ;
     RECT  16.164 0.103 16.578 0.139 ;
     RECT  18.324 0.091 18.522 0.139 ;
     RECT  20.7 0.091 22.59 0.139 ;
     RECT  23.76 0.043 23.778 0.139 ;
     RECT  30.024 0.091 30.042 0.139 ;
     RECT  34.236 0.091 34.254 0.139 ;
     RECT  14.04 0.139 14.31 0.187 ;
     RECT  15.3 0.139 18.594 0.187 ;
     RECT  19.332 0.139 24.354 0.187 ;
     RECT  25.452 0.139 34.47 0.187 ;
     RECT  35.892 0.139 38.07 0.187 ;
     RECT  14.04 0.187 18.594 0.235 ;
     RECT  19.332 0.187 24.498 0.235 ;
     RECT  25.452 0.187 38.07 0.235 ;
     RECT  14.04 0.235 24.498 0.283 ;
     RECT  25.452 0.235 38.43 0.283 ;
     RECT  14.04 0.283 38.43 0.475 ;
     RECT  12.924 0.139 12.978 0.526 ;
     RECT  13.896 0.475 38.43 1.003 ;
     RECT  12.708 0.526 12.978 1.051 ;
     RECT  13.86 1.003 38.43 1.051 ;
     RECT  11.952 0.067 11.97 1.675 ;
     RECT  12.708 1.051 38.43 1.675 ;
     RECT  2.415 2.143 2.505 2.413 ;
     RECT  7.815 2.143 7.905 2.413 ;
     RECT  40.215 2.143 40.305 2.413 ;
     RECT  45.615 2.143 45.705 2.413 ;
     RECT  7.815 2.413 8.097 2.641 ;
     RECT  10.836 2.839 10.854 2.875 ;
     RECT  7.128 2.641 8.097 3.073 ;
     RECT  9.9 0.031 9.918 3.073 ;
     RECT  6.84 3.073 8.097 3.137 ;
     RECT  7.128 3.137 8.097 3.145 ;
     RECT  10.836 2.875 10.89 3.145 ;
     RECT  11.952 1.675 38.43 3.145 ;
     RECT  7.128 3.145 8.262 3.181 ;
     RECT  9.396 3.073 9.918 3.181 ;
     RECT  7.128 3.181 9.918 3.307 ;
     RECT  10.836 3.145 38.43 3.307 ;
     RECT  5.796 3.181 5.814 11.677 ;
     RECT  7.128 3.307 38.43 11.677 ;
     RECT  5.796 11.677 38.43 30.335 ;
     RECT  6.516 30.335 38.43 32.459 ;
     RECT  6.516 32.459 38.394 35.815 ;
     RECT  2.415 2.413 2.697 39.181 ;
     RECT  5.112 30.451 5.13 39.721 ;
     RECT  6.516 35.815 38.43 39.721 ;
     RECT  0.036 39.784 0.054 39.793 ;
     RECT  2.232 39.181 2.697 39.793 ;
     RECT  0.036 39.793 0.126 39.821 ;
     RECT  2.124 39.793 2.697 39.829 ;
     RECT  3.888 39.289 3.906 39.829 ;
     RECT  0.108 39.821 0.126 39.883 ;
     RECT  2.124 39.829 3.906 39.965 ;
     RECT  0.108 39.883 0.486 40.099 ;
     RECT  2.196 39.965 3.906 40.123 ;
     RECT  5.112 39.721 38.43 40.123 ;
     RECT  0.108 40.099 0.522 40.127 ;
     RECT  2.196 40.123 38.43 40.205 ;
     RECT  2.232 40.205 38.43 40.289 ;
     RECT  2.232 40.289 4.338 40.493 ;
     RECT  2.268 40.493 4.338 40.925 ;
     RECT  2.34 40.925 4.338 41.035 ;
     RECT  5.112 40.289 38.43 41.035 ;
     RECT  0.144 40.127 0.522 41.275 ;
     RECT  2.34 41.035 38.43 41.549 ;
     RECT  2.34 41.549 5.202 42.061 ;
     RECT  2.304 42.061 5.202 42.221 ;
     RECT  0.144 41.275 0.558 42.235 ;
     RECT  0.144 42.235 0.666 42.359 ;
     RECT  0.18 42.359 0.666 42.379 ;
     RECT  0.18 42.379 1.17 42.421 ;
     RECT  2.304 42.221 2.898 42.421 ;
     RECT  0.18 42.421 2.898 42.461 ;
     RECT  3.672 42.221 5.202 42.529 ;
     RECT  6.372 41.549 38.43 42.529 ;
     RECT  0.18 42.461 2.862 42.701 ;
     RECT  3.672 42.529 38.43 43.025 ;
     RECT  0.18 42.701 1.386 43.085 ;
     RECT  3.672 43.025 4.23 43.097 ;
     RECT  2.304 42.701 2.862 43.259 ;
     RECT  0.18 43.085 1.206 43.277 ;
     RECT  2.34 43.259 2.754 43.295 ;
     RECT  3.744 43.097 4.23 43.295 ;
     RECT  0.18 43.277 0.342 43.579 ;
     RECT  0.108 43.579 0.342 43.637 ;
     RECT  1.152 43.277 1.206 43.709 ;
     RECT  0.18 43.637 0.342 43.871 ;
     RECT  3.888 43.295 4.23 43.879 ;
     RECT  5.112 43.025 38.43 43.879 ;
     RECT  0.324 43.871 0.342 44.299 ;
     RECT  3.888 43.879 38.43 44.311 ;
     RECT  0.324 44.299 0.414 44.455 ;
     RECT  1.152 43.709 1.17 44.455 ;
     RECT  0.324 44.455 1.17 44.491 ;
     RECT  2.34 43.295 2.697 44.491 ;
     RECT  0.324 44.491 1.278 44.539 ;
     RECT  2.304 44.491 2.697 44.539 ;
     RECT  3.42 44.311 38.43 44.539 ;
     RECT  0.324 44.539 1.458 44.689 ;
     RECT  0.252 44.689 1.458 44.761 ;
     RECT  2.232 44.539 38.43 44.761 ;
     RECT  0.252 44.761 38.43 44.813 ;
     RECT  0.252 44.813 0.45 44.851 ;
     RECT  0.216 44.851 0.45 45.067 ;
     RECT  0.144 45.067 0.45 45.547 ;
     RECT  1.188 44.813 38.43 45.547 ;
     RECT  0.144 45.547 38.43 46.229 ;
     RECT  0.18 46.229 38.43 46.301 ;
     RECT  2.304 46.301 38.43 46.733 ;
     RECT  0.18 46.301 1.314 47.179 ;
     RECT  2.304 46.733 4.23 47.179 ;
     RECT  0.18 47.179 4.23 47.611 ;
     RECT  5.04 46.733 38.43 47.821 ;
     RECT  0.144 47.611 4.23 47.893 ;
     RECT  4.968 47.821 38.43 47.893 ;
     RECT  0.144 47.893 38.43 47.929 ;
     RECT  0.036 47.929 38.43 49.505 ;
     RECT  6.264 49.505 38.43 49.577 ;
     RECT  0.036 49.505 5.454 50.251 ;
     RECT  0.036 50.251 5.526 50.359 ;
     RECT  6.336 49.577 38.43 50.359 ;
     RECT  0.036 50.359 38.43 50.729 ;
     RECT  0.036 50.729 5.346 51.197 ;
     RECT  1.404 51.197 5.346 51.781 ;
     RECT  6.192 50.729 38.43 51.781 ;
     RECT  0.036 51.197 0.558 51.931 ;
     RECT  1.404 51.781 38.43 51.931 ;
     RECT  0.036 51.931 38.43 52.285 ;
     RECT  0.036 52.285 38.79 52.829 ;
     RECT  0.036 52.829 0.594 53.321 ;
     RECT  1.368 52.829 38.79 53.645 ;
     RECT  0.072 53.321 0.594 53.707 ;
     RECT  0.072 53.707 1.314 53.969 ;
     RECT  0.072 53.969 1.17 54.131 ;
     RECT  2.088 53.645 38.79 54.203 ;
     RECT  2.268 54.203 38.79 54.409 ;
     RECT  2.268 54.409 39.186 54.473 ;
     RECT  0.072 54.131 1.134 54.607 ;
     RECT  2.268 54.473 5.346 55.085 ;
     RECT  0.036 54.607 1.134 55.339 ;
     RECT  2.304 55.085 5.346 55.381 ;
     RECT  6.192 54.473 39.186 55.381 ;
     RECT  2.304 55.381 39.186 55.679 ;
     RECT  0.036 55.339 1.17 55.921 ;
     RECT  0.036 55.921 1.35 56.141 ;
     RECT  0.036 56.141 1.278 56.219 ;
     RECT  0.036 56.219 1.206 56.363 ;
     RECT  2.304 55.679 5.346 56.525 ;
     RECT  2.34 56.525 5.346 57.037 ;
     RECT  6.192 55.679 39.186 57.037 ;
     RECT  2.34 57.037 39.186 57.259 ;
     RECT  0.036 56.363 1.134 57.403 ;
     RECT  0.036 57.403 1.17 57.883 ;
     RECT  2.304 57.259 39.186 57.883 ;
     RECT  0.036 57.883 39.186 57.947 ;
     RECT  0.144 57.947 39.186 58.117 ;
     RECT  40.215 2.413 40.497 58.117 ;
     RECT  0.144 58.117 40.497 58.253 ;
     RECT  0.18 58.253 40.497 58.349 ;
     RECT  0.18 58.349 0.594 58.685 ;
     RECT  0.18 58.685 0.414 58.702 ;
     RECT  1.692 58.349 40.497 59.117 ;
     RECT  0.216 58.702 0.414 59.701 ;
     RECT  0.108 59.701 0.414 60.241 ;
     RECT  2.415 59.117 40.497 60.749 ;
     RECT  0.108 60.241 0.63 60.845 ;
     RECT  2.415 60.749 5.346 60.961 ;
     RECT  2.232 60.961 5.346 61.037 ;
     RECT  0.18 60.845 0.63 62.011 ;
     RECT  2.415 61.037 5.346 62.041 ;
     RECT  0.108 62.011 0.63 62.069 ;
     RECT  2.304 62.041 5.346 62.581 ;
     RECT  2.232 62.581 5.346 62.621 ;
     RECT  0.144 62.069 0.63 62.669 ;
     RECT  0.216 62.669 0.63 62.827 ;
     RECT  0.216 62.827 0.666 63.041 ;
     RECT  0.324 63.041 0.666 63.197 ;
     RECT  0.324 63.197 0.558 63.437 ;
     RECT  0.324 63.437 0.522 63.725 ;
     RECT  2.34 62.621 5.346 63.739 ;
     RECT  0.324 63.725 0.414 63.931 ;
     RECT  6.192 60.749 40.497 64.021 ;
     RECT  6.192 64.021 40.554 64.109 ;
     RECT  7.272 64.109 40.554 64.121 ;
     RECT  0.18 63.931 0.414 64.171 ;
     RECT  0.144 64.171 0.414 64.205 ;
     RECT  1.152 64.165 1.17 64.301 ;
     RECT  2.304 63.739 5.346 64.319 ;
     RECT  0.144 64.205 0.198 64.397 ;
     RECT  0.144 64.397 0.162 64.661 ;
     RECT  2.415 64.319 3.906 65.399 ;
     RECT  7.272 64.121 40.497 65.443 ;
     RECT  7.272 65.443 40.554 65.515 ;
     RECT  7.272 65.515 40.626 66.325 ;
     RECT  7.272 66.325 40.698 66.901 ;
     RECT  7.272 66.901 40.842 67.055 ;
     RECT  6.192 64.109 6.21 69.259 ;
     RECT  7.272 67.055 40.497 69.259 ;
     RECT  4.896 64.319 5.346 69.359 ;
     RECT  4.896 69.359 4.914 69.719 ;
     RECT  2.415 65.399 3.366 69.899 ;
     RECT  6.192 69.259 40.497 69.899 ;
     RECT  6.192 69.899 6.21 70.133 ;
     RECT  7.272 69.899 40.497 70.169 ;
     RECT  7.632 70.169 40.497 70.835 ;
     RECT  7.668 70.835 40.497 72.841 ;
     RECT  7.668 72.841 40.518 73.103 ;
     RECT  7.668 73.103 40.497 73.921 ;
     RECT  7.668 73.921 40.554 74.083 ;
     RECT  7.668 74.083 40.842 75.029 ;
     RECT  7.668 75.029 40.626 75.929 ;
     RECT  7.668 75.929 40.497 79.321 ;
     RECT  7.668 79.321 40.554 79.861 ;
     RECT  7.668 79.861 40.698 80.015 ;
     RECT  7.668 80.015 40.497 81.329 ;
     RECT  7.815 81.329 40.497 82.525 ;
     RECT  7.815 82.525 40.59 82.679 ;
     RECT  7.815 82.679 40.497 84.955 ;
     RECT  7.815 84.955 40.698 85.109 ;
     RECT  7.815 85.109 40.497 91.399 ;
     RECT  7.815 91.399 40.554 91.859 ;
     RECT  7.815 91.859 40.497 93.749 ;
     RECT  9.432 93.749 40.497 94.171 ;
     RECT  9.432 94.171 40.734 94.675 ;
     RECT  9.432 94.675 40.878 95.099 ;
     RECT  9.432 95.099 40.77 95.135 ;
     RECT  9.432 95.135 40.497 96.989 ;
     RECT  9.432 96.989 9.594 97.259 ;
     RECT  10.908 96.989 40.497 100.067 ;
     RECT  9.576 97.259 9.594 100.229 ;
     RECT  11.052 100.067 40.497 100.229 ;
     RECT  11.052 100.229 39.402 100.769 ;
     RECT  11.412 100.769 39.366 100.949 ;
     RECT  2.415 69.899 2.697 100.997 ;
     RECT  7.815 93.749 8.097 100.997 ;
     RECT  40.215 100.229 40.497 100.997 ;
     RECT  45.615 2.413 45.897 100.997 ;
     RECT  12.06 100.949 39.366 101.219 ;
     RECT  2.607 100.997 2.697 101.267 ;
     RECT  8.007 100.997 8.097 101.267 ;
     RECT  40.407 100.997 40.497 101.267 ;
     RECT  45.807 100.997 45.897 101.267 ;
     RECT  12.636 101.219 39.366 101.309 ;
     RECT  13.176 101.309 39.366 101.597 ;
     RECT  13.176 101.597 32.67 102.029 ;
     RECT  33.516 101.597 39.366 102.029 ;
     RECT  13.176 102.029 29.034 102.605 ;
     RECT  33.588 102.029 39.366 102.605 ;
     RECT  13.176 102.605 28.242 102.653 ;
     RECT  14.328 102.653 27.27 102.701 ;
     RECT  29.016 102.605 29.034 102.701 ;
     RECT  13.536 102.653 13.554 102.749 ;
     RECT  14.616 102.701 15.75 102.749 ;
     RECT  16.524 102.701 25.038 102.749 ;
     RECT  20.772 102.749 25.038 102.797 ;
     RECT  30.06 102.029 32.634 102.797 ;
     RECT  14.616 102.749 15.714 102.845 ;
     RECT  16.524 102.749 19.998 102.845 ;
     RECT  25.884 102.701 27.27 102.845 ;
     RECT  33.588 102.605 38.934 103.003 ;
     RECT  33.48 103.003 38.934 103.099 ;
     RECT  33.372 103.099 38.934 103.229 ;
     RECT  30.168 102.797 32.634 103.291 ;
     RECT  33.372 103.229 34.65 103.291 ;
     RECT  20.772 102.797 23.454 103.373 ;
     RECT  24.408 102.797 25.038 103.421 ;
     RECT  30.168 103.291 34.65 103.421 ;
     RECT  16.524 102.845 19.242 103.469 ;
     RECT  22.608 103.373 23.022 103.469 ;
     RECT  24.732 103.421 25.038 103.469 ;
     RECT  30.168 103.421 30.726 103.469 ;
     RECT  32.328 103.421 34.65 103.469 ;
     RECT  35.424 103.229 38.934 103.469 ;
     RECT  16.524 103.469 17.226 103.483 ;
     RECT  19.98 102.845 19.998 103.483 ;
     RECT  20.772 103.373 21.618 103.483 ;
     RECT  14.616 102.845 15.03 103.517 ;
     RECT  16.128 103.483 17.226 103.517 ;
     RECT  18 103.469 19.242 103.517 ;
     RECT  19.98 103.483 21.618 103.517 ;
     RECT  22.896 103.469 23.022 103.517 ;
     RECT  24.732 103.469 24.966 103.517 ;
     RECT  25.884 102.845 27.09 103.517 ;
     RECT  28.08 102.653 28.242 103.517 ;
     RECT  30.168 103.469 30.654 103.517 ;
     RECT  32.328 103.469 32.634 103.517 ;
     RECT  33.372 103.469 34.182 103.517 ;
     RECT  35.496 103.469 36.198 103.517 ;
     RECT  37.08 103.469 37.386 103.517 ;
     RECT  38.196 103.469 38.934 103.517 ;
     RECT  16.128 103.517 16.542 103.565 ;
     RECT  18 103.517 18.342 103.565 ;
     RECT  20.88 103.517 21.618 103.565 ;
     RECT  25.884 103.517 25.902 103.565 ;
     RECT  27.072 103.517 27.09 103.565 ;
     RECT  28.08 103.517 28.098 103.565 ;
     RECT  30.168 103.517 30.186 103.565 ;
     RECT  32.328 103.517 32.346 103.565 ;
     RECT  33.372 103.517 33.606 103.565 ;
     RECT  37.08 103.517 37.098 103.565 ;
     RECT  38.916 103.517 38.934 103.565 ;
     RECT  14.616 103.517 14.634 103.613 ;
     RECT  16.128 103.565 16.146 103.613 ;
     RECT  18.324 103.565 18.342 103.613 ;
     RECT  20.088 103.517 20.106 103.613 ;
    LAYER M4 ;
     RECT  0.025 39.792 0.06 39.816 ;
     RECT  0.06 39.696 0.133 64.296 ;
     RECT  0.133 39.696 0.169 64.344 ;
     RECT  0.169 39.696 2.408 64.392 ;
     RECT  2.408 2.148 2.512 100.992 ;
     RECT  2.512 2.418 2.6 100.992 ;
     RECT  2.6 2.418 2.704 101.262 ;
     RECT  2.704 40.032 3.413 64.392 ;
     RECT  3.413 40.08 3.773 64.392 ;
     RECT  3.773 40.128 4.601 64.392 ;
     RECT  4.601 40.176 6.833 64.392 ;
     RECT  6.833 40.32 7.808 64.392 ;
     RECT  7.808 2.148 7.912 100.992 ;
     RECT  7.912 2.418 8 100.992 ;
     RECT  8 2.418 8.104 101.262 ;
     RECT  8.104 86.016 8.317 86.04 ;
     RECT  8.104 79.152 8.627 79.176 ;
     RECT  8.104 39.888 8.741 64.392 ;
     RECT  8.741 39.888 8.849 39.912 ;
     RECT  8.104 65.568 8.957 66.648 ;
     RECT  8.104 82.32 9.011 82.344 ;
     RECT  8.957 65.568 9.107 65.592 ;
     RECT  8.957 66.624 9.107 66.648 ;
     RECT  9.301 80.88 9.388 80.904 ;
     RECT  8.741 41.04 9.641 64.392 ;
     RECT  10.021 72.336 10.108 72.36 ;
     RECT  9.641 41.472 10.325 64.392 ;
     RECT  10.268 77.952 10.355 77.976 ;
     RECT  9.673 71.184 10.393 71.208 ;
     RECT  10.325 41.856 10.397 64.392 ;
     RECT  10.393 70.704 10.465 71.208 ;
     RECT  10.405 79.68 10.492 79.704 ;
     RECT  10.549 87.792 10.636 87.816 ;
     RECT  10.357 69.216 10.645 69.24 ;
     RECT  10.645 69.216 10.681 69.48 ;
     RECT  10.465 70.608 10.681 71.208 ;
     RECT  10.681 69.216 10.793 71.208 ;
     RECT  10.393 77.472 10.835 77.496 ;
     RECT  10.796 66.624 10.883 66.648 ;
     RECT  10.397 41.904 10.988 64.392 ;
     RECT  10.837 83.136 11.045 83.16 ;
     RECT  10.897 87.648 11.045 87.672 ;
     RECT  10.988 41.904 11.075 65.016 ;
     RECT  10.681 75.312 11.105 75.336 ;
     RECT  11.105 75.216 11.149 75.336 ;
     RECT  10.793 69.216 11.153 69.48 ;
     RECT  11.149 75.216 11.189 76.2 ;
     RECT  11.075 41.904 11.365 64.392 ;
     RECT  11.005 96.192 11.411 96.216 ;
     RECT  11.365 41.472 11.437 64.392 ;
     RECT  11.473 82.656 11.557 82.68 ;
     RECT  11.516 90.72 11.603 90.744 ;
     RECT  11.437 41.424 11.653 64.392 ;
     RECT  11.573 94.656 11.657 94.68 ;
     RECT  11.617 96.336 11.701 96.36 ;
     RECT  11.66 92.928 11.747 92.952 ;
     RECT  11.437 40.032 11.977 40.056 ;
     RECT  11.653 41.04 11.977 64.392 ;
     RECT  11.905 98.352 11.989 98.376 ;
     RECT  11.977 40.032 12.053 64.392 ;
     RECT  10.825 3.36 12.085 3.384 ;
     RECT  10.825 68.112 12.089 68.136 ;
     RECT  12.037 97.488 12.125 97.512 ;
     RECT  12.053 40.416 12.161 64.392 ;
     RECT  11.977 82.368 12.229 82.392 ;
     RECT  12.085 3.36 12.469 3.624 ;
     RECT  12.161 44.16 12.517 64.392 ;
     RECT  12.193 92.352 12.572 92.376 ;
     RECT  12.62 73.776 12.661 73.8 ;
     RECT  12.572 92.16 12.661 92.376 ;
     RECT  12.469 3.312 12.757 3.624 ;
     RECT  12.757 3.072 12.949 3.624 ;
     RECT  12.229 82.272 13.085 82.392 ;
     RECT  12.517 44.16 13.093 65.064 ;
     RECT  13.085 82.272 13.093 82.488 ;
     RECT  12.181 87.168 13.093 87.192 ;
     RECT  12.661 91.584 13.093 92.376 ;
     RECT  12.661 98.976 13.093 99.24 ;
     RECT  12.661 100.32 13.093 100.344 ;
     RECT  12.161 40.416 13.129 42.6 ;
     RECT  13.057 67.824 13.129 67.848 ;
     RECT  13.093 87.168 13.129 88.104 ;
     RECT  13.093 98.928 13.129 99.24 ;
     RECT  13.129 98.4 13.201 99.24 ;
     RECT  12.373 1.68 13.208 1.704 ;
     RECT  12.949 3.024 13.208 3.624 ;
     RECT  12.769 5.472 13.208 5.496 ;
     RECT  12.877 14.832 13.208 14.856 ;
     RECT  12.853 22.752 13.208 22.776 ;
     RECT  12.769 23.904 13.208 23.928 ;
     RECT  13.129 40.416 13.208 43.08 ;
     RECT  13.093 44.16 13.208 65.448 ;
     RECT  13.129 67.584 13.208 67.848 ;
     RECT  11.153 69.456 13.208 69.48 ;
     RECT  12.661 72.912 13.208 73.8 ;
     RECT  11.189 76.176 13.208 76.2 ;
     RECT  11.977 78.048 13.208 78.696 ;
     RECT  13.052 80.304 13.208 80.328 ;
     RECT  13.093 82.272 13.208 83.064 ;
     RECT  13.129 87.024 13.208 88.104 ;
     RECT  13.093 90.768 13.208 92.376 ;
     RECT  13.093 93.792 13.208 94.2 ;
     RECT  13.201 97.92 13.208 99.24 ;
     RECT  13.093 100.224 13.208 100.344 ;
     RECT  13.208 1.68 13.345 100.992 ;
     RECT  13.345 1.392 13.4 100.992 ;
     RECT  13.4 1.392 13.504 101.262 ;
     RECT  13.504 1.392 13.525 6.264 ;
     RECT  13.165 102.624 13.525 102.648 ;
     RECT  13.504 79.728 13.565 79.752 ;
     RECT  13.504 73.488 13.619 75.192 ;
     RECT  13.619 73.488 13.667 74.712 ;
     RECT  13.504 88.08 13.667 88.104 ;
     RECT  13.525 102.624 13.669 102.744 ;
     RECT  13.504 76.752 13.673 78.024 ;
     RECT  13.504 87.024 13.673 87.048 ;
     RECT  13.504 96.192 13.705 101.262 ;
     RECT  13.667 73.488 13.708 73.608 ;
     RECT  13.504 40.944 13.745 65.592 ;
     RECT  13.673 76.752 13.804 77.592 ;
     RECT  13.525 1.056 13.849 6.264 ;
     RECT  13.669 102.624 13.849 103.512 ;
     RECT  13.504 68.928 13.859 69 ;
     RECT  13.849 1.008 13.885 6.264 ;
     RECT  13.504 94.992 13.897 95.208 ;
     RECT  13.885 0.48 13.957 6.264 ;
     RECT  13.705 96.192 13.993 101.544 ;
     RECT  13.849 102.576 13.993 103.512 ;
     RECT  13.504 66.816 13.997 67.848 ;
     RECT  13.504 92.88 13.997 92.904 ;
     RECT  13.745 42.96 14.069 65.592 ;
     RECT  13.997 66.816 14.141 67.272 ;
     RECT  13.504 85.488 14.147 85.512 ;
     RECT  13.993 96.192 14.195 103.512 ;
     RECT  13.667 74.688 14.249 74.712 ;
     RECT  14.069 43.536 14.291 65.592 ;
     RECT  13.504 9.36 14.357 9.384 ;
     RECT  13.859 68.976 14.357 69 ;
     RECT  14.195 96.432 14.387 103.512 ;
     RECT  13.957 0.144 14.483 6.264 ;
     RECT  13.504 70.656 14.497 70.728 ;
     RECT  14.497 70.656 14.569 70.776 ;
     RECT  13.745 40.944 14.581 41.976 ;
     RECT  14.387 101.472 14.605 103.512 ;
     RECT  14.533 94.128 14.627 94.584 ;
     RECT  14.581 40.464 14.681 41.976 ;
     RECT  13.708 73.488 14.741 73.512 ;
     RECT  14.291 46.464 14.749 65.592 ;
     RECT  14.725 88.608 14.812 88.632 ;
     RECT  14.605 83.424 14.819 83.448 ;
     RECT  14.741 73.296 14.825 73.944 ;
     RECT  13.804 76.752 14.825 76.776 ;
     RECT  14.749 46.464 14.833 66.168 ;
     RECT  14.825 73.296 14.861 73.512 ;
     RECT  14.569 70.656 14.893 70.824 ;
     RECT  14.893 70.56 14.929 70.824 ;
     RECT  14.627 94.56 14.965 94.584 ;
     RECT  14.857 92.928 14.969 92.952 ;
     RECT  14.965 94.56 15.059 95.208 ;
     RECT  14.641 6.72 15.109 6.792 ;
     RECT  14.141 67.248 15.109 67.272 ;
     RECT  15.109 67.248 15.181 67.848 ;
     RECT  15.109 92.688 15.196 92.712 ;
     RECT  15.157 16.944 15.244 16.968 ;
     RECT  15.109 6.72 15.251 6.84 ;
     RECT  15.251 6.72 15.347 6.744 ;
     RECT  15.26 77.712 15.347 77.736 ;
     RECT  14.681 41.04 15.365 41.976 ;
     RECT  14.833 46.464 15.365 65.208 ;
     RECT  15.181 67.248 15.365 68.808 ;
     RECT  15.317 8.544 15.401 8.568 ;
     RECT  14.929 70.32 15.443 70.824 ;
     RECT  15.365 67.248 15.493 68.52 ;
     RECT  15.469 74.64 15.5 74.664 ;
     RECT  15.365 46.704 15.581 65.208 ;
     RECT  15.5 74.64 15.587 75.192 ;
     RECT  14.387 96.432 15.613 100.392 ;
     RECT  14.291 43.536 15.617 45.288 ;
     RECT  15.587 74.64 15.653 74.712 ;
     RECT  15.569 78.96 15.653 78.984 ;
     RECT  14.483 0.144 15.683 5.688 ;
     RECT  15.649 86.64 15.721 86.664 ;
     RECT  15.469 87.792 15.721 87.816 ;
     RECT  15.617 43.728 15.761 45.288 ;
     RECT  15.692 9.072 15.779 9.096 ;
     RECT  15.365 41.952 15.779 41.976 ;
     RECT  15.721 86.64 15.779 87.816 ;
     RECT  15.779 86.64 15.805 87.24 ;
     RECT  15.059 94.56 15.833 94.584 ;
     RECT  15.781 42.192 15.868 42.216 ;
     RECT  15.781 72.672 15.868 72.696 ;
     RECT  15.781 91.056 15.868 91.08 ;
     RECT  15.761 43.824 15.937 45.288 ;
     RECT  15.493 66.72 15.941 68.52 ;
     RECT  15.613 96.336 15.977 100.392 ;
     RECT  15.443 70.32 15.98 70.68 ;
     RECT  15.98 69.984 16.067 70.68 ;
     RECT  15.977 96.336 16.067 97.656 ;
     RECT  15.683 0.144 16.115 5.496 ;
     RECT  15.805 86.64 16.115 87.144 ;
     RECT  16.115 86.64 16.117 86.664 ;
     RECT  16.117 82.032 16.153 82.056 ;
     RECT  15.937 43.824 16.157 45.528 ;
     RECT  14.605 101.472 16.157 103.608 ;
     RECT  16.067 96.336 16.213 96.456 ;
     RECT  16.165 77.424 16.252 77.448 ;
     RECT  16.213 96.24 16.301 96.456 ;
     RECT  13.504 22.752 16.309 22.776 ;
     RECT  15.941 66.72 16.309 67.848 ;
     RECT  15.653 74.688 16.355 74.712 ;
     RECT  16.301 96.336 16.355 96.456 ;
     RECT  16.117 86.592 16.403 86.664 ;
     RECT  15.977 98.64 16.412 100.392 ;
     RECT  16.157 101.472 16.412 103.56 ;
     RECT  16.067 70.176 16.433 70.68 ;
     RECT  16.153 82.032 16.517 82.344 ;
     RECT  15.581 46.752 16.585 65.208 ;
     RECT  16.441 79.008 16.597 79.032 ;
     RECT  16.157 44.496 16.621 45.528 ;
     RECT  16.585 46.752 16.621 65.592 ;
     RECT  16.067 97.632 16.625 97.656 ;
     RECT  16.309 77.52 16.661 77.544 ;
     RECT  16.355 96.336 16.705 96.36 ;
     RECT  16.621 44.496 16.789 65.592 ;
     RECT  16.597 79.008 16.805 79.272 ;
     RECT  16.309 66.768 16.877 67.848 ;
     RECT  16.433 70.176 16.885 71.304 ;
     RECT  16.805 79.248 16.913 79.272 ;
     RECT  16.412 98.64 16.979 103.56 ;
     RECT  16.877 67.824 16.981 67.848 ;
     RECT  16.981 67.824 17.017 68.472 ;
     RECT  16.789 44.496 17.075 65.688 ;
     RECT  17.075 44.496 17.093 65.208 ;
     RECT  16.837 85.296 17.123 85.32 ;
     RECT  16.979 98.64 17.125 103.512 ;
     RECT  17.093 44.496 17.237 65.016 ;
     RECT  17.017 67.824 17.237 68.616 ;
     RECT  17.125 98.448 17.237 103.512 ;
     RECT  17.237 44.496 17.245 64.44 ;
     RECT  17.245 44.496 17.269 64.392 ;
     RECT  16.403 86.64 17.269 86.664 ;
     RECT  17.237 67.824 17.281 68.472 ;
     RECT  17.197 73.776 17.281 74.088 ;
     RECT  17.237 98.544 17.281 103.512 ;
     RECT  17.173 83.376 17.324 83.4 ;
     RECT  17.324 83.376 17.411 83.448 ;
     RECT  16.885 70.176 17.413 71.16 ;
     RECT  17.372 89.952 17.459 89.976 ;
     RECT  17.372 96.864 17.459 96.936 ;
     RECT  16.115 0.144 17.461 5.256 ;
     RECT  17.125 92.832 17.521 92.856 ;
     RECT  17.017 34.224 17.555 34.248 ;
     RECT  17.269 86.64 17.555 86.712 ;
     RECT  17.269 95.136 17.557 95.256 ;
     RECT  17.557 95.136 17.845 95.448 ;
     RECT  17.521 92.832 17.893 92.904 ;
     RECT  17.413 69.6 17.917 71.16 ;
     RECT  17.281 100.8 17.989 103.512 ;
     RECT  18.181 91.584 18.205 91.608 ;
     RECT  17.893 92.592 18.205 92.904 ;
     RECT  17.281 98.544 18.277 99.816 ;
     RECT  17.917 75.312 18.313 75.336 ;
     RECT  17.989 100.8 18.313 103.56 ;
     RECT  18.133 43.344 18.325 43.368 ;
     RECT  17.269 44.448 18.325 64.392 ;
     RECT  17.281 68.448 18.325 68.472 ;
     RECT  18.205 91.584 18.373 92.904 ;
     RECT  17.411 83.376 18.38 83.4 ;
     RECT  18.269 65.568 18.421 65.592 ;
     RECT  16.877 66.768 18.421 66.792 ;
     RECT  18.325 67.824 18.421 68.472 ;
     RECT  17.917 69.6 18.421 71.496 ;
     RECT  18.229 79.776 18.421 79.8 ;
     RECT  18.373 91.584 18.469 93.096 ;
     RECT  17.845 94.656 18.469 95.88 ;
     RECT  17.459 96.864 18.469 96.888 ;
     RECT  17.461 0.144 18.493 5.88 ;
     RECT  18.493 0.096 18.608 5.88 ;
     RECT  18.277 7.392 18.608 7.416 ;
     RECT  17.665 8.496 18.608 8.52 ;
     RECT  17.612 11.376 18.608 11.4 ;
     RECT  15.685 17.184 18.608 17.208 ;
     RECT  16.165 19.248 18.608 19.272 ;
     RECT  16.309 21.984 18.608 22.776 ;
     RECT  16.501 24.384 18.608 24.408 ;
     RECT  16.117 26.304 18.608 26.328 ;
     RECT  15.925 37.872 18.608 37.896 ;
     RECT  18.325 43.344 18.608 64.392 ;
     RECT  18.421 65.568 18.608 66.792 ;
     RECT  18.421 67.824 18.608 71.496 ;
     RECT  17.281 73.776 18.608 73.8 ;
     RECT  18.313 74.928 18.608 75.336 ;
     RECT  18.229 76.368 18.608 76.392 ;
     RECT  17.837 78.096 18.608 78.12 ;
     RECT  18.421 79.248 18.608 79.8 ;
     RECT  16.517 82.032 18.608 82.056 ;
     RECT  18.38 83.376 18.608 84.36 ;
     RECT  17.555 86.64 18.608 86.664 ;
     RECT  18.092 87.984 18.608 88.008 ;
     RECT  18.469 91.536 18.608 93.096 ;
     RECT  18.469 94.656 18.608 96.888 ;
     RECT  18.277 98.064 18.608 99.816 ;
     RECT  18.313 100.8 18.608 103.608 ;
     RECT  18.608 0.096 18.904 103.608 ;
     RECT  18.904 92.304 19.043 92.904 ;
     RECT  19.043 92.784 19.109 92.904 ;
     RECT  19.109 92.784 19.139 92.808 ;
     RECT  18.904 17.184 19.235 19.272 ;
     RECT  18.904 98.064 19.235 103.608 ;
     RECT  18.904 67.248 19.253 67.848 ;
     RECT  19.235 98.544 19.253 103.608 ;
     RECT  18.904 73.776 19.361 74.76 ;
     RECT  18.904 79.824 19.379 79.848 ;
     RECT  18.904 6.72 19.397 7.464 ;
     RECT  18.904 44.832 19.427 45.576 ;
     RECT  18.904 46.848 19.433 65.784 ;
     RECT  19.433 46.848 19.469 65.256 ;
     RECT  18.904 9.12 19.513 9.144 ;
     RECT  19.361 73.776 19.541 74.712 ;
     RECT  18.904 89.856 19.564 90.648 ;
     RECT  18.904 82.608 19.571 83.16 ;
     RECT  18.904 71.088 19.585 72.408 ;
     RECT  19.253 98.544 19.693 100.344 ;
     RECT  19.397 6.816 19.715 7.464 ;
     RECT  18.904 84.288 19.757 85.272 ;
     RECT  19.715 6.816 19.811 6.84 ;
     RECT  18.904 35.904 19.865 35.928 ;
     RECT  18.904 95.376 19.865 95.4 ;
     RECT  19.571 83.136 19.897 83.16 ;
     RECT  18.904 78.048 19.937 78.648 ;
     RECT  19.897 83.136 19.937 83.256 ;
     RECT  19.757 84.96 19.937 85.272 ;
     RECT  19.937 83.232 19.981 83.256 ;
     RECT  19.585 71.088 20.041 71.592 ;
     RECT  19.253 101.472 20.117 103.608 ;
     RECT  19.469 52.176 20.153 65.256 ;
     RECT  19.469 46.848 20.185 51.192 ;
     RECT  19.693 98.544 20.195 100.296 ;
     RECT  20.041 70.944 20.225 71.592 ;
     RECT  20.149 82.128 20.236 82.152 ;
     RECT  20.195 98.544 20.252 100.248 ;
     RECT  19.427 44.832 20.291 45.048 ;
     RECT  20.245 43.152 20.332 43.176 ;
     RECT  20.291 44.928 20.339 45.048 ;
     RECT  20.185 46.176 20.339 51.192 ;
     RECT  20.339 46.704 20.428 51.192 ;
     RECT  20.153 52.176 20.483 64.92 ;
     RECT  20.428 46.704 20.513 47.112 ;
     RECT  19.541 73.776 20.54 74.136 ;
     RECT  20.225 71.088 20.581 71.592 ;
     RECT  20.483 52.176 20.621 64.344 ;
     RECT  20.54 73.776 20.627 74.904 ;
     RECT  18.904 0.096 20.689 5.256 ;
     RECT  20.005 78.672 20.689 78.696 ;
     RECT  20.339 45.024 20.693 45.048 ;
     RECT  20.581 71.088 20.693 71.832 ;
     RECT  20.627 73.776 20.729 74.712 ;
     RECT  19.253 67.248 20.797 67.8 ;
     RECT  20.252 98.496 20.837 100.248 ;
     RECT  20.725 94.8 20.861 94.824 ;
     RECT  20.689 78.672 20.867 79.272 ;
     RECT  19.564 90.624 20.905 90.648 ;
     RECT  20.797 86.64 20.909 86.664 ;
     RECT  20.861 94.56 20.915 94.824 ;
     RECT  20.915 94.56 20.945 94.584 ;
     RECT  20.869 72.288 20.956 72.312 ;
     RECT  20.941 70.08 21.025 70.104 ;
     RECT  20.797 67.248 21.053 68.376 ;
     RECT  20.905 90.624 21.053 90.744 ;
     RECT  20.689 96.336 21.059 96.36 ;
     RECT  20.428 48.144 21.085 51.192 ;
     RECT  20.621 52.176 21.085 64.056 ;
     RECT  21.053 90.624 21.089 90.648 ;
     RECT  20.117 101.472 21.109 103.56 ;
     RECT  21.068 66.672 21.155 66.696 ;
     RECT  21.085 48.144 21.203 64.056 ;
     RECT  21.157 96.864 21.269 96.888 ;
     RECT  21.193 94.032 21.277 94.248 ;
     RECT  20.837 98.64 21.301 100.248 ;
     RECT  21.109 101.376 21.301 103.56 ;
     RECT  21.053 67.776 21.377 68.376 ;
     RECT  21.301 82.128 21.388 82.152 ;
     RECT  20.689 0.048 21.395 5.256 ;
     RECT  21.395 0.048 21.443 1.704 ;
     RECT  20.513 46.704 21.449 46.872 ;
     RECT  21.193 90.48 21.485 90.504 ;
     RECT  20.729 73.776 21.493 73.8 ;
     RECT  19.937 84.96 21.557 84.984 ;
     RECT  21.493 46.416 21.58 46.44 ;
     RECT  21.301 98.64 21.593 103.56 ;
     RECT  21.049 78.624 21.661 78.648 ;
     RECT  21.593 101.472 21.673 103.56 ;
     RECT  21.277 94.224 21.683 94.248 ;
     RECT  21.203 48.144 21.701 51.144 ;
     RECT  21.253 75.888 21.725 75.912 ;
     RECT  21.203 52.272 21.737 64.056 ;
     RECT  21.725 75.792 21.809 75.912 ;
     RECT  21.395 2.88 21.841 5.256 ;
     RECT  21.829 44.304 21.917 44.328 ;
     RECT  21.877 42.144 21.964 42.168 ;
     RECT  21.637 68.448 22.025 68.472 ;
     RECT  21.593 98.64 22.129 100.296 ;
     RECT  21.493 72.96 22.201 73.8 ;
     RECT  22.124 30.768 22.211 30.792 ;
     RECT  21.733 70.032 22.211 70.056 ;
     RECT  22.124 88.896 22.211 88.92 ;
     RECT  22.213 76.704 22.229 76.728 ;
     RECT  21.661 78.24 22.229 78.648 ;
     RECT  22.129 98.064 22.273 100.296 ;
     RECT  22.229 76.704 22.313 78.648 ;
     RECT  22.057 44.976 22.355 45 ;
     RECT  22.273 97.44 22.357 100.296 ;
     RECT  22.261 89.28 22.421 89.304 ;
     RECT  22.201 72.96 22.453 74.424 ;
     RECT  22.381 43.296 22.465 43.32 ;
     RECT  22.412 95.52 22.499 95.544 ;
     RECT  22.453 89.472 22.573 89.592 ;
     RECT  22.453 72.96 22.597 75.24 ;
     RECT  22.357 98.352 22.669 100.296 ;
     RECT  21.673 101.472 22.669 103.464 ;
     RECT  22.597 72.288 22.673 75.24 ;
     RECT  22.573 89.568 22.673 89.592 ;
     RECT  22.673 72.288 22.684 74.424 ;
     RECT  22.525 94.656 22.709 94.68 ;
     RECT  21.841 2.88 22.741 5.64 ;
     RECT  22.7 85.776 22.787 85.8 ;
     RECT  21.443 0.048 22.813 1.272 ;
     RECT  21.701 48.192 22.813 51.144 ;
     RECT  22.669 82.608 22.817 82.632 ;
     RECT  22.669 98.352 22.837 103.464 ;
     RECT  22.789 65.04 22.876 65.064 ;
     RECT  22.813 48.144 22.892 51.144 ;
     RECT  22.313 78.096 22.921 78.648 ;
     RECT  22.741 2.832 22.957 5.64 ;
     RECT  22.892 47.712 22.979 51.144 ;
     RECT  22.957 2.832 22.993 5.688 ;
     RECT  22.813 0.048 23.173 1.656 ;
     RECT  22.993 2.784 23.173 5.688 ;
     RECT  22.525 69.312 23.353 69.336 ;
     RECT  20.693 71.088 23.353 71.112 ;
     RECT  23.353 69.312 23.365 71.112 ;
     RECT  23.365 68.4 23.42 71.112 ;
     RECT  21.737 52.272 23.497 63.576 ;
     RECT  23.461 91.152 23.605 91.176 ;
     RECT  23.468 96.816 23.677 96.84 ;
     RECT  23.173 0.048 23.789 5.688 ;
     RECT  23.353 93.504 23.852 93.528 ;
     RECT  23.557 45.456 23.857 45.48 ;
     RECT  22.837 98.352 23.893 103.512 ;
     RECT  23.789 0.144 24.008 5.688 ;
     RECT  18.904 11.952 24.008 11.976 ;
     RECT  19.235 17.616 24.008 19.272 ;
     RECT  18.904 21.984 24.008 23.064 ;
     RECT  18.904 24.384 24.008 24.408 ;
     RECT  18.904 26.304 24.008 26.328 ;
     RECT  23.077 28.992 24.008 29.016 ;
     RECT  18.904 37.872 24.008 37.896 ;
     RECT  23.245 42.672 24.008 42.888 ;
     RECT  23.857 44.496 24.008 45.48 ;
     RECT  22.979 48.288 24.008 51.144 ;
     RECT  23.497 52.272 24.008 64.152 ;
     RECT  23.42 68.256 24.008 71.112 ;
     RECT  22.684 72.96 24.008 74.424 ;
     RECT  23.093 75.648 24.008 75.816 ;
     RECT  22.921 78.096 24.008 78.696 ;
     RECT  23.756 80.928 24.008 80.952 ;
     RECT  23.929 82.416 24.008 82.44 ;
     RECT  22.885 83.76 24.008 83.784 ;
     RECT  23.036 87.792 24.008 87.816 ;
     RECT  23.605 90.624 24.008 91.176 ;
     RECT  23.852 92.832 24.008 93.528 ;
     RECT  23.677 96.816 24.008 97.032 ;
     RECT  23.893 98.112 24.008 103.512 ;
     RECT  24.008 0.144 24.275 103.512 ;
     RECT  24.275 2.256 24.304 103.512 ;
     RECT  24.275 0.144 24.374 1.128 ;
     RECT  24.304 2.256 24.401 4.728 ;
     RECT  24.304 46.08 24.401 46.104 ;
     RECT  24.304 41.04 24.419 41.688 ;
     RECT  24.304 49.248 24.419 49.272 ;
     RECT  24.304 70.224 24.419 71.88 ;
     RECT  24.304 72.96 24.419 76.392 ;
     RECT  24.419 70.608 24.437 71.112 ;
     RECT  24.419 72.96 24.473 72.984 ;
     RECT  24.304 84.96 24.473 84.984 ;
     RECT  24.304 82.608 24.481 83.784 ;
     RECT  24.481 82.608 24.509 82.68 ;
     RECT  24.304 7.392 24.515 7.416 ;
     RECT  24.304 50.304 24.515 64.344 ;
     RECT  24.419 74.4 24.515 76.392 ;
     RECT  24.401 2.832 24.545 4.728 ;
     RECT  24.304 81.216 24.611 81.24 ;
     RECT  24.304 96.816 24.617 103.512 ;
     RECT  24.437 70.656 24.652 71.112 ;
     RECT  24.617 96.816 24.652 96.936 ;
     RECT  24.515 50.544 24.653 64.344 ;
     RECT  24.304 78.096 24.659 79.8 ;
     RECT  24.653 50.544 24.689 64.152 ;
     RECT  24.515 74.4 24.689 75.384 ;
     RECT  24.304 89.472 24.689 91.176 ;
     RECT  24.419 41.04 24.697 41.064 ;
     RECT  24.304 68.928 24.7 68.952 ;
     RECT  24.617 98.016 24.755 103.512 ;
     RECT  24.689 50.544 24.761 63.96 ;
     RECT  24.304 94.512 24.796 94.536 ;
     RECT  24.761 50.592 24.833 63.96 ;
     RECT  24.304 93.504 24.869 93.528 ;
     RECT  24.689 89.472 24.899 89.496 ;
     RECT  24.304 23.04 24.941 23.064 ;
     RECT  24.509 82.656 24.941 82.68 ;
     RECT  24.689 90.72 24.941 91.176 ;
     RECT  24.659 79.776 24.947 79.8 ;
     RECT  24.941 90.72 25.013 90.744 ;
     RECT  24.515 76.368 25.043 76.392 ;
     RECT  24.833 50.928 25.085 63.96 ;
     RECT  24.659 78.672 25.085 78.696 ;
     RECT  24.545 2.832 25.091 4.008 ;
     RECT  24.304 87.792 25.139 87.816 ;
     RECT  24.304 47.808 25.165 47.832 ;
     RECT  24.304 24.384 25.229 24.408 ;
     RECT  24.374 0.192 25.261 1.128 ;
     RECT  25.091 2.832 25.283 3.624 ;
     RECT  24.304 67.728 25.324 67.752 ;
     RECT  24.304 31.344 25.379 31.368 ;
     RECT  25.261 0.192 25.397 1.704 ;
     RECT  25.085 51.936 25.409 63.96 ;
     RECT  25.333 76.944 25.445 76.968 ;
     RECT  24.652 96.912 25.553 96.936 ;
     RECT  24.652 71.088 25.573 71.112 ;
     RECT  25.573 71.088 25.621 71.88 ;
     RECT  24.755 98.016 25.628 101.544 ;
     RECT  25.621 71.088 25.661 72.168 ;
     RECT  24.689 75.36 25.667 75.384 ;
     RECT  24.304 17.616 25.697 19.272 ;
     RECT  25.661 72.144 25.705 72.168 ;
     RECT  25.621 88.32 25.708 88.344 ;
     RECT  25.628 97.92 25.715 101.544 ;
     RECT  25.715 97.92 25.729 101.496 ;
     RECT  25.405 86.64 25.772 86.664 ;
     RECT  25.409 51.936 25.805 53.4 ;
     RECT  25.297 7.968 25.859 7.992 ;
     RECT  25.772 86.592 25.859 86.664 ;
     RECT  24.755 102.528 25.868 103.512 ;
     RECT  25.661 71.088 25.945 71.112 ;
     RECT  25.859 86.64 25.949 86.664 ;
     RECT  25.868 102.528 25.955 103.56 ;
     RECT  25.397 0.144 25.957 1.704 ;
     RECT  25.873 47.088 25.985 47.112 ;
     RECT  25.283 3.408 26.053 3.624 ;
     RECT  24.304 26.304 26.053 26.328 ;
     RECT  26.005 68.256 26.093 68.28 ;
     RECT  25.657 82.704 26.093 82.728 ;
     RECT  25.729 97.392 26.099 101.496 ;
     RECT  25.085 50.928 26.108 50.952 ;
     RECT  26.053 81.456 26.125 81.48 ;
     RECT  25.805 52.704 26.129 53.4 ;
     RECT  26.053 44.208 26.14 44.232 ;
     RECT  26.053 45.936 26.14 45.96 ;
     RECT  26.125 80.928 26.14 81.48 ;
     RECT  25.957 0.144 26.165 2.328 ;
     RECT  24.481 83.76 26.193 83.784 ;
     RECT  25.945 94.032 26.197 94.056 ;
     RECT  26.053 26.304 26.201 26.808 ;
     RECT  26.125 91.824 26.209 91.848 ;
     RECT  26.149 5.136 26.237 5.16 ;
     RECT  26.197 94.032 26.243 94.68 ;
     RECT  25.945 70.704 26.245 71.112 ;
     RECT  26.245 70.656 26.332 71.112 ;
     RECT  26.332 71.088 26.339 71.112 ;
     RECT  26.261 88.944 26.345 88.968 ;
     RECT  26.197 90.528 26.345 90.552 ;
     RECT  25.409 54.384 26.377 63.672 ;
     RECT  26.243 94.656 26.417 94.68 ;
     RECT  26.165 2.256 26.437 2.328 ;
     RECT  26.053 3.408 26.437 3.96 ;
     RECT  26.377 54.384 26.449 63.768 ;
     RECT  26.108 50.928 26.453 51.624 ;
     RECT  26.485 87.36 26.572 87.384 ;
     RECT  26.089 39.888 26.627 39.912 ;
     RECT  26.54 65.088 26.627 65.112 ;
     RECT  26.449 54.384 26.669 63.816 ;
     RECT  26.341 74.304 26.771 74.328 ;
     RECT  26.099 97.92 26.773 101.496 ;
     RECT  25.955 102.528 26.773 103.512 ;
     RECT  26.773 97.92 26.777 103.512 ;
     RECT  25.945 92.832 26.828 92.856 ;
     RECT  26.437 2.256 26.867 3.96 ;
     RECT  26.801 75.36 26.885 75.384 ;
     RECT  26.828 92.544 26.915 92.856 ;
     RECT  24.304 21.984 26.993 22.008 ;
     RECT  26.867 2.736 27.011 3.96 ;
     RECT  26.924 93.36 27.011 93.384 ;
     RECT  26.777 101.472 27.028 103.512 ;
     RECT  26.773 42.768 27.065 42.792 ;
     RECT  26.129 53.088 27.101 53.4 ;
     RECT  27.011 2.736 27.155 3.432 ;
     RECT  27.101 53.088 27.209 53.112 ;
     RECT  26.773 83.088 27.241 83.112 ;
     RECT  26.165 0.144 27.245 1.224 ;
     RECT  27.241 83.088 27.281 83.208 ;
     RECT  26.989 65.568 27.347 65.592 ;
     RECT  27.281 83.184 27.347 83.208 ;
     RECT  27.133 47.328 27.349 47.352 ;
     RECT  26.809 96.864 27.349 96.888 ;
     RECT  27.349 46.992 27.385 47.352 ;
     RECT  27.253 41.616 27.389 41.64 ;
     RECT  26.377 36.48 27.433 36.504 ;
     RECT  27.349 96.864 27.452 96.936 ;
     RECT  26.777 97.92 27.452 99.768 ;
     RECT  27.413 45.6 27.497 45.624 ;
     RECT  27.445 88.896 27.533 88.92 ;
     RECT  27.452 93.84 27.539 93.864 ;
     RECT  27.457 74.64 27.569 74.664 ;
     RECT  27.5 69.936 27.587 69.96 ;
     RECT  26.201 26.304 27.605 26.328 ;
     RECT  27.493 86.064 27.635 86.088 ;
     RECT  26.14 80.928 27.641 80.952 ;
     RECT  27.589 45.312 27.676 45.336 ;
     RECT  26.669 54.384 27.677 63.768 ;
     RECT  27.313 92.352 27.683 92.376 ;
     RECT  27.452 96.864 27.733 99.768 ;
     RECT  27.028 101.472 27.788 103.56 ;
     RECT  27.733 44.928 27.821 44.952 ;
     RECT  27.385 46.992 27.857 47.88 ;
     RECT  27.745 70.704 27.857 70.728 ;
     RECT  27.788 100.848 27.865 103.56 ;
     RECT  27.733 96.336 27.925 99.768 ;
     RECT  27.865 100.848 27.925 101.544 ;
     RECT  26.453 50.928 27.929 50.952 ;
     RECT  27.877 52.704 27.964 52.728 ;
     RECT  27.973 88.608 28.06 88.632 ;
     RECT  27.925 96.336 28.069 101.544 ;
     RECT  24.304 37.872 28.073 37.896 ;
     RECT  26.881 72.864 28.109 72.888 ;
     RECT  27.155 2.736 28.205 2.856 ;
     RECT  28.069 3.936 28.211 3.96 ;
     RECT  28.124 80.304 28.211 80.328 ;
     RECT  28.069 95.76 28.211 101.544 ;
     RECT  27.865 102.576 28.259 103.56 ;
     RECT  28.205 2.736 28.289 2.904 ;
     RECT  28.211 95.76 28.289 95.784 ;
     RECT  28.277 42.192 28.361 42.216 ;
     RECT  28.277 89.952 28.361 89.976 ;
     RECT  27.245 0.144 28.501 0.6 ;
     RECT  28.46 84.288 28.501 84.312 ;
     RECT  26.917 49.584 28.537 49.608 ;
     RECT  28.537 49.44 28.549 49.608 ;
     RECT  27.857 47.856 28.573 47.88 ;
     RECT  28.549 48.96 28.573 49.608 ;
     RECT  28.501 0.144 28.681 1.032 ;
     RECT  28.501 74.304 28.748 74.328 ;
     RECT  28.681 0.144 28.753 1.128 ;
     RECT  28.289 2.736 28.753 2.76 ;
     RECT  28.573 47.856 28.825 49.608 ;
     RECT  28.249 37.632 28.853 37.656 ;
     RECT  28.892 92.832 28.933 92.856 ;
     RECT  28.556 70.224 28.969 70.248 ;
     RECT  28.748 74.304 28.969 75 ;
     RECT  28.933 92.832 28.969 93.144 ;
     RECT  28.94 66.192 29.005 66.216 ;
     RECT  29.005 66.048 29.077 66.216 ;
     RECT  28.969 70.224 29.077 70.344 ;
     RECT  27.349 87.264 29.077 87.288 ;
     RECT  28.211 96.912 29.077 101.544 ;
     RECT  28.259 102.576 29.077 103.32 ;
     RECT  28.825 47.328 29.125 49.608 ;
     RECT  28.741 52.56 29.173 52.584 ;
     RECT  28.501 83.76 29.221 84.312 ;
     RECT  29.077 96.912 29.221 103.32 ;
     RECT  29.077 64.944 29.257 66.216 ;
     RECT  28.645 67.296 29.257 67.32 ;
     RECT  28.753 0.144 29.267 2.76 ;
     RECT  28.969 74.304 29.269 75.864 ;
     RECT  29.149 94.56 29.269 94.584 ;
     RECT  29.267 1.968 29.408 2.76 ;
     RECT  29.141 4.56 29.408 4.584 ;
     RECT  28.493 7.968 29.408 7.992 ;
     RECT  24.304 11.952 29.408 11.976 ;
     RECT  25.697 17.616 29.408 18.456 ;
     RECT  28.853 37.056 29.408 37.656 ;
     RECT  28.861 42.768 29.408 42.792 ;
     RECT  29.149 44.448 29.408 44.472 ;
     RECT  29.125 46.896 29.408 49.608 ;
     RECT  29.173 52.032 29.408 52.584 ;
     RECT  27.677 54.384 29.408 63.672 ;
     RECT  29.257 64.944 29.408 67.32 ;
     RECT  28.645 68.352 29.408 68.376 ;
     RECT  29.077 70.224 29.408 70.44 ;
     RECT  29.269 74.304 29.408 76.056 ;
     RECT  29.221 83.76 29.408 85.08 ;
     RECT  29.077 86.64 29.408 87.288 ;
     RECT  28.429 90.144 29.408 90.168 ;
     RECT  28.969 92.16 29.408 93.144 ;
     RECT  29.269 94.56 29.408 95.208 ;
     RECT  29.221 96.768 29.408 103.32 ;
     RECT  29.408 1.968 29.704 103.32 ;
     RECT  29.704 56.064 29.801 63.672 ;
     RECT  29.704 12.528 29.843 12.552 ;
     RECT  29.801 56.208 29.873 63.672 ;
     RECT  29.704 14.784 29.917 15.384 ;
     RECT  29.704 79.728 29.939 79.752 ;
     RECT  29.704 91.824 29.945 95.448 ;
     RECT  29.267 0.144 30.013 0.744 ;
     RECT  29.945 91.824 30.028 93.768 ;
     RECT  29.704 3.36 30.035 3.96 ;
     RECT  29.704 73.392 30.076 73.416 ;
     RECT  30.035 3.36 30.083 3.384 ;
     RECT  29.704 72 30.089 72.024 ;
     RECT  29.704 97.824 30.113 103.32 ;
     RECT  30.013 0.096 30.131 0.744 ;
     RECT  29.873 56.304 30.131 63.672 ;
     RECT  29.917 15.36 30.133 15.384 ;
     RECT  29.704 31.344 30.179 31.368 ;
     RECT  29.704 81.456 30.179 81.48 ;
     RECT  29.704 90.048 30.179 90.12 ;
     RECT  30.113 97.824 30.197 103.56 ;
     RECT  29.704 83.76 30.227 84.504 ;
     RECT  29.704 88.32 30.233 88.344 ;
     RECT  30.028 91.824 30.241 92.952 ;
     RECT  29.704 10.848 30.305 10.872 ;
     RECT  29.704 64.848 30.305 67.272 ;
     RECT  29.704 86.736 30.413 86.76 ;
     RECT  30.197 97.824 30.413 103.512 ;
     RECT  30.179 90.096 30.46 90.12 ;
     RECT  30.131 0.144 30.481 0.744 ;
     RECT  30.325 1.728 30.481 1.8 ;
     RECT  30.305 64.848 30.485 66.696 ;
     RECT  29.704 36.48 30.521 36.504 ;
     RECT  30.241 91.824 30.529 92.376 ;
     RECT  29.704 23.328 30.565 23.352 ;
     RECT  29.704 6.24 30.611 6.888 ;
     RECT  29.704 78.672 30.629 78.696 ;
     RECT  30.529 92.352 30.629 92.376 ;
     RECT  30.485 64.848 30.659 65.784 ;
     RECT  29.704 54.384 30.665 54.408 ;
     RECT  30.413 100.848 30.665 103.512 ;
     RECT  30.413 97.824 30.709 99.72 ;
     RECT  30.481 0.144 30.737 1.8 ;
     RECT  30.611 6.864 30.737 6.888 ;
     RECT  30.659 64.944 30.737 65.784 ;
     RECT  29.704 82.656 30.797 82.68 ;
     RECT  30.665 100.848 30.803 103.464 ;
     RECT  30.709 97.68 30.805 99.72 ;
     RECT  29.704 50.688 30.844 50.712 ;
     RECT  30.797 82.656 30.881 82.968 ;
     RECT  30.227 84.384 30.881 84.408 ;
     RECT  30.805 96.576 30.892 99.72 ;
     RECT  30.737 0.144 30.899 1.128 ;
     RECT  30.803 100.848 30.989 103.416 ;
     RECT  30.805 2.256 30.995 2.28 ;
     RECT  30.908 21.792 30.995 21.816 ;
     RECT  30.131 56.352 30.995 63.672 ;
     RECT  30.899 0.144 31.043 1.08 ;
     RECT  30.956 86.592 31.043 86.616 ;
     RECT  30.805 73.584 31.052 73.608 ;
     RECT  29.704 74.688 31.052 75.24 ;
     RECT  30.805 79.824 31.052 79.848 ;
     RECT  30.997 78 31.084 78.024 ;
     RECT  31.052 73.584 31.097 75.24 ;
     RECT  31.097 74.544 31.139 75.24 ;
     RECT  31.052 79.824 31.139 80.328 ;
     RECT  30.737 65.76 31.205 65.784 ;
     RECT  31.121 73.488 31.205 73.512 ;
     RECT  30.892 96.768 31.205 99.72 ;
     RECT  31.148 94.08 31.235 94.104 ;
     RECT  30.995 57.552 31.283 63.672 ;
     RECT  29.945 95.136 31.301 95.448 ;
     RECT  31.129 76.368 31.333 76.392 ;
     RECT  30.995 56.352 31.349 56.52 ;
     RECT  31.301 95.136 31.385 95.736 ;
     RECT  31.381 47.328 31.465 47.352 ;
     RECT  31.205 96.864 31.477 99.72 ;
     RECT  31.385 95.136 31.489 95.304 ;
     RECT  31.333 75.36 31.493 76.392 ;
     RECT  31.493 75.36 31.523 75.912 ;
     RECT  31.139 79.824 31.525 80.184 ;
     RECT  31.489 94.56 31.565 95.304 ;
     RECT  31.525 79.2 31.571 80.184 ;
     RECT  31.523 75.888 31.601 75.912 ;
     RECT  31.561 72.576 31.645 72.936 ;
     RECT  31.645 72.912 31.667 72.936 ;
     RECT  31.561 42.096 31.705 42.12 ;
     RECT  31.669 70.128 31.753 70.152 ;
     RECT  31.565 94.56 31.781 94.776 ;
     RECT  31.283 57.6 31.811 63.672 ;
     RECT  31.705 42.096 31.813 42.168 ;
     RECT  31.573 53.76 31.853 53.784 ;
     RECT  31.777 86.016 31.861 86.04 ;
     RECT  31.705 51.984 31.889 52.008 ;
     RECT  31.781 94.56 31.889 94.584 ;
     RECT  31.477 96.864 31.907 99.768 ;
     RECT  31.057 81.984 31.909 82.008 ;
     RECT  31.811 57.648 31.957 63.672 ;
     RECT  31.777 64.848 31.957 64.872 ;
     RECT  30.989 101.184 31.957 103.416 ;
     RECT  31.877 39.888 31.961 39.912 ;
     RECT  31.669 46.128 32.065 46.152 ;
     RECT  31.909 81.6 32.065 82.008 ;
     RECT  31.717 17.472 32.069 17.496 ;
     RECT  32.065 81.6 32.069 82.584 ;
     RECT  31.813 42.096 32.137 42.744 ;
     RECT  32.065 46.08 32.149 46.152 ;
     RECT  32.101 68.976 32.156 69 ;
     RECT  32.053 1.728 32.177 1.752 ;
     RECT  32.069 81.984 32.197 82.584 ;
     RECT  32.156 68.256 32.213 69 ;
     RECT  32.197 81.984 32.213 83.16 ;
     RECT  32.137 42.096 32.221 43.368 ;
     RECT  32.213 68.256 32.243 68.952 ;
     RECT  32.149 46.128 32.245 46.152 ;
     RECT  30.853 44.448 32.249 44.472 ;
     RECT  32.065 4.512 32.291 4.536 ;
     RECT  32.221 42.096 32.291 42.744 ;
     RECT  31.043 0.144 32.293 0.6 ;
     RECT  31.957 101.184 32.317 103.512 ;
     RECT  32.197 73.728 32.321 73.752 ;
     RECT  32.237 80.928 32.321 80.952 ;
     RECT  32.213 83.136 32.339 83.16 ;
     RECT  31.907 97.68 32.341 99.768 ;
     RECT  32.317 101.184 32.341 103.56 ;
     RECT  31.957 57.648 32.417 64.872 ;
     RECT  32.341 84.864 32.428 84.888 ;
     RECT  32.245 46.128 32.429 46.728 ;
     RECT  32.341 97.68 32.429 103.56 ;
     RECT  32.348 22.08 32.435 22.104 ;
     RECT  32.429 98.208 32.476 103.56 ;
     RECT  32.389 3.984 32.501 4.008 ;
     RECT  31.525 40.992 32.501 41.016 ;
     RECT  32.429 46.704 32.501 46.728 ;
     RECT  32.417 57.648 32.501 65.016 ;
     RECT  32.501 57.648 32.537 64.344 ;
     RECT  32.533 96.24 32.62 96.36 ;
     RECT  32.629 2.88 32.677 2.904 ;
     RECT  32.569 90.624 32.681 90.648 ;
     RECT  32.677 2.304 32.717 2.904 ;
     RECT  32.636 91.776 32.723 91.8 ;
     RECT  32.684 65.904 32.771 65.928 ;
     RECT  32.677 10.8 32.789 10.824 ;
     RECT  32.749 30.72 32.833 30.744 ;
     RECT  32.785 73.536 32.869 73.56 ;
     RECT  32.717 2.304 32.897 2.328 ;
     RECT  31.093 38.736 32.897 38.76 ;
     RECT  32.773 89.136 32.897 89.16 ;
     RECT  31.571 79.2 33.041 79.224 ;
     RECT  32.173 67.248 33.061 67.272 ;
     RECT  32.993 72.24 33.061 72.264 ;
     RECT  31.349 56.352 33.077 56.376 ;
     RECT  33.061 72.24 33.077 72.936 ;
     RECT  32.476 98.256 33.107 103.56 ;
     RECT  33.013 31.344 33.113 31.368 ;
     RECT  33.029 33.648 33.113 33.672 ;
     RECT  32.533 41.808 33.113 41.832 ;
     RECT  32.537 58.464 33.149 64.344 ;
     RECT  33.068 3.696 33.155 3.72 ;
     RECT  32.917 29.376 33.185 29.4 ;
     RECT  33.061 66.72 33.203 67.272 ;
     RECT  33.077 72.912 33.203 72.936 ;
     RECT  32.213 81.984 33.221 82.056 ;
     RECT  32.869 50.688 33.253 50.712 ;
     RECT  33.149 59.808 33.257 64.344 ;
     RECT  33.181 76.368 33.265 76.392 ;
     RECT  33.205 5.136 33.293 5.16 ;
     RECT  32.62 96.336 33.325 96.36 ;
     RECT  33.253 50.688 33.337 50.76 ;
     RECT  33.253 82.608 33.361 82.632 ;
     RECT  33.461 74.688 33.5 74.712 ;
     RECT  33.107 103.008 33.532 103.56 ;
     RECT  33.361 82.608 33.577 82.68 ;
     RECT  32.243 68.928 33.581 68.952 ;
     RECT  33.5 74.496 33.587 74.712 ;
     RECT  33.5 92.16 33.587 92.184 ;
     RECT  33.107 98.256 33.589 102.024 ;
     RECT  33.325 96.336 33.596 96.936 ;
     RECT  33.541 88.368 33.635 88.392 ;
     RECT  33.532 103.2 33.635 103.56 ;
     RECT  32.821 52.992 33.649 53.016 ;
     RECT  30.997 37.008 33.653 37.032 ;
     RECT  33.596 96.048 33.683 96.936 ;
     RECT  33.649 52.752 33.685 53.016 ;
     RECT  32.093 77.52 33.721 77.544 ;
     RECT  33.685 86.64 33.721 86.664 ;
     RECT  32.437 7.44 33.725 7.464 ;
     RECT  33.644 93.648 33.731 93.672 ;
     RECT  33.577 82.608 33.793 82.824 ;
     RECT  33.257 59.808 33.827 64.2 ;
     RECT  33.721 76.944 33.827 77.544 ;
     RECT  33.685 52.752 33.833 53.544 ;
     RECT  32.893 84.24 33.833 84.264 ;
     RECT  33.827 77.28 33.857 77.544 ;
     RECT  33.683 96.288 33.865 96.936 ;
     RECT  33.589 98.256 33.865 101.832 ;
     RECT  32.293 0.144 33.868 1.176 ;
     RECT  33.857 77.28 33.901 78.12 ;
     RECT  33.721 86.64 33.937 86.808 ;
     RECT  33.781 88.08 33.937 88.104 ;
     RECT  33.109 39.84 33.973 39.864 ;
     RECT  33.901 79.824 33.973 79.848 ;
     RECT  33.937 86.64 34.037 88.104 ;
     RECT  34.037 85.968 34.069 88.104 ;
     RECT  33.893 90.048 34.081 90.072 ;
     RECT  33.203 67.248 34.117 67.272 ;
     RECT  33.973 79.824 34.153 80.328 ;
     RECT  34.081 89.952 34.153 90.072 ;
     RECT  33.868 0.144 34.192 1.224 ;
     RECT  33.635 103.2 34.193 103.512 ;
     RECT  34.021 95.184 34.225 95.208 ;
     RECT  34.192 0.096 34.261 1.224 ;
     RECT  34.225 2.256 34.261 2.28 ;
     RECT  33.793 82.608 34.297 83.208 ;
     RECT  34.069 85.68 34.297 88.104 ;
     RECT  34.261 0.096 34.309 2.28 ;
     RECT  34.153 89.952 34.477 90.168 ;
     RECT  34.309 0.144 34.481 2.28 ;
     RECT  34.357 44.544 34.501 44.568 ;
     RECT  33.145 70.656 34.541 70.68 ;
     RECT  34.405 48.24 34.604 48.264 ;
     RECT  34.189 21.408 34.652 21.432 ;
     RECT  34.153 79.824 34.657 80.904 ;
     RECT  34.645 6.288 34.693 6.312 ;
     RECT  34.297 82.08 34.693 83.208 ;
     RECT  33.865 96.288 34.7 101.832 ;
     RECT  34.193 103.2 34.7 103.464 ;
     RECT  34.481 0.192 34.808 2.28 ;
     RECT  34.405 3.984 34.808 4.008 ;
     RECT  34.693 5.712 34.808 6.312 ;
     RECT  34.597 7.968 34.808 7.992 ;
     RECT  34.069 9.12 34.808 9.144 ;
     RECT  34.604 12.912 34.808 12.936 ;
     RECT  34.357 16.128 34.808 16.152 ;
     RECT  34.369 18.192 34.808 18.216 ;
     RECT  34.652 21.408 34.808 22.2 ;
     RECT  34.117 29.616 34.808 30.264 ;
     RECT  33.973 39.84 34.808 40.776 ;
     RECT  34.021 42.72 34.808 42.744 ;
     RECT  34.501 44.016 34.808 44.568 ;
     RECT  33.733 45.984 34.808 46.008 ;
     RECT  34.604 48.24 34.808 48.36 ;
     RECT  33.337 50.688 34.808 50.712 ;
     RECT  33.833 52.992 34.808 53.544 ;
     RECT  33.149 58.464 34.808 58.728 ;
     RECT  33.827 59.856 34.808 64.2 ;
     RECT  34.076 65.856 34.808 65.88 ;
     RECT  34.117 67.248 34.808 67.368 ;
     RECT  34.693 68.352 34.808 68.376 ;
     RECT  34.541 70.128 34.808 70.68 ;
     RECT  34.213 72.912 34.808 72.936 ;
     RECT  33.587 74.688 34.808 74.712 ;
     RECT  33.901 77.28 34.808 78.696 ;
     RECT  34.657 79.728 34.808 80.904 ;
     RECT  34.693 82.08 34.808 83.448 ;
     RECT  34.297 84.912 34.808 88.104 ;
     RECT  34.477 89.472 34.808 90.168 ;
     RECT  34.069 92.928 34.808 93.528 ;
     RECT  34.225 95.136 34.808 95.208 ;
     RECT  34.7 96.288 34.808 103.464 ;
     RECT  34.808 0.192 35.075 103.464 ;
     RECT  35.075 0.192 35.104 102.024 ;
     RECT  35.104 34.656 35.165 34.776 ;
     RECT  35.104 58.464 35.165 58.728 ;
     RECT  35.104 92.928 35.201 93.384 ;
     RECT  35.104 75.696 35.219 80.136 ;
     RECT  35.104 85.824 35.219 87.096 ;
     RECT  35.104 91.44 35.219 91.464 ;
     RECT  35.201 93.024 35.219 93.384 ;
     RECT  35.165 34.656 35.237 34.728 ;
     RECT  35.104 96.288 35.245 97.656 ;
     RECT  35.104 27.36 35.267 29.016 ;
     RECT  35.219 75.84 35.267 76.44 ;
     RECT  35.104 88.656 35.267 88.968 ;
     RECT  35.104 25.2 35.273 25.224 ;
     RECT  35.267 27.36 35.281 27.384 ;
     RECT  35.104 67.728 35.309 69.288 ;
     RECT  35.104 5.232 35.315 5.256 ;
     RECT  35.104 8.448 35.315 8.808 ;
     RECT  35.104 22.848 35.315 22.872 ;
     RECT  35.104 45.984 35.315 46.104 ;
     RECT  35.267 76.416 35.315 76.44 ;
     RECT  35.219 93.12 35.315 93.384 ;
     RECT  35.104 98.928 35.315 100.296 ;
     RECT  35.075 103.104 35.315 103.464 ;
     RECT  35.104 0.192 35.345 2.328 ;
     RECT  35.315 103.2 35.356 103.464 ;
     RECT  35.104 14.832 35.363 14.856 ;
     RECT  35.237 34.704 35.363 34.728 ;
     RECT  35.104 49.872 35.363 50.136 ;
     RECT  35.315 99.168 35.363 100.296 ;
     RECT  35.315 8.544 35.381 8.712 ;
     RECT  35.267 28.512 35.381 29.016 ;
     RECT  35.104 101.376 35.389 102.024 ;
     RECT  35.381 8.544 35.404 8.568 ;
     RECT  35.363 99.168 35.417 100.2 ;
     RECT  35.356 103.248 35.441 103.464 ;
     RECT  35.315 93.12 35.453 93.144 ;
     RECT  35.104 81.504 35.459 82.152 ;
     RECT  35.345 2.208 35.507 2.328 ;
     RECT  35.104 3.408 35.633 3.432 ;
     RECT  35.104 60.864 35.651 63.672 ;
     RECT  35.219 85.824 35.699 86.904 ;
     RECT  35.104 94.56 35.741 94.584 ;
     RECT  35.309 67.728 35.747 69 ;
     RECT  35.104 72.576 35.747 74.328 ;
     RECT  35.345 0.192 35.749 1.224 ;
     RECT  35.104 54.72 35.795 56.136 ;
     RECT  35.104 90.048 35.813 90.072 ;
     RECT  35.104 26.208 35.857 26.232 ;
     RECT  35.267 88.944 35.885 88.968 ;
     RECT  35.245 96.912 35.893 97.656 ;
     RECT  35.219 78.096 35.932 80.136 ;
     RECT  35.893 96.912 35.932 96.936 ;
     RECT  35.104 31.92 35.957 31.944 ;
     RECT  35.932 80.112 35.957 80.136 ;
     RECT  35.651 61.2 35.993 63.672 ;
     RECT  35.747 72.576 35.993 73.56 ;
     RECT  35.699 86.016 36.029 86.904 ;
     RECT  35.363 49.872 36.035 49.896 ;
     RECT  35.459 81.504 36.073 81.528 ;
     RECT  35.993 72.576 36.076 72.984 ;
     RECT  35.104 16.656 36.083 16.68 ;
     RECT  35.381 28.512 36.101 28.536 ;
     RECT  35.932 78.096 36.109 78.648 ;
     RECT  35.165 58.704 36.131 58.728 ;
     RECT  35.104 66.672 36.131 66.696 ;
     RECT  35.747 68.352 36.131 69 ;
     RECT  36.076 72.72 36.131 72.984 ;
     RECT  36.109 78.48 36.131 78.648 ;
     RECT  35.417 99.168 36.131 99.816 ;
     RECT  35.104 52.464 36.133 52.584 ;
     RECT  35.104 71.472 36.173 71.496 ;
     RECT  36.133 52.464 36.179 52.968 ;
     RECT  35.993 61.584 36.179 63.672 ;
     RECT  35.507 2.304 36.197 2.328 ;
     RECT  35.795 54.72 36.245 55.416 ;
     RECT  36.131 72.96 36.245 72.984 ;
     RECT  36.131 78.48 36.245 78.504 ;
     RECT  36.188 58.128 36.275 58.152 ;
     RECT  36.197 2.304 36.281 2.904 ;
     RECT  36.245 55.248 36.323 55.416 ;
     RECT  36.029 86.016 36.361 86.088 ;
     RECT  36.323 55.248 36.364 55.272 ;
     RECT  35.441 103.248 36.371 103.512 ;
     RECT  36.097 98.016 36.397 98.04 ;
     RECT  36.131 99.168 36.421 99.768 ;
     RECT  36.179 62.208 36.425 63.672 ;
     RECT  36.371 103.344 36.461 103.512 ;
     RECT  36.38 82.848 36.467 82.872 ;
     RECT  36.413 10.272 36.497 10.296 ;
     RECT  36.425 62.256 36.605 63.672 ;
     RECT  36.661 30.192 36.749 30.216 ;
     RECT  36.421 99.072 36.757 99.768 ;
     RECT  36.179 52.944 36.781 52.968 ;
     RECT  36.781 34.512 36.853 34.536 ;
     RECT  36.781 52.944 36.893 53.016 ;
     RECT  36.853 33.6 36.937 34.536 ;
     RECT  36.937 34.512 36.995 34.536 ;
     RECT  36.461 103.392 37.025 103.512 ;
     RECT  36.613 76.704 37.037 76.728 ;
     RECT  36.605 62.448 37.109 63.672 ;
     RECT  37.105 50.736 37.217 50.76 ;
     RECT  36.131 68.352 37.237 68.376 ;
     RECT  35.389 101.472 37.237 102.024 ;
     RECT  37.177 28.464 37.261 28.488 ;
     RECT  37.237 67.728 37.324 68.376 ;
     RECT  37.141 7.44 37.325 7.464 ;
     RECT  36.889 32.352 37.475 32.376 ;
     RECT  37.388 77.136 37.475 77.16 ;
     RECT  36.893 52.992 37.523 53.016 ;
     RECT  37.069 91.008 37.523 91.032 ;
     RECT  37.237 100.8 37.532 102.024 ;
     RECT  37.025 103.392 37.532 103.56 ;
     RECT  37.324 68.352 37.541 68.376 ;
     RECT  37.465 88.944 37.549 88.968 ;
     RECT  37.477 57.168 37.564 57.192 ;
     RECT  36.281 2.304 37.577 2.328 ;
     RECT  37.501 70.752 37.585 70.776 ;
     RECT  37.429 94.992 37.613 95.016 ;
     RECT  37.381 96.864 37.613 96.888 ;
     RECT  37.532 100.8 37.613 103.56 ;
     RECT  37.477 54.72 37.619 54.744 ;
     RECT  37.477 58.224 37.619 58.248 ;
     RECT  37.501 84.336 37.619 84.36 ;
     RECT  37.525 46.752 37.649 46.776 ;
     RECT  37.109 62.784 37.649 63.672 ;
     RECT  36.361 86.016 37.649 86.04 ;
     RECT  36.757 98.64 37.657 99.768 ;
     RECT  37.649 62.976 37.669 63.672 ;
     RECT  37.669 62.976 37.681 63.768 ;
     RECT  37.609 82.8 37.693 82.824 ;
     RECT  37.628 29.04 37.715 29.064 ;
     RECT  37.621 61.632 37.793 61.656 ;
     RECT  37.613 100.8 37.813 101.496 ;
     RECT  37.657 98.64 37.82 99.192 ;
     RECT  37.333 35.328 37.865 35.352 ;
     RECT  37.745 75.264 37.897 75.288 ;
     RECT  37.813 100.656 37.901 101.496 ;
     RECT  37.681 62.976 37.907 64.248 ;
     RECT  37.82 97.92 37.907 99.192 ;
     RECT  37.861 79.248 37.973 79.272 ;
     RECT  37.907 98.64 37.973 99.192 ;
     RECT  37.907 63.024 38.045 64.248 ;
     RECT  35.749 0.144 38.081 1.224 ;
     RECT  38.045 63.024 38.081 63.528 ;
     RECT  38.081 63.12 38.099 63.528 ;
     RECT  38.041 79.824 38.125 79.848 ;
     RECT  37.973 98.64 38.147 99.048 ;
     RECT  38.099 63.168 38.153 63.528 ;
     RECT  38.147 98.64 38.153 98.856 ;
     RECT  38.053 97.392 38.189 97.464 ;
     RECT  38.081 0.24 38.195 1.224 ;
     RECT  37.897 75.216 38.197 75.288 ;
     RECT  38.149 86.544 38.233 86.568 ;
     RECT  38.197 75.216 38.243 75.672 ;
     RECT  38.195 0.24 38.261 0.36 ;
     RECT  38.189 97.44 38.297 97.464 ;
     RECT  38.261 0.24 38.441 0.264 ;
     RECT  38.243 75.648 38.441 75.672 ;
     RECT  38.153 63.168 38.585 63.192 ;
     RECT  38.197 91.056 38.657 91.08 ;
     RECT  38.581 78.48 38.668 78.504 ;
     RECT  37.901 100.656 38.693 100.68 ;
     RECT  37.897 94.704 38.725 94.728 ;
     RECT  38.689 90.048 38.761 90.072 ;
     RECT  38.617 82.656 38.765 82.68 ;
     RECT  38.545 80.736 38.771 80.76 ;
     RECT  38.725 94.608 38.771 94.728 ;
     RECT  38.197 61.584 38.837 61.608 ;
     RECT  38.771 94.608 38.837 94.632 ;
     RECT  38.761 90.048 38.845 90.984 ;
     RECT  38.153 98.64 38.873 98.664 ;
     RECT  37.613 102.576 38.945 103.56 ;
     RECT  38.845 90.048 38.972 90.072 ;
     RECT  38.972 89.904 39.017 90.072 ;
     RECT  38.965 69.984 39.053 70.008 ;
     RECT  39.017 89.904 39.059 89.928 ;
     RECT  39.013 87.792 39.205 87.816 ;
     RECT  38.945 102.576 39.377 102.6 ;
     RECT  39.397 66.72 40.208 66.744 ;
     RECT  39.553 72.816 40.208 72.84 ;
     RECT  39.829 74.592 40.208 74.616 ;
     RECT  39.308 75.84 40.208 75.864 ;
     RECT  39.349 77.184 40.208 77.208 ;
     RECT  39.805 78.672 40.208 78.696 ;
     RECT  39.869 79.68 40.208 79.704 ;
     RECT  38.773 82.128 40.208 82.152 ;
     RECT  38.617 85.44 40.208 85.464 ;
     RECT  39.205 87.504 40.208 87.816 ;
     RECT  40.208 2.148 40.312 100.992 ;
     RECT  40.312 2.418 40.4 100.992 ;
     RECT  40.4 2.418 40.504 101.262 ;
     RECT  45.608 2.148 45.712 100.992 ;
     RECT  45.712 2.418 45.8 100.992 ;
     RECT  45.8 2.418 45.904 101.262 ;
    LAYER M5 ;
     RECT  13.776 0.016 38.184 1.139 ;
     RECT  13.824 1.139 38.184 1.235 ;
     RECT  13.824 1.235 37.56 2.003 ;
     RECT  13.824 2.003 20.712 2.137 ;
     RECT  13.2 2.137 20.712 2.147 ;
     RECT  2.4 2.137 2.52 2.407 ;
     RECT  7.8 2.137 7.92 2.407 ;
     RECT  40.2 2.137 40.32 2.407 ;
     RECT  45.6 2.137 45.72 2.407 ;
     RECT  13.2 2.147 20.568 3.061 ;
     RECT  12.768 3.061 20.568 3.301 ;
     RECT  21.984 2.003 37.56 3.443 ;
     RECT  22.032 3.443 37.56 3.683 ;
     RECT  12.48 3.301 20.568 5.171 ;
     RECT  22.176 3.683 37.56 5.699 ;
     RECT  24 5.699 37.56 8.003 ;
     RECT  26.4 8.003 37.56 10.307 ;
     RECT  26.4 10.307 35.88 16.645 ;
     RECT  37.344 10.307 37.56 28.453 ;
     RECT  22.176 5.699 22.2 28.981 ;
     RECT  24 8.003 25.368 28.981 ;
     RECT  37.2 28.453 37.56 29.029 ;
     RECT  26.4 16.645 36.072 30.181 ;
     RECT  37.2 29.029 37.704 30.181 ;
     RECT  22.176 28.981 25.368 30.803 ;
     RECT  23.088 30.803 25.368 31.379 ;
     RECT  12.48 5.171 19.848 35.939 ;
     RECT  26.4 30.181 37.704 36.515 ;
     RECT  0.24 39.791 0.264 39.797 ;
     RECT  0.144 39.797 0.264 39.875 ;
     RECT  26.592 36.515 37.704 39.923 ;
     RECT  2.4 2.407 2.712 39.925 ;
     RECT  12.48 35.939 19.704 40.021 ;
     RECT  2.256 39.925 2.712 40.043 ;
     RECT  0.144 39.875 0.168 40.077 ;
     RECT  11.952 40.021 19.704 41.029 ;
     RECT  23.088 31.379 24.648 41.075 ;
     RECT  0.528 40.981 0.552 41.125 ;
     RECT  0.288 41.125 0.552 41.141 ;
     RECT  11.664 41.029 19.704 41.461 ;
     RECT  10.272 41.461 10.296 41.545 ;
     RECT  0.144 41.141 0.552 41.555 ;
     RECT  11.376 41.461 19.704 41.579 ;
     RECT  0.24 41.555 0.552 41.613 ;
     RECT  27.264 39.923 37.704 41.651 ;
     RECT  23.088 41.075 24.408 41.699 ;
     RECT  9.696 41.845 9.816 41.929 ;
     RECT  9.792 41.929 9.816 42.027 ;
     RECT  4.224 41.893 4.248 42.035 ;
     RECT  21.888 42.101 21.912 42.189 ;
     RECT  27.456 41.651 37.704 42.227 ;
     RECT  7.8 2.407 8.112 42.229 ;
     RECT  6.864 42.229 8.112 42.421 ;
     RECT  6.864 42.421 8.712 42.611 ;
     RECT  0.288 41.613 0.552 42.671 ;
     RECT  6.864 42.611 8.424 42.707 ;
     RECT  5.712 42.229 5.736 42.731 ;
     RECT  0.144 42.671 0.552 42.755 ;
     RECT  0.528 42.755 0.552 43.045 ;
     RECT  7.8 42.707 8.424 43.139 ;
     RECT  11.664 41.579 19.704 43.141 ;
     RECT  23.088 41.699 24.312 43.285 ;
     RECT  0.528 43.045 1.272 43.331 ;
     RECT  0.528 43.331 0.552 43.923 ;
     RECT  6.288 43.957 6.312 44.149 ;
     RECT  22.416 43.285 24.312 44.277 ;
     RECT  21.84 44.277 24.312 44.365 ;
     RECT  6.288 44.149 6.408 44.425 ;
     RECT  7.8 43.139 8.112 44.437 ;
     RECT  6.864 44.437 8.112 44.579 ;
     RECT  0.144 43.923 0.552 44.639 ;
     RECT  0.144 44.639 0.696 44.677 ;
     RECT  0.144 44.677 1.176 44.715 ;
     RECT  2.4 40.043 2.712 44.821 ;
     RECT  0.528 44.715 1.176 44.867 ;
     RECT  27.456 42.227 27.48 44.883 ;
     RECT  11.664 43.141 20.28 44.917 ;
     RECT  2.304 44.821 2.712 44.963 ;
     RECT  27.456 44.883 27.768 44.971 ;
     RECT  4.704 45.253 4.728 45.539 ;
     RECT  27.456 44.971 27.624 45.635 ;
     RECT  26.064 44.197 26.088 45.971 ;
     RECT  0.528 44.867 0.552 46.021 ;
     RECT  11.664 44.917 20.328 46.211 ;
     RECT  22.32 44.365 24.312 46.405 ;
     RECT  0.288 46.021 0.552 46.693 ;
     RECT  21.504 46.405 24.312 46.693 ;
     RECT  0.144 46.693 0.552 46.827 ;
     RECT  6.288 46.773 6.312 46.883 ;
     RECT  2.4 44.963 2.712 46.885 ;
     RECT  2.4 46.885 3.576 47.083 ;
     RECT  2.4 47.083 2.712 47.157 ;
     RECT  5.712 47.029 5.736 47.211 ;
     RECT  1.728 47.157 2.712 47.245 ;
     RECT  0.192 46.827 0.552 47.275 ;
     RECT  27.6 45.635 27.624 47.285 ;
     RECT  0.288 47.275 0.552 47.315 ;
     RECT  28.848 42.227 37.704 47.363 ;
     RECT  27.36 47.285 27.624 47.373 ;
     RECT  11.664 46.211 19.704 47.541 ;
     RECT  20.688 46.693 24.312 47.541 ;
     RECT  11.664 47.541 24.312 47.797 ;
     RECT  11.664 47.797 25.128 47.881 ;
     RECT  4.992 48.085 5.016 48.275 ;
     RECT  2.4 47.245 2.712 48.277 ;
     RECT  0.528 47.315 0.552 48.339 ;
     RECT  29.136 47.363 37.704 48.421 ;
     RECT  2.4 48.277 2.808 48.853 ;
     RECT  2.304 48.853 2.808 48.885 ;
     RECT  2.304 48.885 3.432 48.939 ;
     RECT  11.664 47.881 24.312 48.949 ;
     RECT  27.6 47.373 27.624 48.949 ;
     RECT  28.608 48.421 37.704 48.949 ;
     RECT  2.4 48.939 3.432 48.995 ;
     RECT  27.6 48.949 37.704 49.033 ;
     RECT  9.168 48.757 9.192 49.093 ;
     RECT  11.616 48.949 24.312 49.237 ;
     RECT  0.144 48.339 0.552 49.269 ;
     RECT  11.616 49.237 24.408 49.323 ;
     RECT  28.608 49.033 37.704 49.475 ;
     RECT  9.168 49.093 9.672 49.861 ;
     RECT  9.12 49.861 9.672 49.955 ;
     RECT  2.4 48.995 2.904 50.051 ;
     RECT  9.12 49.955 9.144 50.147 ;
     RECT  11.616 49.323 24.312 50.293 ;
     RECT  11.616 50.293 24.504 50.377 ;
     RECT  26.16 50.965 26.184 51.051 ;
     RECT  2.4 50.051 2.712 51.589 ;
     RECT  2.4 51.589 2.808 51.779 ;
     RECT  11.616 50.377 24.312 51.781 ;
     RECT  11.616 51.781 24.408 51.947 ;
     RECT  0.048 49.269 0.552 52.139 ;
     RECT  29.136 49.475 37.704 52.549 ;
     RECT  11.616 51.947 24.312 52.597 ;
     RECT  27.6 49.033 27.624 52.661 ;
     RECT  28.752 52.549 37.704 52.661 ;
     RECT  27.6 52.661 37.704 52.715 ;
     RECT  0.144 52.139 0.552 52.907 ;
     RECT  11.568 52.597 24.312 52.947 ;
     RECT  9.6 52.853 9.624 52.979 ;
     RECT  11.568 52.947 25.224 53.035 ;
     RECT  27.6 52.715 27.912 53.035 ;
     RECT  7.8 44.579 8.112 53.173 ;
     RECT  11.568 53.035 24.312 53.221 ;
     RECT  7.68 53.173 8.112 53.257 ;
     RECT  11.52 53.221 24.312 53.699 ;
     RECT  9.216 53.173 9.576 54.035 ;
     RECT  11.616 53.699 24.312 54.069 ;
     RECT  11.616 54.069 24.696 54.371 ;
     RECT  0.528 52.907 0.552 54.389 ;
     RECT  9.216 54.035 9.24 54.467 ;
     RECT  26.208 54.383 26.232 54.517 ;
     RECT  0.192 54.389 0.552 54.623 ;
     RECT  26.112 54.517 26.232 54.635 ;
     RECT  26.208 54.635 26.232 54.699 ;
     RECT  0.144 54.623 0.552 54.773 ;
     RECT  0.096 54.773 0.552 54.861 ;
     RECT  10.608 55.507 10.632 55.541 ;
     RECT  11.616 54.371 24.312 55.541 ;
     RECT  10.608 55.541 24.312 55.595 ;
     RECT  11.472 55.595 24.312 55.715 ;
     RECT  26.304 56.053 26.328 56.195 ;
     RECT  27.6 53.035 27.624 56.197 ;
     RECT  27.456 56.197 27.624 56.245 ;
     RECT  2.4 51.779 2.712 56.309 ;
     RECT  2.016 56.309 2.712 56.619 ;
     RECT  26.784 56.245 27.624 56.627 ;
     RECT  11.616 55.715 24.312 56.773 ;
     RECT  0.144 54.861 0.552 56.819 ;
     RECT  9.12 56.117 9.144 56.915 ;
     RECT  11.616 56.773 24.504 56.963 ;
     RECT  11.616 56.963 24.408 57.011 ;
     RECT  27.6 56.627 27.624 57.301 ;
     RECT  5.088 57.311 5.112 57.395 ;
     RECT  27.6 57.301 28.152 57.493 ;
     RECT  29.136 52.715 37.704 57.493 ;
     RECT  9.648 57.333 9.672 57.539 ;
     RECT  11.616 57.011 24.312 57.637 ;
     RECT  25.92 57.589 25.944 57.731 ;
     RECT  0.528 56.819 0.552 58.037 ;
     RECT  2.4 56.619 2.712 58.117 ;
     RECT  27.6 57.493 37.704 58.117 ;
     RECT  2.4 58.117 2.856 58.259 ;
     RECT  10.848 57.637 24.312 58.309 ;
     RECT  0.144 58.037 0.552 58.387 ;
     RECT  0.096 58.387 0.552 58.475 ;
     RECT  27.36 58.117 37.704 58.547 ;
     RECT  28.752 58.547 37.704 58.667 ;
     RECT  25.632 58.597 25.656 58.681 ;
     RECT  27.36 58.547 27.624 59.125 ;
     RECT  28.8 58.667 37.704 59.179 ;
     RECT  26.784 59.125 27.624 59.307 ;
     RECT  2.4 58.259 2.712 59.605 ;
     RECT  10.848 58.309 24.552 59.667 ;
     RECT  10.848 59.667 25.224 59.755 ;
     RECT  27.6 59.307 27.624 60.277 ;
     RECT  29.136 59.179 37.704 60.277 ;
     RECT  27.6 60.277 37.704 60.361 ;
     RECT  2.4 59.605 3.432 60.651 ;
     RECT  2.4 60.651 2.856 60.707 ;
     RECT  5.664 60.597 5.688 60.755 ;
     RECT  10.848 59.755 24.312 60.757 ;
     RECT  10.656 60.757 24.312 60.997 ;
     RECT  27.6 60.361 28.152 61.291 ;
     RECT  10.656 60.997 24.984 61.379 ;
     RECT  0.144 58.475 0.552 61.483 ;
     RECT  29.136 60.361 37.704 61.493 ;
     RECT  29.136 61.493 38.232 61.619 ;
     RECT  25.488 61.717 25.512 61.803 ;
     RECT  2.4 60.707 2.712 61.813 ;
     RECT  10.656 61.379 24.312 61.907 ;
     RECT  2.4 61.813 2.808 61.909 ;
     RECT  2.4 61.909 2.904 62.051 ;
     RECT  29.136 61.619 37.704 62.709 ;
     RECT  0.192 61.483 0.552 62.725 ;
     RECT  7.8 53.257 8.112 62.773 ;
     RECT  9.12 61.237 9.144 62.803 ;
     RECT  9.12 62.803 9.24 62.837 ;
     RECT  6.864 62.773 8.112 62.955 ;
     RECT  9.12 62.837 9.336 62.963 ;
     RECT  28.608 62.709 37.704 62.965 ;
     RECT  11.616 61.907 24.312 63.093 ;
     RECT  9.12 62.963 9.24 63.107 ;
     RECT  28.608 62.965 37.896 63.109 ;
     RECT  27.6 61.291 27.624 63.123 ;
     RECT  2.4 62.051 2.712 63.157 ;
     RECT  26.832 63.123 27.624 63.157 ;
     RECT  28.608 63.109 38.088 63.157 ;
     RECT  11.616 63.093 24.648 63.203 ;
     RECT  26.832 63.157 38.088 63.211 ;
     RECT  2.304 63.157 2.712 63.251 ;
     RECT  27.6 63.211 38.088 63.443 ;
     RECT  27.6 63.443 36.312 63.539 ;
     RECT  9.12 63.107 9.192 64.259 ;
     RECT  0.144 62.725 0.552 64.355 ;
     RECT  9.168 64.259 9.192 64.355 ;
     RECT  11.616 63.203 24.312 64.981 ;
     RECT  11.04 64.981 24.312 65.067 ;
     RECT  26.592 65.013 26.616 65.123 ;
     RECT  29.136 63.539 36.312 65.491 ;
     RECT  7.8 62.955 8.112 65.519 ;
     RECT  27.6 63.539 27.624 65.519 ;
     RECT  29.088 65.491 36.312 65.525 ;
     RECT  7.8 65.519 9.096 65.603 ;
     RECT  27.312 65.519 27.624 65.603 ;
     RECT  7.8 65.603 8.904 66.579 ;
     RECT  11.616 65.067 24.312 66.579 ;
     RECT  7.8 66.579 9.096 66.667 ;
     RECT  10.848 66.579 24.312 66.667 ;
     RECT  40.2 2.407 40.512 66.709 ;
     RECT  39.408 66.709 40.512 66.795 ;
     RECT  11.616 66.667 24.312 67.283 ;
     RECT  28.992 65.525 36.312 67.331 ;
     RECT  15.024 67.283 24.312 67.717 ;
     RECT  29.136 67.331 36.312 67.717 ;
     RECT  37.488 63.443 38.088 67.717 ;
     RECT  15.024 67.717 25.272 68.245 ;
     RECT  15.024 68.245 26.04 68.331 ;
     RECT  29.136 67.717 38.088 68.341 ;
     RECT  28.656 68.341 38.088 68.387 ;
     RECT  28.656 68.387 36.312 68.425 ;
     RECT  15.024 68.331 24.648 68.971 ;
     RECT  27.6 65.603 27.624 69.907 ;
     RECT  37.488 68.387 38.088 69.941 ;
     RECT  27.552 69.907 27.624 69.995 ;
     RECT  37.488 69.941 39 70.029 ;
     RECT  29.136 68.425 36.312 70.197 ;
     RECT  15.024 68.971 24.312 70.213 ;
     RECT  28.608 70.197 36.312 70.285 ;
     RECT  0.528 64.355 0.552 70.315 ;
     RECT  29.088 70.285 36.312 70.451 ;
     RECT  15.024 70.213 24.408 70.611 ;
     RECT  15.024 70.611 24.6 70.699 ;
     RECT  26.256 70.611 26.28 70.699 ;
     RECT  15.024 70.699 24.312 70.739 ;
     RECT  11.616 67.283 13.848 70.751 ;
     RECT  15.024 70.739 16.872 70.751 ;
     RECT  11.616 70.751 16.872 70.835 ;
     RECT  15.024 70.835 16.872 71.315 ;
     RECT  17.856 70.739 24.312 71.797 ;
     RECT  26.304 71.077 26.328 71.797 ;
     RECT  25.584 71.797 26.328 71.891 ;
     RECT  25.632 71.891 26.328 72.179 ;
     RECT  10.032 72.309 10.056 72.397 ;
     RECT  40.2 66.795 40.512 72.805 ;
     RECT  17.856 71.797 24.408 72.995 ;
     RECT  11.616 70.835 13.848 73.285 ;
     RECT  15.024 71.315 16.68 73.285 ;
     RECT  11.616 73.285 16.68 73.765 ;
     RECT  17.856 72.995 21 73.765 ;
     RECT  22.272 72.995 24.408 73.811 ;
     RECT  11.616 73.765 21 73.955 ;
     RECT  15.024 73.955 21 74.147 ;
     RECT  22.272 73.811 22.344 74.147 ;
     RECT  26.304 72.179 26.328 74.293 ;
     RECT  27.6 69.995 27.624 74.293 ;
     RECT  29.136 70.451 36.312 74.293 ;
     RECT  26.304 74.293 36.312 74.377 ;
     RECT  39.84 72.805 40.512 74.667 ;
     RECT  20.592 74.147 21 74.923 ;
     RECT  28.8 74.377 36.312 75.051 ;
     RECT  24 73.811 24.312 75.061 ;
     RECT  11.616 73.955 13.848 75.205 ;
     RECT  22.272 74.147 22.296 75.205 ;
     RECT  37.488 70.029 38.088 75.205 ;
     RECT  11.136 75.205 13.848 75.253 ;
     RECT  29.136 75.051 36.312 75.299 ;
     RECT  26.304 74.377 27.624 75.311 ;
     RECT  10.704 75.253 13.848 75.347 ;
     RECT  25.632 75.311 27.624 75.395 ;
     RECT  22.272 75.205 22.488 75.603 ;
     RECT  24 75.061 24.504 75.603 ;
     RECT  20.976 74.923 21 75.637 ;
     RECT  37.488 75.205 38.232 75.721 ;
     RECT  20.976 75.637 21.288 75.781 ;
     RECT  22.272 75.603 24.504 75.781 ;
     RECT  40.2 74.667 40.512 75.795 ;
     RECT  39.36 75.795 40.512 75.883 ;
     RECT  20.976 75.781 24.504 76.357 ;
     RECT  29.232 75.299 36.312 76.661 ;
     RECT  37.488 75.721 38.088 76.661 ;
     RECT  29.232 76.661 38.088 76.749 ;
     RECT  20.976 76.357 25.032 76.933 ;
     RECT  26.304 75.395 26.328 76.933 ;
     RECT  40.2 75.883 40.512 77.173 ;
     RECT  37.44 76.749 38.088 77.227 ;
     RECT  39.36 77.173 40.512 77.257 ;
     RECT  11.616 75.347 13.848 77.461 ;
     RECT  29.232 76.749 36.312 77.555 ;
     RECT  10.8 77.461 13.848 77.611 ;
     RECT  10.32 77.907 10.344 77.995 ;
     RECT  15.024 74.147 18.912 78.131 ;
     RECT  32.256 77.555 36.312 78.371 ;
     RECT  37.488 77.227 38.088 78.469 ;
     RECT  18.432 78.131 18.912 78.613 ;
     RECT  7.8 66.667 8.112 79.123 ;
     RECT  7.8 79.123 8.616 79.211 ;
     RECT  20.976 76.933 26.328 79.237 ;
     RECT  37.488 78.469 38.616 79.275 ;
     RECT  40.2 77.257 40.512 79.669 ;
     RECT  10.416 79.605 10.44 79.715 ;
     RECT  39.888 79.669 40.512 79.753 ;
     RECT  15.024 78.131 17.352 79.765 ;
     RECT  18.432 78.613 19.368 79.765 ;
     RECT  15.024 79.765 19.368 79.859 ;
     RECT  37.488 79.275 38.088 79.859 ;
     RECT  29.232 77.555 31.272 80.149 ;
     RECT  32.256 78.371 33.24 80.149 ;
     RECT  29.232 80.149 33.24 80.235 ;
     RECT  27.6 75.395 27.624 80.275 ;
     RECT  27.6 80.275 28.2 80.363 ;
     RECT  38.736 80.687 38.76 80.771 ;
     RECT  32.256 80.235 33.24 80.869 ;
     RECT  34.368 78.371 36.312 80.869 ;
     RECT  9.312 80.851 9.336 80.939 ;
     RECT  32.256 80.869 36.312 80.953 ;
     RECT  29.232 80.235 31.272 81.461 ;
     RECT  32.256 80.953 33.24 81.461 ;
     RECT  29.232 81.461 33.24 81.635 ;
     RECT  20.832 79.237 26.328 82.101 ;
     RECT  32.592 81.635 33.24 82.101 ;
     RECT  34.368 80.953 36.312 82.101 ;
     RECT  38.784 82.101 38.808 82.189 ;
     RECT  11.616 77.611 13.848 82.293 ;
     RECT  7.8 79.211 8.112 82.309 ;
     RECT  7.8 82.309 9 82.411 ;
     RECT  15.024 79.859 18.912 82.645 ;
     RECT  20.16 82.101 26.328 82.645 ;
     RECT  37.488 79.859 37.512 82.789 ;
     RECT  32.592 82.101 36.312 82.805 ;
     RECT  37.488 82.789 37.656 82.873 ;
     RECT  32.592 82.805 36.456 82.893 ;
     RECT  15.024 82.645 26.328 83.039 ;
     RECT  27.6 80.363 27.624 83.039 ;
     RECT  32.592 82.893 36.312 83.091 ;
     RECT  15.024 83.039 27.624 83.123 ;
     RECT  11.52 82.293 13.848 83.125 ;
     RECT  29.232 81.635 31.272 83.125 ;
     RECT  32.304 83.091 36.312 83.125 ;
     RECT  10.848 83.125 13.848 83.209 ;
     RECT  29.232 83.125 36.312 83.243 ;
     RECT  27.312 83.123 27.624 83.257 ;
     RECT  15.024 83.123 26.328 83.267 ;
     RECT  11.616 83.209 13.848 83.375 ;
     RECT  15.024 83.267 19.56 83.375 ;
     RECT  11.616 83.375 19.56 83.459 ;
     RECT  27.6 83.257 27.624 84.243 ;
     RECT  29.232 83.243 31.272 84.243 ;
     RECT  37.488 82.873 37.512 84.325 ;
     RECT  27.6 84.243 31.272 84.331 ;
     RECT  32.592 83.243 36.312 84.819 ;
     RECT  32.352 84.819 36.312 84.907 ;
     RECT  29.232 84.331 31.272 85.091 ;
     RECT  11.616 83.459 13.848 85.477 ;
     RECT  15.024 83.459 19.56 85.477 ;
     RECT  7.8 82.411 8.112 86.005 ;
     RECT  29.4 85.091 31.272 86.005 ;
     RECT  32.592 84.907 36.312 86.005 ;
     RECT  7.8 86.005 8.28 86.089 ;
     RECT  27.6 84.331 27.624 86.099 ;
     RECT  29.4 86.005 36.312 86.099 ;
     RECT  37.488 84.325 37.608 86.533 ;
     RECT  37.488 86.533 38.184 86.635 ;
     RECT  29.4 86.099 36.12 87.221 ;
     RECT  40.2 79.753 40.512 87.221 ;
     RECT  28.464 87.221 36.12 87.253 ;
     RECT  27.984 87.253 36.12 87.309 ;
     RECT  20.832 83.267 26.328 87.315 ;
     RECT  20.832 87.315 26.52 87.403 ;
     RECT  39.216 87.221 40.512 87.539 ;
     RECT  10.56 87.763 10.584 87.851 ;
     RECT  27.984 87.309 28.008 88.643 ;
     RECT  27.456 88.757 27.48 88.931 ;
     RECT  20.832 87.403 26.328 88.979 ;
     RECT  37.488 86.635 37.608 88.979 ;
     RECT  39.024 87.781 39.048 89.939 ;
     RECT  28.32 89.941 28.344 90.027 ;
     RECT  29.4 87.309 36.12 90.095 ;
     RECT  28.464 90.095 36.12 90.179 ;
     RECT  20.832 88.979 25.368 90.517 ;
     RECT  20.832 90.517 26.232 90.603 ;
     RECT  11.616 85.477 19.56 90.613 ;
     RECT  11.568 90.613 19.656 90.755 ;
     RECT  37.584 88.979 37.608 90.933 ;
     RECT  38.784 90.911 38.808 90.995 ;
     RECT  37.488 90.933 37.608 91.043 ;
     RECT  37.584 91.043 37.608 91.045 ;
     RECT  37.584 91.045 38.232 91.129 ;
     RECT  20.832 90.603 25.368 91.765 ;
     RECT  20.832 91.765 26.184 91.859 ;
     RECT  29.4 90.179 36.12 92.149 ;
     RECT  29.04 92.149 36.12 92.387 ;
     RECT  27.648 92.341 27.672 92.499 ;
     RECT  26.88 92.499 27.672 92.587 ;
     RECT  20.832 91.859 25.368 92.821 ;
     RECT  29.04 92.387 30.216 92.821 ;
     RECT  28.944 92.821 30.216 92.963 ;
     RECT  11.616 90.755 19.656 92.971 ;
     RECT  26.976 92.587 27.672 93.419 ;
     RECT  20.832 92.821 25.992 93.749 ;
     RECT  28.944 92.963 30.168 93.803 ;
     RECT  27.504 93.419 27.672 93.931 ;
     RECT  31.248 92.387 36.12 94.035 ;
     RECT  31.2 94.035 36.12 94.123 ;
     RECT  13.104 92.971 19.656 94.211 ;
     RECT  11.616 92.971 12.072 94.691 ;
     RECT  20.832 93.749 26.232 94.691 ;
     RECT  38.736 94.597 38.76 94.739 ;
     RECT  37.584 91.129 37.608 94.981 ;
     RECT  29.4 93.803 30.168 95.125 ;
     RECT  31.248 94.123 36.12 95.125 ;
     RECT  29.4 95.125 36.12 95.173 ;
     RECT  13.2 94.211 19.656 95.219 ;
     RECT  29.28 95.173 36.12 95.275 ;
     RECT  29.4 95.275 36.12 95.497 ;
     RECT  27.648 93.931 27.672 95.749 ;
     RECT  11.664 94.691 12.072 96.181 ;
     RECT  13.2 95.219 14.184 96.227 ;
     RECT  11.376 96.181 12.072 96.265 ;
     RECT  27.648 95.749 28.104 96.325 ;
     RECT  11.664 96.265 12.072 96.371 ;
     RECT  29.4 95.497 30.168 96.565 ;
     RECT  31.248 95.497 36.12 96.565 ;
     RECT  29.4 96.565 36.12 96.723 ;
     RECT  27.648 96.325 28.2 96.853 ;
     RECT  37.44 94.981 37.608 96.853 ;
     RECT  26.976 96.853 28.2 96.863 ;
     RECT  29.232 96.723 36.12 96.863 ;
     RECT  15.744 95.219 19.656 97.077 ;
     RECT  20.832 94.691 25.368 97.363 ;
     RECT  26.976 96.863 36.12 97.363 ;
     RECT  37.392 96.853 37.608 97.381 ;
     RECT  37.392 97.381 38.088 97.429 ;
     RECT  12.048 96.371 12.072 97.523 ;
     RECT  20.832 97.363 36.12 98.005 ;
     RECT  13.2 96.227 14.136 98.053 ;
     RECT  13.2 98.053 14.472 98.101 ;
     RECT  15.6 97.077 19.656 98.101 ;
     RECT  11.952 98.341 11.976 98.425 ;
     RECT  13.2 98.101 19.656 98.485 ;
     RECT  20.832 98.005 36.36 98.485 ;
     RECT  13.2 98.485 36.36 98.629 ;
     RECT  37.392 97.429 38.232 98.629 ;
     RECT  13.2 98.629 38.232 98.917 ;
     RECT  13.104 98.917 38.232 100.259 ;
     RECT  2.4 63.251 2.712 101.003 ;
     RECT  7.8 86.089 8.112 101.003 ;
     RECT  13.2 100.259 38.232 101.003 ;
     RECT  40.2 87.539 40.512 101.003 ;
     RECT  45.6 2.407 45.912 101.003 ;
     RECT  2.592 101.003 2.712 101.273 ;
     RECT  7.992 101.003 8.112 101.273 ;
     RECT  13.392 101.003 38.232 101.273 ;
     RECT  40.392 101.003 40.512 101.273 ;
     RECT  45.792 101.003 45.912 101.273 ;
     RECT  13.68 101.273 38.232 103.381 ;
     RECT  13.68 103.381 38.28 103.467 ;
     RECT  13.68 103.467 38.232 103.523 ;
     RECT  13.824 103.523 38.232 103.632 ;
    LAYER M6 ;
     RECT  0.037 49.28 0.133 49.312 ;
     RECT  0.037 52.096 0.133 52.128 ;
     RECT  0.085 54.784 0.133 54.816 ;
     RECT  0.085 58.432 0.133 58.464 ;
     RECT  0.133 46.784 0.181 46.816 ;
     RECT  0.133 48.384 0.181 49.312 ;
     RECT  0.133 52.096 0.181 52.896 ;
     RECT  0.133 54.656 0.181 56.608 ;
     RECT  0.133 58.048 0.181 61.472 ;
     RECT  0.133 62.784 0.181 63.392 ;
     RECT  0.133 39.808 0.275 44.704 ;
     RECT  0.181 54.4 0.275 56.608 ;
     RECT  0.181 46.784 0.323 49.312 ;
     RECT  0.275 54.4 0.323 54.816 ;
     RECT  0.275 40 0.467 44.704 ;
     RECT  0.181 51.648 0.467 52.896 ;
     RECT  0.467 41.472 0.707 44.704 ;
     RECT  0.323 46.784 1.717 47.072 ;
     RECT  0.323 48.384 1.717 49.312 ;
     RECT  0.467 40 2.16 40.032 ;
     RECT  0.707 41.472 2.16 44.384 ;
     RECT  1.717 46.784 2.16 49.312 ;
     RECT  0.467 52.864 2.16 52.896 ;
     RECT  0.275 56.192 2.16 56.608 ;
     RECT  0.181 58.048 2.16 63.392 ;
     RECT  2.16 40 2.291 44.384 ;
     RECT  2.16 45.729 2.819 49.312 ;
     RECT  2.819 48.896 3.443 49.312 ;
     RECT  2.291 40.329 5.747 44.384 ;
     RECT  2.819 45.729 5.747 47.2 ;
     RECT  5.747 43.968 6.323 44.384 ;
     RECT  5.747 45.729 6.323 46.816 ;
     RECT  6.323 44.288 6.419 44.32 ;
     RECT  2.16 51.129 7.669 52.896 ;
     RECT  0.323 54.4 7.669 54.688 ;
     RECT  2.16 88.929 8.245 89.601 ;
     RECT  8.245 86.016 8.314 86.048 ;
     RECT  2.16 78.129 8.581 78.801 ;
     RECT  2.16 83.529 8.965 84.201 ;
     RECT  8.629 65.856 9.061 65.888 ;
     RECT  2.16 67.329 9.061 68.001 ;
     RECT  2.16 56.192 9.109 63.392 ;
     RECT  9.061 65.536 9.131 68.001 ;
     RECT  8.965 82.368 9.195 84.201 ;
     RECT  9.141 80.896 9.347 80.928 ;
     RECT  7.669 51.129 9.635 54.688 ;
     RECT  5.747 40.329 9.827 42.016 ;
     RECT  2.16 72.729 10.021 73.401 ;
     RECT  10.021 72.32 10.091 73.401 ;
     RECT  9.635 53.184 10.229 54.688 ;
     RECT  9.109 56.128 10.229 63.392 ;
     RECT  8.581 78.129 10.293 79.2 ;
     RECT  10.293 77.952 10.451 79.648 ;
     RECT  10.451 77.952 10.789 78.801 ;
     RECT  9.131 66.624 10.883 68.001 ;
     RECT  10.037 75.264 11.171 75.296 ;
     RECT  2.16 94.329 11.365 95.001 ;
     RECT  9.827 40.329 11.411 41.568 ;
     RECT  9.195 83.136 11.509 84.201 ;
     RECT  9.635 51.129 11.557 51.801 ;
     RECT  10.229 53.184 11.557 63.392 ;
     RECT  8.245 87.808 11.557 89.601 ;
     RECT  11.029 65.024 12.563 65.056 ;
     RECT  11.701 92.928 12.613 92.96 ;
     RECT  12.613 92.16 12.659 92.96 ;
     RECT  11.557 87.808 13.045 90.656 ;
     RECT  12.659 92.16 13.045 92.192 ;
     RECT  6.323 45.729 13.093 46.401 ;
     RECT  11.557 51.129 13.093 63.392 ;
     RECT  11.509 82.304 13.099 84.201 ;
     RECT  13.045 80.32 13.139 80.352 ;
     RECT  13.045 87.808 13.139 92.192 ;
     RECT  13.093 51.129 13.611 64.16 ;
     RECT  13.093 45.729 13.619 47.2 ;
     RECT  13.611 56.128 13.667 64.16 ;
     RECT  13.667 56.128 13.715 63.776 ;
     RECT  11.365 94.329 13.715 96.224 ;
     RECT  13.611 51.129 13.813 54.688 ;
     RECT  13.715 56.128 13.859 63.392 ;
     RECT  13.139 88.384 14.197 92.192 ;
     RECT  13.715 94.329 14.251 96.16 ;
     RECT  11.411 40.329 14.562 41.001 ;
     RECT  14.251 94.329 14.581 95.001 ;
     RECT  14.562 40.329 14.635 41.12 ;
     RECT  14.581 94.08 14.65 95.001 ;
     RECT  14.197 88.384 14.771 92.704 ;
     RECT  0.517 70.272 14.773 70.304 ;
     RECT  13.099 83.529 14.773 84.201 ;
     RECT  3.443 49.28 15.061 49.312 ;
     RECT  14.771 88.929 15.155 92.704 ;
     RECT  10.789 77.568 15.541 78.801 ;
     RECT  14.65 94.329 15.541 95.001 ;
     RECT  11.941 98.368 15.541 98.4 ;
     RECT  15.522 75.2 15.595 75.232 ;
     RECT  15.541 94.329 15.595 98.4 ;
     RECT  15.541 77.44 15.635 78.944 ;
     RECT  15.595 94.329 15.635 97.12 ;
     RECT  10.091 72.729 15.781 73.401 ;
     RECT  15.155 88.929 15.827 91.616 ;
     RECT  15.781 72.576 15.851 73.401 ;
     RECT  15.061 48.832 15.925 49.312 ;
     RECT  13.813 51.008 15.979 54.688 ;
     RECT  14.773 70.272 16.021 70.816 ;
     RECT  15.925 48.832 16.115 49.376 ;
     RECT  15.635 94.329 16.259 96.288 ;
     RECT  16.115 48.832 16.453 49.312 ;
     RECT  2.16 99.729 16.453 100.401 ;
     RECT  16.453 99.729 16.501 101.216 ;
     RECT  10.883 67.329 16.565 68.001 ;
     RECT  16.021 69.952 16.595 70.816 ;
     RECT  16.501 103.232 16.933 103.264 ;
     RECT  16.453 48.768 16.979 49.312 ;
     RECT  13.619 45.729 17.029 46.401 ;
     RECT  14.773 83.392 17.077 84.201 ;
     RECT  16.565 67.329 17.123 68.64 ;
     RECT  13.859 56.192 17.333 63.392 ;
     RECT  17.029 65.536 17.333 65.568 ;
     RECT  16.933 103.232 17.333 103.456 ;
     RECT  17.077 83.392 17.355 85.28 ;
     RECT  15.635 77.44 17.397 78.801 ;
     RECT  15.827 88.929 17.413 89.601 ;
     RECT  17.397 76.736 17.451 78.801 ;
     RECT  16.595 69.952 17.461 70.304 ;
     RECT  17.461 69.568 17.53 70.304 ;
     RECT  16.259 94.329 17.557 95.001 ;
     RECT  17.333 103.232 17.557 103.584 ;
     RECT  17.509 86.656 17.579 86.688 ;
     RECT  16.501 98.56 17.579 101.216 ;
     RECT  17.53 69.952 17.651 70.304 ;
     RECT  17.579 98.56 17.747 100.401 ;
     RECT  17.413 88.929 18.101 89.888 ;
     RECT  18.101 88 18.165 89.888 ;
     RECT  18.165 88 18.179 90.272 ;
     RECT  17.557 94.329 18.229 95.2 ;
     RECT  17.333 56.192 18.323 65.568 ;
     RECT  15.827 91.584 18.357 91.616 ;
     RECT  18.229 94.329 18.357 95.328 ;
     RECT  18.357 91.584 18.41 95.328 ;
     RECT  15.979 51.129 18.411 54.688 ;
     RECT  17.557 102.528 18.419 103.584 ;
     RECT  18.41 91.584 18.421 95.392 ;
     RECT  18.421 91.584 18.43 95.904 ;
     RECT  18.277 0.256 18.467 0.288 ;
     RECT  17.029 45.729 18.469 47.84 ;
     RECT  18.181 75.264 18.469 75.296 ;
     RECT  17.355 83.264 18.469 85.28 ;
     RECT  18.179 88.929 18.469 90.272 ;
     RECT  18.43 91.584 18.469 92.448 ;
     RECT  18.43 94.329 18.515 95.904 ;
     RECT  18.469 88.929 18.795 92.448 ;
     RECT  18.419 102.528 18.851 103.456 ;
     RECT  18.795 92.416 19.043 92.448 ;
     RECT  18.851 102.528 19.187 102.624 ;
     RECT  15.851 72.729 19.189 73.401 ;
     RECT  18.469 74.88 19.189 75.296 ;
     RECT  19.189 72.729 19.243 75.296 ;
     RECT  19.243 72.729 19.283 74.912 ;
     RECT  18.515 94.329 19.427 95.392 ;
     RECT  18.469 82.112 19.523 85.28 ;
     RECT  19.187 102.592 19.859 102.624 ;
     RECT  18.469 45.248 20.339 47.84 ;
     RECT  20.339 45.729 20.387 47.84 ;
     RECT  18.411 51.129 20.437 52.96 ;
     RECT  16.979 49.28 20.485 49.312 ;
     RECT  20.437 50.752 20.485 52.96 ;
     RECT  20.485 49.28 20.533 52.96 ;
     RECT  18.323 56.192 20.579 64.928 ;
     RECT  20.533 48.384 20.627 52.96 ;
     RECT  19.283 72.729 20.853 73.401 ;
     RECT  19.283 74.88 20.853 74.912 ;
     RECT  17.451 76.736 20.853 76.768 ;
     RECT  20.853 74.88 20.907 76.768 ;
     RECT  20.627 49.28 21.038 52.96 ;
     RECT  18.411 54.4 21.038 54.688 ;
     RECT  17.123 67.329 21.109 68.001 ;
     RECT  17.747 99.729 21.157 100.401 ;
     RECT  19.523 82.112 21.347 84.201 ;
     RECT  20.579 64.896 21.365 64.928 ;
     RECT  21.109 66.624 21.365 68.001 ;
     RECT  21.365 64.896 21.419 65.056 ;
     RECT  21.365 66.624 21.419 68.448 ;
     RECT  21.349 103.36 21.491 103.392 ;
     RECT  19.427 94.329 21.637 95.001 ;
     RECT  21.419 67.329 21.683 68.448 ;
     RECT  14.635 40.329 21.685 41.001 ;
     RECT  18.181 43.328 21.685 43.36 ;
     RECT  21.685 40.329 21.739 44.32 ;
     RECT  21.038 49.28 21.779 54.688 ;
     RECT  21.739 44.288 21.875 44.32 ;
     RECT  21.739 40.329 21.923 42.144 ;
     RECT  17.651 70.272 22.165 70.304 ;
     RECT  18.795 88.929 22.165 90.272 ;
     RECT  21.157 98.624 22.165 100.401 ;
     RECT  20.907 75.648 22.259 76.768 ;
     RECT  21.637 94.208 22.434 95.001 ;
     RECT  22.434 94.208 22.507 95.584 ;
     RECT  20.853 72.32 22.643 73.401 ;
     RECT  22.165 88.384 22.773 90.272 ;
     RECT  22.741 85.824 22.827 85.856 ;
     RECT  21.419 65.024 22.835 65.056 ;
     RECT  22.259 75.648 23.171 75.68 ;
     RECT  22.933 47.808 23.269 47.84 ;
     RECT  21.779 49.28 23.269 49.312 ;
     RECT  20.387 45.729 23.285 46.401 ;
     RECT  23.269 42.688 23.339 42.72 ;
     RECT  23.269 47.808 23.339 49.312 ;
     RECT  21.683 67.329 23.461 68.001 ;
     RECT  22.165 98.048 23.509 100.401 ;
     RECT  23.509 96.832 23.733 100.401 ;
     RECT  23.733 96.832 23.797 100.576 ;
     RECT  23.285 45.44 23.893 46.401 ;
     RECT  23.797 96.832 23.893 100.704 ;
     RECT  22.165 70.016 23.925 70.304 ;
     RECT  23.797 103.424 23.925 103.456 ;
     RECT  23.861 92.864 23.939 92.896 ;
     RECT  22.643 72.729 24.373 73.401 ;
     RECT  23.925 103.296 24.373 103.456 ;
     RECT  23.339 49.28 24.419 49.312 ;
     RECT  21.779 51.129 24.469 54.688 ;
     RECT  24.373 103.296 24.491 103.584 ;
     RECT  23.461 67.329 24.501 68.32 ;
     RECT  23.925 70.016 24.501 70.368 ;
     RECT  24.373 71.808 24.501 73.401 ;
     RECT  24.501 67.329 24.555 73.401 ;
     RECT  22.773 87.808 24.563 90.272 ;
     RECT  23.893 96.832 24.611 100.832 ;
     RECT  24.546 81.216 24.619 81.248 ;
     RECT  24.611 97.472 24.634 100.832 ;
     RECT  24.555 67.329 24.659 68.96 ;
     RECT  24.634 97.664 24.738 100.832 ;
     RECT  22.507 94.208 24.755 95.001 ;
     RECT  24.491 103.296 24.853 103.456 ;
     RECT  24.469 50.304 25.067 54.688 ;
     RECT  23.339 47.808 25.139 47.84 ;
     RECT  25.067 50.304 25.235 53.024 ;
     RECT  24.555 70.656 25.619 73.401 ;
     RECT  24.853 103.232 25.653 103.456 ;
     RECT  25.653 103.04 25.781 103.456 ;
     RECT  24.563 87.808 25.813 89.601 ;
     RECT  25.781 102.912 25.861 103.456 ;
     RECT  24.738 97.664 25.957 100.896 ;
     RECT  25.813 86.592 25.963 89.601 ;
     RECT  25.957 97.664 25.973 101.216 ;
     RECT  25.973 96.896 26.027 101.216 ;
     RECT  24.659 67.329 26.051 68.32 ;
     RECT  23.893 44.48 26.099 46.401 ;
     RECT  26.037 81.472 26.11 81.504 ;
     RECT  25.957 92.864 26.149 92.896 ;
     RECT  25.963 88.929 26.165 89.601 ;
     RECT  26.149 91.776 26.165 92.896 ;
     RECT  26.165 88.929 26.197 92.896 ;
     RECT  24.755 94.329 26.197 95.001 ;
     RECT  26.197 88.929 26.219 95.001 ;
     RECT  25.067 54.4 26.243 54.688 ;
     RECT  26.219 88.929 26.243 90.592 ;
     RECT  25.619 70.656 26.291 70.688 ;
     RECT  25.963 87.36 26.531 87.392 ;
     RECT  25.619 72.128 26.725 73.401 ;
     RECT  25.621 75.328 26.725 75.36 ;
     RECT  25.861 102.912 26.731 103.584 ;
     RECT  26.581 65.024 26.859 65.056 ;
     RECT  26.731 103.104 26.915 103.584 ;
     RECT  26.725 72.128 26.923 75.36 ;
     RECT  26.219 92.544 26.923 95.001 ;
     RECT  26.923 93.376 27.051 95.001 ;
     RECT  26.915 103.168 27.155 103.584 ;
     RECT  26.099 44.608 27.349 46.401 ;
     RECT  26.243 88.929 27.381 89.601 ;
     RECT  27.349 44.608 27.435 47.328 ;
     RECT  27.381 88.768 27.491 89.601 ;
     RECT  27.435 44.928 27.779 46.401 ;
     RECT  25.235 50.304 27.829 51.801 ;
     RECT  27.829 50.304 27.877 52.704 ;
     RECT  27.877 50.304 27.947 53.024 ;
     RECT  28.149 80.32 28.222 80.352 ;
     RECT  27.491 88.929 28.309 89.601 ;
     RECT  26.027 96.896 28.357 101.024 ;
     RECT  28.309 88.929 28.453 90.016 ;
     RECT  21.347 82.944 28.501 84.201 ;
     RECT  28.357 96.896 28.523 101.472 ;
     RECT  26.923 72.128 28.547 74.336 ;
     RECT  27.541 69.952 28.578 69.984 ;
     RECT  27.947 50.304 28.587 52.704 ;
     RECT  28.526 48.96 28.595 48.992 ;
     RECT  26.051 67.329 28.597 68.001 ;
     RECT  28.578 69.952 28.651 70.24 ;
     RECT  28.597 67.329 28.691 68.384 ;
     RECT  28.501 82.944 28.779 84.32 ;
     RECT  28.453 87.232 28.779 87.264 ;
     RECT  28.587 51.129 28.787 52.704 ;
     RECT  28.77 75.008 28.843 75.04 ;
     RECT  27.051 93.76 28.917 95.001 ;
     RECT  27.301 65.536 28.981 65.568 ;
     RECT  28.917 92.864 28.99 95.001 ;
     RECT  28.523 96.896 29.035 101.408 ;
     RECT  28.981 65.536 29.123 65.952 ;
     RECT  29.123 65.92 29.221 65.952 ;
     RECT  28.691 67.329 29.221 68.001 ;
     RECT  29.035 96.896 29.221 101.152 ;
     RECT  28.99 93.76 29.269 95.001 ;
     RECT  29.221 96.768 29.291 101.152 ;
     RECT  29.291 97.792 29.363 101.152 ;
     RECT  29.269 75.968 29.611 76 ;
     RECT  27.155 103.168 29.749 103.456 ;
     RECT  20.579 56.192 29.843 63.392 ;
     RECT  29.363 97.792 29.843 100.704 ;
     RECT  29.843 97.792 29.95 100.512 ;
     RECT  29.749 103.168 30.131 103.584 ;
     RECT  28.779 82.944 30.181 84.201 ;
     RECT  30.131 103.296 30.227 103.584 ;
     RECT  29.269 93.76 30.443 95.264 ;
     RECT  29.029 92.16 30.446 92.192 ;
     RECT  28.453 88.929 30.507 90.144 ;
     RECT  30.446 91.776 30.515 92.192 ;
     RECT  29.221 65.92 30.613 68.001 ;
     RECT  17.451 78.129 30.645 78.801 ;
     RECT  28.787 51.129 30.661 51.801 ;
     RECT  30.613 64.96 30.699 68.001 ;
     RECT  30.443 94.08 30.709 95.264 ;
     RECT  30.699 66.048 30.763 68.001 ;
     RECT  30.661 50.688 30.773 51.801 ;
     RECT  30.773 50.688 30.827 53.024 ;
     RECT  30.645 78.129 30.851 79.84 ;
     RECT  30.181 82.944 30.851 84.384 ;
     RECT  30.851 78.129 30.965 78.801 ;
     RECT  28.547 72.128 31.019 73.568 ;
     RECT  30.965 78.016 31.043 78.801 ;
     RECT  30.133 81.472 31.074 81.504 ;
     RECT  31.019 72.576 31.093 73.568 ;
     RECT  30.965 75.456 31.093 75.488 ;
     RECT  31.093 72.576 31.157 75.488 ;
     RECT  29.95 97.792 31.189 97.824 ;
     RECT  29.95 99.729 31.221 100.512 ;
     RECT  31.189 97.152 31.333 97.824 ;
     RECT  30.709 94.08 31.339 95.456 ;
     RECT  31.157 72.576 31.379 75.872 ;
     RECT  30.227 103.296 31.403 103.456 ;
     RECT  31.333 97.152 31.406 98.016 ;
     RECT  30.851 83.2 31.413 84.384 ;
     RECT  30.827 51.129 31.541 53.024 ;
     RECT  31.074 80.192 31.595 81.504 ;
     RECT  31.541 51.129 31.619 53.728 ;
     RECT  31.379 72.576 31.659 75.488 ;
     RECT  31.221 99.729 31.797 100.832 ;
     RECT  31.406 96.896 31.861 98.016 ;
     RECT  31.797 99.729 31.861 101.216 ;
     RECT  31.861 99.584 31.907 101.216 ;
     RECT  31.861 96.832 31.93 98.016 ;
     RECT  29.843 56.529 31.955 63.392 ;
     RECT  31.595 81.472 31.955 81.504 ;
     RECT  31.93 97.92 32.053 98.016 ;
     RECT  31.907 99.584 32.053 101.024 ;
     RECT  31.955 58.56 32.099 63.392 ;
     RECT  30.763 67.136 32.197 68.001 ;
     RECT  31.659 72.729 32.243 73.696 ;
     RECT  31.413 83.2 32.293 84.896 ;
     RECT  32.053 97.92 32.339 101.024 ;
     RECT  32.293 83.136 32.387 84.896 ;
     RECT  31.339 94.329 32.437 95.456 ;
     RECT  32.339 99.584 32.531 101.024 ;
     RECT  32.099 59.008 32.579 63.392 ;
     RECT  32.197 67.136 32.725 68.384 ;
     RECT  30.507 88.929 32.757 89.601 ;
     RECT  32.579 59.264 32.771 63.392 ;
     RECT  30.997 86.592 32.811 86.624 ;
     RECT  31.619 51.129 32.867 53.024 ;
     RECT  32.243 72.729 33.013 73.401 ;
     RECT  31.403 103.424 33.253 103.456 ;
     RECT  32.531 99.729 33.274 100.512 ;
     RECT  33.013 72.256 33.541 73.401 ;
     RECT  31.659 75.456 33.541 75.488 ;
     RECT  33.541 72.256 33.589 75.488 ;
     RECT  30.515 92.16 33.589 92.192 ;
     RECT  33.589 72.256 33.643 75.68 ;
     RECT  33.589 91.072 33.643 92.192 ;
     RECT  32.437 94.329 33.653 96.288 ;
     RECT  32.725 65.856 33.683 68.384 ;
     RECT  33.653 93.696 33.729 96.288 ;
     RECT  33.729 93.696 33.731 95.2 ;
     RECT  33.253 103.232 33.781 103.456 ;
     RECT  32.757 88.064 33.827 89.601 ;
     RECT  32.387 83.136 33.925 84.201 ;
     RECT  31.043 78.129 33.973 78.801 ;
     RECT  32.771 59.968 34.019 63.392 ;
     RECT  33.925 82.112 34.165 84.201 ;
     RECT  33.643 72.256 34.213 73.401 ;
     RECT  33.683 65.856 34.219 65.888 ;
     RECT  33.683 67.2 34.234 68.384 ;
     RECT  34.019 60.16 34.259 63.392 ;
     RECT  32.339 97.92 34.259 97.952 ;
     RECT  34.213 71.232 34.283 73.401 ;
     RECT  34.259 60.736 34.547 63.392 ;
     RECT  33.781 103.168 34.613 103.456 ;
     RECT  34.547 61.312 34.739 63.392 ;
     RECT  34.234 67.329 34.739 68.384 ;
     RECT  34.165 80.896 34.739 84.201 ;
     RECT  34.613 103.04 34.789 103.456 ;
     RECT  33.731 94.208 34.795 95.2 ;
     RECT  34.739 80.896 34.805 82.144 ;
     RECT  34.805 80.128 34.859 82.144 ;
     RECT  34.789 102.912 34.859 103.456 ;
     RECT  34.165 0.192 35.106 0.224 ;
     RECT  33.643 75.648 35.173 75.68 ;
     RECT  33.973 77.184 35.173 78.801 ;
     RECT  35.106 0.192 35.179 0.928 ;
     RECT  34.805 97.28 35.219 97.44 ;
     RECT  33.827 88.929 35.221 89.601 ;
     RECT  35.179 0.192 35.243 0.416 ;
     RECT  32.867 51.129 35.253 51.801 ;
     RECT  34.165 86.784 35.253 86.816 ;
     RECT  35.173 75.648 35.265 78.801 ;
     RECT  35.243 0.32 35.267 0.416 ;
     RECT  35.219 97.28 35.267 97.312 ;
     RECT  2.16 29.529 35.269 30.201 ;
     RECT  34.739 61.44 35.307 63.392 ;
     RECT  35.221 88.384 35.307 89.601 ;
     RECT  35.125 5.376 35.315 5.408 ;
     RECT  35.269 28.992 35.317 30.201 ;
     RECT  35.253 50.112 35.363 51.801 ;
     RECT  35.317 28.864 35.386 30.201 ;
     RECT  35.267 0.32 35.555 0.352 ;
     RECT  35.253 86.784 35.637 86.944 ;
     RECT  34.283 72.729 35.682 73.401 ;
     RECT  34.795 94.208 35.699 95.001 ;
     RECT  35.682 72.729 35.701 74.272 ;
     RECT  35.637 85.824 35.71 86.944 ;
     RECT  31.955 56.529 35.749 57.201 ;
     RECT  35.701 72.576 35.755 74.272 ;
     RECT  33.274 99.729 35.829 100.401 ;
     RECT  35.797 97.152 35.883 97.184 ;
     RECT  34.859 80.128 35.891 80.16 ;
     RECT  35.749 56.128 35.893 57.201 ;
     RECT  35.829 99.2 35.939 100.401 ;
     RECT  35.71 86.912 35.987 86.944 ;
     RECT  35.755 72.576 36.035 73.401 ;
     RECT  34.117 53.504 36.267 53.536 ;
     RECT  34.859 82.112 36.277 82.144 ;
     RECT  34.739 83.529 36.277 84.201 ;
     RECT  35.893 55.232 36.323 58.144 ;
     RECT  36.277 82.112 36.331 84.201 ;
     RECT  35.265 75.648 36.659 76.704 ;
     RECT  34.859 103.168 36.997 103.456 ;
     RECT  35.307 61.632 37.091 63.392 ;
     RECT  36.997 103.168 37.099 103.584 ;
     RECT  37.091 61.632 37.301 62.601 ;
     RECT  35.265 78.129 37.429 78.801 ;
     RECT  33.643 91.072 37.477 91.104 ;
     RECT  36.323 56.529 37.523 58.144 ;
     RECT  37.525 70.72 37.557 70.752 ;
     RECT  37.557 69.952 37.611 70.752 ;
     RECT  36.331 82.816 37.667 84.201 ;
     RECT  37.099 103.168 38.051 103.456 ;
     RECT  36.659 75.648 38.197 75.68 ;
     RECT  38.149 86.592 38.197 86.624 ;
     RECT  37.301 61.504 38.243 62.601 ;
     RECT  37.477 90.944 38.243 91.104 ;
     RECT  38.197 86.592 38.251 87.264 ;
     RECT  38.051 103.424 38.291 103.456 ;
     RECT  37.429 77.184 38.581 78.801 ;
     RECT  38.581 77.184 38.645 79.264 ;
     RECT  38.243 90.944 38.819 90.976 ;
     RECT  38.645 77.184 38.827 80.736 ;
     RECT  38.773 82.112 38.842 82.144 ;
     RECT  38.251 87.232 39.251 87.264 ;
     RECT  38.197 75.264 39.33 75.68 ;
     RECT  34.739 67.329 39.349 68.001 ;
     RECT  36.035 72.729 39.349 73.401 ;
     RECT  39.33 75.264 39.349 75.872 ;
     RECT  38.827 77.184 39.395 79.712 ;
     RECT  37.611 69.952 39.403 69.984 ;
     RECT  39.349 72.729 39.403 75.872 ;
     RECT  39.349 66.752 39.443 68.001 ;
     RECT  39.403 72.729 39.875 74.656 ;
     RECT  39.395 78.129 39.923 79.712 ;
     RECT  2.16 2.529 50.49 3.201 ;
     RECT  2.16 7.929 50.49 8.601 ;
     RECT  2.16 13.329 50.49 14.001 ;
     RECT  2.16 18.729 50.49 19.401 ;
     RECT  2.16 24.129 50.49 24.801 ;
     RECT  35.386 29.529 50.49 30.201 ;
     RECT  2.16 34.929 50.49 35.601 ;
     RECT  21.923 40.329 50.49 41.001 ;
     RECT  27.779 45.729 50.49 46.401 ;
     RECT  35.363 51.129 50.49 51.801 ;
     RECT  37.523 56.529 50.49 57.201 ;
     RECT  38.243 61.929 50.49 62.601 ;
     RECT  39.443 67.329 50.49 68.001 ;
     RECT  39.875 72.729 50.49 73.401 ;
     RECT  39.923 78.129 50.49 78.801 ;
     RECT  37.667 83.529 50.49 84.201 ;
     RECT  35.307 88.929 50.49 89.601 ;
     RECT  35.699 94.329 50.49 95.001 ;
     RECT  35.939 99.729 50.49 100.401 ;
    LAYER M7 ;
     RECT  35.2 0.181 35.232 0.427 ;
     RECT  35.136 0.885 35.168 5.419 ;
     RECT  35.328 28.853 35.36 29.035 ;
     RECT  21.696 42.101 21.728 44.331 ;
     RECT  27.392 44.597 27.424 47.339 ;
     RECT  23.296 42.677 23.328 48.939 ;
     RECT  20.544 48.373 20.576 49.643 ;
     RECT  14.592 41.077 14.624 50.997 ;
     RECT  28.544 48.949 28.576 50.997 ;
     RECT  15.936 48.821 15.968 51.051 ;
     RECT  17.344 47.797 17.376 52.021 ;
     RECT  13.824 50.997 14.624 52.469 ;
     RECT  27.84 50.997 28.576 52.715 ;
     RECT  24.384 51.893 24.416 52.981 ;
     RECT  30.784 50.677 30.816 52.981 ;
     RECT  13.12 52.469 14.624 53.035 ;
     RECT  30.784 52.981 31.584 53.035 ;
     RECT  17.344 52.021 18.4 53.355 ;
     RECT  13.824 53.035 14.624 53.483 ;
     RECT  35.264 50.101 35.296 53.493 ;
     RECT  17.344 53.355 17.632 53.547 ;
     RECT  31.552 53.035 31.584 53.739 ;
     RECT  24.384 52.981 25.056 54.069 ;
     RECT  23.744 54.069 25.056 54.123 ;
     RECT  21.056 50.421 21.088 54.187 ;
     RECT  12.992 54.453 13.024 54.837 ;
     RECT  14.592 53.483 14.624 54.837 ;
     RECT  35.264 53.493 36.256 55.275 ;
     RECT  12.992 54.837 14.624 55.595 ;
     RECT  23.744 54.123 23.776 57.323 ;
     RECT  10.24 55.541 10.272 57.387 ;
     RECT  17.6 53.547 17.632 57.397 ;
     RECT  13.568 55.595 14.624 58.101 ;
     RECT  35.264 55.275 35.936 58.155 ;
     RECT  27.904 52.715 28.576 58.219 ;
     RECT  28.544 58.219 28.576 58.731 ;
     RECT  12.8 58.101 14.624 58.859 ;
     RECT  30.464 59.125 30.496 59.701 ;
     RECT  25.216 59.701 25.248 60.277 ;
     RECT  13.568 58.859 14.624 60.341 ;
     RECT  17.024 57.397 17.632 60.651 ;
     RECT  13.568 60.341 15.008 61.045 ;
     RECT  24.448 60.277 25.248 61.173 ;
     RECT  13.568 61.045 15.072 61.227 ;
     RECT  29.248 59.701 30.496 61.237 ;
     RECT  28.544 61.237 30.496 61.291 ;
     RECT  35.264 58.155 35.296 61.483 ;
     RECT  17.344 60.651 17.632 61.547 ;
     RECT  23.936 61.173 25.248 61.547 ;
     RECT  37.312 58.101 37.344 61.547 ;
     RECT  19.008 60.405 19.04 61.611 ;
     RECT  13.568 61.227 15.008 61.867 ;
     RECT  28.544 61.291 28.576 62.763 ;
     RECT  8.64 60.597 8.672 63.029 ;
     RECT  13.568 61.867 14.624 63.147 ;
     RECT  23.936 61.547 25.12 63.147 ;
     RECT  17.344 61.547 17.376 64.309 ;
     RECT  17.344 64.309 17.504 64.363 ;
     RECT  19.328 63.157 19.36 64.939 ;
     RECT  30.464 61.291 30.496 64.949 ;
     RECT  26.816 63.157 26.848 65.067 ;
     RECT  8.64 63.029 9.12 65.579 ;
     RECT  8.64 65.579 8.672 65.899 ;
     RECT  30.464 64.949 30.688 66.037 ;
     RECT  30.464 66.037 30.752 66.091 ;
     RECT  30.656 66.091 30.752 67.179 ;
     RECT  34.176 65.845 34.208 67.243 ;
     RECT  23.936 63.147 23.968 68.277 ;
     RECT  21.376 64.885 21.408 68.459 ;
     RECT  17.472 64.363 17.504 68.597 ;
     RECT  16.576 68.597 17.504 69.611 ;
     RECT  16.576 69.611 16.608 69.995 ;
     RECT  39.36 66.741 39.392 69.995 ;
     RECT  28.608 68.341 28.64 70.251 ;
     RECT  37.568 69.941 37.6 70.763 ;
     RECT  14.592 63.147 14.624 70.773 ;
     RECT  23.936 68.277 24.544 71.851 ;
     RECT  30.656 67.179 30.688 72.117 ;
     RECT  30.656 72.117 31.008 72.565 ;
     RECT  14.592 70.773 15.84 72.619 ;
     RECT  34.24 71.221 34.272 72.619 ;
     RECT  30.656 72.565 31.648 73.525 ;
     RECT  29.568 73.525 31.648 74.997 ;
     RECT  14.592 72.619 14.624 75.189 ;
     RECT  10.048 72.309 10.08 75.307 ;
     RECT  19.2 73.909 19.232 75.307 ;
     RECT  26.88 74.293 26.912 75.371 ;
     RECT  28.8 74.997 31.648 75.371 ;
     RECT  33.6 74.485 33.632 75.691 ;
     RECT  35.712 72.565 35.744 75.701 ;
     RECT  20.864 72.309 20.896 75.819 ;
     RECT  28.8 75.371 31.2 75.883 ;
     RECT  39.36 74.613 39.392 75.883 ;
     RECT  28.8 75.883 31.008 76.011 ;
     RECT  35.2 75.701 35.744 76.715 ;
     RECT  35.2 76.715 35.232 77.227 ;
     RECT  14.592 75.189 15.584 78.955 ;
     RECT  38.592 77.173 38.624 78.955 ;
     RECT  10.304 77.941 10.336 79.157 ;
     RECT  9.152 79.157 10.336 79.659 ;
     RECT  30.656 76.011 31.008 79.851 ;
     RECT  30.976 79.851 31.008 80.181 ;
     RECT  28.8 76.011 28.832 80.309 ;
     RECT  38.656 79.221 38.688 80.693 ;
     RECT  38.656 80.693 38.816 80.747 ;
     RECT  23.936 71.851 23.968 81.205 ;
     RECT  30.976 80.181 31.584 81.515 ;
     RECT  34.816 80.117 34.848 82.155 ;
     RECT  38.784 80.747 38.816 82.155 ;
     RECT  13.056 80.309 13.088 82.347 ;
     RECT  36.288 82.101 36.32 82.859 ;
     RECT  23.936 81.205 24.608 82.987 ;
     RECT  9.152 79.659 9.184 83.179 ;
     RECT  30.976 81.515 31.136 83.243 ;
     RECT  17.408 76.725 17.44 83.253 ;
     RECT  17.408 83.253 18.208 83.307 ;
     RECT  17.536 83.307 18.208 83.381 ;
     RECT  17.536 83.381 18.272 84.331 ;
     RECT  31.104 83.243 31.136 84.853 ;
     RECT  26.048 81.461 26.08 86.581 ;
     RECT  33.6 83.125 33.632 86.581 ;
     RECT  17.536 84.331 18.208 86.699 ;
     RECT  35.648 85.813 35.68 86.773 ;
     RECT  35.264 86.773 35.68 86.955 ;
     RECT  38.208 86.581 38.24 87.275 ;
     RECT  8.256 86.005 8.288 87.851 ;
     RECT  22.784 85.813 22.816 87.851 ;
     RECT  25.92 86.581 26.08 87.851 ;
     RECT  18.176 86.699 18.208 87.989 ;
     RECT  14.592 78.955 14.624 88.373 ;
     RECT  35.264 86.955 35.296 88.427 ;
     RECT  28.16 80.309 28.832 88.757 ;
     RECT  32.768 86.581 33.632 88.811 ;
     RECT  18.112 87.989 18.208 89.845 ;
     RECT  18.112 89.845 18.784 89.899 ;
     RECT  31.104 84.853 31.456 90.101 ;
     RECT  26.048 87.851 26.08 90.549 ;
     RECT  27.392 88.757 28.832 90.549 ;
     RECT  13.632 88.373 14.624 90.667 ;
     RECT  18.176 89.899 18.784 91.563 ;
     RECT  18.176 91.563 18.4 91.627 ;
     RECT  30.464 90.101 31.456 91.819 ;
     RECT  14.592 90.667 14.624 92.149 ;
     RECT  33.6 88.811 33.632 92.203 ;
     RECT  24.128 82.987 24.608 92.853 ;
     RECT  26.048 90.549 28.832 92.853 ;
     RECT  31.104 91.819 31.456 93.749 ;
     RECT  14.208 92.149 14.624 94.123 ;
     RECT  23.872 92.853 24.608 94.251 ;
     RECT  18.368 91.627 18.4 95.157 ;
     RECT  33.664 93.685 33.696 95.157 ;
     RECT  25.984 92.853 28.96 95.221 ;
     RECT  30.4 93.749 31.456 95.221 ;
     RECT  18.24 95.157 18.464 95.339 ;
     RECT  25.984 95.221 31.456 95.413 ;
     RECT  33.664 95.157 34.784 95.413 ;
     RECT  18.432 95.339 18.464 95.915 ;
     RECT  14.208 94.123 14.24 96.171 ;
     RECT  25.984 95.413 34.784 96.299 ;
     RECT  22.464 95.541 22.496 96.821 ;
     RECT  24.128 94.251 24.608 96.821 ;
     RECT  34.752 96.299 34.784 97.141 ;
     RECT  22.464 96.821 24.608 97.781 ;
     RECT  25.984 96.299 32.48 97.781 ;
     RECT  22.464 97.781 32.48 97.963 ;
     RECT  15.552 96.245 15.584 98.411 ;
     RECT  16.512 98.549 16.544 98.805 ;
     RECT  16.512 98.805 17.376 99.243 ;
     RECT  22.464 97.963 32.224 99.243 ;
     RECT  34.752 97.141 35.872 99.243 ;
     RECT  23.296 99.243 32.224 99.499 ;
     RECT  23.552 99.499 32.224 99.627 ;
     RECT  23.744 99.627 32.224 100.469 ;
     RECT  23.744 100.469 33.248 100.587 ;
     RECT  16.768 99.243 17.376 101.173 ;
     RECT  34.752 99.243 34.976 103.029 ;
     RECT  23.808 100.587 33.248 103.157 ;
     RECT  34.624 103.029 34.976 103.157 ;
     RECT  16.512 101.173 17.568 103.275 ;
     RECT  23.808 103.157 35.232 103.285 ;
     RECT  23.808 103.285 36.384 103.349 ;
     RECT  17.024 103.275 17.568 103.403 ;
     RECT  23.808 103.349 37.088 103.467 ;
     RECT  17.344 103.403 17.376 103.595 ;
     RECT  24.448 103.467 24.48 103.595 ;
     RECT  25.92 103.467 26.912 103.595 ;
     RECT  29.76 103.467 29.792 103.595 ;
     RECT  37.056 103.467 37.088 103.595 ;
  END
END ot_qwen_die_station
END LIBRARY
